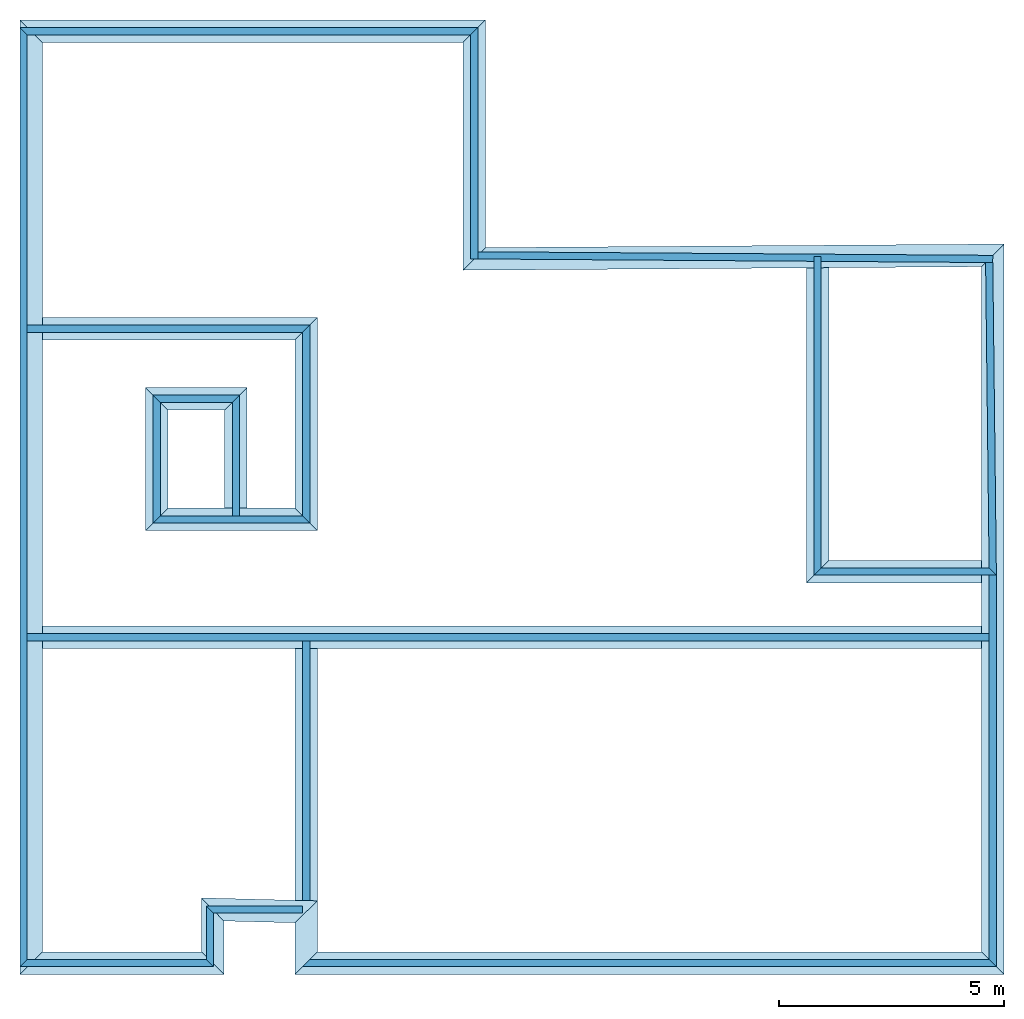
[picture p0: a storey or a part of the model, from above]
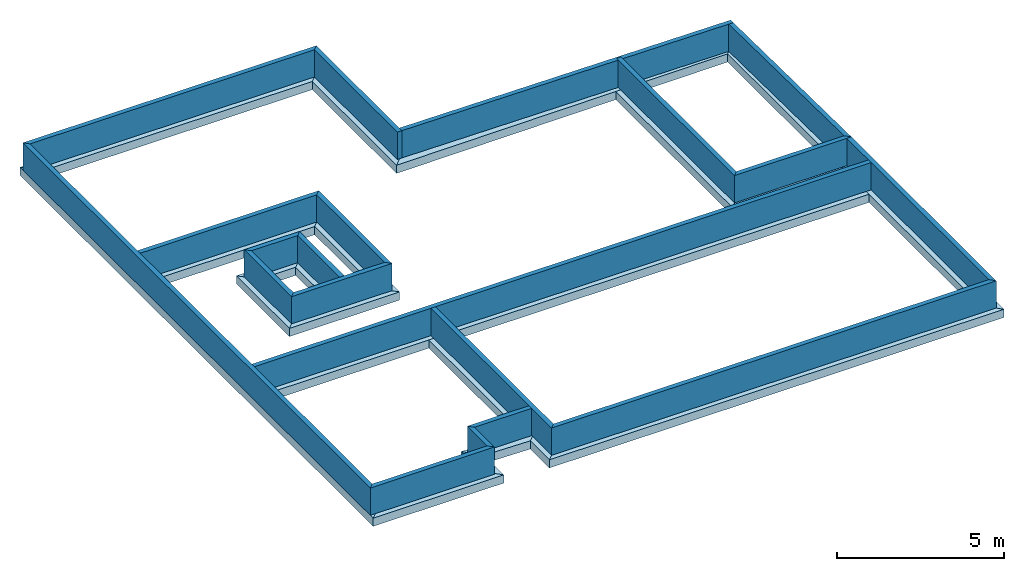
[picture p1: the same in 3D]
Properties of the parts of a building model (IFC2X3), part 1 of 6

# File
Description: ViewDefinition [CoordinationView_V2.0], Option [Drawing Scale: 100.000000], Option [Global Unique Identifiers (GUID): Keep existing], Option [Elements to export: Visible elements (on all stories)], Option [Partial Structure Display: Entire Model], Option [IFC Domain: All], Option [Structural Function: All Elements], Option [Convert Grid elements: On], Option [Convert IFC Annotations and ArchiCAD 2D elements: Off], Option [Convert 2D symbols of Doors and Windows: Off], Option [Explode Composite and Complex Profile elements into parts: Off], Option [Export geometries that Participates in Collision Detection only: Off], Option [Multi-skin complex geometries: Building element parts], Option [Elements in Solid Element Operations: Extruded/revolved], Option [Elements with junctions: Extruded/revolved without junctions], Option [Slabs with slanted edge(s): Extruded], Option [Use legacy geometric methods as in Coordination View 1.0: Off], Option [IFC Site Geometry: As boundary representation (BRep)], Option [Properties To Export: All properties], Option [Space containment: Off], Option [Bounding Box: Off], Option [Geometry to type objects: Off], Option [IFC base quantities (size, area and volume): Off], Option [All ArchiCAD BIM parameters: On], Option [IFC Space boundaries: Off], Option [ArchiCAD Zone Categories as IFC Space classification data: Off]
File name: J:\STATION DOCUMENTS\TB2E COMMI\SESSION 2016\T_Coulaures\GYMN LDV2007PCv5.ifc
Time: 2016-01-12T23:22:32
Author: Architect
Organization: Building Designer Office
Written by: PreProc - EDM 5.0
Made in: IFC file generated by Graphisoft ArchiCAD-64 19.0.0 FRA FULL Windows version (IFC2x3 add-on version: 4006 FRA FULL).
Authorization: The authorising person

# IfcSite, Site
RefLatitude: 48, 52, 0, 0; RefLongitude: 2, 20, 0, 0; RefElevation: 0 m

# IfcBuildingStorey (4)
In: Bâtiment
Name | Elevation (m)
FONDATIONS | -1.5
NIVEAU BAS GYMNASE | 0
NIVEAU HAUT ENTRÉE | 3
PLAN DE MASSE-TOITURE | 6.2

# IfcBeam: Hachure solide 2670559909 60 x 40, Pou-003
In: NIVEAU HAUT ENTRÉE
Material: Hachure solide 2670559909
Pset_BeamCommon - Reference: Hachure solide 2670559909 60 x 40
ArchiCADProperties - ID Elément entier: Pou-003; ID Elément compact: Pou-003; Etage d'implantation: NIVEAU HAUT ENTRÉE; Calque: Constr: Poutraison.Importation IFC; Type: Poutre; Verrouillé: no; Matériau de construction / Composite / Profil / Hachure: Hachure solide 2670559909; Fonction structurelle: Non défini; Position: Non défini; Classification d'élement: Type ArchiCAD; Etat de rénovation: Existant; Afficher sur filtre de rénovation: Tous les filtres appropriés; Type de structure: Basique; Surface supérieure: Menuiserie métal; Surface inférieure: Menuiserie métal; Surface gauche: Menuiserie métal; Surface droite: Menuiserie métal; Surface de fin: Menuiserie métal; Matériau de construction / Profil: Hachure solide 2670559909; Angle d'inclinaison de poutre: 27.0331 deg; Coupe transversale de poutre: Rectangulaire
AC_Pset_RenovationAndPhasing - Renovation Status: Existing
ArchiCADQuantities - Altitude à Zéro du Projet: 0.923819 m; Altitude à étage: -2.07618 m; Hauteur: 0.04 m; Superficie de surface: 1.24902 m2; Volume net: 0.0149235 m3; Superficie: 0.373088 m2; Longueur droite: 6.21814 m; Longueur gauche: 6.21814 m; Surface inférieure: 0.373088 m2; Surface supérieure: 0.373088 m2; Surface côté gauche: 0.248726 m2; Surface côté droit: 0.248726 m2; Volume: 0.0149235 m3; Surface de fin: 0.00538876 m2; Surface des trous: 0 m2; Surface des arêtes de trou: 0 m2; Nombre de trous: 0; Volume des trous: 0 m3; Largeur des trous: 0 m; Hauteur du trou: 0 m; Niveau du trou: 0 m; Largeur: 0.06 m; Décalage: 0 m; Volume conditionnel: 0.0149235 m3

# IfcBeam: Hachure solide 2670559909 700 x 300 (2)
Material: Hachure solide 2670559909
Pset_BeamCommon - Reference: Hachure solide 2670559909 700 x 300
ArchiCADProperties - ID Elément entier: Pou-002; ID Elément compact: Pou-002; Calque: Constr: Poutraison.Importation IFC; Type: Poutre; Verrouillé: no; Matériau de construction / Composite / Profil / Hachure: Hachure solide 2670559909; Fonction structurelle: Non défini; Position: Non défini; Classification d'élement: Type ArchiCAD; Etat de rénovation: Existant; Afficher sur filtre de rénovation: Tous les filtres appropriés; Type de structure: Basique; Surface supérieure: Surface-Stuc blanc; Surface inférieure: Surface-Stuc blanc; Surface gauche: Surface-Stuc blanc; Surface droite: Surface-Stuc blanc; Surface de fin: Surface-Stuc blanc; Matériau de construction / Profil: Hachure solide 2670559909; Angle d'inclinaison de poutre: 0 deg; Coupe transversale de poutre: Rectangulaire
AC_Pset_RenovationAndPhasing - Renovation Status: Existing
ArchiCADQuantities - Hauteur: 0.3 m; Superficie de surface: 35.06 m2; Volume net: 3.6372 m3; Superficie: 12.124 m2; Longueur droite: 17.32 m; Longueur gauche: 17.32 m; Surface inférieure: 12.124 m2; Surface supérieure: 12.124 m2; Surface côté gauche: 5.196 m2; Surface côté droit: 5.196 m2; Volume: 3.6372 m3; Surface de fin: 0.42 m2; Surface des trous: 0 m2; Surface des arêtes de trou: 0 m2; Nombre de trous: 0; Volume des trous: 0 m3; Largeur des trous: 0 m; Hauteur du trou: 0 m; Niveau du trou: 0 m; Largeur: 0.7 m; Décalage: 0 m; Volume conditionnel: 3.6372 m3
Name | In | Etage d'implantation | Altitude à Zéro du Projet (m) | Altitude à étage (m)
Pou-002 | NIVEAU BAS GYMNASE | NIVEAU BAS GYMNASE | 2.75 | 2.75
Pou-002 | PLAN DE MASSE-TOITURE | PLAN DE MASSE-TOITURE | 6.5 | 0.3

# IfcBeam: Pente double 10 (7)
In: NIVEAU BAS GYMNASE
Material: Sans Trame
ArchiCADProperties - ID Elément entier: MOB-0004; ID Elément compact: MOB-0004; Etage d'implantation: NIVEAU BAS GYMNASE; Calque: Cotat: 1/100.Importation IFC; Type: Objet; Verrouillé: no; Nom Elément de Bibliothèque: Poutre 1; Matériau de construction / Composite / Profil / Hachure: Sans Trame; Fonction structurelle: Non défini; Position: Non défini; Classification d'élement: Type ArchiCAD; Etat de rénovation: Existant; Afficher sur filtre de rénovation: Tous les filtres appropriés; Angle de rotation: 90 deg; Surface: Enduit - Blanc nature
AC_Pset_Poutre_1 - Type Hachure: Sans Trame; Stylo Hachure: Fond - Couleur 1; Stylo fond hachure: Fond - Couleur 1; Coût: 0; Type de groupe (FM_Type): Autres; Type de groupe (iFMType): 25; Poids de l'objet: 0; Unité poids de l'objet: kg; Stylo de contour: Eléments 2D - Général; Surface par défaut: Enduit - Blanc nature; Surface 1: Bois-Lambris foncé; Afficher arêtes de contour seulement en 3D: yes
AC_Pset_RenovationAndPhasing - Renovation Status: Existing
ArchiCADQuantities - Altitude à Zéro du Projet: 0 m; Altitude à étage: 0 m; Superficie de surface: 82.9834 m2; Volume net: 1.00818 m3; Superficie: 4.852 m2; Hauteur (Taille en Z): 8.38065 m; Longueur (A): 24.26 m; Volume: 1.00818 m3; Largeur (B): 0.2 m
Name | Nom de Zone | Numéro de Zone
6 x MOB-0004 | Grande Salle de Jeux | 010
MOB-0004

# IfcBuildingElementProxy: Banc public 04 10 (24)
In: NIVEAU BAS GYMNASE
Material: AS_EMPTY
ArchiCADProperties - ID Elément entier: Obj.-025; ID Elément compact: Obj.-025; Etage d'implantation: NIVEAU BAS GYMNASE; Numéro de Zone: 010; Calque: •Arbres.Importation IFC; Type: Objet; Verrouillé: no; Matériau de construction / Composite / Profil / Hachure: AS_EMPTY; Fonction structurelle: Non défini; Position: Non défini; Classification d'élement: Type ArchiCAD; Etat de rénovation: Existant; Afficher sur filtre de rénovation: Tous les filtres appropriés; Surface: Enduit - Blanc nature
AC_Pset_RenovationAndPhasing - Renovation Status: Existing
ArchiCADQuantities - Altitude à Zéro du Projet: 0 m; Altitude à étage: 0 m; Hauteur (Taille en Z): 0.39 m
Name | Nom de Zone | Nom Elément de Bibliothèque | Angle de rotation (deg) | Superficie de surface (m2) | Volume net (m3) = Volume (m3) | Superficie (m2) | Longueur (A) (m) | Largeur (B) (m)
2 x Obj.-025 | Sanit Vest 4 | Elément Modèle 1 | -90 | 3.3602 | 0.0680893 | 0.930667 | 2.32667 | 0.4 | AC_Pset_Elément_Modèle_1 - Type Hachure: Sans Trame; Stylo Hachure: Fond - Couleur 1; Stylo fond hachure: Fond - Couleur 1; Stylo de contour: Eléments 2D - Général; Surface par défaut: Enduit - Blanc nature; Surface 1: Peinture-01; Surface 2: Bois-Pin horizontal; Afficher arêtes de contour seulement en 3D: yes
Obj.-025 | Sanit Vest 4 | Elément Modèle 3 | -90 | 3.2522 | 0.0666973 | 0.882667 | 2.20667 | 0.4 | AC_Pset_Elément_Modèle_3 - Type Hachure: Sans Trame; Stylo Hachure: Fond - Couleur 1; Stylo fond hachure: Fond - Couleur 1; Stylo de contour: Eléments 2D - Général; Surface par défaut: Enduit - Blanc nature; Surface 1: Peinture-01; Surface 2: Bois-Pin horizontal; Afficher arêtes de contour seulement en 3D: yes
3 x Obj.-025 | Sanit Vest 1 | Elément Modèle 4 | 90 | 3.3602 | 0.0680893 | 0.930667 | 2.32667 | 0.4 | AC_Pset_Elément_Modèle_4 - Type Hachure: Sans Trame; Stylo Hachure: Fond - Couleur 1; Stylo fond hachure: Fond - Couleur 1; Stylo de contour: Eléments 2D - Général; Surface par défaut: Enduit - Blanc nature; Surface 1: Peinture-01; Surface 2: Bois-Pin horizontal; Afficher arêtes de contour seulement en 3D: yes
Obj.-025 | Sanit Vest 1 | Elément Modèle 5 | 180 | 4.14599 | 0.0782173 | 1.27991 | 3.19977 | 0.4 | AC_Pset_Elément_Modèle_5 - Type Hachure: Sans Trame; Stylo Hachure: Fond - Couleur 1; Stylo fond hachure: Fond - Couleur 1; Stylo de contour: Eléments 2D - Général; Surface par défaut: Enduit - Blanc nature; Surface 1: Peinture-01; Surface 2: Bois-Pin horizontal; Afficher arêtes de contour seulement en 3D: yes
3 x Obj.-025 | Sanit Vest 2 | Elément Modèle 1 | -90 | 3.3602 | 0.0680893 | 0.930667 | 2.32667 | 0.4 | AC_Pset_Elément_Modèle_1 - Type Hachure: Sans Trame; Stylo Hachure: Fond - Couleur 1; Stylo fond hachure: Fond - Couleur 1; Stylo de contour: Eléments 2D - Général; Surface par défaut: Enduit - Blanc nature; Surface 1: Peinture-01; Surface 2: Bois-Pin horizontal; Afficher arêtes de contour seulement en 3D: yes
Obj.-025 | Sanit Vest 2 | Elément Modèle 6 | 180 | 4.14599 | 0.0782173 | 1.27991 | 3.19977 | 0.4 | AC_Pset_Elément_Modèle_6 - Type Hachure: Sans Trame; Stylo Hachure: Fond - Couleur 1; Stylo fond hachure: Fond - Couleur 1; Stylo de contour: Eléments 2D - Général; Surface par défaut: Enduit - Blanc nature; Surface 1: Peinture-01; Surface 2: Bois-Pin horizontal; Afficher arêtes de contour seulement en 3D: yes
3 x Obj.-025 | Sanit Vest 3 | Elément Modèle 4 | 90 | 3.3602 | 0.0680893 | 0.930667 | 2.32667 | 0.4 | AC_Pset_Elément_Modèle_4 - Type Hachure: Sans Trame; Stylo Hachure: Fond - Couleur 1; Stylo fond hachure: Fond - Couleur 1; Stylo de contour: Eléments 2D - Général; Surface par défaut: Enduit - Blanc nature; Surface 1: Peinture-01; Surface 2: Bois-Pin horizontal; Afficher arêtes de contour seulement en 3D: yes
Obj.-025 | Sanit Vest 3 | Elément Modèle 5 | 180 | 4.14599 | 0.0782173 | 1.27991 | 3.19977 | 0.4 | AC_Pset_Elément_Modèle_5 - Type Hachure: Sans Trame; Stylo Hachure: Fond - Couleur 1; Stylo fond hachure: Fond - Couleur 1; Stylo de contour: Eléments 2D - Général; Surface par défaut: Enduit - Blanc nature; Surface 1: Peinture-01; Surface 2: Bois-Pin horizontal; Afficher arêtes de contour seulement en 3D: yes
2 x Obj.-025 | Sanit Vest 5 | Elément Modèle 7 | 90 | 3.6512 | 0.07184 | 1.06 | 2.65 | 0.4 | AC_Pset_Elément_Modèle_7 - Type Hachure: Sans Trame; Stylo Hachure: Fond - Couleur 1; Stylo fond hachure: Fond - Couleur 1; Stylo de contour: Eléments 2D - Général; Surface par défaut: Enduit - Blanc nature; Surface 1: Peinture-01; Surface 2: Bois-Pin horizontal; Afficher arêtes de contour seulement en 3D: yes
2 x Obj.-025 | Sanit Vest 6 | Elément Modèle 8 | -90 | 3.6512 | 0.07184 | 1.06 | 2.65 | 0.4 | AC_Pset_Elément_Modèle_8 - Type Hachure: Sans Trame; Stylo Hachure: Fond - Couleur 1; Stylo fond hachure: Fond - Couleur 1; Stylo de contour: Eléments 2D - Général; Surface par défaut: Enduit - Blanc nature; Surface 1: Peinture-01; Surface 2: Bois-Pin horizontal; Afficher arêtes de contour seulement en 3D: yes
Obj.-025 | Sanit Vest 5 | Elément Modèle 7 | 180 | 3.6512 | 0.07184 | 1.06 | 2.65 | 0.4 | AC_Pset_Elément_Modèle_7 - Type Hachure: Sans Trame; Stylo Hachure: Fond - Couleur 1; Stylo fond hachure: Fond - Couleur 1; Stylo de contour: Eléments 2D - Général; Surface par défaut: Enduit - Blanc nature; Surface 1: Peinture-01; Surface 2: Bois-Pin horizontal; Afficher arêtes de contour seulement en 3D: yes
Obj.-025 | Sanit Vest 6 | Elément Modèle 7 | 180 | 3.6512 | 0.07184 | 1.06 | 2.65 | 0.4 | AC_Pset_Elément_Modèle_7 - Type Hachure: Sans Trame; Stylo Hachure: Fond - Couleur 1; Stylo fond hachure: Fond - Couleur 1; Stylo de contour: Eléments 2D - Général; Surface par défaut: Enduit - Blanc nature; Surface 1: Peinture-01; Surface 2: Bois-Pin horizontal; Afficher arêtes de contour seulement en 3D: yes
Obj.-025 | Sanit Vest 4 | Elément Modèle 10 | 180 | 4.40922 | 0.0834246 | 1.38394 | 3.32727 | 0.415939 | AC_Pset_Elément_Modèle_10 - Type Hachure: Sans Trame; Stylo Hachure: Fond - Couleur 1; Stylo fond hachure: Fond - Couleur 1; Stylo de contour: Eléments 2D - Général; Surface par défaut: Enduit - Blanc nature; Surface 1: Peinture-01; Surface 2: Bois-Pin horizontal; Afficher arêtes de contour seulement en 3D: yes
Obj.-025 | Sanit Prof H | Elément Modèle 13 | -90 | 1.5602 | 0.0371 | 0.24 | 0.8 | 0.3 | AC_Pset_Elément_Modèle_13 - Type Hachure: Sans Trame; Stylo Hachure: Fond - Couleur 1; Stylo fond hachure: Fond - Couleur 1; Stylo de contour: Eléments 2D - Général; Surface par défaut: Enduit - Blanc nature; Surface 1: Peinture-01; Surface 2: Bois-Pin horizontal; Afficher arêtes de contour seulement en 3D: yes
Obj.-025 | Sanit Prof F | Elément Modèle 14 | 90 | 1.5602 | 0.0371 | 0.24 | 0.8 | 0.3 | AC_Pset_Elément_Modèle_14 - Type Hachure: Sans Trame; Stylo Hachure: Fond - Couleur 1; Stylo fond hachure: Fond - Couleur 1; Stylo de contour: Eléments 2D - Général; Surface par défaut: Enduit - Blanc nature; Surface 1: Peinture-01; Surface 2: Bois-Pin horizontal; Afficher arêtes de contour seulement en 3D: yes

# IfcBuildingElementProxy: Terrain de handball 10, Obj.-016
In: NIVEAU BAS GYMNASE
Material: AS_EMPTY
ArchiCADProperties - ID Elément entier: Obj.-016; ID Elément compact: Obj.-016; Etage d'implantation: NIVEAU BAS GYMNASE; Nom de Zone: Grande Salle de Jeux; Numéro de Zone: 010; Calque: Calque ArchiCAD.Importation IFC; Type: Objet; Verrouillé: no; Nom Elément de Bibliothèque: Elément Modèle 12; Matériau de construction / Composite / Profil / Hachure: AS_EMPTY; Fonction structurelle: Non défini; Position: Non défini; Classification d'élement: Type ArchiCAD; Etat de rénovation: Existant; Afficher sur filtre de rénovation: Tous les filtres appropriés; Angle de rotation: -90 deg; Surface: Enduit - Blanc nature
AC_Pset_Elément_Modèle_12 - Type Hachure: Sans Trame; Stylo Hachure: Fond - Couleur 1; Stylo fond hachure: Fond - Couleur 1; Stylo de contour: Eléments 2D - Général; Surface par défaut: Enduit - Blanc nature; Surface 1: Peinture-21; Surface 2: Surface-Blanc; Surface 3: Peinture-14; Surface 4: Métal-Chaîne clôture; Afficher arêtes de contour seulement en 3D: yes
AC_Pset_RenovationAndPhasing - Renovation Status: Existing
ArchiCADQuantities - Altitude à Zéro du Projet: 0.015 m; Altitude à étage: 0.015 m; Superficie de surface: 1847.91 m2; Volume net: 160.152 m3; Superficie: 836.8 m2; Hauteur (Taille en Z): 2.28 m; Longueur (A): 20 m; Volume: 160.152 m3; Largeur (B): 41.84 m

# IfcBuildingElementProxy: Terrain de volley 10 (3)
In: NIVEAU BAS GYMNASE
Material: AS_EMPTY
ArchiCADProperties - ID Elément entier: Obj.-016; ID Elément compact: Obj.-016; Etage d'implantation: NIVEAU BAS GYMNASE; Nom de Zone: Grande Salle de Jeux; Numéro de Zone: 010; Calque: Calque ArchiCAD.Importation IFC; Type: Objet; Verrouillé: no; Nom Elément de Bibliothèque: Elément Modèle 11; Matériau de construction / Composite / Profil / Hachure: AS_EMPTY; Fonction structurelle: Non défini; Position: Non défini; Classification d'élement: Type ArchiCAD; Etat de rénovation: Existant; Afficher sur filtre de rénovation: Tous les filtres appropriés; Angle de rotation: 0 deg; Surface: Enduit - Blanc nature
AC_Pset_Elément_Modèle_11 - Type Hachure: Sans Trame; Stylo Hachure: Fond - Couleur 1; Stylo fond hachure: Fond - Couleur 1; Stylo de contour: Eléments 2D - Général; Surface par défaut: Enduit - Blanc nature; Surface 1: Peinture-08; Surface 2: Surface-Blanc; Surface 3: Peinture-14; Surface 4: Métal-Inox; Surface 5: Métal-Chaîne clôture; Afficher arêtes de contour seulement en 3D: yes
AC_Pset_RenovationAndPhasing - Renovation Status: Existing
ArchiCADQuantities - Altitude à Zéro du Projet: 0.015 m; Altitude à étage: 0.015 m; Superficie de surface: 349.499 m2; Volume net: 4.18376 m3; Superficie: 203.625 m2; Hauteur (Taille en Z): 3.24167 m; Longueur (A): 10.922 m; Volume: 4.18376 m3; Largeur (B): 18.6436 m

# IfcBuildingElementProxy: Texte_3D_OD (2)
Material: Sans Trame
ArchiCADProperties - ID Elément entier: MOB-0004; ID Elément compact: MOB-0004; Calque: Cotat: 1/100.Importation IFC; Type: Objet; Verrouillé: no; Matériau de construction / Composite / Profil / Hachure: Sans Trame; Fonction structurelle: Non défini; Position: Non défini; Classification d'élement: Type ArchiCAD; Etat de rénovation: Existant; Afficher sur filtre de rénovation: Tous les filtres appropriés; Surface: Enduit - Blanc nature
AC_Pset_RenovationAndPhasing - Renovation Status: Existing
Name | In | Etage d'implantation | Nom Elément de Bibliothèque | Angle de rotation (deg) | Altitude à Zéro du Projet (m) | Altitude à étage (m) | Superficie de surface (m2) | Volume net (m3) = Volume (m3) | Superficie (m2) | Hauteur (Taille en Z) (m) | Longueur (A) (m) | Largeur (B) (m)
MOB-0004 | NIVEAU BAS GYMNASE | NIVEAU BAS GYMNASE | Elément Modèle 9 | 0 | 1.6 | 1.6 | 0.472826 | 0.00186074 | 0.15564 | 0.142176 | 10.376 | 0.015 | AC_Pset_Elément_Modèle_9 - Type Hachure: Sans Trame; Stylo Hachure: Fond - Couleur 1; Stylo fond hachure: Fond - Couleur 1; Stylo de contour: Eléments 2D - Général; Surface par défaut: Enduit - Blanc nature; Surface 1: Métal-Nickel; Afficher arêtes de contour seulement en 3D: yes
MOB-0004 | NIVEAU HAUT ENTRÉE | NIVEAU HAUT ENTRÉE | Elément Modèle 21 | 90 | 7.77443 | 4.77443 | 1.11299 | 0.00467516 | 0.00456994 | 3.02019 | 0.456994 | 0.01 | AC_Pset_Elément_Modèle_21 - Type Hachure: Sans Trame; Stylo Hachure: Fond - Couleur 1; Stylo fond hachure: Fond - Couleur 1; Stylo de contour: Eléments 2D - Général; Surface par défaut: Enduit - Blanc nature; Surface 1: Métal-Nickel; Afficher arêtes de contour seulement en 3D: yes

# IfcBuildingElementProxy: gypse_droit_lisses_rempl, MOB-0003
In: NIVEAU HAUT ENTRÉE
Material: Sans Trame
ArchiCADProperties - ID Elément entier: MOB-0003; ID Elément compact: MOB-0003; Etage d'implantation: NIVEAU HAUT ENTRÉE; Calque: Cotat: 1/100.Importation IFC; Type: Objet; Verrouillé: no; Nom Elément de Bibliothèque: Elément Modèle 16; Matériau de construction / Composite / Profil / Hachure: Sans Trame; Fonction structurelle: Non défini; Position: Non défini; Classification d'élement: Type ArchiCAD; Etat de rénovation: Existant; Afficher sur filtre de rénovation: Tous les filtres appropriés; Angle de rotation: 0 deg; Surface: Enduit - Blanc nature
AC_Pset_Elément_Modèle_16 - Type Hachure: Sans Trame; Stylo Hachure: Fond - Couleur 1; Stylo fond hachure: Fond - Couleur 1; Stylo de contour: Eléments 2D - Général; Surface par défaut: Enduit - Blanc nature; Surface 1: RAL 7035 Gris clair; Surface 2: gypse_gasket; Surface 3: Vitrage-Clair; Afficher arêtes de contour seulement en 3D: yes
AC_Pset_RenovationAndPhasing - Renovation Status: Existing
ArchiCADQuantities - Altitude à Zéro du Projet: 3.01 m; Altitude à étage: 0.01 m; Superficie de surface: 2.75879 m2; Volume net: 0.0103288 m3; Superficie: 0.317148 m2; Hauteur (Taille en Z): 1.1511 m; Longueur (A): 1.38766 m; Volume: 0.0103288 m3; Largeur (B): 0.228548 m

# IfcBuildingElementProxy: gypse_ramp_lisses_tigeinox, MOB-0003
In: NIVEAU HAUT ENTRÉE
Material: Sans Trame
ArchiCADProperties - ID Elément entier: MOB-0003; ID Elément compact: MOB-0003; Etage d'implantation: NIVEAU HAUT ENTRÉE; Nom de Zone: Salle de Sport de Combat; Numéro de Zone: 006; Calque: Cotat: 1/100.Importation IFC; Type: Objet; Verrouillé: no; Nom Elément de Bibliothèque: Elément Modèle 20; Matériau de construction / Composite / Profil / Hachure: Sans Trame; Fonction structurelle: Non défini; Position: Non défini; Classification d'élement: Type ArchiCAD; Etat de rénovation: Existant; Afficher sur filtre de rénovation: Tous les filtres appropriés; Angle de rotation: 180 deg; Surface: Enduit - Blanc nature
AC_Pset_Elément_Modèle_20 - Type Hachure: Sans Trame; Stylo Hachure: Fond - Couleur 1; Stylo fond hachure: Fond - Couleur 1; Stylo de contour: Eléments 2D - Général; Surface par défaut: Enduit - Blanc nature; Surface 1: RAL 7035 Gris clair; Afficher arêtes de contour seulement en 3D: yes
AC_Pset_RenovationAndPhasing - Renovation Status: Existing
ArchiCADQuantities - Altitude à Zéro du Projet: 3 m; Altitude à étage: 0 m; Superficie de surface: 3.69626 m2; Volume net: 0.0146362 m3; Superficie: 0.4284 m2; Hauteur (Taille en Z): 0.999371 m; Longueur (A): 3.57 m; Volume: 0.0146362 m3; Largeur (B): 0.12 m

# IfcColumn: Béton 2199952591 300 x 700, Pilier-001
In: NIVEAU BAS GYMNASE
Material: Béton 2199952591
Pset_ColumnCommon - Reference: Béton 2199952591 300 x 700
ArchiCADProperties - ID Elément entier: Pilier-001; ID Elément compact: Pilier-001; Etage d'implantation: NIVEAU BAS GYMNASE; Calque: Constr: Poteaux.Importation IFC; Type: Poteau; Verrouillé: no; Matériau de construction / Composite / Profil / Hachure: Béton 2199952591; Fonction structurelle: Non défini; Position: Non défini; Classification d'élement: Type ArchiCAD; Etat de rénovation: Existant; Afficher sur filtre de rénovation: Tous les filtres appropriés; Type de structure: Basique; Matériau de construction / Profil: Béton 2199952591; Surface: Surface-Stuc blanc; Angle d'inclinaison de poteau: 90 deg; Coupe transversale de poteau: Rectangulaire; Etage supérieur lié: Non lié
AC_Pset_RenovationAndPhasing - Renovation Status: Existing
ArchiCADQuantities - Altitude à Zéro du Projet: 2.45 m; Altitude à étage: 2.45 m; Hauteur: 4.05 m; Superficie de surface: 8.1 m2; Volume net: 0.8505 m3; Superficie: 0.21 m2; Surface nette de l'âme (sans haut/bas): 8.1 m2; Surface du revêtement: 0 m2; Volume net de l'Ame: 0.8505 m3; Volume net du revêtement: 0 m3; Dimensions Ame: 0.7 m; 2ème dimension âme: 0.3 m; Hauteur minimum du Poteau: 4.05 m; Hauteur maximum Poteau: 4.05 m; Périmètre du Poteau: 2 m; Surface du Poteau: 0.21 m2; Volume du Poteau: 0.8505 m3; Volume brut du Poteau: 0.8505 m3; Surface brute de l'âme (sans haut/bas): 8.1 m2; Volume brut de l'Ame: 0.8505 m3; Surface brute du revêtement (sans haut/bas): 0 m2; Volume brut du revêtement: 0 m3; Surface nette du haut de l'Ame: 0.21 m2; Surface nette du bas de l'Ame: 0.21 m2; Surface nette du haut du Revêtement: 0 m2; Surface nette du bas du Revêtement: 0 m2; Surface brute du haut (ou bas) de l'âme: 0.21 m2; Surface brute du haut (ou bas) du revêtement: 0 m2; Décalage étage d'implantation: 2.45 m; Décalage supérieur: -0.3 m

# IfcColumn: Empty Fill 1720032642 30 x 40 (6)
In: NIVEAU HAUT ENTRÉE
Material: Empty Fill 1720032642
Pset_ColumnCommon - Reference: Empty Fill 1720032642 30 x 40
ArchiCADProperties - ID Elément entier: Pilier-002; ID Elément compact: Pilier-002; Etage d'implantation: NIVEAU HAUT ENTRÉE; Calque: Constr: Poteaux.Importation IFC; Type: Poteau; Verrouillé: no; Matériau de construction / Composite / Profil / Hachure: Empty Fill 1720032642; Fonction structurelle: Non défini; Position: Non défini; Classification d'élement: Type ArchiCAD; Etat de rénovation: Existant; Afficher sur filtre de rénovation: Tous les filtres appropriés; Type de structure: Basique; Matériau de construction / Profil: Empty Fill 1720032642; Surface: Agave 5 OD; Angle d'inclinaison de poteau: 90 deg; Coupe transversale de poteau: Rectangulaire; Etage supérieur lié: Non lié
AC_Pset_RenovationAndPhasing - Renovation Status: Existing
ArchiCADQuantities - Altitude à Zéro du Projet: 2.75 m; Altitude à étage: -0.25 m; Hauteur: 3.45 m; Superficie de surface: 0.483 m2; Volume net: 0.00414 m3; Superficie: 0.0012 m2; Surface nette de l'âme (sans haut/bas): 0.483 m2; Surface du revêtement: 0 m2; Volume net de l'Ame: 0.00414 m3; Volume net du revêtement: 0 m3; Dimensions Ame: 0.04 m; 2ème dimension âme: 0.03 m; Hauteur minimum du Poteau: 3.45 m; Hauteur maximum Poteau: 3.45 m; Périmètre du Poteau: 0.14 m; Surface du Poteau: 0.0012 m2; Volume du Poteau: 0.00414 m3; Volume brut du Poteau: 0.00414 m3; Surface brute de l'âme (sans haut/bas): 0.483 m2; Volume brut de l'Ame: 0.00414 m3; Surface brute du revêtement (sans haut/bas): 0 m2; Volume brut du revêtement: 0 m3; Surface nette du haut de l'Ame: 0.0012 m2; Surface nette du bas de l'Ame: 0.0012 m2; Surface nette du haut du Revêtement: 0 m2; Surface nette du bas du Revêtement: 0 m2; Surface brute du haut (ou bas) de l'âme: 0.0012 m2; Surface brute du haut (ou bas) du revêtement: 0 m2; Décalage étage d'implantation: -0.25 m; Décalage supérieur: -0.3 m

# IfcColumn: Hachure solide (2) 1078492233 250 x 900, Pilier-001
In: NIVEAU BAS GYMNASE
Material: Hachure solide (2) 1078492233
Pset_ColumnCommon - Reference: Hachure solide (2) 1078492233 250 x 900
ArchiCADProperties - ID Elément entier: Pilier-001; ID Elément compact: Pilier-001; Etage d'implantation: NIVEAU BAS GYMNASE; Calque: Constr: Poteaux.Importation IFC; Type: Poteau; Verrouillé: no; Matériau de construction / Composite / Profil / Hachure: Hachure solide (2) 1078492233; Fonction structurelle: Non défini; Position: Non défini; Classification d'élement: Type ArchiCAD; Etat de rénovation: Existant; Afficher sur filtre de rénovation: Tous les filtres appropriés; Type de structure: Basique; Matériau de construction / Profil: Hachure solide (2) 1078492233; Surface: Pierre-Granite rouge; Angle d'inclinaison de poteau: 90 deg; Coupe transversale de poteau: Rectangulaire; Etage supérieur lié: Non lié
AC_Pset_RenovationAndPhasing - Renovation Status: Existing
ArchiCADQuantities - Altitude à Zéro du Projet: 2.75 m; Altitude à étage: 2.75 m; Hauteur: 6.63885 m; Superficie de surface: 15.2694 m2; Volume net: 1.49374 m3; Superficie: 0.225 m2; Surface nette de l'âme (sans haut/bas): 15.2694 m2; Surface du revêtement: 0 m2; Volume net de l'Ame: 1.49374 m3; Volume net du revêtement: 0 m3; Dimensions Ame: 0.9 m; 2ème dimension âme: 0.25 m; Hauteur minimum du Poteau: 6.63885 m; Hauteur maximum Poteau: 6.63885 m; Périmètre du Poteau: 2.3 m; Surface du Poteau: 0.225 m2; Volume du Poteau: 1.49374 m3; Volume brut du Poteau: 1.49374 m3; Surface brute de l'âme (sans haut/bas): 15.2694 m2; Volume brut de l'Ame: 1.49374 m3; Surface brute du revêtement (sans haut/bas): 0 m2; Volume brut du revêtement: 0 m3; Surface nette du haut de l'Ame: 0.225 m2; Surface nette du bas de l'Ame: 0.225 m2; Surface nette du haut du Revêtement: 0 m2; Surface nette du bas du Revêtement: 0 m2; Surface brute du haut (ou bas) de l'âme: 0.225 m2; Surface brute du haut (ou bas) du revêtement: 0 m2; Décalage étage d'implantation: 2.75 m; Décalage supérieur: -0.3 m

# IfcColumn: Hachure solide (2) 2212012751 300 x 870, Pilier-001
In: NIVEAU BAS GYMNASE
Material: Hachure solide (2) 2212012751
Pset_ColumnCommon - Reference: Hachure solide (2) 2212012751 300 x 870
ArchiCADProperties - ID Elément entier: Pilier-001; ID Elément compact: Pilier-001; Etage d'implantation: NIVEAU BAS GYMNASE; Calque: Constr: Poteaux.Importation IFC; Type: Poteau; Verrouillé: no; Matériau de construction / Composite / Profil / Hachure: Hachure solide (2) 2212012751; Fonction structurelle: Non défini; Position: Non défini; Classification d'élement: Type ArchiCAD; Etat de rénovation: Existant; Afficher sur filtre de rénovation: Tous les filtres appropriés; Type de structure: Basique; Matériau de construction / Profil: Hachure solide (2) 2212012751; Surface: Surface-Stuc blanc; Angle d'inclinaison de poteau: 90 deg; Coupe transversale de poteau: Rectangulaire; Etage supérieur lié: Non lié
AC_Pset_RenovationAndPhasing - Renovation Status: Existing
ArchiCADQuantities - Altitude à Zéro du Projet: 2.75 m; Altitude à étage: 2.75 m; Hauteur: 4.55 m; Superficie de surface: 10.647 m2; Volume net: 1.18755 m3; Superficie: 0.261 m2; Surface nette de l'âme (sans haut/bas): 10.647 m2; Surface du revêtement: 0 m2; Volume net de l'Ame: 1.18755 m3; Volume net du revêtement: 0 m3; Dimensions Ame: 0.87 m; 2ème dimension âme: 0.3 m; Hauteur minimum du Poteau: 4.55 m; Hauteur maximum Poteau: 4.55 m; Périmètre du Poteau: 2.34 m; Surface du Poteau: 0.261 m2; Volume du Poteau: 1.18755 m3; Volume brut du Poteau: 1.18755 m3; Surface brute de l'âme (sans haut/bas): 10.647 m2; Volume brut de l'Ame: 1.18755 m3; Surface brute du revêtement (sans haut/bas): 0 m2; Volume brut du revêtement: 0 m3; Surface nette du haut de l'Ame: 0.261 m2; Surface nette du bas de l'Ame: 0.261 m2; Surface nette du haut du Revêtement: 0 m2; Surface nette du bas du Revêtement: 0 m2; Surface brute du haut (ou bas) de l'âme: 0.261 m2; Surface brute du haut (ou bas) du revêtement: 0 m2; Décalage étage d'implantation: 2.75 m; Décalage supérieur: -0.3 m

# IfcColumn: Hachure solide (2) 2212012855 300 x 2400, Pilier-001
In: NIVEAU BAS GYMNASE
Material: Hachure solide (2) 2212012855
Pset_ColumnCommon - Reference: Hachure solide (2) 2212012855 300 x 2400
ArchiCADProperties - ID Elément entier: Pilier-001; ID Elément compact: Pilier-001; Etage d'implantation: NIVEAU BAS GYMNASE; Calque: Constr: Poteaux.Importation IFC; Type: Poteau; Verrouillé: no; Matériau de construction / Composite / Profil / Hachure: Hachure solide (2) 2212012855; Fonction structurelle: Non défini; Position: Non défini; Classification d'élement: Type ArchiCAD; Etat de rénovation: Existant; Afficher sur filtre de rénovation: Tous les filtres appropriés; Type de structure: Basique; Matériau de construction / Profil: Hachure solide (2) 2212012855; Surface: Surface-Stuc blanc; Angle d'inclinaison de poteau: 90 deg; Coupe transversale de poteau: Rectangulaire; Etage supérieur lié: Non lié
AC_Pset_RenovationAndPhasing - Renovation Status: Existing
ArchiCADQuantities - Altitude à Zéro du Projet: 2.85 m; Altitude à étage: 2.85 m; Hauteur: 4.45 m; Superficie de surface: 24.03 m2; Volume net: 3.204 m3; Superficie: 0.72 m2; Surface nette de l'âme (sans haut/bas): 24.03 m2; Surface du revêtement: 0 m2; Volume net de l'Ame: 3.204 m3; Volume net du revêtement: 0 m3; Dimensions Ame: 2.4 m; 2ème dimension âme: 0.3 m; Hauteur minimum du Poteau: 4.45 m; Hauteur maximum Poteau: 4.45 m; Périmètre du Poteau: 5.4 m; Surface du Poteau: 0.72 m2; Volume du Poteau: 3.204 m3; Volume brut du Poteau: 3.204 m3; Surface brute de l'âme (sans haut/bas): 24.03 m2; Volume brut de l'Ame: 3.204 m3; Surface brute du revêtement (sans haut/bas): 0 m2; Volume brut du revêtement: 0 m3; Surface nette du haut de l'Ame: 0.72 m2; Surface nette du bas de l'Ame: 0.72 m2; Surface nette du haut du Revêtement: 0 m2; Surface nette du bas du Revêtement: 0 m2; Surface brute du haut (ou bas) de l'âme: 0.72 m2; Surface brute du haut (ou bas) du revêtement: 0 m2; Décalage étage d'implantation: 2.85 m; Décalage supérieur: -0.3 m

# IfcCurtainWall: Mur rid droit 10 (3)
In: NIVEAU HAUT ENTRÉE
Material: Sans Trame
ArchiCADProperties - ID Elément entier: MOB-0002; ID Elément compact: MOB-0002; Etage d'implantation: NIVEAU HAUT ENTRÉE; Calque: Cotat: 1/100.Importation IFC; Type: Objet; Verrouillé: no; Matériau de construction / Composite / Profil / Hachure: Sans Trame; Fonction structurelle: Non défini; Position: Non défini; Classification d'élement: Type ArchiCAD; Etat de rénovation: Existant; Afficher sur filtre de rénovation: Tous les filtres appropriés; Surface: Enduit - Blanc nature
AC_Pset_RenovationAndPhasing - Renovation Status: Existing
ArchiCADQuantities - Altitude à Zéro du Projet: 2.6 m; Altitude à étage: -0.4 m; Hauteur (Taille en Z): 6.3 m; Largeur (B): 0.16 m
Name | Nom Elément de Bibliothèque | Angle de rotation (deg) | Superficie de surface (m2) | Volume net (m3) = Volume (m3) | Superficie (m2) | Longueur (A) (m)
MOB-0002 | Mur Rideau 1 | 0 | 877.641 | 45.4102 | 7.20797 | 45.0498 | AC_Pset_Mur_Rideau_1 - Type Hachure: Sans Trame; Stylo Hachure: Fond - Couleur 1; Stylo fond hachure: Fond - Couleur 1; Coût: 0; Type de groupe (FM_Type): Autres; Type de groupe (iFMType): 25; Poids de l'objet: 0; Unité poids de l'objet: kg; Stylo de contour: Eléments 2D - Général; Surface par défaut: Enduit - Blanc nature; Surface 1: Carrelage Piscine; Surface 2: RAL 6021 Vert pâle2; Afficher arêtes de contour seulement en 3D: yes
MOB-0002 | Mur Rideau 2 | 90 | 373.556 | 19.2153 | 3.05005 | 19.0628 | AC_Pset_Mur_Rideau_2 - Type Hachure: Sans Trame; Stylo Hachure: Fond - Couleur 1; Stylo fond hachure: Fond - Couleur 1; Coût: 0; Type de groupe (FM_Type): Autres; Type de groupe (iFMType): 25; Poids de l'objet: 0; Unité poids de l'objet: kg; Stylo de contour: Eléments 2D - Général; Surface par défaut: Enduit - Blanc nature; Surface 1: Carrelage Piscine; Surface 2: RAL 6021 Vert pâle2; Afficher arêtes de contour seulement en 3D: yes
MOB-0002 | Mur Rideau 3 | -90 | 481.332 | 24.8069 | 3.9376 | 24.61 | AC_Pset_Mur_Rideau_3 - Type Hachure: Sans Trame; Stylo Hachure: Fond - Couleur 1; Stylo fond hachure: Fond - Couleur 1; Coût: 0; Type de groupe (FM_Type): Autres; Type de groupe (iFMType): 25; Poids de l'objet: 0; Unité poids de l'objet: kg; Stylo de contour: Eléments 2D - Général; Surface par défaut: Enduit - Blanc nature; Surface 1: Carrelage Piscine; Surface 2: RAL 6021 Vert pâle2; Afficher arêtes de contour seulement en 3D: yes

# IfcDiscreteAccessory: Par soleil droit 10, MOB-0009
In: NIVEAU HAUT ENTRÉE
Material: Sans Trame
ArchiCADProperties - ID Elément entier: MOB-0009; ID Elément compact: MOB-0009; Etage d'implantation: NIVEAU HAUT ENTRÉE; Calque: Cotat: 1/100.Importation IFC; Type: Objet; Verrouillé: no; Nom Elément de Bibliothèque: Accessoire partiel 1; Matériau de construction / Composite / Profil / Hachure: Sans Trame; Fonction structurelle: Non défini; Position: Non défini; Classification d'élement: Type ArchiCAD; Etat de rénovation: Existant; Afficher sur filtre de rénovation: Tous les filtres appropriés; Angle de rotation: 0 deg; Surface: Enduit - Blanc nature
AC_Pset_Accessoire_partiel_1 - Type Hachure: Sans Trame; Stylo Hachure: Fond - Couleur 1; Stylo fond hachure: Fond - Couleur 1; Stylo de contour: Eléments 2D - Général; Surface par défaut: Enduit - Blanc nature; Surface 1: AS Laque argenté; Surface 2: Aluminium; Afficher arêtes de contour seulement en 3D: yes
AC_Pset_RenovationAndPhasing - Renovation Status: Existing
ArchiCADQuantities - Altitude à Zéro du Projet: 3.3564 m; Altitude à étage: 0.356398 m; Superficie de surface: 20.0849 m2; Volume net: 0.249482 m3; Superficie: 15.5174 m2; Hauteur (Taille en Z): 0.15 m; Longueur (A): 1.9583 m; Volume: 0.249482 m3; Largeur (B): 7.92391 m

# IfcDoor: P1 Devanture 1 10, Por-020
In: NIVEAU BAS GYMNASE
Type - OperationType: SINGLE_SWING_LEFT; ParameterTakesPrecedence: no; Sizeable: no
Type - Propriétés Doublure Porte - LiningDepth: 0.08 m; LiningThickness: 0.04 m
Type - Propriétés Panneau Porte - Panneau1 - PanelDepth: 0.04 m; PanelOperation: SWINGING; PanelPosition: MIDDLE
OverallHeight: 2.1 m; OverallWidth: 0.9 m; Material: Sans Trame
Pset_DoorCommon - ThermalTransmittance: 0; GlazingAreaFraction: 0
ArchiCADProperties - ID Elément entier: Por-020; ID Elément compact: Por-020; Etage d'implantation: NIVEAU BAS GYMNASE; Nom de Zone: Hall & Circulation; Numéro de Zone: 010; Calque: Murs Ext: Périphériques.Importation IFC; Type: Porte; Verrouillé: no; Nom Elément de Bibliothèque: Porte (Mur) 16; Matériau de construction / Composite / Profil / Hachure: Menuis1; Fonction structurelle: Non défini; Position: Non défini; Classification d'élement: Type ArchiCAD; Etat de rénovation: Existant; Afficher sur filtre de rénovation: Tous les filtres appropriés; De Zone: Hall & Circulation; Orientation: D; De la Zone numéro: 010; Structure mur: •GYMN 10+10 0232896968; Taille L x H nominale: 0,90x2,10; Taille L x H x E nominale: 0,90x2,10x0,20
AC_Pset_Porte_(Mur)_16 - Contours Mur (0-Sans,1-Tout,2-Côté,3-Longueur): 1; Point ch.0-Non,1-2D,2-3D,3-Tous: 3; Points chauds auto. en 3D: yes; Trou reprend surface latérale de mur: no; Division de surface de trou courbée: no; Stylo du symbole: Ouvertures - Général; Angle ouverture en 2D: 90 deg; Stylo de contour: Eléments 2D - Général; Type Hachure: Sans Trame; Stylo Hachure: Fond - Couleur 1; Stylo fond hachure: Fond - Couleur 1; Stylo cadre: Eléments 2D - Général; Stylo panneaux: Eléments 2D - Général; Angle ouverture en 3D: 0 deg; Afficher arêtes de contour seulement en 3D: yes; Surface par défaut: Enduit - Blanc nature; Surface 1: Métal-Aluminium; Surface 2: Vitrage-Clair; Surface de battant: Bois - Pin granuleux horizontal; Surface de cadre: Bois - Pin granuleux horizontal; Opération IFC (ifc_optype): 1
AC_Pset_RenovationAndPhasing - Renovation Status: Existing
ArchiCADQuantities - Altitude à Zéro du Projet: 0 m; Altitude à étage: 0 m; Hauteur: 2.1 m; Superficie de surface: 5.53608 m2; Volume net: 0.0489668 m3; Largeur: 0.9 m; Epaisseur: 0.1 m; Hauteur nominale seuil: 0 m; Hauteur seuil côté ébrasure: 0 m; Hauteur seuil côté opposé ébrasure: 0 m; Hauteur nominale linteau: 2.1 m; Hauteur linteau côté ébrasure: 2.1 m; Hauteur linteau côté opposé ébrasure: 2.1 m; Largeur ouverture côté ébrasure: 0.9 m; Largeur ouverture côté opposé ébrasure: 0.9 m; Hauteur ouverture côté ébrasure: 2.1 m; Hauteur ouverture côté opposé ébrasure: 2.1 m; Surface ouverture côté ébrasure: 1.89 m2; Surface ouverture côté opposé ébrasure: 1.89 m2; Largeur nominale de l'ouverture côté ébrasure: 0.9 m; Largeur nominale de l'ouverture côté opposée ébrasure: 0.9 m; Hauteur nominale de l'ouverture côté ébrasure: 2.1 m; Hauteur nominale de l'ouverture côté opposée ébrasure: 2.1 m; Surface nominale de l'ouverture P/F côté ébrasure: 1.89 m2; Surface nominale de l'ouverture P/F côté opposé ébrasure: 1.89 m2; Volume ouverture: 0.0489668 m3; Surface nominale ouverture P/F: 1.89 m2; Volume nominal ouverture: 0.378 m3; Valeur Appui ou Linteau: 0 m; Epaisseur de Mur: 0.2 m
AC_Equantity_Porte_(Mur)_16 - Largeur: 1 m; Hauteur: 2.1 m; Hauteur appui à étage actuel: 0 m; Niveau inférieur: 1 m; Niveau supérieur: 0 m; Largeur cadre: 0.05 m; Epaisseur cadre: 0.1 m; Epaisseur panneaux: 0.04 m; Dépass.ouverture à droite: 0 m; Dépass.ouverture supérieur: 0 m; Dépass.ouverture inférieur: 0 m; Dépass.ouverture gauche: 0 m

# IfcDoor: P2 Devanture 2 10 (2)
Type - OperationType: DOUBLE_DOOR_SINGLE_SWING; ParameterTakesPrecedence: no; Sizeable: no
Type - Propriétés Doublure Porte - LiningDepth: 0.08 m; LiningThickness: 0.04 m
Type - Propriétés Panneau Porte - Panneau1 - PanelDepth: 0.04 m; PanelOperation: SWINGING; PanelWidth: 0.5; PanelPosition: LEFT
Type - Propriétés Panneau Porte - Panneau2 - PanelDepth: 0.04 m; PanelOperation: SWINGING; PanelWidth: 0.5; PanelPosition: RIGHT
OverallWidth: 1.9 m; Material: Sans Trame
Pset_DoorCommon - ThermalTransmittance: 0; GlazingAreaFraction: 0
ArchiCADProperties - Type: Porte; Verrouillé: no; Matériau de construction / Composite / Profil / Hachure: Menuis1; Fonction structurelle: Non défini; Position: Non défini; Classification d'élement: Type ArchiCAD; Etat de rénovation: Existant; Afficher sur filtre de rénovation: Tous les filtres appropriés; Orientation: G
AC_Pset_RenovationAndPhasing - Renovation Status: Existing
ArchiCADQuantities - Largeur: 1.9 m; Epaisseur: 0.1 m; Largeur ouverture côté ébrasure: 1.9 m; Largeur ouverture côté opposé ébrasure: 1.9 m; Largeur nominale de l'ouverture côté ébrasure: 1.9 m; Largeur nominale de l'ouverture côté opposée ébrasure: 1.9 m
Name | In | OverallHeight (m) = ArchiCADQuantities, Hauteur (m) = Hauteur ouverture côté ébrasure (m) = Hauteur ouverture côté opposé ébrasure (m) = Hauteur nominale de l'ouverture côté ébrasure (m) = Hauteur nominale de l'ouverture côté opposée ébrasure (m) | ID Elément entier = ID Elément compact | Etage d'implantation | Calque | Nom Elément de Bibliothèque | Structure mur | Taille L x H nominale | Taille L x H x E nominale | Altitude à Zéro du Projet (m) | Altitude à étage (m) | Superficie de surface (m2) | Volume net (m3) = Volume ouverture (m3) | Hauteur nominale seuil (m) = Valeur Appui ou Linteau (m) | Hauteur seuil côté ébrasure (m) = Hauteur seuil côté opposé ébrasure (m) | Hauteur nominale linteau (m) = Hauteur linteau côté ébrasure (m) = Hauteur linteau côté opposé ébrasure (m) | Surface ouverture côté ébrasure (m2) = Surface ouverture côté opposé ébrasure (m2) = Surface nominale de l'ouverture P/F côté ébrasure (m2) = Surface nominale de l'ouverture P/F côté opposé ébrasure (m2) = Surface nominale ouverture P/F (m2) | Volume nominal ouverture (m3) | Epaisseur de Mur (m)
Por-013 | NIVEAU BAS GYMNASE | 2.4 | Por-013 | NIVEAU BAS GYMNASE | Murs Ext: Périphériques.Importation IFC | Porte (Mur) 11 | •GYMN 10+10 0232896968 | 1,90x2,40 | 1,90x2,40x0,20 | 0.02 | 0.02 | 11.9869 | 0.1123 | 0.02 | 0.02 | 2.42 | 4.56 | 0.912 | 0.2 | AC_Pset_Porte_(Mur)_11 - Contours Mur (0-Sans,1-Tout,2-Côté,3-Longueur): 1; Point ch.0-Non,1-2D,2-3D,3-Tous: 3; Points chauds auto. en 3D: yes; Trou reprend surface latérale de mur: no; Division de surface de trou courbée: no; Stylo du symbole: Ouvertures - Général; Angle ouverture en 2D: 90 deg; Stylo de contour: Eléments 2D - Général; Type Hachure: Sans Trame; Stylo Hachure: Fond - Couleur 1; Stylo fond hachure: Fond - Couleur 1; Stylo cadre: Eléments 2D - Général; Stylo panneaux: Eléments 2D - Général; Angle ouverture en 3D: 0 deg; Afficher arêtes de contour seulement en 3D: yes; Surface par défaut: Enduit - Blanc nature; Surface 1: Métal-Aluminium; Surface 2: Métal-Zinc; Surface 3: Vitrage-Bleu; Surface 4: Métal-Fer; Surface de battant: Bois - Pin granuleux horizontal; Surface de cadre: Bois - Pin granuleux horizontal; Opération IFC (ifc_optype): 2; AC_Equantity_Porte_(Mur)_11 - Largeur: 1 m; Hauteur: 2.1 m; Hauteur appui à étage actuel: 0 m; Niveau inférieur: 1 m; Niveau supérieur: 0 m; Largeur cadre: 0.05 m; Epaisseur cadre: 0.1 m; Epaisseur panneaux: 0.04 m; Dépass.ouverture à droite: 0 m; Dépass.ouverture supérieur: 0 m; Dépass.ouverture inférieur: 0 m; Dépass.ouverture gauche: 0 m
Por-014 | NIVEAU HAUT ENTRÉE | 2.95373 | Por-014 | NIVEAU HAUT ENTRÉE | 0.Importation IFC | Porte (Mur) 42 | •GYMN 16+10 | 1,90x2,95 | 1,90x2,95x0,26 | 2.97 | -0.03 | 14.476 | 0.13007 | -5e-12 | 0 | 2.95373 | 5.61209 | 1.45914 | 0.26 | ArchiCADProperties - Nom de Zone: Hall d'Entrée; Numéro de Zone: 010; De Zone: Hall d'Entrée; De la Zone numéro: 010; AC_Pset_Porte_(Mur)_42 - Contours Mur (0-Sans,1-Tout,2-Côté,3-Longueur): 1; Point ch.0-Non,1-2D,2-3D,3-Tous: 3; Points chauds auto. en 3D: yes; Trou reprend surface latérale de mur: no; Division de surface de trou courbée: no; Stylo du symbole: Ouvertures - Général; Angle ouverture en 2D: 90 deg; Stylo de contour: Eléments 2D - Général; Type Hachure: Sans Trame; Stylo Hachure: Fond - Couleur 1; Stylo fond hachure: Fond - Couleur 1; Stylo cadre: Eléments 2D - Général; Stylo panneaux: Eléments 2D - Général; Angle ouverture en 3D: 0 deg; Afficher arêtes de contour seulement en 3D: yes; Surface par défaut: Enduit - Blanc nature; Surface 1: Métal-Aluminium; Surface 2: Vitrage-Clair; Surface 3: Métal-Zinc; Surface 4: Métal-Fer; Surface de battant: Bois - Pin granuleux horizontal; Surface de cadre: Bois - Pin granuleux horizontal; Opération IFC (ifc_optype): 2; AC_Equantity_Porte_(Mur)_42 - Largeur: 1 m; Hauteur: 2.1 m; Hauteur appui à étage actuel: 2.97 m; Niveau inférieur: 1 m; Niveau supérieur: 0 m; Largeur cadre: 0.05 m; Epaisseur cadre: 0.1 m; Epaisseur panneaux: 0.04 m; Dépass.ouverture à droite: 0 m; Dépass.ouverture supérieur: 0 m; Dépass.ouverture inférieur: 0 m; Dépass.ouverture gauche: 0 m

# IfcDoor: P2 Devanture 3 10 (2)
In: NIVEAU BAS GYMNASE
Type - OperationType: DOUBLE_DOOR_SINGLE_SWING; ParameterTakesPrecedence: no; Sizeable: no
Type - Propriétés Doublure Porte - LiningDepth: 0.08 m; LiningThickness: 0.04 m
Type - Propriétés Panneau Porte - Panneau1 - PanelDepth: 0.04 m; PanelOperation: SWINGING; PanelWidth: 0.5; PanelPosition: LEFT
Type - Propriétés Panneau Porte - Panneau2 - PanelDepth: 0.04 m; PanelOperation: SWINGING; PanelWidth: 0.5; PanelPosition: RIGHT
OverallHeight: 2.32 m; OverallWidth: 3.9397 m; Material: Sans Trame
Pset_DoorCommon - ThermalTransmittance: 0; GlazingAreaFraction: 0
ArchiCADProperties - ID Elément entier: Por-022; ID Elément compact: Por-022; Etage d'implantation: NIVEAU BAS GYMNASE; Calque: Murs Ext: Périphériques.Importation IFC; Type: Porte; Verrouillé: no; Matériau de construction / Composite / Profil / Hachure: Menuis1; Fonction structurelle: Non défini; Position: Non défini; Classification d'élement: Type ArchiCAD; Etat de rénovation: Existant; Afficher sur filtre de rénovation: Tous les filtres appropriés; Orientation: G; Structure mur: Acier 2556372607; Taille L x H nominale: 3,94x2,32; Taille L x H x E nominale: 3,94x2,32x0,10
AC_Pset_RenovationAndPhasing - Renovation Status: Existing
ArchiCADQuantities - Altitude à Zéro du Projet: 0.1 m; Altitude à étage: 0.1 m; Hauteur: 2.32 m; Largeur: 3.9397 m; Epaisseur: 0.1 m; Hauteur nominale seuil: 0.1 m; Hauteur seuil côté ébrasure: 0.1 m; Hauteur seuil côté opposé ébrasure: 0.1 m; Hauteur nominale linteau: 2.42 m; Hauteur linteau côté ébrasure: 2.42 m; Hauteur linteau côté opposé ébrasure: 2.42 m; Largeur ouverture côté ébrasure: 3.9397 m; Largeur ouverture côté opposé ébrasure: 3.8397 m; Hauteur ouverture côté ébrasure: 2.32 m; Hauteur ouverture côté opposé ébrasure: 2.32 m; Surface ouverture côté ébrasure: 9.1401 m2; Surface ouverture côté opposé ébrasure: 8.9081 m2; Largeur nominale de l'ouverture côté ébrasure: 3.9397 m; Largeur nominale de l'ouverture côté opposée ébrasure: 3.9397 m; Hauteur nominale de l'ouverture côté ébrasure: 2.32 m; Hauteur nominale de l'ouverture côté opposée ébrasure: 2.32 m; Surface nominale de l'ouverture P/F côté ébrasure: 9.1401 m2; Surface nominale de l'ouverture P/F côté opposé ébrasure: 9.1401 m2; Surface nominale ouverture P/F: 9.1401 m2; Volume nominal ouverture: 0.91401 m3; Valeur Appui ou Linteau: 0.1 m; Epaisseur de Mur: 0.1 m
Name | Nom Elément de Bibliothèque | Superficie de surface (m2) | Volume net (m3) = Volume ouverture (m3)
Por-022 | Porte (Mur) 17 | 22.3576 | 0.200278 | AC_Pset_Porte_(Mur)_17 - Contours Mur (0-Sans,1-Tout,2-Côté,3-Longueur): 1; Point ch.0-Non,1-2D,2-3D,3-Tous: 3; Points chauds auto. en 3D: yes; Trou reprend surface latérale de mur: no; Division de surface de trou courbée: no; Stylo du symbole: Ouvertures - Général; Angle ouverture en 2D: 90 deg; Stylo de contour: Eléments 2D - Général; Type Hachure: Sans Trame; Stylo Hachure: Fond - Couleur 1; Stylo fond hachure: Fond - Couleur 1; Stylo cadre: Eléments 2D - Général; Stylo panneaux: Eléments 2D - Général; Angle ouverture en 3D: 0 deg; Afficher arêtes de contour seulement en 3D: yes; Surface par défaut: Enduit - Blanc nature; Surface 1: Métal-Aluminium; Surface 2: Vitrage-Clair; Surface 3: Métal-Zinc; Surface 4: Métal-Fer; Surface de battant: Bois - Pin granuleux horizontal; Surface de cadre: Bois - Pin granuleux horizontal; Opération IFC (ifc_optype): 2; AC_Equantity_Porte_(Mur)_17 - Largeur: 1 m; Hauteur: 2.1 m; Hauteur appui à étage actuel: 0 m; Niveau inférieur: 1 m; Niveau supérieur: 0 m; Largeur cadre: 0.05 m; Epaisseur cadre: 0.1 m; Epaisseur panneaux: 0.04 m; Dépass.ouverture à droite: 0 m; Dépass.ouverture supérieur: 0 m; Dépass.ouverture inférieur: 0 m; Dépass.ouverture gauche: 0 m
Por-022 | Porte (Mur) 33 | 22.3548 | 0.197296 | AC_Pset_Porte_(Mur)_33 - Contours Mur (0-Sans,1-Tout,2-Côté,3-Longueur): 1; Point ch.0-Non,1-2D,2-3D,3-Tous: 3; Points chauds auto. en 3D: yes; Trou reprend surface latérale de mur: no; Division de surface de trou courbée: no; Stylo du symbole: Ouvertures - Général; Angle ouverture en 2D: 90 deg; Stylo de contour: Eléments 2D - Général; Type Hachure: Sans Trame; Stylo Hachure: Fond - Couleur 1; Stylo fond hachure: Fond - Couleur 1; Stylo cadre: Eléments 2D - Général; Stylo panneaux: Eléments 2D - Général; Angle ouverture en 3D: 0 deg; Afficher arêtes de contour seulement en 3D: yes; Surface par défaut: Enduit - Blanc nature; Surface 1: Métal-Aluminium; Surface 2: Vitrage-Clair; Surface 3: Métal-Zinc; Surface 4: Métal-Fer; Surface de battant: Bois - Pin granuleux horizontal; Surface de cadre: Bois - Pin granuleux horizontal; Opération IFC (ifc_optype): 2; AC_Equantity_Porte_(Mur)_33 - Largeur: 1 m; Hauteur: 2.1 m; Hauteur appui à étage actuel: 0 m; Niveau inférieur: 1 m; Niveau supérieur: 0 m; Largeur cadre: 0.05 m; Epaisseur cadre: 0.1 m; Epaisseur panneaux: 0.04 m; Dépass.ouverture à droite: 0 m; Dépass.ouverture supérieur: 0 m; Dépass.ouverture inférieur: 0 m; Dépass.ouverture gauche: 0 m

# IfcDoor: P_métallique 10, Por-021
In: NIVEAU BAS GYMNASE
Type - OperationType: SINGLE_SWING_LEFT; ParameterTakesPrecedence: no; Sizeable: no
Type - Propriétés Doublure Porte - LiningDepth: 0.1 m; LiningThickness: 0.032 m; ThresholdThickness: 0.012 m
Type - Propriétés Panneau Porte - Panneau1 - PanelDepth: 0.04 m; PanelOperation: SWINGING; PanelPosition: MIDDLE
OverallHeight: 2.1 m; OverallWidth: 0.9 m; Material: Sans Trame
Pset_DoorCommon - ThermalTransmittance: 0; GlazingAreaFraction: 0
ArchiCADProperties - ID Elément entier: Por-021; ID Elément compact: Por-021; Etage d'implantation: NIVEAU BAS GYMNASE; Nom de Zone: Chaufferie; Numéro de Zone: 010; Calque: Murs Ext: Périphériques.Importation IFC; Type: Porte; Verrouillé: no; Nom Elément de Bibliothèque: Porte (Mur) 9; Matériau de construction / Composite / Profil / Hachure: Menuis1; Fonction structurelle: Non défini; Position: Non défini; Classification d'élement: Type ArchiCAD; Etat de rénovation: Existant; Afficher sur filtre de rénovation: Tous les filtres appropriés; De Zone: Chaufferie; Orientation: D; De la Zone numéro: 010; Structure mur: Hachure solide* 1842511997; Taille L x H nominale: 0,90x2,10; Taille L x H x E nominale: 0,90x2,10x0,16
AC_Pset_Porte_(Mur)_9 - Contours Mur (0-Sans,1-Tout,2-Côté,3-Longueur): 1; Point ch.0-Non,1-2D,2-3D,3-Tous: 3; Points chauds auto. en 3D: yes; Trou reprend surface latérale de mur: no; Division de surface de trou courbée: no; Stylo du symbole: Ouvertures - Général; Angle ouverture en 2D: 90 deg; Stylo de contour: Eléments 2D - Général; Type Hachure: Sans Trame; Stylo Hachure: Fond - Couleur 1; Stylo fond hachure: Fond - Couleur 1; Stylo cadre: Eléments 2D - Général; Stylo panneaux: Eléments 2D - Général; Angle ouverture en 3D: 0 deg; Afficher arêtes de contour seulement en 3D: yes; Surface par défaut: Enduit - Blanc nature; Surface 1: Métal-Fer; Surface 2: Métal-Aluminium; Surface 3: Agave 2 OD; Surface de battant: Bois - Pin granuleux horizontal; Surface de cadre: Bois - Pin granuleux horizontal; Opération IFC (ifc_optype): 1
AC_Pset_RenovationAndPhasing - Renovation Status: Existing
ArchiCADQuantities - Altitude à Zéro du Projet: 0 m; Altitude à étage: 0 m; Hauteur: 2.1 m; Superficie de surface: 5.21659 m2; Volume net: 0.0853402 m3; Largeur: 0.9 m; Epaisseur: 0.1 m; Hauteur nominale seuil: 0 m; Hauteur seuil côté ébrasure: 0 m; Hauteur seuil côté opposé ébrasure: 0 m; Hauteur nominale linteau: 2.1 m; Hauteur linteau côté ébrasure: 2.1 m; Hauteur linteau côté opposé ébrasure: 2.1 m; Largeur ouverture côté ébrasure: 0.9 m; Largeur ouverture côté opposé ébrasure: 0.9 m; Hauteur ouverture côté ébrasure: 2.1 m; Hauteur ouverture côté opposé ébrasure: 2.1 m; Surface ouverture côté ébrasure: 1.89 m2; Surface ouverture côté opposé ébrasure: 1.89 m2; Largeur nominale de l'ouverture côté ébrasure: 0.9 m; Largeur nominale de l'ouverture côté opposée ébrasure: 0.9 m; Hauteur nominale de l'ouverture côté ébrasure: 2.1 m; Hauteur nominale de l'ouverture côté opposée ébrasure: 2.1 m; Surface nominale de l'ouverture P/F côté ébrasure: 1.89 m2; Surface nominale de l'ouverture P/F côté opposé ébrasure: 1.89 m2; Volume ouverture: 0.0853402 m3; Surface nominale ouverture P/F: 1.89 m2; Volume nominal ouverture: 0.3024 m3; Valeur Appui ou Linteau: 0 m; Epaisseur de Mur: 0.16 m
AC_Equantity_Porte_(Mur)_9 - Largeur: 1 m; Hauteur: 2.1 m; Hauteur appui à étage actuel: 0 m; Niveau inférieur: 1 m; Niveau supérieur: 0 m; Largeur cadre: 0.05 m; Epaisseur cadre: 0.1 m; Epaisseur panneaux: 0.04 m; Dépass.ouverture à droite: 0 m; Dépass.ouverture supérieur: 0 m; Dépass.ouverture inférieur: 0 m; Dépass.ouverture gauche: 0 m

# IfcDoor: Porte int 1v (55)
Type - ParameterTakesPrecedence: no; Sizeable: no
Material: Sans Trame
ArchiCADProperties - Type: Porte; Verrouillé: no; Matériau de construction / Composite / Profil / Hachure: Menuis1; Fonction structurelle: Non défini; Position: Non défini; Classification d'élement: Type ArchiCAD; Etat de rénovation: Existant; Afficher sur filtre de rénovation: Tous les filtres appropriés; Orientation: G
AC_Pset_RenovationAndPhasing - Renovation Status: Existing
ArchiCADQuantities - Epaisseur: 0.1 m; Hauteur seuil côté ébrasure: 0 m; Hauteur seuil côté opposé ébrasure: 0 m
Name | In | OverallHeight (m) = ArchiCADQuantities, Hauteur (m) = Hauteur nominale de l'ouverture côté ébrasure (m) = Hauteur nominale de l'ouverture côté opposée ébrasure (m) | OverallWidth (m) = ArchiCADQuantities, Largeur (m) = Largeur ouverture côté ébrasure (m) = Largeur ouverture côté opposé ébrasure (m) = Largeur nominale de l'ouverture côté ébrasure (m) = Largeur nominale de l'ouverture côté opposée ébrasure (m) | ID Elément entier = ID Elément compact | Etage d'implantation | Calque | Nom Elément de Bibliothèque | Structure mur | Taille L x H nominale | Taille L x H x E nominale | Altitude à Zéro du Projet (m) | Altitude à étage (m) = Hauteur nominale seuil (m) = Valeur Appui ou Linteau (m) | Superficie de surface (m2) | Volume net (m3) = Volume ouverture (m3) | Hauteur nominale linteau (m) = Hauteur linteau côté ébrasure (m) = Hauteur linteau côté opposé ébrasure (m) = Hauteur ouverture côté ébrasure (m) = Hauteur ouverture côté opposé ébrasure (m) | Surface ouverture côté ébrasure (m2) = Surface ouverture côté opposé ébrasure (m2) | Surface nominale de l'ouverture P/F côté ébrasure (m2) = Surface nominale de l'ouverture P/F côté opposé ébrasure (m2) = Surface nominale ouverture P/F (m2) | Volume nominal ouverture (m3) | Epaisseur de Mur (m)
Por-021 | NIVEAU BAS GYMNASE | 2.055 | 0.79 | Por-021 | NIVEAU BAS GYMNASE | Murs Ext: Périphériques.Importation IFC | Porte (Mur) 1 | Hachure solide* 3962059836 | 0,79x2,05 | 0,79x2,05x0,07 | -0.01 | -0.01 | 4.32837 | 0.0730983 | 2.045 | 1.61555 | 1.62345 | 0.113642 | 0.07 | AC_Pset_Porte_(Mur)_1 - Contours Mur (0-Sans,1-Tout,2-Côté,3-Longueur): 1; Point ch.0-Non,1-2D,2-3D,3-Tous: 3; Points chauds auto. en 3D: yes; Trou reprend surface latérale de mur: no; Division de surface de trou courbée: no; Stylo du symbole: Ouvertures - Général; Angle ouverture en 2D: 90 deg; Stylo de contour: Eléments 2D - Général; Type Hachure: Sans Trame; Stylo Hachure: Fond - Couleur 1; Stylo fond hachure: Fond - Couleur 1; Stylo cadre: Eléments 2D - Général; Stylo panneaux: Eléments 2D - Général; Angle ouverture en 3D: 0 deg; Afficher arêtes de contour seulement en 3D: yes; Surface par défaut: Enduit - Blanc nature; Surface 1: •MENUIS H CHASSIS; Surface 2: Peinture-16; Surface 3: Métal-Fer; Surface 4: Métal-Nickel; Surface de battant: Bois - Pin granuleux horizontal; Surface de cadre: Bois - Pin granuleux horizontal; Opération IFC (ifc_optype): 0; AC_Equantity_Porte_(Mur)_1 - Largeur: 1 m; Hauteur: 2.1 m; Hauteur appui à étage actuel: 0 m; Niveau inférieur: 1 m; Niveau supérieur: 0 m; Largeur cadre: 0.05 m; Epaisseur cadre: 0.1 m; Epaisseur panneaux: 0.04 m; Dépass.ouverture à droite: 0 m; Dépass.ouverture supérieur: 0 m; Dépass.ouverture inférieur: 0 m; Dépass.ouverture gauche: 0 m
Por-018 | NIVEAU BAS GYMNASE | 2.055 | 0.79 | Por-018 | NIVEAU BAS GYMNASE | Murs Ext: Périphériques.Importation IFC | Porte (Mur) 2 | Hachure solide* 3962059836 | 0,79x2,05 | 0,79x2,05x0,10 | -0.01 | -0.01 | 4.61967 | 0.0795918 | 2.045 | 1.61555 | 1.62345 | 0.162345 | 0.1 | AC_Pset_Porte_(Mur)_2 - Contours Mur (0-Sans,1-Tout,2-Côté,3-Longueur): 1; Point ch.0-Non,1-2D,2-3D,3-Tous: 3; Points chauds auto. en 3D: yes; Trou reprend surface latérale de mur: no; Division de surface de trou courbée: no; Stylo du symbole: Ouvertures - Général; Angle ouverture en 2D: 90 deg; Stylo de contour: Eléments 2D - Général; Type Hachure: Sans Trame; Stylo Hachure: Fond - Couleur 1; Stylo fond hachure: Fond - Couleur 1; Stylo cadre: Eléments 2D - Général; Stylo panneaux: Eléments 2D - Général; Angle ouverture en 3D: 0 deg; Afficher arêtes de contour seulement en 3D: yes; Surface par défaut: Enduit - Blanc nature; Surface 1: •MENUIS H CHASSIS; Surface 2: Peinture-16; Surface 3: Métal-Fer; Surface 4: Métal-Nickel; Surface de battant: Bois - Pin granuleux horizontal; Surface de cadre: Bois - Pin granuleux horizontal; Opération IFC (ifc_optype): 0; AC_Equantity_Porte_(Mur)_2 - Largeur: 1 m; Hauteur: 2.1 m; Hauteur appui à étage actuel: 0 m; Niveau inférieur: 1 m; Niveau supérieur: 0 m; Largeur cadre: 0.05 m; Epaisseur cadre: 0.1 m; Epaisseur panneaux: 0.04 m; Dépass.ouverture à droite: 0 m; Dépass.ouverture supérieur: 0 m; Dépass.ouverture inférieur: 0 m; Dépass.ouverture gauche: 0 m
Por-017 | NIVEAU BAS GYMNASE | 2.555 | 0.89 | Por-017 | NIVEAU BAS GYMNASE | Murs Ext: Périphériques.Importation IFC | Porte (Mur) 3 | Hachure solide* 3962059836 | 0,89x2,55 | 0,89x2,55x0,10 | -0.01 | -0.01 | 6.45477 | 0.0997413 | 2.545 | 2.26505 | 2.27395 | 0.227395 | 0.1 | ArchiCADProperties - Nom de Zone: Bureau Prof; Numéro de Zone: 006; De Zone: Sanit Prof F; De la Zone numéro: 010; AC_Pset_Porte_(Mur)_3 - Contours Mur (0-Sans,1-Tout,2-Côté,3-Longueur): 1; Point ch.0-Non,1-2D,2-3D,3-Tous: 3; Points chauds auto. en 3D: yes; Trou reprend surface latérale de mur: no; Division de surface de trou courbée: no; Stylo du symbole: Ouvertures - Général; Angle ouverture en 2D: 90 deg; Stylo de contour: Eléments 2D - Général; Type Hachure: Sans Trame; Stylo Hachure: Fond - Couleur 1; Stylo fond hachure: Fond - Couleur 1; Stylo cadre: Eléments 2D - Général; Stylo panneaux: Eléments 2D - Général; Angle ouverture en 3D: 0 deg; Afficher arêtes de contour seulement en 3D: yes; Surface par défaut: Enduit - Blanc nature; Surface 1: •MENUIS H CHASSIS; Surface 2: Vitrage-Clair; Surface 3: Peinture-16; Surface 4: Métal-Fer; Surface 5: Métal-Nickel; Surface de battant: Bois - Pin granuleux horizontal; Surface de cadre: Bois - Pin granuleux horizontal; Opération IFC (ifc_optype): 0; AC_Equantity_Porte_(Mur)_3 - Largeur: 1 m; Hauteur: 2.1 m; Hauteur appui à étage actuel: 0 m; Niveau inférieur: 1 m; Niveau supérieur: 0 m; Largeur cadre: 0.05 m; Epaisseur cadre: 0.1 m; Epaisseur panneaux: 0.04 m; Dépass.ouverture à droite: 0 m; Dépass.ouverture supérieur: 0 m; Dépass.ouverture inférieur: 0 m; Dépass.ouverture gauche: 0 m
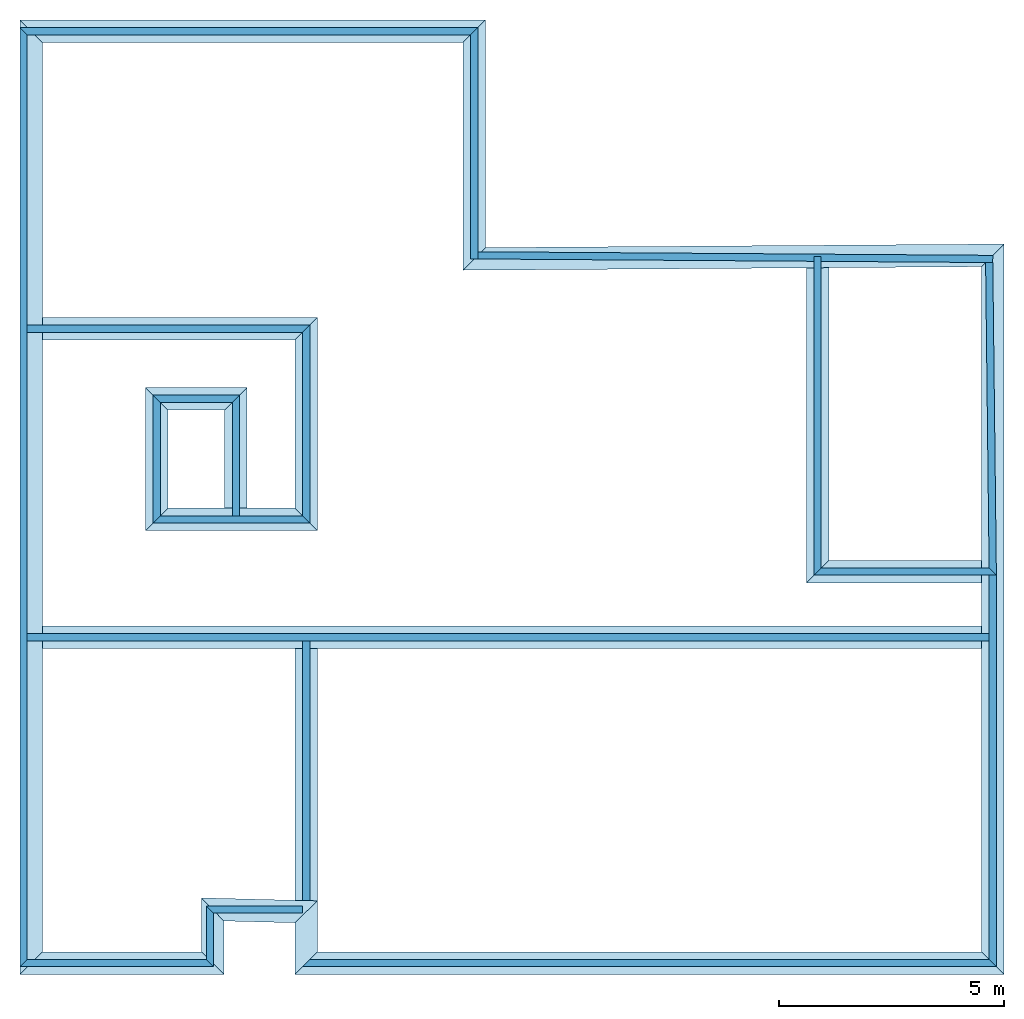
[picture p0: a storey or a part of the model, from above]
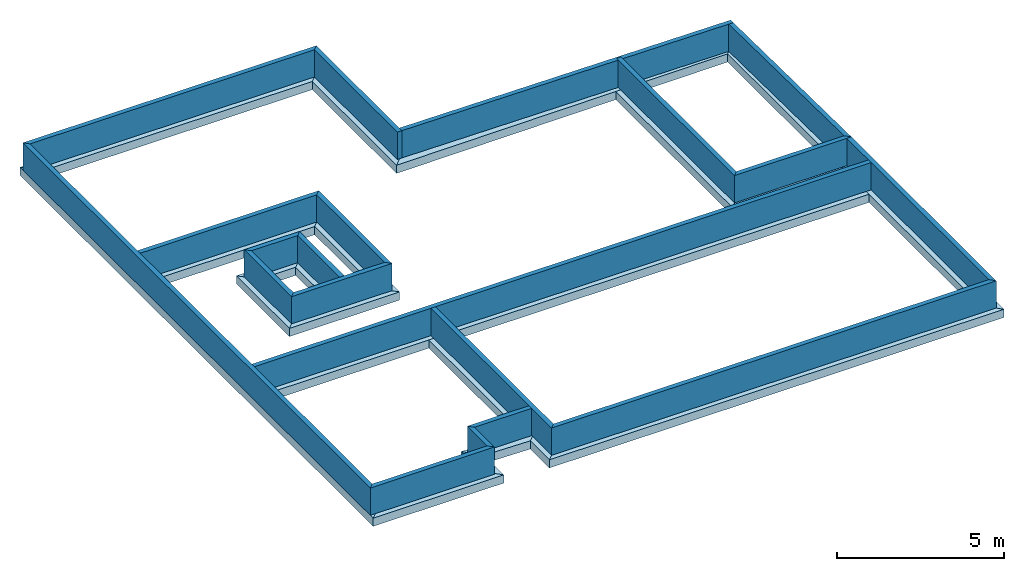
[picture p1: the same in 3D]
Properties of the parts of a building model (IFC2X3), part 2 of 6

# IfcDoor: Porte int 1v (55)
Name | In | OverallHeight (m) = ArchiCADQuantities, Hauteur (m) = Hauteur nominale de l'ouverture côté ébrasure (m) = Hauteur nominale de l'ouverture côté opposée ébrasure (m) | OverallWidth (m) = ArchiCADQuantities, Largeur (m) = Largeur ouverture côté ébrasure (m) = Largeur ouverture côté opposé ébrasure (m) = Largeur nominale de l'ouverture côté ébrasure (m) = Largeur nominale de l'ouverture côté opposée ébrasure (m) | ID Elément entier = ID Elément compact | Etage d'implantation | Calque | Nom Elément de Bibliothèque | Structure mur | Taille L x H nominale | Taille L x H x E nominale | Altitude à Zéro du Projet (m) | Altitude à étage (m) = Hauteur nominale seuil (m) = Valeur Appui ou Linteau (m) | Superficie de surface (m2) | Volume net (m3) = Volume ouverture (m3) | Hauteur nominale linteau (m) = Hauteur linteau côté ébrasure (m) = Hauteur linteau côté opposé ébrasure (m) = Hauteur ouverture côté ébrasure (m) = Hauteur ouverture côté opposé ébrasure (m) | Surface ouverture côté ébrasure (m2) = Surface ouverture côté opposé ébrasure (m2) | Surface nominale de l'ouverture P/F côté ébrasure (m2) = Surface nominale de l'ouverture P/F côté opposé ébrasure (m2) = Surface nominale ouverture P/F (m2) | Volume nominal ouverture (m3) | Epaisseur de Mur (m)
Por-018 | NIVEAU BAS GYMNASE | 2.555 | 0.89 | Por-018 | NIVEAU BAS GYMNASE | Murs Ext: Périphériques.Importation IFC | Porte (Mur) 4 | Hachure solide* 3962059836 | 0,89x2,55 | 0,89x2,55x0,10 | -0.01 | -0.01 | 6.45477 | 0.0997413 | 2.545 | 2.26505 | 2.27395 | 0.227395 | 0.1 | ArchiCADProperties - Nom de Zone: Bureau Prof; Numéro de Zone: 006; De Zone: Sanit Prof H; De la Zone numéro: 010; AC_Pset_Porte_(Mur)_4 - Contours Mur (0-Sans,1-Tout,2-Côté,3-Longueur): 1; Point ch.0-Non,1-2D,2-3D,3-Tous: 3; Points chauds auto. en 3D: yes; Trou reprend surface latérale de mur: no; Division de surface de trou courbée: no; Stylo du symbole: Ouvertures - Général; Angle ouverture en 2D: 90 deg; Stylo de contour: Eléments 2D - Général; Type Hachure: Sans Trame; Stylo Hachure: Fond - Couleur 1; Stylo fond hachure: Fond - Couleur 1; Stylo cadre: Eléments 2D - Général; Stylo panneaux: Eléments 2D - Général; Angle ouverture en 3D: 0 deg; Afficher arêtes de contour seulement en 3D: yes; Surface par défaut: Enduit - Blanc nature; Surface 1: •MENUIS H CHASSIS; Surface 2: Vitrage-Clair; Surface 3: Peinture-16; Surface 4: Métal-Fer; Surface 5: Métal-Nickel; Surface de battant: Bois - Pin granuleux horizontal; Surface de cadre: Bois - Pin granuleux horizontal; Opération IFC (ifc_optype): 0; AC_Equantity_Porte_(Mur)_4 - Largeur: 1 m; Hauteur: 2.1 m; Hauteur appui à étage actuel: 0 m; Niveau inférieur: 1 m; Niveau supérieur: 0 m; Largeur cadre: 0.05 m; Epaisseur cadre: 0.1 m; Epaisseur panneaux: 0.04 m; Dépass.ouverture à droite: 0 m; Dépass.ouverture supérieur: 0 m; Dépass.ouverture inférieur: 0 m; Dépass.ouverture gauche: 0 m
Por-018 | NIVEAU BAS GYMNASE | 2.055 | 0.79 | Por-018 | NIVEAU BAS GYMNASE | Murs Ext: Périphériques.Importation IFC | Porte (Mur) 5 | Hachure solide* 3962059836 | 0,79x2,05 | 0,79x2,05x0,10 | -0.01 | -0.01 | 4.61967 | 0.0795918 | 2.045 | 1.61555 | 1.62345 | 0.162345 | 0.1 | AC_Pset_Porte_(Mur)_5 - Contours Mur (0-Sans,1-Tout,2-Côté,3-Longueur): 1; Point ch.0-Non,1-2D,2-3D,3-Tous: 3; Points chauds auto. en 3D: yes; Trou reprend surface latérale de mur: no; Division de surface de trou courbée: no; Stylo du symbole: Ouvertures - Général; Angle ouverture en 2D: 90 deg; Stylo de contour: Eléments 2D - Général; Type Hachure: Sans Trame; Stylo Hachure: Fond - Couleur 1; Stylo fond hachure: Fond - Couleur 1; Stylo cadre: Eléments 2D - Général; Stylo panneaux: Eléments 2D - Général; Angle ouverture en 3D: 0 deg; Afficher arêtes de contour seulement en 3D: yes; Surface par défaut: Enduit - Blanc nature; Surface 1: •MENUIS H CHASSIS; Surface 2: Peinture-16; Surface 3: Métal-Fer; Surface 4: Métal-Nickel; Surface de battant: Bois - Pin granuleux horizontal; Surface de cadre: Bois - Pin granuleux horizontal; Opération IFC (ifc_optype): 0; AC_Equantity_Porte_(Mur)_5 - Largeur: 1 m; Hauteur: 2.1 m; Hauteur appui à étage actuel: 0 m; Niveau inférieur: 1 m; Niveau supérieur: 0 m; Largeur cadre: 0.05 m; Epaisseur cadre: 0.1 m; Epaisseur panneaux: 0.04 m; Dépass.ouverture à droite: 0 m; Dépass.ouverture supérieur: 0 m; Dépass.ouverture inférieur: 0 m; Dépass.ouverture gauche: 0 m
Por-019 | NIVEAU BAS GYMNASE | 2.055 | 0.79 | Por-019 | NIVEAU BAS GYMNASE | Murs Ext: Périphériques.Importation IFC | Porte (Mur) 1 | Hachure solide* 3962059836 | 0,79x2,05 | 0,79x2,05x0,07 | -0.01 | -0.01 | 4.32837 | 0.0730983 | 2.045 | 1.61555 | 1.62345 | 0.113642 | 0.07 | AC_Pset_Porte_(Mur)_1 - Contours Mur (0-Sans,1-Tout,2-Côté,3-Longueur): 1; Point ch.0-Non,1-2D,2-3D,3-Tous: 3; Points chauds auto. en 3D: yes; Trou reprend surface latérale de mur: no; Division de surface de trou courbée: no; Stylo du symbole: Ouvertures - Général; Angle ouverture en 2D: 90 deg; Stylo de contour: Eléments 2D - Général; Type Hachure: Sans Trame; Stylo Hachure: Fond - Couleur 1; Stylo fond hachure: Fond - Couleur 1; Stylo cadre: Eléments 2D - Général; Stylo panneaux: Eléments 2D - Général; Angle ouverture en 3D: 0 deg; Afficher arêtes de contour seulement en 3D: yes; Surface par défaut: Enduit - Blanc nature; Surface 1: •MENUIS H CHASSIS; Surface 2: Peinture-16; Surface 3: Métal-Fer; Surface 4: Métal-Nickel; Surface de battant: Bois - Pin granuleux horizontal; Surface de cadre: Bois - Pin granuleux horizontal; Opération IFC (ifc_optype): 0; AC_Equantity_Porte_(Mur)_1 - Largeur: 1 m; Hauteur: 2.1 m; Hauteur appui à étage actuel: 0 m; Niveau inférieur: 1 m; Niveau supérieur: 0 m; Largeur cadre: 0.05 m; Epaisseur cadre: 0.1 m; Epaisseur panneaux: 0.04 m; Dépass.ouverture à droite: 0 m; Dépass.ouverture supérieur: 0 m; Dépass.ouverture inférieur: 0 m; Dépass.ouverture gauche: 0 m
Por-017 | NIVEAU BAS GYMNASE | 2.555 | 0.89 | Por-017 | NIVEAU BAS GYMNASE | Murs Ext: Périphériques.Importation IFC | Porte (Mur) 7 | Hachure solide* 1842511997 | 0,89x2,55 | 0,89x2,55x0,16 | -0.01 | -0.01 | 7.27437 | 0.117939 | 2.545 | 2.26505 | 2.27395 | 0.363832 | 0.16 | ArchiCADProperties - Nom de Zone: Sanit Vest 1; Numéro de Zone: 010; De Zone: Hall & Circulation; De la Zone numéro: 010; AC_Pset_Porte_(Mur)_7 - Contours Mur (0-Sans,1-Tout,2-Côté,3-Longueur): 1; Point ch.0-Non,1-2D,2-3D,3-Tous: 3; Points chauds auto. en 3D: yes; Trou reprend surface latérale de mur: no; Division de surface de trou courbée: no; Stylo du symbole: Ouvertures - Général; Angle ouverture en 2D: 90 deg; Stylo de contour: Eléments 2D - Général; Type Hachure: Sans Trame; Stylo Hachure: Fond - Couleur 1; Stylo fond hachure: Fond - Couleur 1; Stylo cadre: Eléments 2D - Général; Stylo panneaux: Eléments 2D - Général; Angle ouverture en 3D: 0 deg; Afficher arêtes de contour seulement en 3D: yes; Surface par défaut: Enduit - Blanc nature; Surface 1: •MENUIS H CHASSIS; Surface 2: Vitrage-Clair; Surface 3: Peinture-16; Surface 4: Métal-Fer; Surface 5: Métal-Nickel; Surface de battant: Bois - Pin granuleux horizontal; Surface de cadre: Bois - Pin granuleux horizontal; Opération IFC (ifc_optype): 0; AC_Equantity_Porte_(Mur)_7 - Largeur: 1 m; Hauteur: 2.1 m; Hauteur appui à étage actuel: 0 m; Niveau inférieur: 1 m; Niveau supérieur: 0 m; Largeur cadre: 0.05 m; Epaisseur cadre: 0.1 m; Epaisseur panneaux: 0.04 m; Dépass.ouverture à droite: 0 m; Dépass.ouverture supérieur: 0 m; Dépass.ouverture inférieur: 0 m; Dépass.ouverture gauche: 0 m
Por-017 | NIVEAU BAS GYMNASE | 2.555 | 0.89 | Por-017 | NIVEAU BAS GYMNASE | Murs Ext: Périphériques.Importation IFC | Porte (Mur) 8 | Hachure solide* 1842511997 | 0,89x2,55 | 0,89x2,55x0,16 | -0.01 | -0.01 | 7.27437 | 0.117939 | 2.545 | 2.26505 | 2.27395 | 0.363832 | 0.16 | ArchiCADProperties - Nom de Zone: Sanit Vest 2; Numéro de Zone: 010; De Zone: Hall & Circulation; De la Zone numéro: 010; AC_Pset_Porte_(Mur)_8 - Contours Mur (0-Sans,1-Tout,2-Côté,3-Longueur): 1; Point ch.0-Non,1-2D,2-3D,3-Tous: 3; Points chauds auto. en 3D: yes; Trou reprend surface latérale de mur: no; Division de surface de trou courbée: no; Stylo du symbole: Ouvertures - Général; Angle ouverture en 2D: 90 deg; Stylo de contour: Eléments 2D - Général; Type Hachure: Sans Trame; Stylo Hachure: Fond - Couleur 1; Stylo fond hachure: Fond - Couleur 1; Stylo cadre: Eléments 2D - Général; Stylo panneaux: Eléments 2D - Général; Angle ouverture en 3D: 0 deg; Afficher arêtes de contour seulement en 3D: yes; Surface par défaut: Enduit - Blanc nature; Surface 1: •MENUIS H CHASSIS; Surface 2: Vitrage-Clair; Surface 3: Peinture-16; Surface 4: Métal-Fer; Surface 5: Métal-Nickel; Surface de battant: Bois - Pin granuleux horizontal; Surface de cadre: Bois - Pin granuleux horizontal; Opération IFC (ifc_optype): 0; AC_Equantity_Porte_(Mur)_8 - Largeur: 1 m; Hauteur: 2.1 m; Hauteur appui à étage actuel: 0 m; Niveau inférieur: 1 m; Niveau supérieur: 0 m; Largeur cadre: 0.05 m; Epaisseur cadre: 0.1 m; Epaisseur panneaux: 0.04 m; Dépass.ouverture à droite: 0 m; Dépass.ouverture supérieur: 0 m; Dépass.ouverture inférieur: 0 m; Dépass.ouverture gauche: 0 m
Por-017 | NIVEAU BAS GYMNASE | 2.555 | 0.89 | Por-017 | NIVEAU BAS GYMNASE | Murs Ext: Périphériques.Importation IFC | Porte (Mur) 7 | Hachure solide* 1842511997 | 0,89x2,55 | 0,89x2,55x0,16 | -0.01 | -0.01 | 7.27437 | 0.117939 | 2.545 | 2.26505 | 2.27395 | 0.363832 | 0.16 | ArchiCADProperties - Nom de Zone: Sanit Vest 3; Numéro de Zone: 010; De Zone: Hall & Circulation; De la Zone numéro: 010; AC_Pset_Porte_(Mur)_7 - Contours Mur (0-Sans,1-Tout,2-Côté,3-Longueur): 1; Point ch.0-Non,1-2D,2-3D,3-Tous: 3; Points chauds auto. en 3D: yes; Trou reprend surface latérale de mur: no; Division de surface de trou courbée: no; Stylo du symbole: Ouvertures - Général; Angle ouverture en 2D: 90 deg; Stylo de contour: Eléments 2D - Général; Type Hachure: Sans Trame; Stylo Hachure: Fond - Couleur 1; Stylo fond hachure: Fond - Couleur 1; Stylo cadre: Eléments 2D - Général; Stylo panneaux: Eléments 2D - Général; Angle ouverture en 3D: 0 deg; Afficher arêtes de contour seulement en 3D: yes; Surface par défaut: Enduit - Blanc nature; Surface 1: •MENUIS H CHASSIS; Surface 2: Vitrage-Clair; Surface 3: Peinture-16; Surface 4: Métal-Fer; Surface 5: Métal-Nickel; Surface de battant: Bois - Pin granuleux horizontal; Surface de cadre: Bois - Pin granuleux horizontal; Opération IFC (ifc_optype): 0; AC_Equantity_Porte_(Mur)_7 - Largeur: 1 m; Hauteur: 2.1 m; Hauteur appui à étage actuel: 0 m; Niveau inférieur: 1 m; Niveau supérieur: 0 m; Largeur cadre: 0.05 m; Epaisseur cadre: 0.1 m; Epaisseur panneaux: 0.04 m; Dépass.ouverture à droite: 0 m; Dépass.ouverture supérieur: 0 m; Dépass.ouverture inférieur: 0 m; Dépass.ouverture gauche: 0 m
Por-018 | NIVEAU BAS GYMNASE | 2.555 | 0.89 | Por-018 | NIVEAU BAS GYMNASE | Murs Ext: Périphériques.Importation IFC | Porte (Mur) 8 | Hachure solide* 1842511997 | 0,89x2,55 | 0,89x2,55x0,16 | -0.01 | -0.01 | 7.27437 | 0.117939 | 2.545 | 2.26505 | 2.27395 | 0.363832 | 0.16 | ArchiCADProperties - Nom de Zone: Sanit Vest 4; Numéro de Zone: 010; De Zone: Hall & Circulation; De la Zone numéro: 010; AC_Pset_Porte_(Mur)_8 - Contours Mur (0-Sans,1-Tout,2-Côté,3-Longueur): 1; Point ch.0-Non,1-2D,2-3D,3-Tous: 3; Points chauds auto. en 3D: yes; Trou reprend surface latérale de mur: no; Division de surface de trou courbée: no; Stylo du symbole: Ouvertures - Général; Angle ouverture en 2D: 90 deg; Stylo de contour: Eléments 2D - Général; Type Hachure: Sans Trame; Stylo Hachure: Fond - Couleur 1; Stylo fond hachure: Fond - Couleur 1; Stylo cadre: Eléments 2D - Général; Stylo panneaux: Eléments 2D - Général; Angle ouverture en 3D: 0 deg; Afficher arêtes de contour seulement en 3D: yes; Surface par défaut: Enduit - Blanc nature; Surface 1: •MENUIS H CHASSIS; Surface 2: Vitrage-Clair; Surface 3: Peinture-16; Surface 4: Métal-Fer; Surface 5: Métal-Nickel; Surface de battant: Bois - Pin granuleux horizontal; Surface de cadre: Bois - Pin granuleux horizontal; Opération IFC (ifc_optype): 0; AC_Equantity_Porte_(Mur)_8 - Largeur: 1 m; Hauteur: 2.1 m; Hauteur appui à étage actuel: 0 m; Niveau inférieur: 1 m; Niveau supérieur: 0 m; Largeur cadre: 0.05 m; Epaisseur cadre: 0.1 m; Epaisseur panneaux: 0.04 m; Dépass.ouverture à droite: 0 m; Dépass.ouverture supérieur: 0 m; Dépass.ouverture inférieur: 0 m; Dépass.ouverture gauche: 0 m
Por-017 | NIVEAU BAS GYMNASE | 2.555 | 0.89 | Por-017 | NIVEAU BAS GYMNASE | Murs Ext: Périphériques.Importation IFC | Porte (Mur) 10 | •GYMN 10+10 0232896968 | 0,89x2,55 | 0,89x2,55x0,20 | -0.01 | -0.01 | 7.82077 | 0.130071 | 2.545 | 2.26505 | 2.27395 | 0.45479 | 0.2 | ArchiCADProperties - Nom de Zone: Bureau Prof; Numéro de Zone: 006; De Zone: Hall & Circulation; De la Zone numéro: 010; AC_Pset_Porte_(Mur)_10 - Contours Mur (0-Sans,1-Tout,2-Côté,3-Longueur): 1; Point ch.0-Non,1-2D,2-3D,3-Tous: 3; Points chauds auto. en 3D: yes; Trou reprend surface latérale de mur: no; Division de surface de trou courbée: no; Stylo du symbole: Ouvertures - Général; Angle ouverture en 2D: 90 deg; Stylo de contour: Eléments 2D - Général; Type Hachure: Sans Trame; Stylo Hachure: Fond - Couleur 1; Stylo fond hachure: Fond - Couleur 1; Stylo cadre: Eléments 2D - Général; Stylo panneaux: Eléments 2D - Général; Angle ouverture en 3D: 0 deg; Afficher arêtes de contour seulement en 3D: yes; Surface par défaut: Enduit - Blanc nature; Surface 1: •MENUIS H CHASSIS; Surface 2: Vitrage-Clair; Surface 3: Peinture-16; Surface 4: Métal-Fer; Surface 5: Métal-Nickel; Surface de battant: Bois - Pin granuleux horizontal; Surface de cadre: Bois - Pin granuleux horizontal; Opération IFC (ifc_optype): 0; AC_Equantity_Porte_(Mur)_10 - Largeur: 1 m; Hauteur: 2.1 m; Hauteur appui à étage actuel: 0 m; Niveau inférieur: 1 m; Niveau supérieur: 0 m; Largeur cadre: 0.05 m; Epaisseur cadre: 0.1 m; Epaisseur panneaux: 0.04 m; Dépass.ouverture à droite: 0 m; Dépass.ouverture supérieur: 0 m; Dépass.ouverture inférieur: 0 m; Dépass.ouverture gauche: 0 m
Por-019 | NIVEAU BAS GYMNASE | 2.055 | 0.79 | Por-019 | NIVEAU BAS GYMNASE | Murs Ext: Périphériques.Importation IFC | Porte (Mur) 12 | Hachure solide* 3962059836 | 0,79x2,05 | 0,79x2,05x0,07 | -0.01 | -0.01 | 4.32837 | 0.0730983 | 2.045 | 1.61555 | 1.62345 | 0.113642 | 0.07 | AC_Pset_Porte_(Mur)_12 - Contours Mur (0-Sans,1-Tout,2-Côté,3-Longueur): 1; Point ch.0-Non,1-2D,2-3D,3-Tous: 3; Points chauds auto. en 3D: yes; Trou reprend surface latérale de mur: no; Division de surface de trou courbée: no; Stylo du symbole: Ouvertures - Général; Angle ouverture en 2D: 90 deg; Stylo de contour: Eléments 2D - Général; Type Hachure: Sans Trame; Stylo Hachure: Fond - Couleur 1; Stylo fond hachure: Fond - Couleur 1; Stylo cadre: Eléments 2D - Général; Stylo panneaux: Eléments 2D - Général; Angle ouverture en 3D: 0 deg; Afficher arêtes de contour seulement en 3D: yes; Surface par défaut: Enduit - Blanc nature; Surface 1: •MENUIS H CHASSIS; Surface 2: Peinture-16; Surface 3: Métal-Fer; Surface 4: Métal-Nickel; Surface de battant: Bois - Pin granuleux horizontal; Surface de cadre: Bois - Pin granuleux horizontal; Opération IFC (ifc_optype): 0; AC_Equantity_Porte_(Mur)_12 - Largeur: 1 m; Hauteur: 2.1 m; Hauteur appui à étage actuel: 0 m; Niveau inférieur: 1 m; Niveau supérieur: 0 m; Largeur cadre: 0.05 m; Epaisseur cadre: 0.1 m; Epaisseur panneaux: 0.04 m; Dépass.ouverture à droite: 0 m; Dépass.ouverture supérieur: 0 m; Dépass.ouverture inférieur: 0 m; Dépass.ouverture gauche: 0 m
Por-018 | NIVEAU BAS GYMNASE | 2.555 | 0.89 | Por-018 | NIVEAU BAS GYMNASE | Murs Ext: Périphériques.Importation IFC | Porte (Mur) 4 | Hachure solide* 4022991772 | 0,89x2,55 | 0,89x2,55x0,10 | -0.01 | -0.01 | 6.45477 | 0.0997413 | 2.545 | 2.26505 | 2.27395 | 0.227395 | 0.1 | ArchiCADProperties - Nom de Zone: Bureau Arbitre; Numéro de Zone: 006; De Zone: Hall & Circulation; De la Zone numéro: 010; AC_Pset_Porte_(Mur)_4 - Contours Mur (0-Sans,1-Tout,2-Côté,3-Longueur): 1; Point ch.0-Non,1-2D,2-3D,3-Tous: 3; Points chauds auto. en 3D: yes; Trou reprend surface latérale de mur: no; Division de surface de trou courbée: no; Stylo du symbole: Ouvertures - Général; Angle ouverture en 2D: 90 deg; Stylo de contour: Eléments 2D - Général; Type Hachure: Sans Trame; Stylo Hachure: Fond - Couleur 1; Stylo fond hachure: Fond - Couleur 1; Stylo cadre: Eléments 2D - Général; Stylo panneaux: Eléments 2D - Général; Angle ouverture en 3D: 0 deg; Afficher arêtes de contour seulement en 3D: yes; Surface par défaut: Enduit - Blanc nature; Surface 1: •MENUIS H CHASSIS; Surface 2: Vitrage-Clair; Surface 3: Peinture-16; Surface 4: Métal-Fer; Surface 5: Métal-Nickel; Surface de battant: Bois - Pin granuleux horizontal; Surface de cadre: Bois - Pin granuleux horizontal; Opération IFC (ifc_optype): 0; AC_Equantity_Porte_(Mur)_4 - Largeur: 1 m; Hauteur: 2.1 m; Hauteur appui à étage actuel: 0 m; Niveau inférieur: 1 m; Niveau supérieur: 0 m; Largeur cadre: 0.05 m; Epaisseur cadre: 0.1 m; Epaisseur panneaux: 0.04 m; Dépass.ouverture à droite: 0 m; Dépass.ouverture supérieur: 0 m; Dépass.ouverture inférieur: 0 m; Dépass.ouverture gauche: 0 m
Por-021 | NIVEAU BAS GYMNASE | 2.055 | 0.79 | Por-021 | NIVEAU BAS GYMNASE | Murs Ext: Périphériques.Importation IFC | Porte (Mur) 12 | Hachure solide* 3962059836 | 0,79x2,05 | 0,79x2,05x0,07 | -0.01 | -0.01 | 4.32837 | 0.0730983 | 2.045 | 1.61555 | 1.62345 | 0.113642 | 0.07 | AC_Pset_Porte_(Mur)_12 - Contours Mur (0-Sans,1-Tout,2-Côté,3-Longueur): 1; Point ch.0-Non,1-2D,2-3D,3-Tous: 3; Points chauds auto. en 3D: yes; Trou reprend surface latérale de mur: no; Division de surface de trou courbée: no; Stylo du symbole: Ouvertures - Général; Angle ouverture en 2D: 90 deg; Stylo de contour: Eléments 2D - Général; Type Hachure: Sans Trame; Stylo Hachure: Fond - Couleur 1; Stylo fond hachure: Fond - Couleur 1; Stylo cadre: Eléments 2D - Général; Stylo panneaux: Eléments 2D - Général; Angle ouverture en 3D: 0 deg; Afficher arêtes de contour seulement en 3D: yes; Surface par défaut: Enduit - Blanc nature; Surface 1: •MENUIS H CHASSIS; Surface 2: Peinture-16; Surface 3: Métal-Fer; Surface 4: Métal-Nickel; Surface de battant: Bois - Pin granuleux horizontal; Surface de cadre: Bois - Pin granuleux horizontal; Opération IFC (ifc_optype): 0; AC_Equantity_Porte_(Mur)_12 - Largeur: 1 m; Hauteur: 2.1 m; Hauteur appui à étage actuel: 0 m; Niveau inférieur: 1 m; Niveau supérieur: 0 m; Largeur cadre: 0.05 m; Epaisseur cadre: 0.1 m; Epaisseur panneaux: 0.04 m; Dépass.ouverture à droite: 0 m; Dépass.ouverture supérieur: 0 m; Dépass.ouverture inférieur: 0 m; Dépass.ouverture gauche: 0 m
Por-017 | NIVEAU BAS GYMNASE | 2.555 | 0.89 | Por-017 | NIVEAU BAS GYMNASE | Murs Ext: Périphériques.Importation IFC | Porte (Mur) 3 | Hachure solide* 3962059836 | 0,89x2,55 | 0,89x2,55x0,10 | -0.01 | -0.01 | 6.45477 | 0.0997413 | 2.545 | 2.26505 | 2.27395 | 0.227395 | 0.1 | ArchiCADProperties - Nom de Zone: Local Nettoyage Ent.; Numéro de Zone: 010; De Zone: Hall & Circulation; De la Zone numéro: 010; AC_Pset_Porte_(Mur)_3 - Contours Mur (0-Sans,1-Tout,2-Côté,3-Longueur): 1; Point ch.0-Non,1-2D,2-3D,3-Tous: 3; Points chauds auto. en 3D: yes; Trou reprend surface latérale de mur: no; Division de surface de trou courbée: no; Stylo du symbole: Ouvertures - Général; Angle ouverture en 2D: 90 deg; Stylo de contour: Eléments 2D - Général; Type Hachure: Sans Trame; Stylo Hachure: Fond - Couleur 1; Stylo fond hachure: Fond - Couleur 1; Stylo cadre: Eléments 2D - Général; Stylo panneaux: Eléments 2D - Général; Angle ouverture en 3D: 0 deg; Afficher arêtes de contour seulement en 3D: yes; Surface par défaut: Enduit - Blanc nature; Surface 1: •MENUIS H CHASSIS; Surface 2: Vitrage-Clair; Surface 3: Peinture-16; Surface 4: Métal-Fer; Surface 5: Métal-Nickel; Surface de battant: Bois - Pin granuleux horizontal; Surface de cadre: Bois - Pin granuleux horizontal; Opération IFC (ifc_optype): 0; AC_Equantity_Porte_(Mur)_3 - Largeur: 1 m; Hauteur: 2.1 m; Hauteur appui à étage actuel: 0 m; Niveau inférieur: 1 m; Niveau supérieur: 0 m; Largeur cadre: 0.05 m; Epaisseur cadre: 0.1 m; Epaisseur panneaux: 0.04 m; Dépass.ouverture à droite: 0 m; Dépass.ouverture supérieur: 0 m; Dépass.ouverture inférieur: 0 m; Dépass.ouverture gauche: 0 m
Por-018 | NIVEAU BAS GYMNASE | 2.555 | 0.89 | Por-018 | NIVEAU BAS GYMNASE | Murs Ext: Périphériques.Importation IFC | Porte (Mur) 3 | Hachure solide* 3962059836 | 0,89x2,55 | 0,89x2,55x0,10 | -0.01 | -0.01 | 6.45477 | 0.0997413 | 2.545 | 2.26505 | 2.27395 | 0.227395 | 0.1 | ArchiCADProperties - Nom de Zone: Sanit Vest 5; Numéro de Zone: 010; De Zone: Hall & Circulation; De la Zone numéro: 010; AC_Pset_Porte_(Mur)_3 - Contours Mur (0-Sans,1-Tout,2-Côté,3-Longueur): 1; Point ch.0-Non,1-2D,2-3D,3-Tous: 3; Points chauds auto. en 3D: yes; Trou reprend surface latérale de mur: no; Division de surface de trou courbée: no; Stylo du symbole: Ouvertures - Général; Angle ouverture en 2D: 90 deg; Stylo de contour: Eléments 2D - Général; Type Hachure: Sans Trame; Stylo Hachure: Fond - Couleur 1; Stylo fond hachure: Fond - Couleur 1; Stylo cadre: Eléments 2D - Général; Stylo panneaux: Eléments 2D - Général; Angle ouverture en 3D: 0 deg; Afficher arêtes de contour seulement en 3D: yes; Surface par défaut: Enduit - Blanc nature; Surface 1: •MENUIS H CHASSIS; Surface 2: Vitrage-Clair; Surface 3: Peinture-16; Surface 4: Métal-Fer; Surface 5: Métal-Nickel; Surface de battant: Bois - Pin granuleux horizontal; Surface de cadre: Bois - Pin granuleux horizontal; Opération IFC (ifc_optype): 0; AC_Equantity_Porte_(Mur)_3 - Largeur: 1 m; Hauteur: 2.1 m; Hauteur appui à étage actuel: 0 m; Niveau inférieur: 1 m; Niveau supérieur: 0 m; Largeur cadre: 0.05 m; Epaisseur cadre: 0.1 m; Epaisseur panneaux: 0.04 m; Dépass.ouverture à droite: 0 m; Dépass.ouverture supérieur: 0 m; Dépass.ouverture inférieur: 0 m; Dépass.ouverture gauche: 0 m
Por-019 | NIVEAU BAS GYMNASE | 2.555 | 0.89 | Por-019 | NIVEAU BAS GYMNASE | Murs Ext: Périphériques.Importation IFC | Porte (Mur) 4 | Hachure solide* 3962059836 | 0,89x2,55 | 0,89x2,55x0,10 | -0.01 | -0.01 | 6.45477 | 0.0997413 | 2.545 | 2.26505 | 2.27395 | 0.227395 | 0.1 | ArchiCADProperties - Nom de Zone: Sanit Vest 6; Numéro de Zone: 010; De Zone: Hall & Circulation; De la Zone numéro: 010; AC_Pset_Porte_(Mur)_4 - Contours Mur (0-Sans,1-Tout,2-Côté,3-Longueur): 1; Point ch.0-Non,1-2D,2-3D,3-Tous: 3; Points chauds auto. en 3D: yes; Trou reprend surface latérale de mur: no; Division de surface de trou courbée: no; Stylo du symbole: Ouvertures - Général; Angle ouverture en 2D: 90 deg; Stylo de contour: Eléments 2D - Général; Type Hachure: Sans Trame; Stylo Hachure: Fond - Couleur 1; Stylo fond hachure: Fond - Couleur 1; Stylo cadre: Eléments 2D - Général; Stylo panneaux: Eléments 2D - Général; Angle ouverture en 3D: 0 deg; Afficher arêtes de contour seulement en 3D: yes; Surface par défaut: Enduit - Blanc nature; Surface 1: •MENUIS H CHASSIS; Surface 2: Vitrage-Clair; Surface 3: Peinture-16; Surface 4: Métal-Fer; Surface 5: Métal-Nickel; Surface de battant: Bois - Pin granuleux horizontal; Surface de cadre: Bois - Pin granuleux horizontal; Opération IFC (ifc_optype): 0; AC_Equantity_Porte_(Mur)_4 - Largeur: 1 m; Hauteur: 2.1 m; Hauteur appui à étage actuel: 0 m; Niveau inférieur: 1 m; Niveau supérieur: 0 m; Largeur cadre: 0.05 m; Epaisseur cadre: 0.1 m; Epaisseur panneaux: 0.04 m; Dépass.ouverture à droite: 0 m; Dépass.ouverture supérieur: 0 m; Dépass.ouverture inférieur: 0 m; Dépass.ouverture gauche: 0 m
Por-018 | NIVEAU BAS GYMNASE | 2.05 | 0.86 | Por-018 | NIVEAU BAS GYMNASE | 0.Importation IFC | Porte (Mur) 25 | Hachure solide 3821565075 | 0,86x2,05 | 0,86x2,05x0,02 | -0.02 | -0.02 | 4.00463 | 0.035358 | 2.03 | 1.7458 | 1.763 | 0.03526 | 0.02 | AC_Pset_Porte_(Mur)_25 - Contours Mur (0-Sans,1-Tout,2-Côté,3-Longueur): 1; Point ch.0-Non,1-2D,2-3D,3-Tous: 3; Points chauds auto. en 3D: yes; Trou reprend surface latérale de mur: no; Division de surface de trou courbée: no; Stylo du symbole: Ouvertures - Général; Angle ouverture en 2D: 90 deg; Stylo de contour: Eléments 2D - Général; Type Hachure: Sans Trame; Stylo Hachure: Fond - Couleur 1; Stylo fond hachure: Fond - Couleur 1; Stylo cadre: Eléments 2D - Général; Stylo panneaux: Eléments 2D - Général; Angle ouverture en 3D: 0 deg; Afficher arêtes de contour seulement en 3D: yes; Surface par défaut: Enduit - Blanc nature; Surface 1: Menuiserie Plastique (2); Surface 2: Peinture-16; Surface 3: Métal-Nickel; Surface 4: Métal-Fer; Surface de battant: Bois - Pin granuleux horizontal; Surface de cadre: Bois - Pin granuleux horizontal; Opération IFC (ifc_optype): 0; AC_Equantity_Porte_(Mur)_25 - Largeur: 1 m; Hauteur: 2.1 m; Hauteur appui à étage actuel: 0 m; Niveau inférieur: 1 m; Niveau supérieur: 0 m; Largeur cadre: 0.05 m; Epaisseur cadre: 0.1 m; Epaisseur panneaux: 0.04 m; Dépass.ouverture à droite: 0 m; Dépass.ouverture supérieur: 0 m; Dépass.ouverture inférieur: 0 m; Dépass.ouverture gauche: 0 m
Por-018 | NIVEAU BAS GYMNASE | 2.05 | 0.78 | Por-018 | NIVEAU BAS GYMNASE | 0.Importation IFC | Porte (Mur) 26 | Hachure solide 3821565075 | 0,78x2,05 | 0,78x2,05x0,02 | -0.02 | -0.02 | 3.67103 | 0.032104 | 2.03 | 1.5834 | 1.599 | 0.03198 | 0.02 | AC_Pset_Porte_(Mur)_26 - Contours Mur (0-Sans,1-Tout,2-Côté,3-Longueur): 1; Point ch.0-Non,1-2D,2-3D,3-Tous: 3; Points chauds auto. en 3D: yes; Trou reprend surface latérale de mur: no; Division de surface de trou courbée: no; Stylo du symbole: Ouvertures - Général; Angle ouverture en 2D: 90 deg; Stylo de contour: Eléments 2D - Général; Type Hachure: Sans Trame; Stylo Hachure: Fond - Couleur 1; Stylo fond hachure: Fond - Couleur 1; Stylo cadre: Eléments 2D - Général; Stylo panneaux: Eléments 2D - Général; Angle ouverture en 3D: 0 deg; Afficher arêtes de contour seulement en 3D: yes; Surface par défaut: Enduit - Blanc nature; Surface 1: Menuiserie Plastique (2); Surface 2: Peinture-16; Surface 3: Métal-Nickel; Surface 4: Métal-Fer; Surface de battant: Bois - Pin granuleux horizontal; Surface de cadre: Bois - Pin granuleux horizontal; Opération IFC (ifc_optype): 0; AC_Equantity_Porte_(Mur)_26 - Largeur: 1 m; Hauteur: 2.1 m; Hauteur appui à étage actuel: 0 m; Niveau inférieur: 1 m; Niveau supérieur: 0 m; Largeur cadre: 0.05 m; Epaisseur cadre: 0.1 m; Epaisseur panneaux: 0.04 m; Dépass.ouverture à droite: 0 m; Dépass.ouverture supérieur: 0 m; Dépass.ouverture inférieur: 0 m; Dépass.ouverture gauche: 0 m
Por-019 | NIVEAU BAS GYMNASE | 2.05 | 0.78 | Por-019 | NIVEAU BAS GYMNASE | 0.Importation IFC | Porte (Mur) 26 | Hachure solide 3821565075 | 0,78x2,05 | 0,78x2,05x0,02 | -0.02 | -0.02 | 3.67103 | 0.032104 | 2.03 | 1.5834 | 1.599 | 0.03198 | 0.02 | AC_Pset_Porte_(Mur)_26 - Contours Mur (0-Sans,1-Tout,2-Côté,3-Longueur): 1; Point ch.0-Non,1-2D,2-3D,3-Tous: 3; Points chauds auto. en 3D: yes; Trou reprend surface latérale de mur: no; Division de surface de trou courbée: no; Stylo du symbole: Ouvertures - Général; Angle ouverture en 2D: 90 deg; Stylo de contour: Eléments 2D - Général; Type Hachure: Sans Trame; Stylo Hachure: Fond - Couleur 1; Stylo fond hachure: Fond - Couleur 1; Stylo cadre: Eléments 2D - Général; Stylo panneaux: Eléments 2D - Général; Angle ouverture en 3D: 0 deg; Afficher arêtes de contour seulement en 3D: yes; Surface par défaut: Enduit - Blanc nature; Surface 1: Menuiserie Plastique (2); Surface 2: Peinture-16; Surface 3: Métal-Nickel; Surface 4: Métal-Fer; Surface de battant: Bois - Pin granuleux horizontal; Surface de cadre: Bois - Pin granuleux horizontal; Opération IFC (ifc_optype): 0; AC_Equantity_Porte_(Mur)_26 - Largeur: 1 m; Hauteur: 2.1 m; Hauteur appui à étage actuel: 0 m; Niveau inférieur: 1 m; Niveau supérieur: 0 m; Largeur cadre: 0.05 m; Epaisseur cadre: 0.1 m; Epaisseur panneaux: 0.04 m; Dépass.ouverture à droite: 0 m; Dépass.ouverture supérieur: 0 m; Dépass.ouverture inférieur: 0 m; Dépass.ouverture gauche: 0 m
Por-022 | NIVEAU BAS GYMNASE | 2.05 | 0.78 | Por-022 | NIVEAU BAS GYMNASE | 0.Importation IFC | Porte (Mur) 26 | Hachure solide 3821565075 | 0,78x2,05 | 0,78x2,05x0,02 | -0.02 | -0.02 | 3.67103 | 0.032104 | 2.03 | 1.5834 | 1.599 | 0.03198 | 0.02 | AC_Pset_Porte_(Mur)_26 - Contours Mur (0-Sans,1-Tout,2-Côté,3-Longueur): 1; Point ch.0-Non,1-2D,2-3D,3-Tous: 3; Points chauds auto. en 3D: yes; Trou reprend surface latérale de mur: no; Division de surface de trou courbée: no; Stylo du symbole: Ouvertures - Général; Angle ouverture en 2D: 90 deg; Stylo de contour: Eléments 2D - Général; Type Hachure: Sans Trame; Stylo Hachure: Fond - Couleur 1; Stylo fond hachure: Fond - Couleur 1; Stylo cadre: Eléments 2D - Général; Stylo panneaux: Eléments 2D - Général; Angle ouverture en 3D: 0 deg; Afficher arêtes de contour seulement en 3D: yes; Surface par défaut: Enduit - Blanc nature; Surface 1: Menuiserie Plastique (2); Surface 2: Peinture-16; Surface 3: Métal-Nickel; Surface 4: Métal-Fer; Surface de battant: Bois - Pin granuleux horizontal; Surface de cadre: Bois - Pin granuleux horizontal; Opération IFC (ifc_optype): 0; AC_Equantity_Porte_(Mur)_26 - Largeur: 1 m; Hauteur: 2.1 m; Hauteur appui à étage actuel: 0 m; Niveau inférieur: 1 m; Niveau supérieur: 0 m; Largeur cadre: 0.05 m; Epaisseur cadre: 0.1 m; Epaisseur panneaux: 0.04 m; Dépass.ouverture à droite: 0 m; Dépass.ouverture supérieur: 0 m; Dépass.ouverture inférieur: 0 m; Dépass.ouverture gauche: 0 m
Por-023 | NIVEAU BAS GYMNASE | 2.05 | 0.78 | Por-023 | NIVEAU BAS GYMNASE | 0.Importation IFC | Porte (Mur) 26 | Hachure solide 3821565075 | 0,78x2,05 | 0,78x2,05x0,02 | -0.02 | -0.02 | 3.67103 | 0.032104 | 2.03 | 1.5834 | 1.599 | 0.03198 | 0.02 | AC_Pset_Porte_(Mur)_26 - Contours Mur (0-Sans,1-Tout,2-Côté,3-Longueur): 1; Point ch.0-Non,1-2D,2-3D,3-Tous: 3; Points chauds auto. en 3D: yes; Trou reprend surface latérale de mur: no; Division de surface de trou courbée: no; Stylo du symbole: Ouvertures - Général; Angle ouverture en 2D: 90 deg; Stylo de contour: Eléments 2D - Général; Type Hachure: Sans Trame; Stylo Hachure: Fond - Couleur 1; Stylo fond hachure: Fond - Couleur 1; Stylo cadre: Eléments 2D - Général; Stylo panneaux: Eléments 2D - Général; Angle ouverture en 3D: 0 deg; Afficher arêtes de contour seulement en 3D: yes; Surface par défaut: Enduit - Blanc nature; Surface 1: Menuiserie Plastique (2); Surface 2: Peinture-16; Surface 3: Métal-Nickel; Surface 4: Métal-Fer; Surface de battant: Bois - Pin granuleux horizontal; Surface de cadre: Bois - Pin granuleux horizontal; Opération IFC (ifc_optype): 0; AC_Equantity_Porte_(Mur)_26 - Largeur: 1 m; Hauteur: 2.1 m; Hauteur appui à étage actuel: 0 m; Niveau inférieur: 1 m; Niveau supérieur: 0 m; Largeur cadre: 0.05 m; Epaisseur cadre: 0.1 m; Epaisseur panneaux: 0.04 m; Dépass.ouverture à droite: 0 m; Dépass.ouverture supérieur: 0 m; Dépass.ouverture inférieur: 0 m; Dépass.ouverture gauche: 0 m
Por-019 | NIVEAU BAS GYMNASE | 2.05 | 0.86 | Por-019 | NIVEAU BAS GYMNASE | 0.Importation IFC | Porte (Mur) 27 | Hachure solide 3821565075 | 0,86x2,05 | 0,86x2,05x0,02 | -0.02 | -0.02 | 4.00463 | 0.035358 | 2.03 | 1.7458 | 1.763 | 0.03526 | 0.02 | AC_Pset_Porte_(Mur)_27 - Contours Mur (0-Sans,1-Tout,2-Côté,3-Longueur): 1; Point ch.0-Non,1-2D,2-3D,3-Tous: 3; Points chauds auto. en 3D: yes; Trou reprend surface latérale de mur: no; Division de surface de trou courbée: no; Stylo du symbole: Ouvertures - Général; Angle ouverture en 2D: 90 deg; Stylo de contour: Eléments 2D - Général; Type Hachure: Sans Trame; Stylo Hachure: Fond - Couleur 1; Stylo fond hachure: Fond - Couleur 1; Stylo cadre: Eléments 2D - Général; Stylo panneaux: Eléments 2D - Général; Angle ouverture en 3D: 0 deg; Afficher arêtes de contour seulement en 3D: yes; Surface par défaut: Enduit - Blanc nature; Surface 1: Menuiserie Plastique (2); Surface 2: Peinture-16; Surface 3: Métal-Nickel; Surface 4: Métal-Fer; Surface de battant: Bois - Pin granuleux horizontal; Surface de cadre: Bois - Pin granuleux horizontal; Opération IFC (ifc_optype): 0; AC_Equantity_Porte_(Mur)_27 - Largeur: 1 m; Hauteur: 2.1 m; Hauteur appui à étage actuel: 0 m; Niveau inférieur: 1 m; Niveau supérieur: 0 m; Largeur cadre: 0.05 m; Epaisseur cadre: 0.1 m; Epaisseur panneaux: 0.04 m; Dépass.ouverture à droite: 0 m; Dépass.ouverture supérieur: 0 m; Dépass.ouverture inférieur: 0 m; Dépass.ouverture gauche: 0 m
Por-023 | NIVEAU BAS GYMNASE | 2.05 | 0.78 | Por-023 | NIVEAU BAS GYMNASE | 0.Importation IFC | Porte (Mur) 28 | Hachure solide 3821565075 | 0,78x2,05 | 0,78x2,05x0,02 | -0.02 | -0.02 | 3.67103 | 0.032104 | 2.03 | 1.5834 | 1.599 | 0.03198 | 0.02 | AC_Pset_Porte_(Mur)_28 - Contours Mur (0-Sans,1-Tout,2-Côté,3-Longueur): 1; Point ch.0-Non,1-2D,2-3D,3-Tous: 3; Points chauds auto. en 3D: yes; Trou reprend surface latérale de mur: no; Division de surface de trou courbée: no; Stylo du symbole: Ouvertures - Général; Angle ouverture en 2D: 90 deg; Stylo de contour: Eléments 2D - Général; Type Hachure: Sans Trame; Stylo Hachure: Fond - Couleur 1; Stylo fond hachure: Fond - Couleur 1; Stylo cadre: Eléments 2D - Général; Stylo panneaux: Eléments 2D - Général; Angle ouverture en 3D: 0 deg; Afficher arêtes de contour seulement en 3D: yes; Surface par défaut: Enduit - Blanc nature; Surface 1: Menuiserie Plastique (2); Surface 2: Peinture-16; Surface 3: Métal-Nickel; Surface 4: Métal-Fer; Surface de battant: Bois - Pin granuleux horizontal; Surface de cadre: Bois - Pin granuleux horizontal; Opération IFC (ifc_optype): 0; AC_Equantity_Porte_(Mur)_28 - Largeur: 1 m; Hauteur: 2.1 m; Hauteur appui à étage actuel: 0 m; Niveau inférieur: 1 m; Niveau supérieur: 0 m; Largeur cadre: 0.05 m; Epaisseur cadre: 0.1 m; Epaisseur panneaux: 0.04 m; Dépass.ouverture à droite: 0 m; Dépass.ouverture supérieur: 0 m; Dépass.ouverture inférieur: 0 m; Dépass.ouverture gauche: 0 m
Por-024 | NIVEAU BAS GYMNASE | 2.05 | 0.78 | Por-024 | NIVEAU BAS GYMNASE | 0.Importation IFC | Porte (Mur) 28 | Hachure solide 3821565075 | 0,78x2,05 | 0,78x2,05x0,02 | -0.02 | -0.02 | 3.67103 | 0.032104 | 2.03 | 1.5834 | 1.599 | 0.03198 | 0.02 | AC_Pset_Porte_(Mur)_28 - Contours Mur (0-Sans,1-Tout,2-Côté,3-Longueur): 1; Point ch.0-Non,1-2D,2-3D,3-Tous: 3; Points chauds auto. en 3D: yes; Trou reprend surface latérale de mur: no; Division de surface de trou courbée: no; Stylo du symbole: Ouvertures - Général; Angle ouverture en 2D: 90 deg; Stylo de contour: Eléments 2D - Général; Type Hachure: Sans Trame; Stylo Hachure: Fond - Couleur 1; Stylo fond hachure: Fond - Couleur 1; Stylo cadre: Eléments 2D - Général; Stylo panneaux: Eléments 2D - Général; Angle ouverture en 3D: 0 deg; Afficher arêtes de contour seulement en 3D: yes; Surface par défaut: Enduit - Blanc nature; Surface 1: Menuiserie Plastique (2); Surface 2: Peinture-16; Surface 3: Métal-Nickel; Surface 4: Métal-Fer; Surface de battant: Bois - Pin granuleux horizontal; Surface de cadre: Bois - Pin granuleux horizontal; Opération IFC (ifc_optype): 0; AC_Equantity_Porte_(Mur)_28 - Largeur: 1 m; Hauteur: 2.1 m; Hauteur appui à étage actuel: 0 m; Niveau inférieur: 1 m; Niveau supérieur: 0 m; Largeur cadre: 0.05 m; Epaisseur cadre: 0.1 m; Epaisseur panneaux: 0.04 m; Dépass.ouverture à droite: 0 m; Dépass.ouverture supérieur: 0 m; Dépass.ouverture inférieur: 0 m; Dépass.ouverture gauche: 0 m
Por-025 | NIVEAU BAS GYMNASE | 2.05 | 0.78 | Por-025 | NIVEAU BAS GYMNASE | 0.Importation IFC | Porte (Mur) 28 | Hachure solide 3821565075 | 0,78x2,05 | 0,78x2,05x0,02 | -0.02 | -0.02 | 3.67103 | 0.032104 | 2.03 | 1.5834 | 1.599 | 0.03198 | 0.02 | AC_Pset_Porte_(Mur)_28 - Contours Mur (0-Sans,1-Tout,2-Côté,3-Longueur): 1; Point ch.0-Non,1-2D,2-3D,3-Tous: 3; Points chauds auto. en 3D: yes; Trou reprend surface latérale de mur: no; Division de surface de trou courbée: no; Stylo du symbole: Ouvertures - Général; Angle ouverture en 2D: 90 deg; Stylo de contour: Eléments 2D - Général; Type Hachure: Sans Trame; Stylo Hachure: Fond - Couleur 1; Stylo fond hachure: Fond - Couleur 1; Stylo cadre: Eléments 2D - Général; Stylo panneaux: Eléments 2D - Général; Angle ouverture en 3D: 0 deg; Afficher arêtes de contour seulement en 3D: yes; Surface par défaut: Enduit - Blanc nature; Surface 1: Menuiserie Plastique (2); Surface 2: Peinture-16; Surface 3: Métal-Nickel; Surface 4: Métal-Fer; Surface de battant: Bois - Pin granuleux horizontal; Surface de cadre: Bois - Pin granuleux horizontal; Opération IFC (ifc_optype): 0; AC_Equantity_Porte_(Mur)_28 - Largeur: 1 m; Hauteur: 2.1 m; Hauteur appui à étage actuel: 0 m; Niveau inférieur: 1 m; Niveau supérieur: 0 m; Largeur cadre: 0.05 m; Epaisseur cadre: 0.1 m; Epaisseur panneaux: 0.04 m; Dépass.ouverture à droite: 0 m; Dépass.ouverture supérieur: 0 m; Dépass.ouverture inférieur: 0 m; Dépass.ouverture gauche: 0 m
Por-026 | NIVEAU BAS GYMNASE | 2.05 | 0.78 | Por-026 | NIVEAU BAS GYMNASE | 0.Importation IFC | Porte (Mur) 28 | Hachure solide 3821565075 | 0,78x2,05 | 0,78x2,05x0,02 | -0.02 | -0.02 | 3.67103 | 0.032104 | 2.03 | 1.5834 | 1.599 | 0.03198 | 0.02 | AC_Pset_Porte_(Mur)_28 - Contours Mur (0-Sans,1-Tout,2-Côté,3-Longueur): 1; Point ch.0-Non,1-2D,2-3D,3-Tous: 3; Points chauds auto. en 3D: yes; Trou reprend surface latérale de mur: no; Division de surface de trou courbée: no; Stylo du symbole: Ouvertures - Général; Angle ouverture en 2D: 90 deg; Stylo de contour: Eléments 2D - Général; Type Hachure: Sans Trame; Stylo Hachure: Fond - Couleur 1; Stylo fond hachure: Fond - Couleur 1; Stylo cadre: Eléments 2D - Général; Stylo panneaux: Eléments 2D - Général; Angle ouverture en 3D: 0 deg; Afficher arêtes de contour seulement en 3D: yes; Surface par défaut: Enduit - Blanc nature; Surface 1: Menuiserie Plastique (2); Surface 2: Peinture-16; Surface 3: Métal-Nickel; Surface 4: Métal-Fer; Surface de battant: Bois - Pin granuleux horizontal; Surface de cadre: Bois - Pin granuleux horizontal; Opération IFC (ifc_optype): 0; AC_Equantity_Porte_(Mur)_28 - Largeur: 1 m; Hauteur: 2.1 m; Hauteur appui à étage actuel: 0 m; Niveau inférieur: 1 m; Niveau supérieur: 0 m; Largeur cadre: 0.05 m; Epaisseur cadre: 0.1 m; Epaisseur panneaux: 0.04 m; Dépass.ouverture à droite: 0 m; Dépass.ouverture supérieur: 0 m; Dépass.ouverture inférieur: 0 m; Dépass.ouverture gauche: 0 m
4 x Por-017 | NIVEAU BAS GYMNASE | 1.87 | 0.78 | Por-017 | NIVEAU BAS GYMNASE | 0.Importation IFC | Porte (Mur) 29 | Hachure solide 3821565075 | 0,78x1,87 | 0,78x1,87x0,02 | -0.02 | -0.02 | 3.35783 | 0.029269 | 1.85 | 1.443 | 1.4586 | 0.029172 | 0.02 | AC_Pset_Porte_(Mur)_29 - Contours Mur (0-Sans,1-Tout,2-Côté,3-Longueur): 1; Point ch.0-Non,1-2D,2-3D,3-Tous: 3; Points chauds auto. en 3D: yes; Trou reprend surface latérale de mur: no; Division de surface de trou courbée: no; Stylo du symbole: Ouvertures - Général; Angle ouverture en 2D: 90 deg; Stylo de contour: Eléments 2D - Général; Type Hachure: Sans Trame; Stylo Hachure: Fond - Couleur 1; Stylo fond hachure: Fond - Couleur 1; Stylo cadre: Eléments 2D - Général; Stylo panneaux: Eléments 2D - Général; Angle ouverture en 3D: 0 deg; Afficher arêtes de contour seulement en 3D: yes; Surface par défaut: Enduit - Blanc nature; Surface 1: Menuiserie Plastique (2); Surface 2: Peinture-16; Surface 3: Métal-Nickel; Surface 4: Métal-Fer; Surface de battant: Bois - Pin granuleux horizontal; Surface de cadre: Bois - Pin granuleux horizontal; Opération IFC (ifc_optype): 0; AC_Equantity_Porte_(Mur)_29 - Largeur: 1 m; Hauteur: 2.1 m; Hauteur appui à étage actuel: 0 m; Niveau inférieur: 1 m; Niveau supérieur: 0 m; Largeur cadre: 0.05 m; Epaisseur cadre: 0.1 m; Epaisseur panneaux: 0.04 m; Dépass.ouverture à droite: 0 m; Dépass.ouverture supérieur: 0 m; Dépass.ouverture inférieur: 0 m; Dépass.ouverture gauche: 0 m
2 x Por-018 | NIVEAU BAS GYMNASE | 1.87 | 0.78 | Por-018 | NIVEAU BAS GYMNASE | 0.Importation IFC | Porte (Mur) 29 | Hachure solide 3821565075 | 0,78x1,87 | 0,78x1,87x0,02 | -0.02 | -0.02 | 3.35783 | 0.029269 | 1.85 | 1.443 | 1.4586 | 0.029172 | 0.02 | AC_Pset_Porte_(Mur)_29 - Contours Mur (0-Sans,1-Tout,2-Côté,3-Longueur): 1; Point ch.0-Non,1-2D,2-3D,3-Tous: 3; Points chauds auto. en 3D: yes; Trou reprend surface latérale de mur: no; Division de surface de trou courbée: no; Stylo du symbole: Ouvertures - Général; Angle ouverture en 2D: 90 deg; Stylo de contour: Eléments 2D - Général; Type Hachure: Sans Trame; Stylo Hachure: Fond - Couleur 1; Stylo fond hachure: Fond - Couleur 1; Stylo cadre: Eléments 2D - Général; Stylo panneaux: Eléments 2D - Général; Angle ouverture en 3D: 0 deg; Afficher arêtes de contour seulement en 3D: yes; Surface par défaut: Enduit - Blanc nature; Surface 1: Menuiserie Plastique (2); Surface 2: Peinture-16; Surface 3: Métal-Nickel; Surface 4: Métal-Fer; Surface de battant: Bois - Pin granuleux horizontal; Surface de cadre: Bois - Pin granuleux horizontal; Opération IFC (ifc_optype): 0; AC_Equantity_Porte_(Mur)_29 - Largeur: 1 m; Hauteur: 2.1 m; Hauteur appui à étage actuel: 0 m; Niveau inférieur: 1 m; Niveau supérieur: 0 m; Largeur cadre: 0.05 m; Epaisseur cadre: 0.1 m; Epaisseur panneaux: 0.04 m; Dépass.ouverture à droite: 0 m; Dépass.ouverture supérieur: 0 m; Dépass.ouverture inférieur: 0 m; Dépass.ouverture gauche: 0 m
2 x Por-019 | NIVEAU BAS GYMNASE | 1.87 | 0.78 | Por-019 | NIVEAU BAS GYMNASE | 0.Importation IFC | Porte (Mur) 29 | Hachure solide 3821565075 | 0,78x1,87 | 0,78x1,87x0,02 | -0.02 | -0.02 | 3.35783 | 0.029269 | 1.85 | 1.443 | 1.4586 | 0.029172 | 0.02 | AC_Pset_Porte_(Mur)_29 - Contours Mur (0-Sans,1-Tout,2-Côté,3-Longueur): 1; Point ch.0-Non,1-2D,2-3D,3-Tous: 3; Points chauds auto. en 3D: yes; Trou reprend surface latérale de mur: no; Division de surface de trou courbée: no; Stylo du symbole: Ouvertures - Général; Angle ouverture en 2D: 90 deg; Stylo de contour: Eléments 2D - Général; Type Hachure: Sans Trame; Stylo Hachure: Fond - Couleur 1; Stylo fond hachure: Fond - Couleur 1; Stylo cadre: Eléments 2D - Général; Stylo panneaux: Eléments 2D - Général; Angle ouverture en 3D: 0 deg; Afficher arêtes de contour seulement en 3D: yes; Surface par défaut: Enduit - Blanc nature; Surface 1: Menuiserie Plastique (2); Surface 2: Peinture-16; Surface 3: Métal-Nickel; Surface 4: Métal-Fer; Surface de battant: Bois - Pin granuleux horizontal; Surface de cadre: Bois - Pin granuleux horizontal; Opération IFC (ifc_optype): 0; AC_Equantity_Porte_(Mur)_29 - Largeur: 1 m; Hauteur: 2.1 m; Hauteur appui à étage actuel: 0 m; Niveau inférieur: 1 m; Niveau supérieur: 0 m; Largeur cadre: 0.05 m; Epaisseur cadre: 0.1 m; Epaisseur panneaux: 0.04 m; Dépass.ouverture à droite: 0 m; Dépass.ouverture supérieur: 0 m; Dépass.ouverture inférieur: 0 m; Dépass.ouverture gauche: 0 m
Por-018 | NIVEAU BAS GYMNASE | 1.87 | 0.86 | Por-018 | NIVEAU BAS GYMNASE | 0.Importation IFC | Porte (Mur) 30 | Hachure solide 3821565075 | 0,86x1,87 | 0,86x1,87x0,02 | -0.02 | -0.02 | 3.66263 | 0.032235 | 1.85 | 1.591 | 1.6082 | 0.032164 | 0.02 | AC_Pset_Porte_(Mur)_30 - Contours Mur (0-Sans,1-Tout,2-Côté,3-Longueur): 1; Point ch.0-Non,1-2D,2-3D,3-Tous: 3; Points chauds auto. en 3D: yes; Trou reprend surface latérale de mur: no; Division de surface de trou courbée: no; Stylo du symbole: Ouvertures - Général; Angle ouverture en 2D: 90 deg; Stylo de contour: Eléments 2D - Général; Type Hachure: Sans Trame; Stylo Hachure: Fond - Couleur 1; Stylo fond hachure: Fond - Couleur 1; Stylo cadre: Eléments 2D - Général; Stylo panneaux: Eléments 2D - Général; Angle ouverture en 3D: 0 deg; Afficher arêtes de contour seulement en 3D: yes; Surface par défaut: Enduit - Blanc nature; Surface 1: Menuiserie Plastique (2); Surface 2: Peinture-16; Surface 3: Métal-Nickel; Surface 4: Métal-Fer; Surface de battant: Bois - Pin granuleux horizontal; Surface de cadre: Bois - Pin granuleux horizontal; Opération IFC (ifc_optype): 0; AC_Equantity_Porte_(Mur)_30 - Largeur: 1 m; Hauteur: 2.1 m; Hauteur appui à étage actuel: 0 m; Niveau inférieur: 1 m; Niveau supérieur: 0 m; Largeur cadre: 0.05 m; Epaisseur cadre: 0.1 m; Epaisseur panneaux: 0.04 m; Dépass.ouverture à droite: 0 m; Dépass.ouverture supérieur: 0 m; Dépass.ouverture inférieur: 0 m; Dépass.ouverture gauche: 0 m
4 x Por-017 | NIVEAU BAS GYMNASE | 1.87 | 0.78 | Por-017 | NIVEAU BAS GYMNASE | 0.Importation IFC | Porte (Mur) 31 | Hachure solide 3821565075 | 0,78x1,87 | 0,78x1,87x0,02 | -0.02 | -0.02 | 3.35783 | 0.029269 | 1.85 | 1.443 | 1.4586 | 0.029172 | 0.02 | AC_Pset_Porte_(Mur)_31 - Contours Mur (0-Sans,1-Tout,2-Côté,3-Longueur): 1; Point ch.0-Non,1-2D,2-3D,3-Tous: 3; Points chauds auto. en 3D: yes; Trou reprend surface latérale de mur: no; Division de surface de trou courbée: no; Stylo du symbole: Ouvertures - Général; Angle ouverture en 2D: 90 deg; Stylo de contour: Eléments 2D - Général; Type Hachure: Sans Trame; Stylo Hachure: Fond - Couleur 1; Stylo fond hachure: Fond - Couleur 1; Stylo cadre: Eléments 2D - Général; Stylo panneaux: Eléments 2D - Général; Angle ouverture en 3D: 0 deg; Afficher arêtes de contour seulement en 3D: yes; Surface par défaut: Enduit - Blanc nature; Surface 1: Menuiserie Plastique (2); Surface 2: Peinture-16; Surface 3: Métal-Nickel; Surface 4: Métal-Fer; Surface de battant: Bois - Pin granuleux horizontal; Surface de cadre: Bois - Pin granuleux horizontal; Opération IFC (ifc_optype): 0; AC_Equantity_Porte_(Mur)_31 - Largeur: 1 m; Hauteur: 2.1 m; Hauteur appui à étage actuel: 0 m; Niveau inférieur: 1 m; Niveau supérieur: 0 m; Largeur cadre: 0.05 m; Epaisseur cadre: 0.1 m; Epaisseur panneaux: 0.04 m; Dépass.ouverture à droite: 0 m; Dépass.ouverture supérieur: 0 m; Dépass.ouverture inférieur: 0 m; Dépass.ouverture gauche: 0 m
2 x Por-018 | NIVEAU BAS GYMNASE | 1.87 | 0.78 | Por-018 | NIVEAU BAS GYMNASE | 0.Importation IFC | Porte (Mur) 31 | Hachure solide 3821565075 | 0,78x1,87 | 0,78x1,87x0,02 | -0.02 | -0.02 | 3.35783 | 0.029269 | 1.85 | 1.443 | 1.4586 | 0.029172 | 0.02 | AC_Pset_Porte_(Mur)_31 - Contours Mur (0-Sans,1-Tout,2-Côté,3-Longueur): 1; Point ch.0-Non,1-2D,2-3D,3-Tous: 3; Points chauds auto. en 3D: yes; Trou reprend surface latérale de mur: no; Division de surface de trou courbée: no; Stylo du symbole: Ouvertures - Général; Angle ouverture en 2D: 90 deg; Stylo de contour: Eléments 2D - Général; Type Hachure: Sans Trame; Stylo Hachure: Fond - Couleur 1; Stylo fond hachure: Fond - Couleur 1; Stylo cadre: Eléments 2D - Général; Stylo panneaux: Eléments 2D - Général; Angle ouverture en 3D: 0 deg; Afficher arêtes de contour seulement en 3D: yes; Surface par défaut: Enduit - Blanc nature; Surface 1: Menuiserie Plastique (2); Surface 2: Peinture-16; Surface 3: Métal-Nickel; Surface 4: Métal-Fer; Surface de battant: Bois - Pin granuleux horizontal; Surface de cadre: Bois - Pin granuleux horizontal; Opération IFC (ifc_optype): 0; AC_Equantity_Porte_(Mur)_31 - Largeur: 1 m; Hauteur: 2.1 m; Hauteur appui à étage actuel: 0 m; Niveau inférieur: 1 m; Niveau supérieur: 0 m; Largeur cadre: 0.05 m; Epaisseur cadre: 0.1 m; Epaisseur panneaux: 0.04 m; Dépass.ouverture à droite: 0 m; Dépass.ouverture supérieur: 0 m; Dépass.ouverture inférieur: 0 m; Dépass.ouverture gauche: 0 m
2 x Por-019 | NIVEAU BAS GYMNASE | 1.87 | 0.78 | Por-019 | NIVEAU BAS GYMNASE | 0.Importation IFC | Porte (Mur) 31 | Hachure solide 3821565075 | 0,78x1,87 | 0,78x1,87x0,02 | -0.02 | -0.02 | 3.35783 | 0.029269 | 1.85 | 1.443 | 1.4586 | 0.029172 | 0.02 | AC_Pset_Porte_(Mur)_31 - Contours Mur (0-Sans,1-Tout,2-Côté,3-Longueur): 1; Point ch.0-Non,1-2D,2-3D,3-Tous: 3; Points chauds auto. en 3D: yes; Trou reprend surface latérale de mur: no; Division de surface de trou courbée: no; Stylo du symbole: Ouvertures - Général; Angle ouverture en 2D: 90 deg; Stylo de contour: Eléments 2D - Général; Type Hachure: Sans Trame; Stylo Hachure: Fond - Couleur 1; Stylo fond hachure: Fond - Couleur 1; Stylo cadre: Eléments 2D - Général; Stylo panneaux: Eléments 2D - Général; Angle ouverture en 3D: 0 deg; Afficher arêtes de contour seulement en 3D: yes; Surface par défaut: Enduit - Blanc nature; Surface 1: Menuiserie Plastique (2); Surface 2: Peinture-16; Surface 3: Métal-Nickel; Surface 4: Métal-Fer; Surface de battant: Bois - Pin granuleux horizontal; Surface de cadre: Bois - Pin granuleux horizontal; Opération IFC (ifc_optype): 0; AC_Equantity_Porte_(Mur)_31 - Largeur: 1 m; Hauteur: 2.1 m; Hauteur appui à étage actuel: 0 m; Niveau inférieur: 1 m; Niveau supérieur: 0 m; Largeur cadre: 0.05 m; Epaisseur cadre: 0.1 m; Epaisseur panneaux: 0.04 m; Dépass.ouverture à droite: 0 m; Dépass.ouverture supérieur: 0 m; Dépass.ouverture inférieur: 0 m; Dépass.ouverture gauche: 0 m
Por-020 | NIVEAU BAS GYMNASE | 1.87 | 0.86 | Por-020 | NIVEAU BAS GYMNASE | 0.Importation IFC | Porte (Mur) 32 | Hachure solide 3821565075 | 0,86x1,87 | 0,86x1,87x0,02 | -0.02 | -0.02 | 3.66263 | 0.032235 | 1.85 | 1.591 | 1.6082 | 0.032164 | 0.02 | AC_Pset_Porte_(Mur)_32 - Contours Mur (0-Sans,1-Tout,2-Côté,3-Longueur): 1; Point ch.0-Non,1-2D,2-3D,3-Tous: 3; Points chauds auto. en 3D: yes; Trou reprend surface latérale de mur: no; Division de surface de trou courbée: no; Stylo du symbole: Ouvertures - Général; Angle ouverture en 2D: 90 deg; Stylo de contour: Eléments 2D - Général; Type Hachure: Sans Trame; Stylo Hachure: Fond - Couleur 1; Stylo fond hachure: Fond - Couleur 1; Stylo cadre: Eléments 2D - Général; Stylo panneaux: Eléments 2D - Général; Angle ouverture en 3D: 0 deg; Afficher arêtes de contour seulement en 3D: yes; Surface par défaut: Enduit - Blanc nature; Surface 1: Menuiserie Plastique (2); Surface 2: Peinture-16; Surface 3: Métal-Nickel; Surface 4: Métal-Fer; Surface de battant: Bois - Pin granuleux horizontal; Surface de cadre: Bois - Pin granuleux horizontal; Opération IFC (ifc_optype): 0; AC_Equantity_Porte_(Mur)_32 - Largeur: 1 m; Hauteur: 2.1 m; Hauteur appui à étage actuel: 0 m; Niveau inférieur: 1 m; Niveau supérieur: 0 m; Largeur cadre: 0.05 m; Epaisseur cadre: 0.1 m; Epaisseur panneaux: 0.04 m; Dépass.ouverture à droite: 0 m; Dépass.ouverture supérieur: 0 m; Dépass.ouverture inférieur: 0 m; Dépass.ouverture gauche: 0 m
Por-019 | NIVEAU BAS GYMNASE | 1.87 | 0.86 | Por-019 | NIVEAU BAS GYMNASE | 0.Importation IFC | Porte (Mur) 30 | Hachure solide 3821565075 | 0,86x1,87 | 0,86x1,87x0,02 | -0.02 | -0.02 | 3.66263 | 0.032235 | 1.85 | 1.591 | 1.6082 | 0.032164 | 0.02 | AC_Pset_Porte_(Mur)_30 - Contours Mur (0-Sans,1-Tout,2-Côté,3-Longueur): 1; Point ch.0-Non,1-2D,2-3D,3-Tous: 3; Points chauds auto. en 3D: yes; Trou reprend surface latérale de mur: no; Division de surface de trou courbée: no; Stylo du symbole: Ouvertures - Général; Angle ouverture en 2D: 90 deg; Stylo de contour: Eléments 2D - Général; Type Hachure: Sans Trame; Stylo Hachure: Fond - Couleur 1; Stylo fond hachure: Fond - Couleur 1; Stylo cadre: Eléments 2D - Général; Stylo panneaux: Eléments 2D - Général; Angle ouverture en 3D: 0 deg; Afficher arêtes de contour seulement en 3D: yes; Surface par défaut: Enduit - Blanc nature; Surface 1: Menuiserie Plastique (2); Surface 2: Peinture-16; Surface 3: Métal-Nickel; Surface 4: Métal-Fer; Surface de battant: Bois - Pin granuleux horizontal; Surface de cadre: Bois - Pin granuleux horizontal; Opération IFC (ifc_optype): 0; AC_Equantity_Porte_(Mur)_30 - Largeur: 1 m; Hauteur: 2.1 m; Hauteur appui à étage actuel: 0 m; Niveau inférieur: 1 m; Niveau supérieur: 0 m; Largeur cadre: 0.05 m; Epaisseur cadre: 0.1 m; Epaisseur panneaux: 0.04 m; Dépass.ouverture à droite: 0 m; Dépass.ouverture supérieur: 0 m; Dépass.ouverture inférieur: 0 m; Dépass.ouverture gauche: 0 m
Por-019 | NIVEAU BAS GYMNASE | 1.87 | 0.86 | Por-019 | NIVEAU BAS GYMNASE | 0.Importation IFC | Porte (Mur) 32 | Hachure solide 3821565075 | 0,86x1,87 | 0,86x1,87x0,02 | -0.02 | -0.02 | 3.66263 | 0.032235 | 1.85 | 1.591 | 1.6082 | 0.032164 | 0.02 | AC_Pset_Porte_(Mur)_32 - Contours Mur (0-Sans,1-Tout,2-Côté,3-Longueur): 1; Point ch.0-Non,1-2D,2-3D,3-Tous: 3; Points chauds auto. en 3D: yes; Trou reprend surface latérale de mur: no; Division de surface de trou courbée: no; Stylo du symbole: Ouvertures - Général; Angle ouverture en 2D: 90 deg; Stylo de contour: Eléments 2D - Général; Type Hachure: Sans Trame; Stylo Hachure: Fond - Couleur 1; Stylo fond hachure: Fond - Couleur 1; Stylo cadre: Eléments 2D - Général; Stylo panneaux: Eléments 2D - Général; Angle ouverture en 3D: 0 deg; Afficher arêtes de contour seulement en 3D: yes; Surface par défaut: Enduit - Blanc nature; Surface 1: Menuiserie Plastique (2); Surface 2: Peinture-16; Surface 3: Métal-Nickel; Surface 4: Métal-Fer; Surface de battant: Bois - Pin granuleux horizontal; Surface de cadre: Bois - Pin granuleux horizontal; Opération IFC (ifc_optype): 0; AC_Equantity_Porte_(Mur)_32 - Largeur: 1 m; Hauteur: 2.1 m; Hauteur appui à étage actuel: 0 m; Niveau inférieur: 1 m; Niveau supérieur: 0 m; Largeur cadre: 0.05 m; Epaisseur cadre: 0.1 m; Epaisseur panneaux: 0.04 m; Dépass.ouverture à droite: 0 m; Dépass.ouverture supérieur: 0 m; Dépass.ouverture inférieur: 0 m; Dépass.ouverture gauche: 0 m
Por-019 | NIVEAU HAUT ENTRÉE | 2.06 | 0.75 | Por-019 | NIVEAU HAUT ENTRÉE | Murs Ext: Périphériques.Importation IFC | Porte (Mur) 34 | Hachure solide* 3962059836 | 0,75x2,06 | 0,75x2,06x0,10 | 3 | 0 | 4.40903 | 0.0674207 | 2.06 | 1.545 | 1.545 | 0.1545 | 0.1 | ArchiCADProperties - Nom de Zone: Hall d'Entrée; Numéro de Zone: 010; De Zone: Hall d'Entrée; De la Zone numéro: 010; AC_Pset_Porte_(Mur)_34 - Contours Mur (0-Sans,1-Tout,2-Côté,3-Longueur): 1; Point ch.0-Non,1-2D,2-3D,3-Tous: 3; Points chauds auto. en 3D: yes; Trou reprend surface latérale de mur: no; Division de surface de trou courbée: no; Stylo du symbole: Ouvertures - Général; Angle ouverture en 2D: 90 deg; Stylo de contour: Eléments 2D - Général; Type Hachure: Sans Trame; Stylo Hachure: Fond - Couleur 1; Stylo fond hachure: Fond - Couleur 1; Stylo cadre: Eléments 2D - Général; Stylo panneaux: Eléments 2D - Général; Angle ouverture en 3D: 0 deg; Afficher arêtes de contour seulement en 3D: yes; Surface par défaut: Enduit - Blanc nature; Surface 1: Menuiserie Plastique (2); Surface 2: Peinture-16; Surface 3: Métal-Nickel; Surface 4: Métal-Fer; Surface de battant: Bois - Pin granuleux horizontal; Surface de cadre: Bois - Pin granuleux horizontal; Opération IFC (ifc_optype): 0; AC_Equantity_Porte_(Mur)_34 - Largeur: 1 m; Hauteur: 2.1 m; Hauteur appui à étage actuel: 0 m; Niveau inférieur: 1 m; Niveau supérieur: 0 m; Largeur cadre: 0.05 m; Epaisseur cadre: 0.1 m; Epaisseur panneaux: 0.04 m; Dépass.ouverture à droite: 0 m; Dépass.ouverture supérieur: 0 m; Dépass.ouverture inférieur: 0 m; Dépass.ouverture gauche: 0 m
Por-017 | NIVEAU HAUT ENTRÉE | 2.06 | 0.8 | Por-017 | NIVEAU HAUT ENTRÉE | Murs Ext: Périphériques.Importation IFC | Porte (Mur) 35 | Hachure solide* 3962059836 | 0,80x2,06 | 0,80x2,06x0,10 | 3 | 0 | 4.62953 | 0.070732 | 2.06 | 1.648 | 1.648 | 0.1648 | 0.1 | ArchiCADProperties - Nom de Zone: Hall d'Entrée; Numéro de Zone: 010; De Zone: Hall d'Entrée; De la Zone numéro: 010; AC_Pset_Porte_(Mur)_35 - Contours Mur (0-Sans,1-Tout,2-Côté,3-Longueur): 1; Point ch.0-Non,1-2D,2-3D,3-Tous: 3; Points chauds auto. en 3D: yes; Trou reprend surface latérale de mur: no; Division de surface de trou courbée: no; Stylo du symbole: Ouvertures - Général; Angle ouverture en 2D: 90 deg; Stylo de contour: Eléments 2D - Général; Type Hachure: Sans Trame; Stylo Hachure: Fond - Couleur 1; Stylo fond hachure: Fond - Couleur 1; Stylo cadre: Eléments 2D - Général; Stylo panneaux: Eléments 2D - Général; Angle ouverture en 3D: 0 deg; Afficher arêtes de contour seulement en 3D: yes; Surface par défaut: Enduit - Blanc nature; Surface 1: Menuiserie Plastique (2); Surface 2: Peinture-16; Surface 3: Métal-Nickel; Surface 4: Métal-Fer; Surface de battant: Bois - Pin granuleux horizontal; Surface de cadre: Bois - Pin granuleux horizontal; Opération IFC (ifc_optype): 0; AC_Equantity_Porte_(Mur)_35 - Largeur: 1 m; Hauteur: 2.1 m; Hauteur appui à étage actuel: 0 m; Niveau inférieur: 1 m; Niveau supérieur: 0 m; Largeur cadre: 0.05 m; Epaisseur cadre: 0.1 m; Epaisseur panneaux: 0.04 m; Dépass.ouverture à droite: 0 m; Dépass.ouverture supérieur: 0 m; Dépass.ouverture inférieur: 0 m; Dépass.ouverture gauche: 0 m
Por-018 | NIVEAU HAUT ENTRÉE | 2.06 | 0.72 | Por-018 | NIVEAU HAUT ENTRÉE | Murs Ext: Périphériques.Importation IFC | Porte (Mur) 36 | Hachure solide* 3962059836 | 0,72x2,06 | 0,72x2,06x0,10 | 3 | 0 | 4.27673 | 0.065434 | 2.06 | 1.4832 | 1.4832 | 0.14832 | 0.1 | ArchiCADProperties - Nom de Zone: Hall d'Entrée; Numéro de Zone: 010; De Zone: Hall d'Entrée; De la Zone numéro: 010; AC_Pset_Porte_(Mur)_36 - Contours Mur (0-Sans,1-Tout,2-Côté,3-Longueur): 1; Point ch.0-Non,1-2D,2-3D,3-Tous: 3; Points chauds auto. en 3D: yes; Trou reprend surface latérale de mur: no; Division de surface de trou courbée: no; Stylo du symbole: Ouvertures - Général; Angle ouverture en 2D: 90 deg; Stylo de contour: Eléments 2D - Général; Type Hachure: Sans Trame; Stylo Hachure: Fond - Couleur 1; Stylo fond hachure: Fond - Couleur 1; Stylo cadre: Eléments 2D - Général; Stylo panneaux: Eléments 2D - Général; Angle ouverture en 3D: 0 deg; Afficher arêtes de contour seulement en 3D: yes; Surface par défaut: Enduit - Blanc nature; Surface 1: Menuiserie Plastique (2); Surface 2: Peinture-16; Surface 3: Métal-Nickel; Surface 4: Métal-Fer; Surface de battant: Bois - Pin granuleux horizontal; Surface de cadre: Bois - Pin granuleux horizontal; Opération IFC (ifc_optype): 0; AC_Equantity_Porte_(Mur)_36 - Largeur: 1 m; Hauteur: 2.1 m; Hauteur appui à étage actuel: 0 m; Niveau inférieur: 1 m; Niveau supérieur: 0 m; Largeur cadre: 0.05 m; Epaisseur cadre: 0.1 m; Epaisseur panneaux: 0.04 m; Dépass.ouverture à droite: 0 m; Dépass.ouverture supérieur: 0 m; Dépass.ouverture inférieur: 0 m; Dépass.ouverture gauche: 0 m
Por-019 | NIVEAU HAUT ENTRÉE | 2.05 | 0.96 | Por-019 | NIVEAU HAUT ENTRÉE | Murs Ext: Périphériques.Importation IFC | Porte (Mur) 37 | Hachure solide* 3962059836 | 0,96x2,05 | 0,96x2,05x0,10 | 2.98 | -0.02 | 5.28213 | 0.070117 | 2.03 | 1.9488 | 1.968 | 0.1968 | 0.1 | ArchiCADProperties - Nom de Zone: Sanit Visit. F; Numéro de Zone: 010; De Zone: Hall d'Entrée; De la Zone numéro: 010; AC_Pset_Porte_(Mur)_37 - Contours Mur (0-Sans,1-Tout,2-Côté,3-Longueur): 1; Point ch.0-Non,1-2D,2-3D,3-Tous: 3; Points chauds auto. en 3D: yes; Trou reprend surface latérale de mur: no; Division de surface de trou courbée: no; Stylo du symbole: Ouvertures - Général; Angle ouverture en 2D: 90 deg; Stylo de contour: Eléments 2D - Général; Type Hachure: Sans Trame; Stylo Hachure: Fond - Couleur 1; Stylo fond hachure: Fond - Couleur 1; Stylo cadre: Eléments 2D - Général; Stylo panneaux: Eléments 2D - Général; Angle ouverture en 3D: 0 deg; Afficher arêtes de contour seulement en 3D: yes; Surface par défaut: Enduit - Blanc nature; Surface 1: Menuiserie Plastique (2); Surface 2: Peinture-16; Surface 3: Métal-Nickel; Surface 4: Métal-Fer; Surface de battant: Bois - Pin granuleux horizontal; Surface de cadre: Bois - Pin granuleux horizontal; Opération IFC (ifc_optype): 0; AC_Equantity_Porte_(Mur)_37 - Largeur: 1 m; Hauteur: 2.1 m; Hauteur appui à étage actuel: 0 m; Niveau inférieur: 1 m; Niveau supérieur: 0 m; Largeur cadre: 0.05 m; Epaisseur cadre: 0.1 m; Epaisseur panneaux: 0.04 m; Dépass.ouverture à droite: 0 m; Dépass.ouverture supérieur: 0 m; Dépass.ouverture inférieur: 0 m; Dépass.ouverture gauche: 0 m
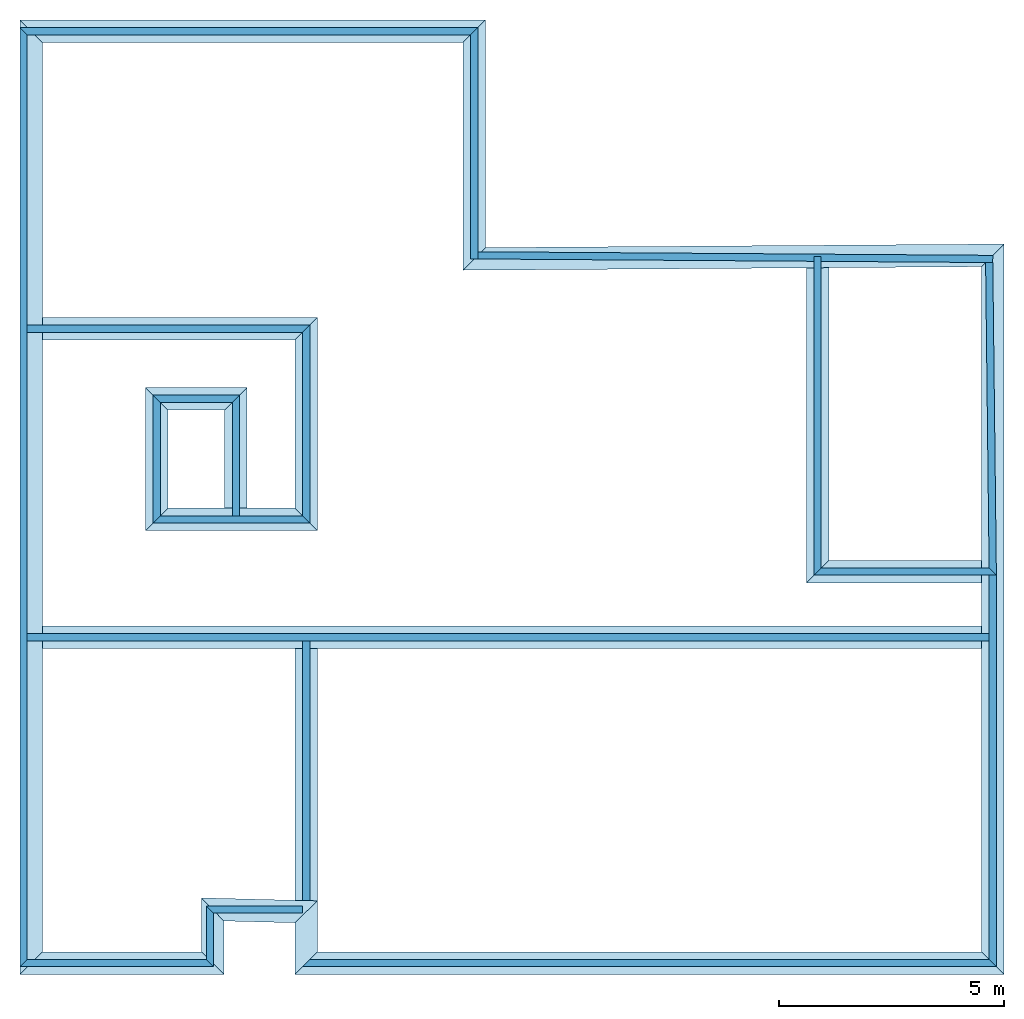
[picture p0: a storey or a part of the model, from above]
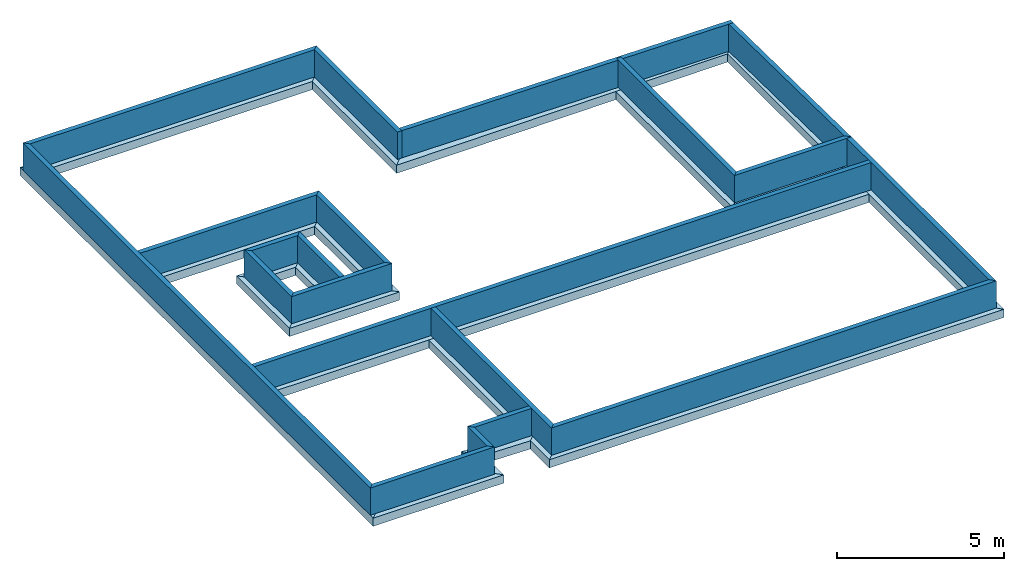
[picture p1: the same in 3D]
Properties of the parts of a building model (IFC2X3), part 3 of 6

# IfcDoor: Porte int 1v (55)
Name | In | OverallHeight (m) = ArchiCADQuantities, Hauteur (m) = Hauteur nominale de l'ouverture côté ébrasure (m) = Hauteur nominale de l'ouverture côté opposée ébrasure (m) | OverallWidth (m) = ArchiCADQuantities, Largeur (m) = Largeur ouverture côté ébrasure (m) = Largeur ouverture côté opposé ébrasure (m) = Largeur nominale de l'ouverture côté ébrasure (m) = Largeur nominale de l'ouverture côté opposée ébrasure (m) | ID Elément entier = ID Elément compact | Etage d'implantation | Calque | Nom Elément de Bibliothèque | Structure mur | Taille L x H nominale | Taille L x H x E nominale | Altitude à Zéro du Projet (m) | Altitude à étage (m) = Hauteur nominale seuil (m) = Valeur Appui ou Linteau (m) | Superficie de surface (m2) | Volume net (m3) = Volume ouverture (m3) | Hauteur nominale linteau (m) = Hauteur linteau côté ébrasure (m) = Hauteur linteau côté opposé ébrasure (m) = Hauteur ouverture côté ébrasure (m) = Hauteur ouverture côté opposé ébrasure (m) | Surface ouverture côté ébrasure (m2) = Surface ouverture côté opposé ébrasure (m2) | Surface nominale de l'ouverture P/F côté ébrasure (m2) = Surface nominale de l'ouverture P/F côté opposé ébrasure (m2) = Surface nominale ouverture P/F (m2) | Volume nominal ouverture (m3) | Epaisseur de Mur (m)
Por-021 | NIVEAU HAUT ENTRÉE | 2.05 | 0.96 | Por-021 | NIVEAU HAUT ENTRÉE | Murs Ext: Périphériques.Importation IFC | Porte (Mur) 37 | Hachure solide* 3962059836 | 0,96x2,05 | 0,96x2,05x0,10 | 2.98 | -0.02 | 5.28213 | 0.070117 | 2.03 | 1.9488 | 1.968 | 0.1968 | 0.1 | ArchiCADProperties - Nom de Zone: Sanit Visit. H; Numéro de Zone: 010; De Zone: Hall d'Entrée; De la Zone numéro: 010; AC_Pset_Porte_(Mur)_37 - Contours Mur (0-Sans,1-Tout,2-Côté,3-Longueur): 1; Point ch.0-Non,1-2D,2-3D,3-Tous: 3; Points chauds auto. en 3D: yes; Trou reprend surface latérale de mur: no; Division de surface de trou courbée: no; Stylo du symbole: Ouvertures - Général; Angle ouverture en 2D: 90 deg; Stylo de contour: Eléments 2D - Général; Type Hachure: Sans Trame; Stylo Hachure: Fond - Couleur 1; Stylo fond hachure: Fond - Couleur 1; Stylo cadre: Eléments 2D - Général; Stylo panneaux: Eléments 2D - Général; Angle ouverture en 3D: 0 deg; Afficher arêtes de contour seulement en 3D: yes; Surface par défaut: Enduit - Blanc nature; Surface 1: Menuiserie Plastique (2); Surface 2: Peinture-16; Surface 3: Métal-Nickel; Surface 4: Métal-Fer; Surface de battant: Bois - Pin granuleux horizontal; Surface de cadre: Bois - Pin granuleux horizontal; Opération IFC (ifc_optype): 0; AC_Equantity_Porte_(Mur)_37 - Largeur: 1 m; Hauteur: 2.1 m; Hauteur appui à étage actuel: 0 m; Niveau inférieur: 1 m; Niveau supérieur: 0 m; Largeur cadre: 0.05 m; Epaisseur cadre: 0.1 m; Epaisseur panneaux: 0.04 m; Dépass.ouverture à droite: 0 m; Dépass.ouverture supérieur: 0 m; Dépass.ouverture inférieur: 0 m; Dépass.ouverture gauche: 0 m
Por-019 | NIVEAU HAUT ENTRÉE | 2.05 | 0.96 | Por-019 | NIVEAU HAUT ENTRÉE | Murs Ext: Périphériques.Importation IFC | Porte (Mur) 38 | Hachure solide* 3962059836 | 0,96x2,05 | 0,96x2,05x0,10 | 2.98 | -0.02 | 5.28213 | 0.070117 | 2.03 | 1.9488 | 1.968 | 0.1968 | 0.1 | ArchiCADProperties - Nom de Zone: Dépot; Numéro de Zone: 010; De Zone: Hall d'Entrée; De la Zone numéro: 010; AC_Pset_Porte_(Mur)_38 - Contours Mur (0-Sans,1-Tout,2-Côté,3-Longueur): 1; Point ch.0-Non,1-2D,2-3D,3-Tous: 3; Points chauds auto. en 3D: yes; Trou reprend surface latérale de mur: no; Division de surface de trou courbée: no; Stylo du symbole: Ouvertures - Général; Angle ouverture en 2D: 90 deg; Stylo de contour: Eléments 2D - Général; Type Hachure: Sans Trame; Stylo Hachure: Fond - Couleur 1; Stylo fond hachure: Fond - Couleur 1; Stylo cadre: Eléments 2D - Général; Stylo panneaux: Eléments 2D - Général; Angle ouverture en 3D: 0 deg; Afficher arêtes de contour seulement en 3D: yes; Surface par défaut: Enduit - Blanc nature; Surface 1: Menuiserie Plastique (2); Surface 2: Peinture-16; Surface 3: Métal-Nickel; Surface 4: Métal-Fer; Surface de battant: Bois - Pin granuleux horizontal; Surface de cadre: Bois - Pin granuleux horizontal; Opération IFC (ifc_optype): 0; AC_Equantity_Porte_(Mur)_38 - Largeur: 1 m; Hauteur: 2.1 m; Hauteur appui à étage actuel: 0 m; Niveau inférieur: 1 m; Niveau supérieur: 0 m; Largeur cadre: 0.05 m; Epaisseur cadre: 0.1 m; Epaisseur panneaux: 0.04 m; Dépass.ouverture à droite: 0 m; Dépass.ouverture supérieur: 0 m; Dépass.ouverture inférieur: 0 m; Dépass.ouverture gauche: 0 m
Por-018 | NIVEAU HAUT ENTRÉE | 2.05 | 0.96 | Por-018 | NIVEAU HAUT ENTRÉE | Murs Ext: Périphériques.Importation IFC | Porte (Mur) 39 | Hachure solide* 3962059836 | 0,96x2,05 | 0,96x2,05x0,16 | 2.98 | -0.02 | 5.88334 | 0.0790821 | 2.03 | 1.9488 | 1.968 | 0.31488 | 0.16 | ArchiCADProperties - Nom de Zone: Hall d'Entrée; Numéro de Zone: 010; De Zone: Hall d'Entrée; De la Zone numéro: 010; AC_Pset_Porte_(Mur)_39 - Contours Mur (0-Sans,1-Tout,2-Côté,3-Longueur): 1; Point ch.0-Non,1-2D,2-3D,3-Tous: 3; Points chauds auto. en 3D: yes; Trou reprend surface latérale de mur: no; Division de surface de trou courbée: no; Stylo du symbole: Ouvertures - Général; Angle ouverture en 2D: 90 deg; Stylo de contour: Eléments 2D - Général; Type Hachure: Sans Trame; Stylo Hachure: Fond - Couleur 1; Stylo fond hachure: Fond - Couleur 1; Stylo cadre: Eléments 2D - Général; Stylo panneaux: Eléments 2D - Général; Angle ouverture en 3D: 0 deg; Afficher arêtes de contour seulement en 3D: yes; Surface par défaut: Enduit - Blanc nature; Surface 1: Menuiserie Plastique (2); Surface 2: Peinture-16; Surface 3: Métal-Nickel; Surface 4: Métal-Fer; Surface de battant: Bois - Pin granuleux horizontal; Surface de cadre: Bois - Pin granuleux horizontal; Opération IFC (ifc_optype): 0; AC_Equantity_Porte_(Mur)_39 - Largeur: 1 m; Hauteur: 2.1 m; Hauteur appui à étage actuel: 0 m; Niveau inférieur: 1 m; Niveau supérieur: 0 m; Largeur cadre: 0.05 m; Epaisseur cadre: 0.1 m; Epaisseur panneaux: 0.04 m; Dépass.ouverture à droite: 0 m; Dépass.ouverture supérieur: 0 m; Dépass.ouverture inférieur: 0 m; Dépass.ouverture gauche: 0 m
Por-019 | NIVEAU HAUT ENTRÉE | 2.05 | 0.96 | Por-019 | NIVEAU HAUT ENTRÉE | Murs Ext: Périphériques.Importation IFC | Porte (Mur) 40 | Hachure solide* 3962059836 | 0,96x2,05 | 0,96x2,05x0,16 | 2.98 | -0.02 | 5.88333 | 0.0790801 | 2.03 | 1.9488 | 1.968 | 0.31488 | 0.16 | ArchiCADProperties - Nom de Zone: Hall d'Entrée; Numéro de Zone: 010; De Zone: Hall d'Entrée; De la Zone numéro: 010; AC_Pset_Porte_(Mur)_40 - Contours Mur (0-Sans,1-Tout,2-Côté,3-Longueur): 1; Point ch.0-Non,1-2D,2-3D,3-Tous: 3; Points chauds auto. en 3D: yes; Trou reprend surface latérale de mur: no; Division de surface de trou courbée: no; Stylo du symbole: Ouvertures - Général; Angle ouverture en 2D: 90 deg; Stylo de contour: Eléments 2D - Général; Type Hachure: Sans Trame; Stylo Hachure: Fond - Couleur 1; Stylo fond hachure: Fond - Couleur 1; Stylo cadre: Eléments 2D - Général; Stylo panneaux: Eléments 2D - Général; Angle ouverture en 3D: 0 deg; Afficher arêtes de contour seulement en 3D: yes; Surface par défaut: Enduit - Blanc nature; Surface 1: Menuiserie Plastique (2); Surface 2: Peinture-16; Surface 3: Métal-Nickel; Surface 4: Métal-Fer; Surface de battant: Bois - Pin granuleux horizontal; Surface de cadre: Bois - Pin granuleux horizontal; Opération IFC (ifc_optype): 0; AC_Equantity_Porte_(Mur)_40 - Largeur: 1 m; Hauteur: 2.1 m; Hauteur appui à étage actuel: 0 m; Niveau inférieur: 1 m; Niveau supérieur: 0 m; Largeur cadre: 0.05 m; Epaisseur cadre: 0.1 m; Epaisseur panneaux: 0.04 m; Dépass.ouverture à droite: 0 m; Dépass.ouverture supérieur: 0 m; Dépass.ouverture inférieur: 0 m; Dépass.ouverture gauche: 0 m

# IfcDoor: Porte int 2v inégaux (4)
Type - ParameterTakesPrecedence: no; Sizeable: no
OverallHeight: 2.045 m; Material: Sans Trame
ArchiCADProperties - Type: Porte; Verrouillé: no; Matériau de construction / Composite / Profil / Hachure: Menuis1; Fonction structurelle: Non défini; Position: Non défini; Classification d'élement: Type ArchiCAD; Etat de rénovation: Existant; Afficher sur filtre de rénovation: Tous les filtres appropriés; Orientation: G
AC_Pset_RenovationAndPhasing - Renovation Status: Existing
ArchiCADQuantities - Altitude à étage: 0 m; Hauteur: 2.045 m; Epaisseur: 0.1 m; Hauteur nominale seuil: 0 m; Hauteur seuil côté ébrasure: 0 m; Hauteur seuil côté opposé ébrasure: 0 m; Hauteur nominale linteau: 2.045 m; Hauteur linteau côté ébrasure: 2.045 m; Hauteur linteau côté opposé ébrasure: 2.045 m; Hauteur ouverture côté ébrasure: 2.045 m; Hauteur ouverture côté opposé ébrasure: 2.045 m; Hauteur nominale de l'ouverture côté ébrasure: 2.045 m; Hauteur nominale de l'ouverture côté opposée ébrasure: 2.045 m; Valeur Appui ou Linteau: 0 m
Name | In | OverallWidth (m) = ArchiCADQuantities, Largeur (m) = Largeur ouverture côté ébrasure (m) = Largeur ouverture côté opposé ébrasure (m) = Largeur nominale de l'ouverture côté ébrasure (m) = Largeur nominale de l'ouverture côté opposée ébrasure (m) | ID Elément entier = ID Elément compact | Etage d'implantation | Nom de Zone | Numéro de Zone | Calque | Nom Elément de Bibliothèque | De Zone | De la Zone numéro | Structure mur | Taille L x H nominale | Taille L x H x E nominale | Altitude à Zéro du Projet (m) | Superficie de surface (m2) | Volume net (m3) = Volume ouverture (m3) | Surface ouverture côté ébrasure (m2) = Surface ouverture côté opposé ébrasure (m2) = Surface nominale de l'ouverture P/F côté ébrasure (m2) = Surface nominale de l'ouverture P/F côté opposé ébrasure (m2) = Surface nominale ouverture P/F (m2) | Volume nominal ouverture (m3) | Epaisseur de Mur (m)
Por-017 | NIVEAU BAS GYMNASE | 1.89 | Por-017 | NIVEAU BAS GYMNASE | Dépot 1 | 010 | 0.Importation IFC | Porte (Mur) 23 | Dépot 1 | 010 | •GYMN 18+10 | 1,89x2,05 | 1,89x2,05x0,28 | 0 | 11.7801 | 0.183643 | 3.86505 | 1.08221 | 0.28 | AC_Pset_Porte_(Mur)_23 - Contours Mur (0-Sans,1-Tout,2-Côté,3-Longueur): 1; Point ch.0-Non,1-2D,2-3D,3-Tous: 3; Points chauds auto. en 3D: yes; Trou reprend surface latérale de mur: no; Division de surface de trou courbée: no; Stylo du symbole: Ouvertures - Général; Angle ouverture en 2D: 90 deg; Stylo de contour: Eléments 2D - Général; Type Hachure: Sans Trame; Stylo Hachure: Fond - Couleur 1; Stylo fond hachure: Fond - Couleur 1; Stylo cadre: Eléments 2D - Général; Stylo panneaux: Eléments 2D - Général; Angle ouverture en 3D: 0 deg; Afficher arêtes de contour seulement en 3D: yes; Surface par défaut: Enduit - Blanc nature; Surface 1: Bois-Pin horizontal; Surface 2: Peinture-16; Surface 3: Métal-Nickel; Surface 4: Métal-Fer; Surface de battant: Bois - Pin granuleux horizontal; Surface de cadre: Bois - Pin granuleux horizontal; Opération IFC (ifc_optype): 0; AC_Equantity_Porte_(Mur)_23 - Largeur: 1 m; Hauteur: 2.1 m; Hauteur appui à étage actuel: 0 m; Niveau inférieur: 1 m; Niveau supérieur: 0 m; Largeur cadre: 0.05 m; Epaisseur cadre: 0.1 m; Epaisseur panneaux: 0.04 m; Dépass.ouverture à droite: 0 m; Dépass.ouverture supérieur: 0 m; Dépass.ouverture inférieur: 0 m; Dépass.ouverture gauche: 0 m
Por-017 | NIVEAU BAS GYMNASE | 1.89 | Por-017 | NIVEAU BAS GYMNASE | Dépot 2 | 010 | 0.Importation IFC | Porte (Mur) 24 | Dépot 2 | 010 | •GYMN 18+10 | 1,89x2,05 | 1,89x2,05x0,28 | 0 | 11.7801 | 0.183643 | 3.86505 | 1.08221 | 0.28 | AC_Pset_Porte_(Mur)_24 - Contours Mur (0-Sans,1-Tout,2-Côté,3-Longueur): 1; Point ch.0-Non,1-2D,2-3D,3-Tous: 3; Points chauds auto. en 3D: yes; Trou reprend surface latérale de mur: no; Division de surface de trou courbée: no; Stylo du symbole: Ouvertures - Général; Angle ouverture en 2D: 90 deg; Stylo de contour: Eléments 2D - Général; Type Hachure: Sans Trame; Stylo Hachure: Fond - Couleur 1; Stylo fond hachure: Fond - Couleur 1; Stylo cadre: Eléments 2D - Général; Stylo panneaux: Eléments 2D - Général; Angle ouverture en 3D: 0 deg; Afficher arêtes de contour seulement en 3D: yes; Surface par défaut: Enduit - Blanc nature; Surface 1: Bois-Pin horizontal; Surface 2: Peinture-16; Surface 3: Métal-Nickel; Surface 4: Métal-Fer; Surface de battant: Bois - Pin granuleux horizontal; Surface de cadre: Bois - Pin granuleux horizontal; Opération IFC (ifc_optype): 0; AC_Equantity_Porte_(Mur)_24 - Largeur: 1 m; Hauteur: 2.1 m; Hauteur appui à étage actuel: 0 m; Niveau inférieur: 1 m; Niveau supérieur: 0 m; Largeur cadre: 0.05 m; Epaisseur cadre: 0.1 m; Epaisseur panneaux: 0.04 m; Dépass.ouverture à droite: 0 m; Dépass.ouverture supérieur: 0 m; Dépass.ouverture inférieur: 0 m; Dépass.ouverture gauche: 0 m
Por-018 | NIVEAU BAS GYMNASE | 1.89 | Por-018 | NIVEAU BAS GYMNASE |  |  | 0.Importation IFC | Porte (Mur) 24 |  |  | •GYMN 18+10 | 1,89x2,05 | 1,89x2,05x0,28 | 0 | 11.7801 | 0.183643 | 3.86505 | 1.08221 | 0.28 | AC_Pset_Porte_(Mur)_24 - Contours Mur (0-Sans,1-Tout,2-Côté,3-Longueur): 1; Point ch.0-Non,1-2D,2-3D,3-Tous: 3; Points chauds auto. en 3D: yes; Trou reprend surface latérale de mur: no; Division de surface de trou courbée: no; Stylo du symbole: Ouvertures - Général; Angle ouverture en 2D: 90 deg; Stylo de contour: Eléments 2D - Général; Type Hachure: Sans Trame; Stylo Hachure: Fond - Couleur 1; Stylo fond hachure: Fond - Couleur 1; Stylo cadre: Eléments 2D - Général; Stylo panneaux: Eléments 2D - Général; Angle ouverture en 3D: 0 deg; Afficher arêtes de contour seulement en 3D: yes; Surface par défaut: Enduit - Blanc nature; Surface 1: Bois-Pin horizontal; Surface 2: Peinture-16; Surface 3: Métal-Nickel; Surface 4: Métal-Fer; Surface de battant: Bois - Pin granuleux horizontal; Surface de cadre: Bois - Pin granuleux horizontal; Opération IFC (ifc_optype): 0; AC_Equantity_Porte_(Mur)_24 - Largeur: 1 m; Hauteur: 2.1 m; Hauteur appui à étage actuel: 0 m; Niveau inférieur: 1 m; Niveau supérieur: 0 m; Largeur cadre: 0.05 m; Epaisseur cadre: 0.1 m; Epaisseur panneaux: 0.04 m; Dépass.ouverture à droite: 0 m; Dépass.ouverture supérieur: 0 m; Dépass.ouverture inférieur: 0 m; Dépass.ouverture gauche: 0 m
Por-017 | NIVEAU HAUT ENTRÉE | 1.78 | Por-017 | NIVEAU HAUT ENTRÉE | Salle de Sport de Combat | 006 | Murs Ext: Périphériques.Importation IFC | Porte (Mur) 41 | Hall d'Entrée | 010 | Hachure solide* 3962059836 | 1,78x2,05 | 1,78x2,05x0,16 | 3 | 9.86066 | 0.14442 | 3.6401 | 0.582416 | 0.16 | AC_Pset_Porte_(Mur)_41 - Contours Mur (0-Sans,1-Tout,2-Côté,3-Longueur): 1; Point ch.0-Non,1-2D,2-3D,3-Tous: 3; Points chauds auto. en 3D: yes; Trou reprend surface latérale de mur: no; Division de surface de trou courbée: no; Stylo du symbole: Ouvertures - Général; Angle ouverture en 2D: 90 deg; Stylo de contour: Eléments 2D - Général; Type Hachure: Sans Trame; Stylo Hachure: Fond - Couleur 1; Stylo fond hachure: Fond - Couleur 1; Stylo cadre: Eléments 2D - Général; Stylo panneaux: Eléments 2D - Général; Angle ouverture en 3D: 0 deg; Afficher arêtes de contour seulement en 3D: yes; Surface par défaut: Enduit - Blanc nature; Surface 1: Bois-Pin horizontal; Surface 2: Peinture-16; Surface 3: Métal-Nickel; Surface 4: Métal-Fer; Surface de battant: Bois - Pin granuleux horizontal; Surface de cadre: Bois - Pin granuleux horizontal; Opération IFC (ifc_optype): 0; AC_Equantity_Porte_(Mur)_41 - Largeur: 1 m; Hauteur: 2.1 m; Hauteur appui à étage actuel: 0 m; Niveau inférieur: 1 m; Niveau supérieur: 0 m; Largeur cadre: 0.05 m; Epaisseur cadre: 0.1 m; Epaisseur panneaux: 0.04 m; Dépass.ouverture à droite: 0 m; Dépass.ouverture supérieur: 0 m; Dépass.ouverture inférieur: 0 m; Dépass.ouverture gauche: 0 m

# IfcFooting (20)
In: FONDATIONS
Material: Struct. - B.A. coulé
BET - Classe béton: C25/30; Ratio acier: 65 kg/m3
ArchiCADProperties - Etage d'implantation: FONDATIONS; Calque: Murs ext - Périphériques; Type: Mur; Verrouillé: no; Matériau de construction / Composite / Profil / Hachure: Struct. - B.A. coulé; Fonction structurelle: Elément porteur; Position: Extérieur; Classification d'élement: Empattement; Etat de rénovation: Existant; Afficher sur filtre de rénovation: Tous les filtres appropriés; Type de structure: Basique; Matériau de construction / Composite / Profil: Struct. - B.A. coulé; Surface de face extérieure: Béton - Brut de décoffrage (Planches); Surface de face intérieure: Béton - Brut de décoffrage (Planches); Surface latérale: Béton - Brut de décoffrage (Planches); Angle d'inclinaison externe: 90 deg; Angle d'inclinaison interne: 90 deg; Type d'inclinaison de mur: Droit; Etage supérieur lié: Non lié; Option de géométrie: Uniforme
AC_Pset_RenovationAndPhasing - Renovation Status: Existing
ArchiCADQuantities - Altitude à Zéro du Projet: -1.5 m; Altitude à étage: 0 m; Hauteur: 0.3 m; Epaisseur: 0.5 m; Nombre de Portes: 0; Nombre de Fenêtres: 0; Nombre de trous (Nombre d'ouvertures vides): 0; Nombre de Poteaux: 0; Largeur totale des Portes: 0 m; Largeur totale des Fenêtres: 0 m; Epaisseur du Mur à la fin: 0.5 m; Hauteur minimum du Mur: 0 m; Hauteur maximum du Mur: 0.3 m; Surface analytique des ouvertures sur face intérieure: 0 m2; Surface analytique des ouvertures sur face extérieure: 0 m2; Volume analytique des ouvertures dans le Mur: 0 m3; Epaisseur de couche de mur sur face extérieure: 0 m; Epaisseur de couche de mur sur face intérieure: 0 m; Epaisseur couche isolation: 0 m; Epaisseur couche d'air: 0 m; Hauteur de couche de mur minimum sur face extérieure: 0 m; Hauteur de couche de mur maximum sur face extérieure: 0 m; Hauteur de couche de mur minimum sur face intérieure: 0 m; Hauteur de couche de mur maximum sur face intérieure: 0 m; Volume de couche de mur sur face extérieure: 0 m3; Volume de couche de mur sur face intérieure: 0 m3; Volume de couche de mur conditionnelle sur face extérieure: 0 m3; Volume de couche de mur conditionnelle sur face intérieure: 0 m3; Décalage étage d'implantation: 0 m; Décalage supérieur: -0.2 m; Surface des fenêtres dans le mur: 0 m2; Surface des portes dans le mur: 0 m2; Surface des baies libres dans le mur: 0 m2; Volume de poteaux: 0 m3
Name | ID Elément entier = ID Elément compact | Emplacement de ligne de référence | Superficie de surface (m2) = Surface de mur nette sur face extérieure (m2) = Surface conditionnelle sur face extérieure (m2) | Volume net (m3) = Volume conditionnel (m3) | Superficie (m2) = Surface du Mur (m2) | Longueur de mur sur face extérieure (m) = Longueur conditionnelle sur face extérieure (m) | Longueur de mur sur face intérieure (m) = Longueur conditionnelle sur face intérieure (m) | Surface de mur nette sur face intérieure (m2) = Surface conditionnelle sur face intérieure (m2) | Surface nette des arêtes (m2) | Longueur du Mur au centre (m) = Longueur moyenne (m) | Périmètre du Mur (m) | Surface brute de mur sur face intérieure (m2) | Surface brute de mur sur face extérieure (m2) | Volume brut du Mur (m3) | Longueur de ligne de référence (m)
semelle | semelle | Centrer | 3.1035 | 1.55175 | 4.9225 | 9.345 | 10.345 | 3.1035 | 10.345 | 9.845 | 21.1042 | 3.1035 | 3.1035 | 1.55175 | 10.095
semelle | semelle | Centrer | 1.51861 | 0.759046 | 2.53015 | 5.06204 | 5.05856 | 1.51757 | 5.06031 | 5.0603 | 11.5373 | 1.66757 | 1.66861 | 0.834046 | 5.0603
semelle | semelle | Centrer | 3.45758 | 1.72879 | 5.76264 | 11.5253 | 11.5253 | 3.45758 | 11.5253 | 11.5253 | 24.4697 | 3.60759 | 3.60759 | 1.80379 | 11.5253
semelle | semelle | Centrer | 4.71848 | 2.3595 | 7.865 | 15.2283 | 16.2317 | 4.71952 | 15.73 | 15.73 | 32.8767 | 4.86952 | 4.86848 | 2.4345 | 15.73
semelle | semelle | Centrer | 4.578 | 2.289 | 7.63 | 14.76 | 15.76 | 4.578 | 15.26 | 15.26 | 31.9342 | 4.728 | 4.728 | 2.364 | 15.26
semelle | semelle | Centrer | 0.159803 | 0.0799014 | 0.569579 | 1.13284 | 1.14548 | 0.159803 | 0.532676 | 1.13916 | 3.68365 | 0.493692 | 0.489852 | 0.245886 | 1.13916
semelle | semelle | Centrer | 0.624204 | 0.312102 | 1.04034 | 2.58085 | 1.58052 | 0.624204 | 2.08068 | 2.08068 | 5.57592 | 0.774254 | 0.774254 | 0.387127 | 2.08068
semelle | semelle | Centrer | 0.359617 | 0.178849 | 0.596203 | 1.19889 | 1.18592 | 0.355777 | 1.19232 | 1.19241 | 3.80825 | 0.505826 | 0.509666 | 0.253873 | 1.19241
semelle | semelle | Centrer | 1.209 | 0.6045 | 2.015 | 3.53 | 4.53 | 1.209 | 4.03 | 4.03 | 9.47421 | 1.359 | 1.359 | 0.6795 | 4.28
Semelles | Semelles | Face intérieure | 6.06309 | 3.03155 | 10.3552 | 20.2103 | 21.2103 | 6.06309 | 20.2103 | 20.7103 | 42.8348 | 6.36309 | 6.36309 | 3.18155 | 20.7103
Semelles | Semelles | Centrer | 6.261 | 3.1305 | 10.435 | 20.87 | 20.87 | 6.261 | 20.87 | 20.87 | 42.74 | 6.561 | 6.561 | 3.2805 | 21.62
Semelles | Semelles | Centrer | 1.8622 | 0.931099 | 2.80038 | 5.60716 | 5.59436 | 1.8622 | 6.35732 | 5.60076 | 12.2017 | 2.0122 | 2.0122 | 1.0061 | 6.10084
Semelles | Semelles | Centrer | 1.1685 | 0.58425 | 1.8225 | 3.395 | 3.895 | 1.1685 | 3.895 | 3.645 | 8.49711 | 1.3185 | 1.3185 | 0.65925 | 3.895
Semelles | Semelles | Centrer | 1.95141 | 0.975444 | 3.37648 | 6.50469 | 7.00122 | 1.95037 | 6.50296 | 6.75296 | 14.713 | 2.25037 | 2.25141 | 1.12545 | 7.00296
Semelles | Semelles | Centrer | 1.833 | 0.9165 | 2.93 | 5.61 | 6.11 | 1.833 | 6.11 | 5.86 | 12.9271 | 1.983 | 1.983 | 0.9915 | 6.36
Semelles | Semelles | Centrer | 1.272 | 0.636 | 2.12 | 3.74 | 4.74 | 1.272 | 4.24 | 4.24 | 9.89421 | 1.422 | 1.422 | 0.711 | 4.24
Semelles | Semelles | Centrer | 0.996 | 0.498 | 1.66 | 2.82 | 3.82 | 0.996 | 3.32 | 3.32 | 8.05421 | 1.146 | 1.146 | 0.573 | 3.32
Semelles | Semelles | Centrer | 0.804324 | 0.402162 | 1.34054 | 2.18108 | 3.18108 | 0.804324 | 2.68108 | 2.68108 | 6.77637 | 0.954324 | 0.954324 | 0.477162 | 2.68108
Semelles | Semelles | Centrer | 0.528 | 0.264 | 0.88 | 1.26 | 2.26 | 0.528 | 1.76 | 1.76 | 4.93421 | 0.678 | 0.678 | 0.339 | 1.76
Semelles | Semelles | Centrer | 0.654324 | 0.327162 | 1.21554 | 2.18108 | 2.68108 | 0.654324 | 2.18108 | 2.43108 | 6.06926 | 0.954324 | 0.954324 | 0.477162 | 2.68108

# IfcSlab: 3/Couches toiture 250mm 288 (2)
In: PLAN DE MASSE-TOITURE
Type - PredefinedType: ROOF
Material: Placomur 278529293 0.06 m, Hachure solide 278529293 0.036 m, Contre-plaqué 270275980 0.022 m, Isolation structures 337961919 0.1 m, Bois 270275980 0.032 m
ArchiCADProperties - ID Elément entier: Toit-003; ID Elément compact: Toit-003; Etage d'implantation: PLAN DE MASSE-TOITURE; Calque: Toit: Toitures.Importation IFC; Type: Toit; Verrouillé: no; Matériau de construction / Composite / Profil / Hachure: 3/Couches toiture 250mm; Fonction structurelle: Non défini; Position: Non défini; Classification d'élement: Type ArchiCAD; Etat de rénovation: Existant; Afficher sur filtre de rénovation: Tous les filtres appropriés; Type de structure: Composite; Matériau de construction / Composite: 3/Couches toiture 250mm; Hachure de recouvrement: Tuile de toit 01; Option de géométrie: Panneau-simple; Corps de découpe: Contours vers le bas; Pente: 2.95986 deg
AC_Pset_RenovationAndPhasing - Renovation Status: Existing
ArchiCADQuantities - Altitude à Zéro du Projet: 7.8 m; Altitude à étage: 1.6 m; Hauteur: 0.25 m; Superficie de surface: 500.851 m2; Volume net: 125.213 m3; Superficie: 500.182 m2; Surface inférieure nette: 500.851 m2; Surface supérieure nette: 500.851 m2; Surface nette de l'arête: 27.9222 m2; Volume: 125.213 m3; Périmètre: 111.57 m; Surface des trous: 0 m2; Périmètre des trous: 0 m; Epaisseur: 0.25 m; Epaisseur verticales: 0.250334 m; Surface inférieure brute: 500.851 m2; Surface supérieure brute: 500.851 m2; Surface brute des bords du Toit: 27.9222 m2; Volume brut du Toit: 125.213 m3; Surface conditionnelle inférieure: 500.851 m2; Surface conditionnelles upérieure: 500.851 m2; Volume conditionnel: 125.213 m3; Epaisseur couche isolation: 0 m; Longueur faîtage: 0 m; Longueur noue: 0 m; Longueur rive: 0 m; Longueur arêtier: 0 m; Longueur d'avant-toit: 0 m; Longueur rive de tête: 0 m; Longueur connexion mur latéral: 0 m; Longueur de la connexion mur d’extrémité: 0 m; Longueur connexion dôme: 0 m; Longueur connexion creux: 0 m; Nombre d'Ouvertures de toit: 0; Nombre de trous: 0; Surface des ouvertures: 0 m2

# IfcSlab: 3/Couches toiture 250mm 289 (2)
In: PLAN DE MASSE-TOITURE
Type - PredefinedType: ROOF
Material: Placomur 278529293 0.06 m, Hachure solide 278529293 0.036 m, Contre-plaqué 270275980 0.022 m, Isolation structures 337961919 0.1 m, Bois 270275980 0.032 m
ArchiCADProperties - ID Elément entier: Toit-003; ID Elément compact: Toit-003; Etage d'implantation: PLAN DE MASSE-TOITURE; Calque: Toit: Toitures.Importation IFC; Type: Toit; Verrouillé: no; Matériau de construction / Composite / Profil / Hachure: 3/Couches toiture 250mm; Fonction structurelle: Non défini; Position: Non défini; Classification d'élement: Type ArchiCAD; Etat de rénovation: Existant; Afficher sur filtre de rénovation: Tous les filtres appropriés; Type de structure: Composite; Matériau de construction / Composite: 3/Couches toiture 250mm; Hachure de recouvrement: Tuile de toit 01; Option de géométrie: Panneau-simple; Corps de découpe: Contours vers le bas; Pente: 0.967013 deg
AC_Pset_RenovationAndPhasing - Renovation Status: Existing
ArchiCADQuantities - Altitude à Zéro du Projet: 7.78 m; Altitude à étage: 1.58 m; Hauteur: 0.25 m; Superficie de surface: 40.0916 m2; Volume net: 10.0229 m3; Superficie: 40.0859 m2; Surface inférieure nette: 40.0916 m2; Surface supérieure nette: 40.0916 m2; Surface nette de l'arête: 22.7232 m2; Volume: 10.0229 m3; Périmètre: 90.8799 m; Surface des trous: 0 m2; Périmètre des trous: 0 m; Epaisseur: 0.25 m; Epaisseur verticales: 0.250036 m; Surface inférieure brute: 40.0916 m2; Surface supérieure brute: 40.0916 m2; Surface brute des bords du Toit: 22.7232 m2; Volume brut du Toit: 10.0229 m3; Surface conditionnelle inférieure: 40.0916 m2; Surface conditionnelles upérieure: 40.0916 m2; Volume conditionnel: 10.0229 m3; Epaisseur couche isolation: 0 m; Longueur faîtage: 0 m; Longueur noue: 0 m; Longueur rive: 0 m; Longueur arêtier: 0 m; Longueur d'avant-toit: 0 m; Longueur rive de tête: 0 m; Longueur connexion mur latéral: 0 m; Longueur de la connexion mur d’extrémité: 0 m; Longueur connexion dôme: 0 m; Longueur connexion creux: 0 m; Nombre d'Ouvertures de toit: 0; Nombre de trous: 0; Surface des ouvertures: 0 m2

# IfcSlab: Bloc béton 2590676203 50 (2)
In: PLAN DE MASSE-TOITURE
Type - PredefinedType: FLOOR
Material: Bloc béton 2590676203 0.05 m
ArchiCADProperties - ID Elément entier: Dalle-002; ID Elément compact: Dalle-002; Etage d'implantation: PLAN DE MASSE-TOITURE; Calque: Sols: Dalles.Importation IFC; Type: Dalle; Verrouillé: no; Matériau de construction / Composite / Profil / Hachure: Bloc béton 2590676203; Fonction structurelle: Non défini; Position: Non défini; Classification d'élement: Type ArchiCAD; Etat de rénovation: Existant; Afficher sur filtre de rénovation: Tous les filtres appropriés; Type de structure: Basique; Surface supérieure: RAL 9005 Noir; Surface latérale: RAL 9005 Noir; Surface inférieure: RAL 9005 Noir; Matériau de construction / Composite: Bloc béton 2590676203; Hachure de recouvrement: 25 %; Emplacement de plan de référence: Haut
AC_Pset_RenovationAndPhasing - Renovation Status: Existing
ArchiCADQuantities - Hauteur: 0.05 m; Surface des trous: 0 m2; Périmètre des trous: 0 m; Epaisseur: 0.05 m
Name | Altitude à Zéro du Projet (m) = Altitude supérieure (m) | Altitude à étage (m) | Superficie de surface (m2) = Superficie (m2) = Surface inférieure (m2) = Surface supérieure (m2) = Surface conditionnelle inférieure (m2) = Surface conditionnelle supérieure (m2) | Volume net (m3) = Volume (m3) = Volume conditionnel (m3) | Surface d'arête (m2) | Périmètre (m) | Surface brute supérieure de la Dalle (m2) = Surface brute inférieure de la Dalle (m2) = Surface brute supérieure de la dalle avec trous (m2) = Surface brute inférieure de la dalle avec trous (m2) | Surface brute des bords de la Dalle (m2) = Surface brute des arêtes de la dalle avec trous (m2) | Volume brut de la Dalle (m3) = Volume brut de la dalle avec trous (m3) | Altitude inférieure (m)
Dalle-002 | 8.95 | 2.75 | 19.5256 | 0.976279 | 8.89727 | 177.945 | 19.5256 | 8.89727 | 0.976279 | 8.9
Dalle-002 | 6.98 | 0.78 | 14.6462 | 0.73231 | 6.245 | 124.98 | 14.6478 | 6.249 | 0.73239 | 6.93

# IfcSlab: Hachure solide* 2593434267 180, Dalle-001
In: PLAN DE MASSE-TOITURE
Type - PredefinedType: FLOOR
Material: Hachure solide* 2593434267 0.18 m
ArchiCADProperties - ID Elément entier: Dalle-001; ID Elément compact: Dalle-001; Etage d'implantation: PLAN DE MASSE-TOITURE; Calque: Sols: Dalles.Importation IFC; Type: Dalle; Verrouillé: no; Matériau de construction / Composite / Profil / Hachure: Hachure solide* 2593434267; Fonction structurelle: Non défini; Position: Non défini; Classification d'élement: Type ArchiCAD; Etat de rénovation: Existant; Afficher sur filtre de rénovation: Tous les filtres appropriés; Type de structure: Basique; Surface supérieure: Peinture-09; Surface latérale: Peinture-09; Surface inférieure: Peinture-09; Matériau de construction / Composite: Hachure solide* 2593434267; Hachure de recouvrement: 25 %; Emplacement de plan de référence: Haut
AC_Pset_RenovationAndPhasing - Renovation Status: Existing
ArchiCADQuantities - Altitude à Zéro du Projet: 6.38 m; Altitude à étage: 0.18 m; Hauteur: 0.18 m; Superficie de surface: 322.787 m2; Volume net: 58.1017 m3; Superficie: 322.787 m2; Surface inférieure: 322.787 m2; Surface supérieure: 322.787 m2; Surface d'arête: 14.1948 m2; Volume: 58.1017 m3; Périmètre: 78.86 m; Surface des trous: 1.4 m2; Périmètre des trous: 4.8 m; Epaisseur: 0.18 m; Surface brute supérieure de la Dalle: 324.187 m2; Surface brute inférieure de la Dalle: 324.187 m2; Surface brute des bords de la Dalle: 13.3308 m2; Volume brut de la Dalle: 58.3537 m3; Surface conditionnelle inférieure: 324.187 m2; Surface conditionnelle supérieure: 324.187 m2; Volume conditionnel: 58.3537 m3; Surface brute supérieure de la dalle avec trous: 322.787 m2; Surface brute inférieure de la dalle avec trous: 322.787 m2; Surface brute des arêtes de la dalle avec trous: 14.1948 m2; Volume brut de la dalle avec trous: 58.1017 m3; Altitude supérieure: 6.38 m; Altitude inférieure: 6.2 m

# IfcSlab: Hachure solide* 2593434267 200 (3)
Type - PredefinedType: FLOOR
Material: Hachure solide* 2593434267 0.2 m
ArchiCADProperties - Calque: Sols: Dalles.Importation IFC; Type: Dalle; Verrouillé: no; Matériau de construction / Composite / Profil / Hachure: Hachure solide* 2593434267; Fonction structurelle: Non défini; Position: Non défini; Classification d'élement: Type ArchiCAD; Etat de rénovation: Existant; Afficher sur filtre de rénovation: Tous les filtres appropriés; Type de structure: Basique; Matériau de construction / Composite: Hachure solide* 2593434267; Hachure de recouvrement: 25 %; Emplacement de plan de référence: Haut
AC_Pset_RenovationAndPhasing - Renovation Status: Existing
ArchiCADQuantities - Hauteur: 0.2 m; Surface des trous: 0 m2; Périmètre des trous: 0 m; Epaisseur: 0.2 m
Name | In | ID Elément entier = ID Elément compact | Etage d'implantation | ArchiCADProperties, Surface supérieure = Surface latérale = ArchiCADProperties, Surface inférieure | Altitude à Zéro du Projet (m) = Altitude supérieure (m) | Altitude à étage (m) | Superficie de surface (m2) = Superficie (m2) = ArchiCADQuantities, Surface supérieure (m2) = Surface brute supérieure de la Dalle (m2) = Surface brute inférieure de la Dalle (m2) = Surface conditionnelle supérieure (m2) = Surface brute supérieure de la dalle avec trous (m2) = Surface brute inférieure de la dalle avec trous (m2) | Volume net (m3) = Volume (m3) = Volume conditionnel (m3) | ArchiCADQuantities, Surface inférieure (m2) = Surface conditionnelle inférieure (m2) | Surface d'arête (m2) | Périmètre (m) | Surface brute des bords de la Dalle (m2) = Surface brute des arêtes de la dalle avec trous (m2) | Volume brut de la Dalle (m3) = Volume brut de la dalle avec trous (m3) | Altitude inférieure (m)
Dalle-002 | NIVEAU BAS GYMNASE | Dalle-002 | NIVEAU BAS GYMNASE | Peinture-09 | 2.8 | 2.8 | 44.1279 | 8.29583 | 40.5962 | 3.66683 | 29.9106 | 5.98212 | 8.82558 | 2.6
Dalle-001 | NIVEAU BAS GYMNASE | Dalle-001 | NIVEAU BAS GYMNASE | Peinture-09 | 0 | 0 | 1089.38 | 217.876 | 1089.38 | 27.632 | 138.16 | 27.632 | 217.876 | -0.2
Dalle-002 | NIVEAU HAUT ENTRÉE | Dalle-002 | NIVEAU HAUT ENTRÉE | RAL 9010 Blanc pure | 3 | 0 | 303.364 | 60.6728 | 303.364 | 16.316 | 81.58 | 16.316 | 60.6728 | 2.8

# IfcSlab: Hachure solide* 2593434267 300 (2)
Type - PredefinedType: FLOOR
Material: Hachure solide* 2593434267 0.3 m
ArchiCADProperties - Calque: Sols: Dalles.Importation IFC; Type: Dalle; Verrouillé: no; Matériau de construction / Composite / Profil / Hachure: Hachure solide* 2593434267; Fonction structurelle: Non défini; Position: Non défini; Classification d'élement: Type ArchiCAD; Etat de rénovation: Existant; Afficher sur filtre de rénovation: Tous les filtres appropriés; Type de structure: Basique; Matériau de construction / Composite: Hachure solide* 2593434267; Hachure de recouvrement: 25 %; Emplacement de plan de référence: Haut
AC_Pset_RenovationAndPhasing - Renovation Status: Existing
ArchiCADQuantities - Hauteur: 0.3 m; Surface des trous: 0 m2; Périmètre des trous: 0 m; Epaisseur: 0.3 m
Name | In | ID Elément entier = ID Elément compact | Etage d'implantation | ArchiCADProperties, Surface supérieure = Surface latérale = ArchiCADProperties, Surface inférieure | Altitude à Zéro du Projet (m) = Altitude supérieure (m) | Altitude à étage (m) | Superficie de surface (m2) = Superficie (m2) = ArchiCADQuantities, Surface supérieure (m2) = Surface conditionnelle supérieure (m2) | Volume net (m3) = Volume (m3) = Volume conditionnel (m3) | ArchiCADQuantities, Surface inférieure (m2) = Surface brute supérieure de la Dalle (m2) = Surface brute inférieure de la Dalle (m2) = Surface conditionnelle inférieure (m2) = Surface brute supérieure de la dalle avec trous (m2) = Surface brute inférieure de la dalle avec trous (m2) | Surface d'arête (m2) | Périmètre (m) | Surface brute des bords de la Dalle (m2) = Surface brute des arêtes de la dalle avec trous (m2) | Volume brut de la Dalle (m3) = Volume brut de la dalle avec trous (m3) | Altitude inférieure (m)
Dalle-002 | NIVEAU BAS GYMNASE | Dalle-002 | NIVEAU BAS GYMNASE | Peinture-09 | 0 | 0 | 374.731 | 112.768 | 378.22 | 16.4198 | 87.6069 | 26.2821 | 113.466 | -0.3
Dalle-001 | PLAN DE MASSE-TOITURE | Dalle-001 | PLAN DE MASSE-TOITURE | Surface-Stuc blanc | 7.3 | 1.1 | 40.9336 | 12.2801 | 40.9336 | 7.716 | 25.72 | 7.716 | 12.2801 | 7

# IfcSlab: Hachure solide* 2593434267 370, Dalle-001
In: NIVEAU HAUT ENTRÉE
Type - PredefinedType: FLOOR
Material: Hachure solide* 2593434267 0.37 m
ArchiCADProperties - ID Elément entier: Dalle-001; ID Elément compact: Dalle-001; Etage d'implantation: NIVEAU HAUT ENTRÉE; Calque: Sols: Dalles.Importation IFC; Type: Dalle; Verrouillé: no; Matériau de construction / Composite / Profil / Hachure: Hachure solide* 2593434267; Fonction structurelle: Non défini; Position: Non défini; Classification d'élement: Type ArchiCAD; Etat de rénovation: Existant; Afficher sur filtre de rénovation: Tous les filtres appropriés; Type de structure: Basique; Surface supérieure: Surface-Stuc blanc; Surface latérale: Surface-Stuc blanc; Surface inférieure: Surface-Stuc blanc; Matériau de construction / Composite: Hachure solide* 2593434267; Hachure de recouvrement: 25 %; Emplacement de plan de référence: Haut
AC_Pset_RenovationAndPhasing - Renovation Status: Existing
ArchiCADQuantities - Altitude à Zéro du Projet: 2.97 m; Altitude à étage: -0.03 m; Hauteur: 0.37 m; Superficie de surface: 15.15 m2; Volume net: 5.6055 m3; Superficie: 15.15 m2; Surface inférieure: 15.15 m2; Surface supérieure: 15.15 m2; Surface d'arête: 6.3344 m2; Volume: 5.6055 m3; Périmètre: 17.12 m; Surface des trous: 0 m2; Périmètre des trous: 0 m; Epaisseur: 0.37 m; Surface brute supérieure de la Dalle: 15.15 m2; Surface brute inférieure de la Dalle: 15.15 m2; Surface brute des bords de la Dalle: 6.3344 m2; Volume brut de la Dalle: 5.6055 m3; Surface conditionnelle inférieure: 15.15 m2; Surface conditionnelle supérieure: 15.15 m2; Volume conditionnel: 5.6055 m3; Surface brute supérieure de la dalle avec trous: 15.15 m2; Surface brute inférieure de la dalle avec trous: 15.15 m2; Surface brute des arêtes de la dalle avec trous: 6.3344 m2; Volume brut de la dalle avec trous: 5.6055 m3; Altitude supérieure: 2.97 m; Altitude inférieure: 2.6 m

# IfcSlab: Hachure solide* 2593434267 640, Dalle-001
In: NIVEAU HAUT ENTRÉE
Type - PredefinedType: FLOOR
Material: Hachure solide* 2593434267 0.64 m
ArchiCADProperties - ID Elément entier: Dalle-001; ID Elément compact: Dalle-001; Etage d'implantation: NIVEAU HAUT ENTRÉE; Calque: Sols: Dalles.Importation IFC; Type: Dalle; Verrouillé: no; Matériau de construction / Composite / Profil / Hachure: Hachure solide* 2593434267; Fonction structurelle: Non défini; Position: Non défini; Classification d'élement: Type ArchiCAD; Etat de rénovation: Existant; Afficher sur filtre de rénovation: Tous les filtres appropriés; Type de structure: Basique; Surface supérieure: Agave 3 OD; Surface latérale: Agave 3 OD; Surface inférieure: Agave 3 OD; Matériau de construction / Composite: Hachure solide* 2593434267; Hachure de recouvrement: 25 %; Emplacement de plan de référence: Haut
AC_Pset_RenovationAndPhasing - Renovation Status: Existing
ArchiCADQuantities - Altitude à Zéro du Projet: 6.16 m; Altitude à étage: 3.16 m; Hauteur: 0.64 m; Superficie de surface: 0.078127 m2; Volume net: 0.0500013 m3; Superficie: 0.078127 m2; Surface inférieure: 0.078127 m2; Surface supérieure: 0.078127 m2; Surface d'arête: 4.42846 m2; Volume: 0.0500013 m3; Périmètre: 6.91946 m; Surface des trous: 0 m2; Périmètre des trous: 0 m; Epaisseur: 0.64 m; Surface brute supérieure de la Dalle: 0.078127 m2; Surface brute inférieure de la Dalle: 0.078127 m2; Surface brute des bords de la Dalle: 4.42846 m2; Volume brut de la Dalle: 0.0500013 m3; Surface conditionnelle inférieure: 0.078127 m2; Surface conditionnelle supérieure: 0.078127 m2; Volume conditionnel: 0.0500013 m3; Surface brute supérieure de la dalle avec trous: 0.078127 m2; Surface brute inférieure de la dalle avec trous: 0.078127 m2; Surface brute des arêtes de la dalle avec trous: 4.42846 m2; Volume brut de la dalle avec trous: 0.0500013 m3; Altitude supérieure: 6.16 m; Altitude inférieure: 5.52 m

# IfcSlab: Hachure solide* 2593434267 660 (9)
In: NIVEAU HAUT ENTRÉE
Type - PredefinedType: FLOOR
Material: Hachure solide* 2593434267 0.66 m
ArchiCADProperties - ID Elément entier: Dalle-001; ID Elément compact: Dalle-001; Etage d'implantation: NIVEAU HAUT ENTRÉE; Calque: Sols: Dalles.Importation IFC; Type: Dalle; Verrouillé: no; Matériau de construction / Composite / Profil / Hachure: Hachure solide* 2593434267; Fonction structurelle: Non défini; Position: Non défini; Classification d'élement: Type ArchiCAD; Etat de rénovation: Existant; Afficher sur filtre de rénovation: Tous les filtres appropriés; Type de structure: Basique; Matériau de construction / Composite: Hachure solide* 2593434267; Hachure de recouvrement: 25 %; Emplacement de plan de référence: Haut
AC_Pset_RenovationAndPhasing - Renovation Status: Existing
ArchiCADQuantities - Hauteur: 0.66 m; Surface des trous: 0 m2; Périmètre des trous: 0 m; Epaisseur: 0.66 m
Name | ArchiCADProperties, Surface supérieure = Surface latérale = ArchiCADProperties, Surface inférieure | Altitude à Zéro du Projet (m) = Altitude supérieure (m) | Altitude à étage (m) | Superficie de surface (m2) = Superficie (m2) = ArchiCADQuantities, Surface inférieure (m2) = ArchiCADQuantities, Surface supérieure (m2) = Surface conditionnelle inférieure (m2) = Surface conditionnelle supérieure (m2) | Volume net (m3) = Volume (m3) = Volume conditionnel (m3) | Surface d'arête (m2) | Périmètre (m) | Surface brute supérieure de la Dalle (m2) = Surface brute inférieure de la Dalle (m2) = Surface brute supérieure de la dalle avec trous (m2) = Surface brute inférieure de la dalle avec trous (m2) | Surface brute des bords de la Dalle (m2) = Surface brute des arêtes de la dalle avec trous (m2) | Volume brut de la Dalle (m3) = Volume brut de la dalle avec trous (m3) | Altitude inférieure (m)
Dalle-001 | Agave 1 OD | 4.09 | 1.09 | 0.0779224 | 0.0514288 | 4.55497 | 6.90146 | 0.0779224 | 4.55497 | 0.0514288 | 3.43
Dalle-001 | Agave 1 OD | 3.43 | 0.43 | 0.0777178 | 0.0512938 | 4.54309 | 6.88346 | 0.0777178 | 4.54309 | 0.0512938 | 2.77
Dalle-001 | Agave 1 OD | 5.49 | 2.49 | 0.0779224 | 0.0514288 | 4.55497 | 6.90146 | 0.0779224 | 4.55497 | 0.0514288 | 4.83
Dalle-001 | Agave 3 OD | 4.10999 | 1.10999 | 0.077911 | 0.0514213 | 4.5393 | 6.90146 | 0.0779224 | 4.55497 | 0.0514288 | 3.44999
Dalle-001 | Agave 3 OD | 5.49 | 2.49 | 0.0779224 | 0.0514288 | 4.55497 | 6.90146 | 0.0779224 | 4.55497 | 0.0514288 | 4.83
Dalle-001 | Agave 3 OD | 4.8 | 1.8 | 0.0777178 | 0.0512938 | 4.54309 | 6.88346 | 0.0777178 | 4.54309 | 0.0512938 | 4.14
Dalle-001 | Agave 3 OD | 4.8 | 1.8 | 0.0788355 | 0.0520314 | 4.55532 | 6.902 | 0.0788355 | 4.55532 | 0.0520314 | 4.14
Dalle-001 | Agave 3 OD | 6.18 | 3.18 | 0.0788355 | 0.0520314 | 4.55532 | 6.902 | 0.0788355 | 4.55532 | 0.0520314 | 5.52
Dalle-001 | Agave 1 OD | 3.43 | 0.43 | 0.0788355 | 0.0520314 | 4.55532 | 6.902 | 0.0788355 | 4.55532 | 0.0520314 | 2.77

# IfcStair (2)
In: NIVEAU BAS GYMNASE
Material: Placomur
ArchiCADProperties - Etage d'implantation: NIVEAU BAS GYMNASE; Calque: Equip: Escaliers int.Importation IFC; Type: Objet; Verrouillé: no; Matériau de construction / Composite / Profil / Hachure: Placomur; Fonction structurelle: Non défini; Position: Non défini; Classification d'élement: Type ArchiCAD; Etat de rénovation: Existant; Afficher sur filtre de rénovation: Tous les filtres appropriés; Surface: Enduit - Blanc nature
AC_Pset_RenovationAndPhasing - Renovation Status: Existing
Name | ID Elément entier = ID Elément compact | Nom Elément de Bibliothèque | Angle de rotation (deg) | Altitude à Zéro du Projet (m) = Altitude à étage (m) | Superficie de surface (m2) | Volume net (m3) = Volume (m3) | Superficie (m2) | Hauteur (Taille en Z) (m) | Longueur (A) (m) | Largeur (B) (m)
ESC-004 | ESC-004 | Escalier 1 | 0 | -0.05 | 44.5743 | 2.88087 | 10.6532 | 3.05105 | 1.9583 | 5.44 | AC_Pset_Escalier_1 - Type Hachure: Sans Trame; Stylo Hachure: Fond - Couleur 1; Stylo fond hachure: Fond - Couleur 1; Coût: 0; Type de groupe (FM_Type): Autres; Type de groupe (iFMType): 25; Poids de l'objet: 0; Unité poids de l'objet: kg; Nombre d'étages: 0; Nombre de demi-paliers: 0; Hauteur des niveaux: 0; Echappée: 0; Capacité de support: 0; Escalier sans fumée: no; Longueur des marches: 0; Type escalier: 0; Nombre de contremarches: 0; Nombre de girons (ifc_NumberOfTreads): 0; Stylo de contour: Eléments 2D - Général; Surface par défaut: Enduit - Blanc nature; Surface 1: Pierre-Marbre blanc; Surface 2: Pierre-Marbre rose; Afficher arêtes de contour seulement en 3D: yes; AC_Equantity_Escalier_1 - Hauteur contremarche: 0 m; Longueur giron: 0 m
ESC-003 | ESC-003 | Escalier 2 | -90 | 0 | 68.2727 | 3.43736 | 17.1205 | 4.7244 | 4.5955 | 3.7255 | AC_Pset_Escalier_2 - Type Hachure: Sans Trame; Stylo Hachure: Fond - Couleur 1; Stylo fond hachure: Fond - Couleur 1; Coût: 0; Type de groupe (FM_Type): Autres; Type de groupe (iFMType): 25; Poids de l'objet: 0; Unité poids de l'objet: kg; Nombre d'étages: 0; Nombre de demi-paliers: 0; Hauteur des niveaux: 0; Echappée: 0; Capacité de support: 0; Escalier sans fumée: no; Longueur des marches: 0; Type escalier: 0; Nombre de contremarches: 0; Nombre de girons (ifc_NumberOfTreads): 0; Stylo de contour: Eléments 2D - Général; Surface par défaut: Enduit - Blanc nature; Surface 1: Métal-Zinc; Surface 2: Bois-Pin horizontal; Surface 3: BETON65; Surface 4: Peinture-04; Afficher arêtes de contour seulement en 3D: yes; AC_Equantity_Escalier_2 - Hauteur contremarche: 0 m; Longueur giron: 0 m

# IfcTransportElement: Ascenseur 2 10, Obj.-013
In: NIVEAU BAS GYMNASE
CapacityByWeight: 0 g; CapacityByNumber: 0; Material: AS_EMPTY
ArchiCADProperties - ID Elément entier: Obj.-013; ID Elément compact: Obj.-013; Etage d'implantation: NIVEAU BAS GYMNASE; Calque: •Objets.Importation IFC; Type: Objet; Verrouillé: no; Nom Elément de Bibliothèque: Elément de transport 1; Matériau de construction / Composite / Profil / Hachure: AS_EMPTY; Fonction structurelle: Non défini; Position: Non défini; Classification d'élement: Type ArchiCAD; Etat de rénovation: Existant; Afficher sur filtre de rénovation: Tous les filtres appropriés; Angle de rotation: 0 deg; Surface: Enduit - Blanc nature
AC_Pset_Elément_de_transport_1 - Type Hachure: Sans Trame; Stylo Hachure: Fond - Couleur 1; Stylo fond hachure: Fond - Couleur 1; Coût: 0; Type de groupe (FM_Type): Ascenseurs; Type de groupe (iFMType): 4; Poids de l'objet: 0; Unité poids de l'objet: kg; Capacité ascenseur: 0; Capacité par personne: 0; Opération IFC: 0; Stylo de contour: Eléments 2D - Général; Surface par défaut: Enduit - Blanc nature; Surface 1: Peinture-18; Surface 2: Aluminium; Surface 3: Peinture-17; Surface 4: Métal-Or; Surface 5: Métal-Fer; Surface 6: Peinture-01; Surface 7: Peinture-19; Surface 8: Peinture-15; Afficher arêtes de contour seulement en 3D: yes
AC_Pset_RenovationAndPhasing - Renovation Status: Existing
ArchiCADQuantities - Altitude à Zéro du Projet: 0 m; Altitude à étage: 0 m; Superficie de surface: 195.531 m2; Volume net: 10.2544 m3; Superficie: 3.9168 m2; Hauteur (Taille en Z): 7.76 m; Longueur (A): 1.92 m; Volume: 10.2544 m3; Largeur (B): 2.04 m

# IfcWallStandardCase: Acier 2556372607 100 (3)
In: NIVEAU BAS GYMNASE
Material: Acier 2556372607 0.1 m
ArchiCADProperties - ID Elément entier: Mur-002; ID Elément compact: Mur-002; Etage d'implantation: NIVEAU BAS GYMNASE; Calque: Murs Ext: Périphériques.Importation IFC; Type: Mur; Verrouillé: no; Matériau de construction / Composite / Profil / Hachure: Acier 2556372607; Fonction structurelle: Non défini; Position: Non défini; Classification d'élement: Type ArchiCAD; Etat de rénovation: Existant; Afficher sur filtre de rénovation: Tous les filtres appropriés; Type de structure: Basique; Matériau de construction / Composite / Profil: Acier 2556372607; Surface de face extérieure: RAL 7016 Gris anthracite; Surface de face intérieure: RAL 7016 Gris anthracite; Surface latérale: RAL 7016 Gris anthracite; Angle d'inclinaison externe: 90 deg; Angle d'inclinaison interne: 90 deg; Type d'inclinaison de mur: Droit; Emplacement de ligne de référence: Face extérieure; Etage supérieur lié: Non lié; Option de géométrie: Uniforme
AC_Pset_RenovationAndPhasing - Renovation Status: Existing
ArchiCADQuantities - Altitude à Zéro du Projet: 0 m; Altitude à étage: 0 m; Epaisseur: 0.1 m; Nombre de trous (Nombre d'ouvertures vides): 0; Nombre de Poteaux: 0; Epaisseur du Mur à la fin: 0.1 m; Hauteur minimum du Mur: 0 m; Epaisseur de couche de mur sur face extérieure: 0 m; Epaisseur de couche de mur sur face intérieure: 0 m; Epaisseur couche isolation: 0 m; Epaisseur couche d'air: 0 m; Hauteur de couche de mur minimum sur face extérieure: 0 m; Hauteur de couche de mur maximum sur face extérieure: 0 m; Hauteur de couche de mur minimum sur face intérieure: 0 m; Hauteur de couche de mur maximum sur face intérieure: 0 m; Volume de couche de mur sur face extérieure: 0 m3; Volume de couche de mur sur face intérieure: 0 m3; Volume de couche de mur conditionnelle sur face extérieure: 0 m3; Volume de couche de mur conditionnelle sur face intérieure: 0 m3; Décalage étage d'implantation: 0 m; Décalage supérieur: -0.12 m; Surface des baies libres dans le mur: 0 m2; Volume de poteaux: 0 m3
Name | Hauteur (m) = Hauteur maximum du Mur (m) | Superficie de surface (m2) = Surface de mur nette sur face extérieure (m2) = Surface de mur nette sur face intérieure (m2) = Surface conditionnelle sur face extérieure (m2) = Surface conditionnelle sur face intérieure (m2) | Volume net (m3) | Superficie (m2) = Surface du Mur (m2) | Longueur de mur sur face extérieure (m) = Longueur conditionnelle sur face extérieure (m) | Longueur de mur sur face intérieure (m) = Longueur conditionnelle sur face intérieure (m) | Surface nette des arêtes (m2) | Volume conditionnel (m3) | Nombre de Portes | Nombre de Fenêtres | Largeur totale des Portes (m) | Largeur totale des Fenêtres (m) | Longueur du Mur au centre (m) = Longueur moyenne (m) | Périmètre du Mur (m) | Surface brute de mur sur face intérieure (m2) = Surface brute de mur sur face extérieure (m2) | Volume brut du Mur (m3) | Surface analytique des ouvertures sur face intérieure (m2) = Surface analytique des ouvertures sur face extérieure (m2) | Volume analytique des ouvertures dans le Mur (m3) | Longueur de ligne de référence (m) | Surface des fenêtres dans le mur (m2) | Surface des portes dans le mur (m2)
Mur-002 | 2.62 | 13.468 | 1.3468 | 4.46398 | 44.7398 | 44.5398 | 8.94797 | 3.11154 | 0 | 6 | 0 | 44.72 | 44.6398 | 89.5625 | 117.218 | 11.7218 | 103.75 | 10.375 | 44.7398 | 103.75 | 0
Mur-002 | 2.8 | 1.86106 | 0.186106 | 0.38897 | 3.9397 | 3.8397 | 0.82594 | 1.07692 | 1 | 0 | 3.9397 | 0 | 3.8897 | 8.02082 | 11.0312 | 1.10312 | 8.9081 | 0.89081 | 3.9397 | 0 | 9.1401
Mur-002 | 2.62 | 2.429 | 0.2429 | 0.814667 | 8.09667 | 8.19667 | 1.64933 | 2.12133 | 1 | 1 | 3.9397 | 4.25697 | 8.14667 | 16.5348 | 21.4753 | 2.14753 | 18.7843 | 1.87843 | 8.19667 | 9.87616 | 9.1401

# IfcWallStandardCase: Aluminium 3973644675 300, Mur-006
In: NIVEAU BAS GYMNASE
Material: Aluminium 3973644675 0.3 m
ArchiCADProperties - ID Elément entier: Mur-006; ID Elément compact: Mur-006; Etage d'implantation: NIVEAU BAS GYMNASE; Calque: Murs Ext: Périphériques.Importation IFC; Type: Mur; Verrouillé: no; Matériau de construction / Composite / Profil / Hachure: Aluminium 3973644675; Fonction structurelle: Non défini; Position: Non défini; Classification d'élement: Type ArchiCAD; Etat de rénovation: Existant; Afficher sur filtre de rénovation: Tous les filtres appropriés; Type de structure: Basique; Matériau de construction / Composite / Profil: Aluminium 3973644675; Surface de face extérieure: Surface-Stuc blanc; Surface de face intérieure: Surface-Stuc blanc; Surface latérale: Surface-Stuc blanc; Angle d'inclinaison externe: 90 deg; Angle d'inclinaison interne: 90 deg; Type d'inclinaison de mur: Droit; Emplacement de ligne de référence: Face extérieure; Etage supérieur lié: Non lié; Option de géométrie: Uniforme
AC_Pset_RenovationAndPhasing - Renovation Status: Existing
ArchiCADQuantities - Altitude à Zéro du Projet: 2.45 m; Altitude à étage: 2.45 m; Hauteur: 4.05 m; Superficie de surface: 13.938 m2; Volume net: 4.1814 m3; Superficie: 1.188 m2; Epaisseur: 0.3 m; Longueur de mur sur face extérieure: 3.96 m; Longueur de mur sur face intérieure: 3.96 m; Surface de mur nette sur face extérieure: 13.938 m2; Surface de mur nette sur face intérieure: 13.938 m2; Surface nette des arêtes: 4.596 m2; Volume conditionnel: 4.8114 m3; Nombre de Portes: 0; Nombre de Fenêtres: 1; Nombre de trous (Nombre d'ouvertures vides): 0; Nombre de Poteaux: 1; Largeur totale des Portes: 0 m; Largeur totale des Fenêtres: 3 m; Epaisseur du Mur à la fin: 0.3 m; Hauteur minimum du Mur: 4.05 m; Hauteur maximum du Mur: 4.05 m; Longueur du Mur au centre: 3.96 m; Surface du Mur: 1.188 m2; Périmètre du Mur: 8.52 m; Surface brute de mur sur face intérieure: 16.038 m2; Surface brute de mur sur face extérieure: 16.038 m2; Volume brut du Mur: 4.8114 m3; Surface analytique des ouvertures sur face intérieure: 2.1 m2; Surface analytique des ouvertures sur face extérieure: 2.1 m2; Volume analytique des ouvertures dans le Mur: 0.63 m3; Epaisseur de couche de mur sur face extérieure: 0 m; Epaisseur de couche de mur sur face intérieure: 0 m; Epaisseur couche isolation: 0 m; Epaisseur couche d'air: 0 m; Hauteur de couche de mur minimum sur face extérieure: 0 m; Hauteur de couche de mur maximum sur face extérieure: 0 m; Hauteur de couche de mur minimum sur face intérieure: 0 m; Hauteur de couche de mur maximum sur face intérieure: 0 m; Longueur conditionnelle sur face extérieure: 3.96 m; Longueur conditionnelle sur face intérieure: 3.96 m; Surface conditionnelle sur face extérieure: 13.938 m2; Surface conditionnelle sur face intérieure: 13.938 m2; Volume de couche de mur sur face extérieure: 0 m3; Volume de couche de mur sur face intérieure: 0 m3; Volume de couche de mur conditionnelle sur face extérieure: 0 m3; Volume de couche de mur conditionnelle sur face intérieure: 0 m3; Longueur de ligne de référence: 3.96 m; Décalage étage d'implantation: 2.45 m; Décalage supérieur: -0.12 m; Longueur moyenne: 3.96 m; Surface des fenêtres dans le mur: 2.1 m2; Surface des portes dans le mur: 0 m2; Surface des baies libres dans le mur: 0 m2; Volume de poteaux: 0 m3

# IfcWallStandardCase: Hachure solide 3821565075 20 (36)
In: NIVEAU BAS GYMNASE
Material: Hachure solide 3821565075 0.02 m
ArchiCADProperties - Etage d'implantation: NIVEAU BAS GYMNASE; Calque: 0.Importation IFC; Type: Mur; Verrouillé: no; Matériau de construction / Composite / Profil / Hachure: Hachure solide 3821565075; Fonction structurelle: Non défini; Position: Non défini; Classification d'élement: Type ArchiCAD; Etat de rénovation: Existant; Afficher sur filtre de rénovation: Tous les filtres appropriés; Type de structure: Basique; Matériau de construction / Composite / Profil: Hachure solide 3821565075; Surface de face extérieure: RAL 5002 Bleu OutreMer; Surface de face intérieure: RAL 5002 Bleu OutreMer; Surface latérale: RAL 5002 Bleu OutreMer; Angle d'inclinaison externe: 90 deg; Angle d'inclinaison interne: 90 deg; Type d'inclinaison de mur: Droit; Emplacement de ligne de référence: Face extérieure; Etage supérieur lié: Non lié; Option de géométrie: Uniforme
AC_Pset_RenovationAndPhasing - Renovation Status: Existing
ArchiCADQuantities - Altitude à Zéro du Projet: 0 m; Altitude à étage: 0 m; Epaisseur: 0.02 m; Nombre de Fenêtres: 0; Nombre de trous (Nombre d'ouvertures vides): 0; Nombre de Poteaux: 0; Largeur totale des Fenêtres: 0 m; Epaisseur du Mur à la fin: 0.02 m; Hauteur minimum du Mur: 0 m; Epaisseur de couche de mur sur face extérieure: 0 m; Epaisseur de couche de mur sur face intérieure: 0 m; Epaisseur couche isolation: 0 m; Epaisseur couche d'air: 0 m; Hauteur de couche de mur minimum sur face extérieure: 0 m; Hauteur de couche de mur maximum sur face extérieure: 0 m; Hauteur de couche de mur minimum sur face intérieure: 0 m; Hauteur de couche de mur maximum sur face intérieure: 0 m; Volume de couche de mur sur face extérieure: 0 m3; Volume de couche de mur sur face intérieure: 0 m3; Volume de couche de mur conditionnelle sur face extérieure: 0 m3; Volume de couche de mur conditionnelle sur face intérieure: 0 m3; Décalage étage d'implantation: 0 m; Décalage supérieur: -0.12 m; Surface des fenêtres dans le mur: 0 m2; Surface des baies libres dans le mur: 0 m2; Volume de poteaux: 0 m3
Name | ID Elément entier = ID Elément compact | Nom de Zone | Numéro de Zone | Hauteur (m) | Superficie de surface (m2) = Surface de mur nette sur face extérieure (m2) = Surface de mur nette sur face intérieure (m2) | Volume net (m3) | Superficie (m2) = Surface du Mur (m2) | Longueur de mur sur face extérieure (m) | Longueur de mur sur face intérieure (m) | Surface nette des arêtes (m2) | Volume conditionnel (m3) | Nombre de Portes | Largeur totale des Portes (m) | Hauteur maximum du Mur (m) | Longueur du Mur au centre (m) = Longueur moyenne (m) | Périmètre du Mur (m) | Surface brute de mur sur face intérieure (m2) = Surface brute de mur sur face extérieure (m2) | Volume brut du Mur (m3) | Surface analytique des ouvertures sur face intérieure (m2) = Surface analytique des ouvertures sur face extérieure (m2) | Volume analytique des ouvertures dans le Mur (m3) | Longueur conditionnelle sur face extérieure (m) | Longueur conditionnelle sur face intérieure (m) | Surface conditionnelle sur face extérieure (m2) = Surface conditionnelle sur face intérieure (m2) | Longueur de ligne de référence (m) | Surface des portes dans le mur (m2)
Mur-022 | Mur-022 | Sanit Vest 6 | 010 | 2.1 | 3.38959 | 0.0677917 | 0.0320951 | 1.59476 | 1.61476 | 0.0641902 | 0.0677917 | 0 | 0 | 2.1 | 1.60476 | 3.25779 | 3.59959 | 0.0719917 | 0 | 0 | 1.59476 | 1.61476 | 3.38959 | 1.59476 | 0
Mur-022 | Mur-022 | Sanit Vest 5 | 010 | 2.03 | 2.43571 | 0.0487143 | 0.103397 | 5.15986 | 5.17986 | 0.0479944 | 0.210302 | 5 | 3.98 | 2.03 | 5.16986 | 10.388 | 10.5151 | 0.210302 | 8.0794 | 0.161588 | 1.17986 | 1.19986 | 10.5151 | 5.15986 | 8.159
Mur-022 | Mur-022 | Sanit Vest 1 | 010 | 1.85 | 2.9503 | 0.0590059 | 0.0318951 | 1.59476 | 1.59476 | 0.0637902 | 0.0590059 | 0 | 0 | 1.85 | 1.59476 | 3.22951 | 3.3573 | 0.0671459 | 0 | 0 | 1.59476 | 1.59476 | 2.9503 | 1.64476 | 0
Mur-022 | Mur-022 | Sanit Vest 6 | 010 | 2.03 | 2.39511 | 0.0479023 | 0.103397 | 5.17986 | 5.15986 | 0.0471944 | 0.20949 | 5 | 3.98 | 2.03 | 5.16986 | 10.388 | 10.5151 | 0.210302 | 8.0794 | 0.161588 | 1.19986 | 1.17986 | 10.4745 | 5.15986 | 8.159
Mur-023 | Mur-023 | Sanit Vest 4 | 010 | 1.85 | 2.9503 | 0.0590059 | 0.0318951 | 1.59476 | 1.59476 | 0.0637902 | 0.0590059 | 0 | 0 | 1.85 | 1.59476 | 3.22951 | 3.3573 | 0.0671459 | 0 | 0 | 1.59476 | 1.59476 | 2.9503 | 1.64476 | 0
2 x Mur-022 | Mur-022 | Sanit Vest 5 | 010 | 2.82 | 4.46531 | 0.0893063 | 0.0318951 | 1.59476 | 1.59476 | 0.0318951 | 0.0893063 | 0 | 0 | 2.8 | 1.59476 | 3.22951 | 5.10181 | 0.102036 | 0 | 0 | 1.59476 | 1.59476 | 4.46531 | 1.69476 | 0
Mur-022 | Mur-022 | Sanit Vest 5 | 010 | 2.82 | 4.46531 | 0.0893063 | 0.0320951 | 1.61476 | 1.59476 | 0.0878951 | 0.0893063 | 0 | 0 | 2.8 | 1.60476 | 3.25779 | 4.53781 | 0.0907562 | 0 | 0 | 1.61476 | 1.59476 | 4.46531 | 1.59476 | 0
2 x Mur-023 | Mur-023 | Sanit Vest 5 | 010 | 2.82 | 4.46531 | 0.0893063 | 0.0318951 | 1.59476 | 1.59476 | 0.0318951 | 0.0893063 | 0 | 0 | 2.8 | 1.59476 | 3.22951 | 5.10181 | 0.102036 | 0 | 0 | 1.59476 | 1.59476 | 4.46531 | 1.69476 | 0
2 x Mur-023 | Mur-023 | Sanit Vest 6 | 010 | 2.82 | 4.46531 | 0.0893063 | 0.0318951 | 1.59476 | 1.59476 | 0.0318951 | 0.0893063 | 0 | 0 | 2.8 | 1.59476 | 3.22951 | 4.81981 | 0.0963962 | 0 | 0 | 1.59476 | 1.59476 | 4.46531 | 1.59476 | 0
2 x Mur-022 | Mur-022 | Sanit Vest 6 | 010 | 2.82 | 4.46531 | 0.0893063 | 0.0318951 | 1.59476 | 1.59476 | 0.0318951 | 0.0893063 | 0 | 0 | 2.8 | 1.59476 | 3.22951 | 4.81981 | 0.0963962 | 0 | 0 | 1.59476 | 1.59476 | 4.46531 | 1.59476 | 0
2 x Mur-023 | Mur-023 | Sanit Vest 2 | 010 | 1.85 | 2.9503 | 0.0590059 | 0.0318951 | 1.59476 | 1.59476 | 0.0637902 | 0.0590059 | 0 | 0 | 1.85 | 1.59476 | 3.22951 | 3.3573 | 0.0671459 | 0 | 0 | 1.59476 | 1.59476 | 2.9503 | 1.64476 | 0
2 x Mur-023 | Mur-023 | Sanit Vest 1 | 010 | 1.85 | 2.9503 | 0.0590059 | 0.0318951 | 1.59476 | 1.59476 | 0.0637902 | 0.0590059 | 0 | 0 | 1.85 | 1.59476 | 3.22951 | 3.1723 | 0.0634459 | 0 | 0 | 1.59476 | 1.59476 | 2.9503 | 1.64476 | 0
Mur-022 | Mur-022 | Sanit Vest 2 | 010 | 1.85 | 2.9873 | 0.0597459 | 0.0320951 | 1.59476 | 1.61476 | 0.10159 | 0.0597459 | 0 | 0 | 1.85 | 1.60476 | 3.25779 | 2.9873 | 0.0597459 | 0 | 0 | 1.59476 | 1.61476 | 2.9873 | 1.59476 | 0
Mur-023 | Mur-023 | Sanit Vest 3 | 010 | 1.85 | 2.9503 | 0.0590059 | 0.0318951 | 1.59476 | 1.59476 | 0.0637902 | 0.0590059 | 0 | 0 | 1.85 | 1.59476 | 3.22951 | 3.3573 | 0.0671459 | 0 | 0 | 1.59476 | 1.59476 | 2.9503 | 1.64476 | 0
Mur-022 | Mur-022 | Sanit Vest 2 | 010 | 1.85 | 2.9503 | 0.0590059 | 0.0318951 | 1.59476 | 1.59476 | 0.0637902 | 0.0590059 | 0 | 0 | 1.85 | 1.59476 | 3.22951 | 3.1723 | 0.0634459 | 0 | 0 | 1.59476 | 1.59476 | 2.9503 | 1.64476 | 0
Mur-022 | Mur-022 | Sanit Vest 1 | 010 | 1.85 | 2.9873 | 0.0597459 | 0.0320951 | 1.61476 | 1.59476 | 0.10159 | 0.0597459 | 0 | 0 | 1.85 | 1.60476 | 3.25779 | 2.9873 | 0.0597459 | 0 | 0 | 1.61476 | 1.59476 | 2.9873 | 1.59476 | 0
2 x Mur-022 | Mur-022 |  |  | 1.85 | 2.18274 | 0.0436548 | 0.103397 | 5.15986 | 5.17986 | 0.0841944 | 0.190915 | 5 | 3.98 | 1.85 | 5.16986 | 10.388 | 9.58274 | 0.191655 | 7.363 | 0.14726 | 1.17986 | 1.19986 | 9.54574 | 5.15986 | 7.4426
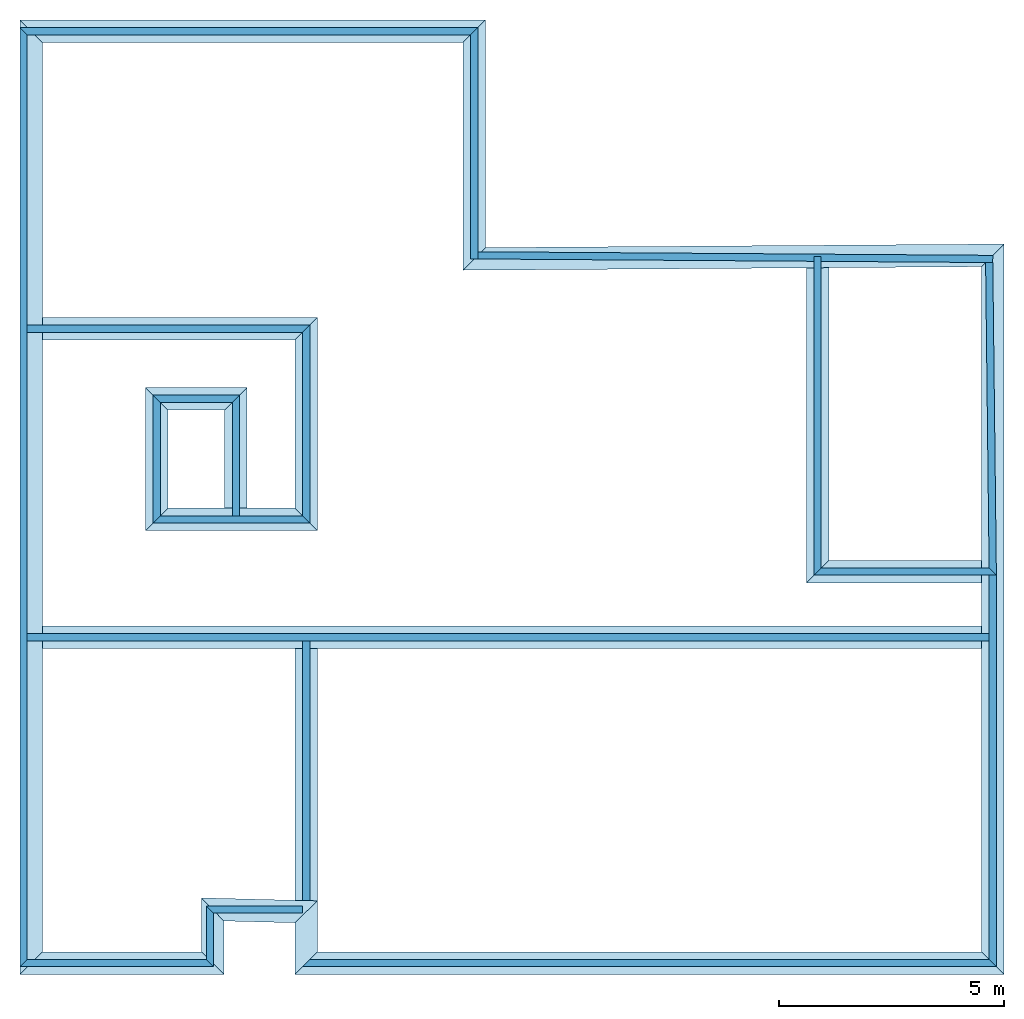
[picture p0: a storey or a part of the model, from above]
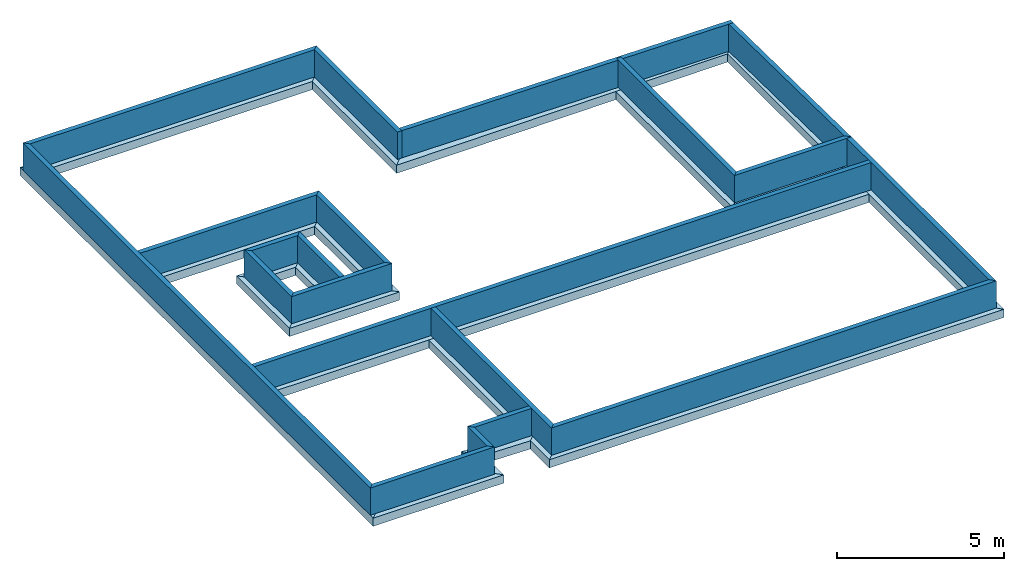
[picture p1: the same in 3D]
Properties of the parts of a building model (IFC2X3), part 4 of 6

# IfcWallStandardCase: Hachure solide 3821565075 20 (36)
Name | ID Elément entier = ID Elément compact | Nom de Zone | Numéro de Zone | Hauteur (m) | Superficie de surface (m2) = Surface de mur nette sur face extérieure (m2) = Surface de mur nette sur face intérieure (m2) | Volume net (m3) | Superficie (m2) = Surface du Mur (m2) | Longueur de mur sur face extérieure (m) | Longueur de mur sur face intérieure (m) | Surface nette des arêtes (m2) | Volume conditionnel (m3) | Nombre de Portes | Largeur totale des Portes (m) | Hauteur maximum du Mur (m) | Longueur du Mur au centre (m) = Longueur moyenne (m) | Périmètre du Mur (m) | Surface brute de mur sur face intérieure (m2) = Surface brute de mur sur face extérieure (m2) | Volume brut du Mur (m3) | Surface analytique des ouvertures sur face intérieure (m2) = Surface analytique des ouvertures sur face extérieure (m2) | Volume analytique des ouvertures dans le Mur (m3) | Longueur conditionnelle sur face extérieure (m) | Longueur conditionnelle sur face intérieure (m) | Surface conditionnelle sur face extérieure (m2) = Surface conditionnelle sur face intérieure (m2) | Longueur de ligne de référence (m) | Surface des portes dans le mur (m2)
Mur-022 | Mur-022 | Sanit Vest 2 | 010 | 1.85 | 2.9503 | 0.0590059 | 0.0318951 | 1.59476 | 1.59476 | 0.0637902 | 0.0590059 | 0 | 0 | 1.85 | 1.59476 | 3.22951 | 3.3573 | 0.0671459 | 0 | 0 | 1.59476 | 1.59476 | 2.9503 | 1.64476 | 0
Mur-022 | Mur-022 | Sanit Vest 1 | 010 | 1.85 | 2.9503 | 0.0590059 | 0.0318951 | 1.59476 | 1.59476 | 0.0637902 | 0.0590059 | 0 | 0 | 1.85 | 1.59476 | 3.22951 | 3.1723 | 0.0634459 | 0 | 0 | 1.59476 | 1.59476 | 2.9503 | 1.64476 | 0
Mur-022 | Mur-022 | Sanit Vest 3 | 010 | 1.85 | 2.9873 | 0.0597459 | 0.0320951 | 1.61476 | 1.59476 | 0.10159 | 0.0597459 | 0 | 0 | 1.85 | 1.60476 | 3.25779 | 2.9873 | 0.0597459 | 0 | 0 | 1.61476 | 1.59476 | 2.9873 | 1.59476 | 0
Mur-022 | Mur-022 | Sanit Vest 4 | 010 | 1.85 | 2.9873 | 0.0597459 | 0.0320951 | 1.59476 | 1.61476 | 0.10159 | 0.0597459 | 0 | 0 | 1.85 | 1.60476 | 3.25779 | 2.9873 | 0.0597459 | 0 | 0 | 1.59476 | 1.61476 | 2.9873 | 1.59476 | 0
2 x Mur-022 | Mur-022 |  |  | 1.85 | 2.18274 | 0.0436548 | 0.103397 | 5.17986 | 5.15986 | 0.0841944 | 0.190915 | 5 | 3.98 | 1.85 | 5.16986 | 10.388 | 9.58274 | 0.191655 | 7.363 | 0.14726 | 1.19986 | 1.17986 | 9.54574 | 5.15986 | 7.4426
Mur-023 | Mur-023 | Sanit Vest 3 | 010 | 1.85 | 2.9503 | 0.0590059 | 0.0318951 | 1.59476 | 1.59476 | 0.0637902 | 0.0590059 | 0 | 0 | 1.85 | 1.59476 | 3.22951 | 3.1723 | 0.0634459 | 0 | 0 | 1.59476 | 1.59476 | 2.9503 | 1.64476 | 0
Mur-023 | Mur-023 | Sanit Vest 4 | 010 | 1.85 | 2.9503 | 0.0590059 | 0.0318951 | 1.59476 | 1.59476 | 0.0637902 | 0.0590059 | 0 | 0 | 1.85 | 1.59476 | 3.22951 | 3.1723 | 0.0634459 | 0 | 0 | 1.59476 | 1.59476 | 2.9503 | 1.64476 | 0
2 x Mur-022 | Mur-022 | Sanit Vest 3 | 010 | 1.85 | 2.9503 | 0.0590059 | 0.0318951 | 1.59476 | 1.59476 | 0.0637902 | 0.0590059 | 0 | 0 | 1.85 | 1.59476 | 3.22951 | 3.3573 | 0.0671459 | 0 | 0 | 1.59476 | 1.59476 | 2.9503 | 1.64476 | 0
2 x Mur-022 | Mur-022 | Sanit Vest 4 | 010 | 1.85 | 2.9503 | 0.0590059 | 0.0318951 | 1.59476 | 1.59476 | 0.0637902 | 0.0590059 | 0 | 0 | 1.85 | 1.59476 | 3.22951 | 3.1723 | 0.0634459 | 0 | 0 | 1.59476 | 1.59476 | 2.9503 | 1.64476 | 0

# IfcWallStandardCase: Hachure solide* 1842511997 160 (3)
In: NIVEAU BAS GYMNASE
Material: Hachure solide* 1842511997 0.16 m
ArchiCADProperties - ID Elément entier: Mur-004; ID Elément compact: Mur-004; Etage d'implantation: NIVEAU BAS GYMNASE; Numéro de Zone: 010; Calque: Murs Ext: Périphériques.Importation IFC; Type: Mur; Verrouillé: no; Matériau de construction / Composite / Profil / Hachure: Hachure solide* 1842511997; Fonction structurelle: Non défini; Position: Non défini; Classification d'élement: Type ArchiCAD; Etat de rénovation: Existant; Afficher sur filtre de rénovation: Tous les filtres appropriés; Type de structure: Basique; Matériau de construction / Composite / Profil: Hachure solide* 1842511997; Angle d'inclinaison externe: 90 deg; Angle d'inclinaison interne: 90 deg; Type d'inclinaison de mur: Droit; Emplacement de ligne de référence: Face extérieure; Etage supérieur lié: Non lié; Option de géométrie: Uniforme
AC_Pset_RenovationAndPhasing - Renovation Status: Existing
ArchiCADQuantities - Altitude à Zéro du Projet: 0 m; Altitude à étage: 0 m; Epaisseur: 0.16 m; Nombre de trous (Nombre d'ouvertures vides): 0; Nombre de Poteaux: 0; Epaisseur du Mur à la fin: 0.16 m; Hauteur minimum du Mur: 0 m; Epaisseur de couche de mur sur face extérieure: 0 m; Epaisseur de couche de mur sur face intérieure: 0 m; Epaisseur couche isolation: 0 m; Epaisseur couche d'air: 0 m; Hauteur de couche de mur minimum sur face extérieure: 0 m; Hauteur de couche de mur maximum sur face extérieure: 0 m; Hauteur de couche de mur minimum sur face intérieure: 0 m; Hauteur de couche de mur maximum sur face intérieure: 0 m; Volume de couche de mur sur face extérieure: 0 m3; Volume de couche de mur sur face intérieure: 0 m3; Volume de couche de mur conditionnelle sur face extérieure: 0 m3; Volume de couche de mur conditionnelle sur face intérieure: 0 m3; Décalage étage d'implantation: 0 m; Décalage supérieur: -0.12 m; Surface des baies libres dans le mur: 0 m2; Volume de poteaux: 0 m3
Name | Nom de Zone | Surface de face extérieure = Surface de face intérieure = Surface latérale | Hauteur (m) = Hauteur maximum du Mur (m) | Superficie de surface (m2) = Surface de mur nette sur face extérieure (m2) | Volume net (m3) | Superficie (m2) = Surface du Mur (m2) | Longueur de mur sur face extérieure (m) | Longueur de mur sur face intérieure (m) | Surface de mur nette sur face intérieure (m2) | Surface nette des arêtes (m2) | Volume conditionnel (m3) | Nombre de Portes | Nombre de Fenêtres | Largeur totale des Portes (m) | Largeur totale des Fenêtres (m) | Longueur du Mur au centre (m) = Longueur moyenne (m) | Périmètre du Mur (m) | Surface brute de mur sur face intérieure (m2) = Surface brute de mur sur face extérieure (m2) | Volume brut du Mur (m3) | Surface analytique des ouvertures sur face intérieure (m2) = Surface analytique des ouvertures sur face extérieure (m2) | Volume analytique des ouvertures dans le Mur (m3) | Longueur conditionnelle sur face extérieure (m) | Longueur conditionnelle sur face intérieure (m) | Surface conditionnelle sur face extérieure (m2) | Surface conditionnelle sur face intérieure (m2) | Longueur de ligne de référence (m) | Surface des fenêtres dans le mur (m2) | Surface des portes dans le mur (m2)
Mur-004 | Hall & Circulation | Revêt-murs int. | 2.8 | 31.3845 | 5.02005 | 2.29833 | 14.4446 | 14.2846 | 31.2365 | 4.09266 | 6.46968 | 4 | 0 | 3.56 | 0 | 14.3646 | 29.1154 | 40.4447 | 6.47116 | 9.0602 | 1.44963 | 10.8846 | 10.7246 | 31.3845 | 31.2365 | 14.4446 | 0 | 9.0958
Mur-004 | Chaufferie | BETON65 | 2.75 | 1.025 | 0.164 | 0.1568 | 0.9 | 1.06 | 1.025 | 0.1952 | 0.4664 | 1 | 0 | 0.9 | 0 | 0.98 | 2.34627 | 3.905 | 0.6248 | 1.89 | 0.3024 | 0 | 0.16 | 2.915 | 2.915 | 1.16 | 0 | 1.89
Mur-004 | Chaufferie | BETON65 | 2.8 | 0.447921 | 0.0716673 | 0.111271 | 0.615447 | 0.775447 | 0.447921 | 0.180943 | 0.27492 | 0 | 1 | 0 | 0.615447 | 0.695447 | 1.77717 | 2.61125 | 0.4178 | 1.27033 | 0.203253 | 0.615447 | 0.775447 | 1.71825 | 1.71825 | 0.775447 | 1.27033 | 0

# IfcWallStandardCase: Hachure solide* 2593434267 160 (2)
In: NIVEAU BAS GYMNASE
Material: Hachure solide* 2593434267 0.16 m
ArchiCADProperties - Etage d'implantation: NIVEAU BAS GYMNASE; Numéro de Zone: 010; Calque: Murs Ext: Périphériques.Importation IFC; Type: Mur; Verrouillé: no; Matériau de construction / Composite / Profil / Hachure: Hachure solide* 2593434267; Fonction structurelle: Non défini; Position: Non défini; Classification d'élement: Type ArchiCAD; Etat de rénovation: Existant; Afficher sur filtre de rénovation: Tous les filtres appropriés; Type de structure: Basique; Matériau de construction / Composite / Profil: Hachure solide* 2593434267; Angle d'inclinaison externe: 90 deg; Angle d'inclinaison interne: 90 deg; Type d'inclinaison de mur: Droit; Emplacement de ligne de référence: Face extérieure; Etage supérieur lié: Non lié; Option de géométrie: Uniforme
AC_Pset_RenovationAndPhasing - Renovation Status: Existing
ArchiCADQuantities - Epaisseur: 0.16 m; Nombre de Portes: 1; Nombre de Fenêtres: 0; Nombre de trous (Nombre d'ouvertures vides): 0; Nombre de Poteaux: 0; Largeur totale des Fenêtres: 0 m; Epaisseur du Mur à la fin: 0.16 m; Hauteur minimum du Mur: 0 m; Epaisseur de couche de mur sur face extérieure: 0 m; Epaisseur de couche de mur sur face intérieure: 0 m; Epaisseur couche isolation: 0 m; Epaisseur couche d'air: 0 m; Hauteur de couche de mur minimum sur face extérieure: 0 m; Hauteur de couche de mur maximum sur face extérieure: 0 m; Hauteur de couche de mur minimum sur face intérieure: 0 m; Hauteur de couche de mur maximum sur face intérieure: 0 m; Volume de couche de mur sur face extérieure: 0 m3; Volume de couche de mur sur face intérieure: 0 m3; Volume de couche de mur conditionnelle sur face extérieure: 0 m3; Volume de couche de mur conditionnelle sur face intérieure: 0 m3; Décalage supérieur: -0.12 m; Surface des fenêtres dans le mur: 0 m2; Surface des baies libres dans le mur: 0 m2; Volume de poteaux: 0 m3
Name | ID Elément entier = ID Elément compact | Nom de Zone | Surface de face extérieure = Surface de face intérieure = Surface latérale | Altitude à Zéro du Projet (m) = Altitude à étage (m) = Décalage étage d'implantation (m) | Hauteur (m) = Hauteur maximum du Mur (m) | Superficie de surface (m2) = Surface de mur nette sur face extérieure (m2) = Surface de mur nette sur face intérieure (m2) = Surface conditionnelle sur face extérieure (m2) = Surface conditionnelle sur face intérieure (m2) | Volume net (m3) | Superficie (m2) = Surface du Mur (m2) | Longueur de mur sur face extérieure (m) | Longueur de mur sur face intérieure (m) | Surface nette des arêtes (m2) | Volume conditionnel (m3) | Largeur totale des Portes (m) | Longueur du Mur au centre (m) = Longueur moyenne (m) | Périmètre du Mur (m) | Surface brute de mur sur face intérieure (m2) = Surface brute de mur sur face extérieure (m2) | Volume brut du Mur (m3) | Surface analytique des ouvertures sur face intérieure (m2) = Surface analytique des ouvertures sur face extérieure (m2) | Volume analytique des ouvertures dans le Mur (m3) | Longueur conditionnelle sur face extérieure (m) | Longueur conditionnelle sur face intérieure (m) | Longueur de ligne de référence (m) | Surface des portes dans le mur (m2)
Mur-005 | Mur-005 | Dépot 3 | BETON65 | 0 | 3 | 18.725 | 2.996 | 0.9984 | 6.24 | 6.24 | 2.48 | 2.996 | 3.475 | 6.24 | 12.8 | 19.56 | 3.1296 | 0 | 0 | 6.24 | 6.24 | 6.52 | 6.95
Mur-022 | Mur-022 | Chaufferie | Peinture-09 | -0.2 | 2.95 | 18.2875 | 2.926 | 1.1376 | 7.19 | 7.03 | 2.184 | 3.31576 | 1.2 | 7.11 | 14.6063 | 21.2105 | 3.39368 | 2.436 | 0.38976 | 6.03 | 5.87 | 7.19 | 2.52

# IfcWallStandardCase: Hachure solide* 3893414420 450, Mur-002
In: NIVEAU BAS GYMNASE
Material: Hachure solide* 3893414420 0.45 m
ArchiCADProperties - ID Elément entier: Mur-002; ID Elément compact: Mur-002; Etage d'implantation: NIVEAU BAS GYMNASE; Nom de Zone: Grande Salle de Jeux; Numéro de Zone: 010; Calque: Murs Ext: Périphériques.Importation IFC; Type: Mur; Verrouillé: no; Matériau de construction / Composite / Profil / Hachure: Hachure solide* 3893414420; Fonction structurelle: Non défini; Position: Non défini; Classification d'élement: Type ArchiCAD; Etat de rénovation: Existant; Afficher sur filtre de rénovation: Tous les filtres appropriés; Type de structure: Basique; Matériau de construction / Composite / Profil: Hachure solide* 3893414420; Surface de face extérieure: BETON65; Surface de face intérieure: BETON65; Surface latérale: BETON65; Angle d'inclinaison externe: 90 deg; Angle d'inclinaison interne: 90 deg; Type d'inclinaison de mur: Droit; Emplacement de ligne de référence: Face extérieure; Etage supérieur lié: Non lié; Option de géométrie: Uniforme
AC_Pset_RenovationAndPhasing - Renovation Status: Existing
ArchiCADQuantities - Altitude à Zéro du Projet: -0.2 m; Altitude à étage: -0.2 m; Hauteur: 4.66 m; Superficie de surface: 103.537 m2; Volume net: 46.5917 m3; Superficie: 9.9855 m2; Epaisseur: 0.45 m; Longueur de mur sur face extérieure: 22.07 m; Longueur de mur sur face intérieure: 22.31 m; Surface de mur nette sur face extérieure: 103.537 m2; Surface de mur nette sur face intérieure: 103.537 m2; Surface nette des arêtes: 22.0635 m2; Volume conditionnel: 46.5917 m3; Nombre de Portes: 0; Nombre de Fenêtres: 0; Nombre de trous (Nombre d'ouvertures vides): 0; Nombre de Poteaux: 1; Largeur totale des Portes: 0 m; Largeur totale des Fenêtres: 0 m; Epaisseur du Mur à la fin: 0.45 m; Hauteur minimum du Mur: 0 m; Hauteur maximum du Mur: 4.66 m; Longueur du Mur au centre: 22.19 m; Surface du Mur: 9.9855 m2; Périmètre du Mur: 45.34 m; Surface brute de mur sur face intérieure: 103.965 m2; Surface brute de mur sur face extérieure: 103.965 m2; Volume brut du Mur: 46.7841 m3; Surface analytique des ouvertures sur face intérieure: 0 m2; Surface analytique des ouvertures sur face extérieure: 0 m2; Volume analytique des ouvertures dans le Mur: 0 m3; Epaisseur de couche de mur sur face extérieure: 0 m; Epaisseur de couche de mur sur face intérieure: 0 m; Epaisseur couche isolation: 0 m; Epaisseur couche d'air: 0 m; Hauteur de couche de mur minimum sur face extérieure: 0 m; Hauteur de couche de mur maximum sur face extérieure: 0 m; Hauteur de couche de mur minimum sur face intérieure: 0 m; Hauteur de couche de mur maximum sur face intérieure: 0 m; Longueur conditionnelle sur face extérieure: 22.07 m; Longueur conditionnelle sur face intérieure: 22.31 m; Surface conditionnelle sur face extérieure: 103.537 m2; Surface conditionnelle sur face intérieure: 103.537 m2; Volume de couche de mur sur face extérieure: 0 m3; Volume de couche de mur sur face intérieure: 0 m3; Volume de couche de mur conditionnelle sur face extérieure: 0 m3; Volume de couche de mur conditionnelle sur face intérieure: 0 m3; Longueur de ligne de référence: 22.31 m; Décalage étage d'implantation: -0.2 m; Décalage supérieur: -0.12 m; Longueur moyenne: 22.19 m; Surface des fenêtres dans le mur: 0 m2; Surface des portes dans le mur: 0 m2; Surface des baies libres dans le mur: 0 m2; Volume de poteaux: 0 m3

# IfcWallStandardCase: Hachure solide* 3914859788 160, Mur-004
In: NIVEAU BAS GYMNASE
Material: Hachure solide* 3914859788 0.16 m
ArchiCADProperties - ID Elément entier: Mur-004; ID Elément compact: Mur-004; Etage d'implantation: NIVEAU BAS GYMNASE; Nom de Zone: Hall & Circulation; Numéro de Zone: 010; Calque: Murs Ext: Périphériques.Importation IFC; Type: Mur; Verrouillé: no; Matériau de construction / Composite / Profil / Hachure: Hachure solide* 3914859788; Fonction structurelle: Non défini; Position: Non défini; Classification d'élement: Type ArchiCAD; Etat de rénovation: Existant; Afficher sur filtre de rénovation: Tous les filtres appropriés; Type de structure: Basique; Matériau de construction / Composite / Profil: Hachure solide* 3914859788; Surface de face extérieure: BETON65; Surface de face intérieure: BETON65; Surface latérale: BETON65; Angle d'inclinaison externe: 90 deg; Angle d'inclinaison interne: 90 deg; Type d'inclinaison de mur: Droit; Emplacement de ligne de référence: Face extérieure; Etage supérieur lié: Non lié; Option de géométrie: Uniforme
AC_Pset_RenovationAndPhasing - Renovation Status: Existing
ArchiCADQuantities - Altitude à Zéro du Projet: 0 m; Altitude à étage: 0 m; Hauteur: 2.75 m; Superficie de surface: 19.195 m2; Volume net: 3.0712 m3; Superficie: 1.1296 m2; Epaisseur: 0.16 m; Longueur de mur sur face extérieure: 7.14 m; Longueur de mur sur face intérieure: 6.98 m; Surface de mur nette sur face extérieure: 19.195 m2; Surface de mur nette sur face intérieure: 19.195 m2; Surface nette des arêtes: 2.2336 m2; Volume conditionnel: 3.0712 m3; Nombre de Portes: 0; Nombre de Fenêtres: 0; Nombre de trous (Nombre d'ouvertures vides): 0; Nombre de Poteaux: 0; Largeur totale des Portes: 0 m; Largeur totale des Fenêtres: 0 m; Epaisseur du Mur à la fin: 0.16 m; Hauteur minimum du Mur: 0 m; Hauteur maximum du Mur: 2.75 m; Longueur du Mur au centre: 7.06 m; Surface du Mur: 1.1296 m2; Périmètre du Mur: 14.5063 m; Surface brute de mur sur face intérieure: 20.35 m2; Surface brute de mur sur face extérieure: 20.35 m2; Volume brut du Mur: 3.256 m3; Surface analytique des ouvertures sur face intérieure: 0 m2; Surface analytique des ouvertures sur face extérieure: 0 m2; Volume analytique des ouvertures dans le Mur: 0 m3; Epaisseur de couche de mur sur face extérieure: 0 m; Epaisseur de couche de mur sur face intérieure: 0 m; Epaisseur couche isolation: 0 m; Epaisseur couche d'air: 0 m; Hauteur de couche de mur minimum sur face extérieure: 0 m; Hauteur de couche de mur maximum sur face extérieure: 0 m; Hauteur de couche de mur minimum sur face intérieure: 0 m; Hauteur de couche de mur maximum sur face intérieure: 0 m; Longueur conditionnelle sur face extérieure: 7.14 m; Longueur conditionnelle sur face intérieure: 6.98 m; Surface conditionnelle sur face extérieure: 19.195 m2; Surface conditionnelle sur face intérieure: 19.195 m2; Volume de couche de mur sur face extérieure: 0 m3; Volume de couche de mur sur face intérieure: 0 m3; Volume de couche de mur conditionnelle sur face extérieure: 0 m3; Volume de couche de mur conditionnelle sur face intérieure: 0 m3; Longueur de ligne de référence: 7.24 m; Décalage étage d'implantation: 0 m; Décalage supérieur: -0.12 m; Longueur moyenne: 7.06 m; Surface des fenêtres dans le mur: 0 m2; Surface des portes dans le mur: 0 m2; Surface des baies libres dans le mur: 0 m2; Volume de poteaux: 0 m3

# IfcWallStandardCase: Hachure solide* 3919599173 160, Mur-004
In: NIVEAU BAS GYMNASE
Material: Hachure solide* 3919599173 0.16 m
ArchiCADProperties - ID Elément entier: Mur-004; ID Elément compact: Mur-004; Etage d'implantation: NIVEAU BAS GYMNASE; Nom de Zone: Local Nettoyage Ent.; Numéro de Zone: 010; Calque: Murs Ext: Périphériques.Importation IFC; Type: Mur; Verrouillé: no; Matériau de construction / Composite / Profil / Hachure: Hachure solide* 3919599173; Fonction structurelle: Non défini; Position: Non défini; Classification d'élement: Type ArchiCAD; Etat de rénovation: Existant; Afficher sur filtre de rénovation: Tous les filtres appropriés; Type de structure: Basique; Matériau de construction / Composite / Profil: Hachure solide* 3919599173; Surface de face extérieure: BETON65; Surface de face intérieure: BETON65; Surface latérale: BETON65; Angle d'inclinaison externe: 90 deg; Angle d'inclinaison interne: 90 deg; Type d'inclinaison de mur: Droit; Emplacement de ligne de référence: Face extérieure; Etage supérieur lié: Non lié; Option de géométrie: Uniforme
AC_Pset_RenovationAndPhasing - Renovation Status: Existing
ArchiCADQuantities - Altitude à Zéro du Projet: 0 m; Altitude à étage: 0 m; Hauteur: 3 m; Superficie de surface: 11.648 m2; Volume net: 1.86368 m3; Superficie: 0.6576 m2; Epaisseur: 0.16 m; Longueur de mur sur face extérieure: 4.16 m; Longueur de mur sur face intérieure: 4.06 m; Surface de mur nette sur face extérieure: 11.648 m2; Surface de mur nette sur face intérieure: 11.648 m2; Surface nette des arêtes: 0.6656 m2; Volume conditionnel: 1.86368 m3; Nombre de Portes: 0; Nombre de Fenêtres: 0; Nombre de trous (Nombre d'ouvertures vides): 0; Nombre de Poteaux: 0; Largeur totale des Portes: 0 m; Largeur totale des Fenêtres: 0 m; Epaisseur du Mur à la fin: 0.16 m; Hauteur minimum du Mur: 0 m; Hauteur maximum du Mur: 2.8 m; Longueur du Mur au centre: 4.11 m; Surface du Mur: 0.6576 m2; Périmètre du Mur: 8.56868 m; Surface brute de mur sur face intérieure: 12.942 m2; Surface brute de mur sur face extérieure: 12.942 m2; Volume brut du Mur: 2.07072 m3; Surface analytique des ouvertures sur face intérieure: 0 m2; Surface analytique des ouvertures sur face extérieure: 0 m2; Volume analytique des ouvertures dans le Mur: 0 m3; Epaisseur de couche de mur sur face extérieure: 0 m; Epaisseur de couche de mur sur face intérieure: 0 m; Epaisseur couche isolation: 0 m; Epaisseur couche d'air: 0 m; Hauteur de couche de mur minimum sur face extérieure: 0 m; Hauteur de couche de mur maximum sur face extérieure: 0 m; Hauteur de couche de mur minimum sur face intérieure: 0 m; Hauteur de couche de mur maximum sur face intérieure: 0 m; Longueur conditionnelle sur face extérieure: 4.16 m; Longueur conditionnelle sur face intérieure: 4.06 m; Surface conditionnelle sur face extérieure: 11.648 m2; Surface conditionnelle sur face intérieure: 11.648 m2; Volume de couche de mur sur face extérieure: 0 m3; Volume de couche de mur sur face intérieure: 0 m3; Volume de couche de mur conditionnelle sur face extérieure: 0 m3; Volume de couche de mur conditionnelle sur face intérieure: 0 m3; Longueur de ligne de référence: 4.06 m; Décalage étage d'implantation: 0 m; Décalage supérieur: -0.12 m; Longueur moyenne: 4.11 m; Surface des fenêtres dans le mur: 0 m2; Surface des portes dans le mur: 0 m2; Surface des baies libres dans le mur: 0 m2; Volume de poteaux: 0 m3

# IfcWallStandardCase: Hachure solide* 3919599173 450, Mur-002
In: NIVEAU BAS GYMNASE
Material: Hachure solide* 3919599173 0.45 m
ArchiCADProperties - ID Elément entier: Mur-002; ID Elément compact: Mur-002; Etage d'implantation: NIVEAU BAS GYMNASE; Nom de Zone: Grande Salle de Jeux; Numéro de Zone: 010; Calque: Murs Ext: Périphériques.Importation IFC; Type: Mur; Verrouillé: no; Matériau de construction / Composite / Profil / Hachure: Hachure solide* 3919599173; Fonction structurelle: Non défini; Position: Non défini; Classification d'élement: Type ArchiCAD; Etat de rénovation: Existant; Afficher sur filtre de rénovation: Tous les filtres appropriés; Type de structure: Basique; Matériau de construction / Composite / Profil: Hachure solide* 3919599173; Surface de face extérieure: BETON65; Surface de face intérieure: BETON65; Surface latérale: BETON65; Angle d'inclinaison externe: 90 deg; Angle d'inclinaison interne: 90 deg; Type d'inclinaison de mur: Droit; Emplacement de ligne de référence: Face extérieure; Etage supérieur lié: Non lié; Option de géométrie: Uniforme
AC_Pset_RenovationAndPhasing - Renovation Status: Existing
ArchiCADQuantities - Altitude à Zéro du Projet: -0.2 m; Altitude à étage: -0.2 m; Hauteur: 4.66 m; Superficie de surface: 108.281 m2; Volume net: 48.7266 m3; Superficie: 10.4563 m2; Epaisseur: 0.45 m; Longueur de mur sur face extérieure: 23.2363 m; Longueur de mur sur face intérieure: 23.2363 m; Surface de mur nette sur face extérieure: 108.281 m2; Surface de mur nette sur face intérieure: 108.281 m2; Surface nette des arêtes: 25.1067 m2; Volume conditionnel: 48.7266 m3; Nombre de Portes: 0; Nombre de Fenêtres: 0; Nombre de trous (Nombre d'ouvertures vides): 0; Nombre de Poteaux: 0; Largeur totale des Portes: 0 m; Largeur totale des Fenêtres: 0 m; Epaisseur du Mur à la fin: 0.45 m; Hauteur minimum du Mur: 4.66 m; Hauteur maximum du Mur: 4.66 m; Longueur du Mur au centre: 23.2363 m; Surface du Mur: 10.4563 m2; Périmètre du Mur: 47.3727 m; Surface brute de mur sur face intérieure: 108.281 m2; Surface brute de mur sur face extérieure: 108.281 m2; Volume brut du Mur: 48.7266 m3; Surface analytique des ouvertures sur face intérieure: 0 m2; Surface analytique des ouvertures sur face extérieure: 0 m2; Volume analytique des ouvertures dans le Mur: 0 m3; Epaisseur de couche de mur sur face extérieure: 0 m; Epaisseur de couche de mur sur face intérieure: 0 m; Epaisseur couche isolation: 0 m; Epaisseur couche d'air: 0 m; Hauteur de couche de mur minimum sur face extérieure: 0 m; Hauteur de couche de mur maximum sur face extérieure: 0 m; Hauteur de couche de mur minimum sur face intérieure: 0 m; Hauteur de couche de mur maximum sur face intérieure: 0 m; Longueur conditionnelle sur face extérieure: 23.2363 m; Longueur conditionnelle sur face intérieure: 23.2363 m; Surface conditionnelle sur face extérieure: 108.281 m2; Surface conditionnelle sur face intérieure: 108.281 m2; Volume de couche de mur sur face extérieure: 0 m3; Volume de couche de mur sur face intérieure: 0 m3; Volume de couche de mur conditionnelle sur face extérieure: 0 m3; Volume de couche de mur conditionnelle sur face intérieure: 0 m3; Longueur de ligne de référence: 23.2363 m; Décalage étage d'implantation: -0.2 m; Décalage supérieur: -0.12 m; Longueur moyenne: 23.2363 m; Surface des fenêtres dans le mur: 0 m2; Surface des portes dans le mur: 0 m2; Surface des baies libres dans le mur: 0 m2; Volume de poteaux: 0 m3

# IfcWallStandardCase: Hachure solide* 3962059836 100 (25)
Material: Hachure solide* 3962059836 0.1 m
ArchiCADProperties - Calque: Murs Ext: Périphériques.Importation IFC; Type: Mur; Verrouillé: no; Matériau de construction / Composite / Profil / Hachure: Hachure solide* 3962059836; Fonction structurelle: Non défini; Position: Non défini; Classification d'élement: Type ArchiCAD; Etat de rénovation: Existant; Afficher sur filtre de rénovation: Tous les filtres appropriés; Type de structure: Basique; Matériau de construction / Composite / Profil: Hachure solide* 3962059836; Angle d'inclinaison externe: 90 deg; Angle d'inclinaison interne: 90 deg; Type d'inclinaison de mur: Droit; Emplacement de ligne de référence: Face extérieure; Etage supérieur lié: Non lié; Option de géométrie: Uniforme
AC_Pset_RenovationAndPhasing - Renovation Status: Existing
ArchiCADQuantities - Altitude à étage: 0 m; Epaisseur: 0.1 m; Nombre de trous (Nombre d'ouvertures vides): 0; Nombre de Poteaux: 0; Epaisseur du Mur à la fin: 0.1 m; Epaisseur de couche de mur sur face extérieure: 0 m; Epaisseur de couche de mur sur face intérieure: 0 m; Epaisseur couche isolation: 0 m; Epaisseur couche d'air: 0 m; Hauteur de couche de mur minimum sur face extérieure: 0 m; Hauteur de couche de mur maximum sur face extérieure: 0 m; Hauteur de couche de mur minimum sur face intérieure: 0 m; Hauteur de couche de mur maximum sur face intérieure: 0 m; Volume de couche de mur sur face extérieure: 0 m3; Volume de couche de mur sur face intérieure: 0 m3; Volume de couche de mur conditionnelle sur face extérieure: 0 m3; Volume de couche de mur conditionnelle sur face intérieure: 0 m3; Décalage étage d'implantation: 0 m; Décalage supérieur: -0.12 m; Surface des baies libres dans le mur: 0 m2; Volume de poteaux: 0 m3
Name | In | ID Elément entier = ID Elément compact | Etage d'implantation | Nom de Zone | Numéro de Zone | Surface de face extérieure = Surface de face intérieure = Surface latérale | Altitude à Zéro du Projet (m) | Hauteur (m) | Superficie de surface (m2) = Surface de mur nette sur face extérieure (m2) = Surface de mur nette sur face intérieure (m2) | Volume net (m3) | Superficie (m2) = Surface du Mur (m2) | Longueur de mur sur face extérieure (m) | Longueur de mur sur face intérieure (m) | Surface nette des arêtes (m2) | Volume conditionnel (m3) | Nombre de Portes | Nombre de Fenêtres | Largeur totale des Portes (m) | Largeur totale des Fenêtres (m) | Hauteur minimum du Mur (m) | Hauteur maximum du Mur (m) | Longueur du Mur au centre (m) = Longueur moyenne (m) | Périmètre du Mur (m) | Surface brute de mur sur face intérieure (m2) = Surface brute de mur sur face extérieure (m2) | Volume brut du Mur (m3) | Surface analytique des ouvertures sur face intérieure (m2) = Surface analytique des ouvertures sur face extérieure (m2) | Volume analytique des ouvertures dans le Mur (m3) | Longueur conditionnelle sur face extérieure (m) | Longueur conditionnelle sur face intérieure (m) | Surface conditionnelle sur face extérieure (m2) = Surface conditionnelle sur face intérieure (m2) | Longueur de ligne de référence (m) | Surface des fenêtres dans le mur (m2) | Surface des portes dans le mur (m2)
Mur-004 | NIVEAU BAS GYMNASE | Mur-004 | NIVEAU BAS GYMNASE | Bureau Arbitre | 006 | BETON65 | 0 | 2.8 | 0.87645 | 0.087645 | 0.084 | 0.79 | 0.89 | 0.099 | 0.2492 | 1 | 0 | 0.79 | 0 | 0 | 2.8 | 0.84 | 1.92142 | 3.22 | 0.322 | 1.61555 | 0.161555 | 3.24101e-09 | 0.1 | 2.492 | 0.79 | 0 | 1.62345
Mur-004 | NIVEAU BAS GYMNASE | Mur-004 | NIVEAU BAS GYMNASE | Bureau Arbitre | 006 | BETON65 | 0 | 2.8 | 3.92 | 0.392 | 0.145 | 1.4 | 1.5 | 0.28 | 0.392 | 0 | 0 | 0 | 0 | 0 | 2.8 | 1.45 | 3.14142 | 4.648 | 0.4648 | 0 | 0 | 1.4 | 1.5 | 3.92 | 1.4 | 0 | 0
Mur-004 | NIVEAU BAS GYMNASE | Mur-004 | NIVEAU BAS GYMNASE | Bureau Arbitre | 006 | BETON65 | 0 | 2.8 | 3.92 | 0.392 | 0.14 | 1.4 | 1.4 | 0.28 | 0.392 | 0 | 0 | 0 | 0 | 0 | 2.8 | 1.4 | 3 | 4.816 | 0.4816 | 0 | 0 | 1.4 | 1.4 | 3.92 | 1.4 | 0 | 0
Mur-001 | NIVEAU BAS GYMNASE | Mur-001 | NIVEAU BAS GYMNASE | Sanit Prof F | 010 | BETON65 | 0 | 2.8 | 7.1749 | 0.71749 | 0.413 | 4.18 | 4.08 | 0.66 | 1.1705 | 2 | 0 | 1.78 | 0 | 0 | 2.8 | 4.13 | 8.50142 | 12.488 | 1.2488 | 4.5301 | 0.45301 | 2.4 | 2.3 | 7.1749 | 4.36 | 0 | 4.5479
Mur-005 | NIVEAU BAS GYMNASE | Mur-005 | NIVEAU BAS GYMNASE |  |  | BETON65 | 0 | 2.8 | 3.62145 | 0.362145 | 0.187 | 1.87 | 1.87 | 0.297 | 0.5237 | 1 | 0 | 0.79 | 0 | 0 | 2.8 | 1.87 | 3.94 | 6.3 | 0.63 | 1.61555 | 0.161555 | 1.08 | 1.08 | 5.237 | 2.25 | 0 | 1.62345
Mur-004 | NIVEAU BAS GYMNASE | Mur-004 | NIVEAU BAS GYMNASE | Sanit Prof F | 010 | BETON65 | 0 | 3 | 8.596 | 0.8596 | 0.307 | 3.07 | 3.07 | 0.307 | 0.8596 | 0 | 0 | 0 | 0 | 0 | 2.8 | 3.07 | 6.34 | 9.958 | 0.9958 | 0 | 0 | 3.07 | 3.07 | 8.596 | 3.17 | 0 | 0
Mur-006 | NIVEAU BAS GYMNASE | Mur-006 | NIVEAU BAS GYMNASE | Hall & Circulation | 010 | BETON65 | 0 | 1 | 1.03077 | 0.103077 | 0.103077 | 1.03077 | 1.03077 | 0.306155 | 0.103077 | 0 | 0 | 0 | 0 | 0 | 1 | 1.03077 | 2.26155 | 1.13077 | 0.113077 | 0 | 0 | 1.03077 | 1.03077 | 1.03077 | 1.13077 | 0 | 0
Mur-004 | NIVEAU BAS GYMNASE | Mur-004 | NIVEAU BAS GYMNASE | Hall & Circulation | 010 | BETON65 | 0 | 3 | 8.596 | 0.8596 | 0.32 | 3.07 | 3.33 | 0.307 | 0.8596 | 0 | 0 | 0 | 0 | 0 | 2.8 | 3.2 | 6.7301 | 9.958 | 0.9958 | 0 | 0 | 3.07 | 3.33 | 8.596 | 3.17 | 0 | 0
Mur-004 | NIVEAU BAS GYMNASE | Mur-004 | NIVEAU BAS GYMNASE | Hall & Circulation | 010 | BETON65 | 0 | 2.82 | 7.91295 | 0.791295 | 0.3715 | 3.795 | 3.635 | 0.2745 | 1.0178 | 1 | 0 | 0.89 | 0 | 0 | 2.8 | 3.715 | 7.71868 | 10.9839 | 1.09839 | 2.26505 | 0.226505 | 2.905 | 2.745 | 7.91295 | 3.895 | 0 | 2.27395
Mur-007 | NIVEAU BAS GYMNASE | Mur-007 | NIVEAU BAS GYMNASE | Hall & Circulation | 010 | BETON65 | 0 | 2.82 | 10.4024 | 1.04024 | 0.366514 | 3.71514 | 3.61514 | 0.371514 | 1.04024 | 0 | 0 | 0 | 0 | 0 | 2.8 | 3.66514 | 7.57171 | 10.4767 | 1.04767 | 0 | 0 | 3.71514 | 3.61514 | 10.4024 | 3.71514 | 0 | 0
Mur-004 | NIVEAU BAS GYMNASE | Mur-004 | NIVEAU BAS GYMNASE | Local Nettoyage Ent. | 010 | BETON65 | 0 | 2.82 | 10.178 | 1.0178 | 0.3635 | 3.635 | 3.635 | 0.3635 | 1.0178 | 0 | 0 | 0 | 0 | 0 | 2.8 | 3.635 | 7.47 | 10.9839 | 1.09839 | 0 | 0 | 3.635 | 3.635 | 10.178 | 3.895 | 0 | 0
Mur-007 | NIVEAU BAS GYMNASE | Mur-007 | NIVEAU BAS GYMNASE | Sanit Vest 5 | 010 | BETON65 | 0 | 2.82 | 19.124 | 1.9124 | 0.683 | 6.83 | 6.83 | 0.963 | 1.9124 | 0 | 0 | 0 | 0 | 0 | 2.8 | 6.83 | 13.86 | 19.5426 | 1.95426 | 0 | 0 | 6.83 | 6.83 | 19.124 | 6.93 | 0 | 0
Mur-004 | NIVEAU BAS GYMNASE | Mur-004 | NIVEAU BAS GYMNASE | Hall & Circulation | 010 | BETON65 | 0 | 2.82 | 16.2039 | 1.62039 | 0.742 | 7.37 | 7.47 | 0.865 | 2.1634 | 2 | 1 | 1.78 | 2 | 2.545 | 2.8 | 7.42 | 15.0814 | 22.0686 | 2.20686 | 5.4301 | 0.54301 | 5.59 | 5.69 | 17.1039 | 7.63 | 0.9 | 4.5479
Mur-007 | NIVEAU BAS GYMNASE | Mur-007 | NIVEAU BAS GYMNASE | Sanit Vest 4 | 010 | RAL 5024 Bleu pastel | 0 | 1.85 | 12.913 | 1.2913 | 0.698 | 6.98 | 6.98 | 1.396 | 1.2913 | 0 | 0 | 0 | 0 | 0 | 1.85 | 6.98 | 14.16 | 13.69 | 1.369 | 0 | 0 | 6.98 | 6.98 | 12.913 | 7.24 | 0 | 0
2 x Mur-007 | NIVEAU BAS GYMNASE | Mur-007 | NIVEAU BAS GYMNASE | Sanit Vest 2 | 010 | RAL 5024 Bleu pastel | 0 | 1.85 | 12.913 | 1.2913 | 0.698 | 6.98 | 6.98 | 1.396 | 1.2913 | 0 | 0 | 0 | 0 | 0 | 1.85 | 6.98 | 14.16 | 13.69 | 1.369 | 0 | 0 | 6.98 | 6.98 | 12.913 | 7.24 | 0 | 0
Mur-002 | NIVEAU HAUT ENTRÉE | Mur-002 | NIVEAU HAUT ENTRÉE | Salle de Sport de Combat | 006 | BETON65 | 3 | 2.03 | 5.68858 | 0.568858 | 0.280226 | 2.80226 | 2.80226 | 0.763451 | 0.568858 | 0 | 0 | 0 | 0 | 0 | 2.03 | 2.80226 | 5.80451 | 5.89158 | 0.589158 | 0 | 0 | 2.80226 | 2.80226 | 5.68858 | 2.80226 | 0 | 0
Mur-007 | NIVEAU HAUT ENTRÉE | Mur-007 | NIVEAU HAUT ENTRÉE | Sanit Visit. F | 010 | BETON65 | 3 | 3.2 | 7.35278 | 0.735278 | 0.229774 | 2.29774 | 2.29774 | 0.459549 | 0.735278 | 0 | 0 | 0 | 0 | 0 | 3.2 | 2.29774 | 4.79549 | 8.50478 | 0.850478 | 0 | 0 | 2.29774 | 2.29774 | 7.35278 | 2.65774 | 0 | 0
Mur-007 | NIVEAU HAUT ENTRÉE | Mur-007 | NIVEAU HAUT ENTRÉE | Hall d'Entrée | 010 | BETON65 | 3 | 3.2 | 2.99658 | 0.299658 | 0.234774 | 2.39774 | 2.29774 | 0.252549 | 0.767278 | 3 | 0 | 2.27 | 0 | 0 | 3.2 | 2.34774 | 4.93691 | 8.50478 | 0.850478 | 4.6762 | 0.46762 | 0.127744 | 0.0277437 | 2.99658 | 2.65774 | 0 | 4.6762
Mur-005 | NIVEAU HAUT ENTRÉE | Mur-005 | NIVEAU HAUT ENTRÉE | Sanit Visit. F | 010 | BETON65 | 3 | 3.2 | 7.35278 | 0.735278 | 0.229774 | 2.29774 | 2.29774 | 0.459549 | 0.735278 | 0 | 0 | 0 | 0 | 0 | 3.2 | 2.29774 | 4.79549 | 8.50478 | 0.850478 | 0 | 0 | 2.29774 | 2.29774 | 7.35278 | 2.65774 | 0 | 0
Mur-002 | NIVEAU HAUT ENTRÉE | Mur-002 | NIVEAU HAUT ENTRÉE | Bureau Association | 011 | BETON65 | 3 | 3.2 | 7.67278 | 0.767278 | 0.234774 | 2.29774 | 2.39774 | 0.479549 | 0.767278 | 0 | 0 | 0 | 0 | 0 | 3.2 | 2.34774 | 4.93691 | 8.50478 | 0.850478 | 0 | 0 | 2.29774 | 2.39774 | 7.67278 | 2.65774 | 0 | 0
Mur-006 | NIVEAU HAUT ENTRÉE | Mur-006 | NIVEAU HAUT ENTRÉE | Sanit Visit. F | 010 | BETON65 | 3 | 3.2 | 9.0624 | 0.90624 | 0.415 | 4.25 | 4.05 | 0.618 | 1.296 | 2 | 0 | 1.92 | 0 | 0 | 3.2 | 4.15 | 8.58284 | 13.6 | 1.36 | 3.8976 | 0.38976 | 2.33 | 2.13 | 12.96 | 4.15 | 0 | 3.936
Mur-005 | NIVEAU HAUT ENTRÉE | Mur-005 | NIVEAU HAUT ENTRÉE | Dépot | 010 | BETON65 | 3 | 3.2 | 9.2832 | 0.92832 | 0.346 | 3.51 | 3.41 | 0.606 | 1.1232 | 1 | 0 | 0.96 | 0 | 0 | 3.2 | 3.46 | 7.16142 | 11.744 | 1.1744 | 1.9488 | 0.19488 | 2.55 | 2.45 | 11.232 | 3.51 | 0 | 1.968
Mur-007 | NIVEAU HAUT ENTRÉE | Mur-007 | NIVEAU HAUT ENTRÉE | Dépot | 010 | BETON65 | 3 | 3.2 | 5.06322 | 0.506322 | 0.163226 | 1.58226 | 1.68226 | 0.316451 | 0.506322 | 0 | 0 | 0 | 0 | 0 | 3.2 | 1.63226 | 3.50593 | 5.89522 | 0.589522 | 0 | 0 | 1.58226 | 1.68226 | 5.06322 | 1.58226 | 0 | 0
Mur-001 | NIVEAU HAUT ENTRÉE | Mur-001 | NIVEAU HAUT ENTRÉE | Salle de Sport de Combat | 006 | BETON65 | 3 | 3.2 | 13.536 | 1.3536 | 0.423 | 4.23 | 4.23 | 0.846 | 1.3536 | 0 | 0 | 0 | 0 | 0 | 3.2 | 4.23 | 8.66 | 14.88 | 1.488 | 0 | 0 | 4.23 | 4.23 | 13.536 | 4.65 | 0 | 0

# IfcWallStandardCase: Hachure solide* 3962059836 160 (19)
Material: Hachure solide* 3962059836 0.16 m
ArchiCADProperties - Calque: Murs Ext: Périphériques.Importation IFC; Type: Mur; Verrouillé: no; Matériau de construction / Composite / Profil / Hachure: Hachure solide* 3962059836; Fonction structurelle: Non défini; Position: Non défini; Classification d'élement: Type ArchiCAD; Etat de rénovation: Existant; Afficher sur filtre de rénovation: Tous les filtres appropriés; Type de structure: Basique; Matériau de construction / Composite / Profil: Hachure solide* 3962059836; Angle d'inclinaison externe: 90 deg; Angle d'inclinaison interne: 90 deg; Type d'inclinaison de mur: Droit; Emplacement de ligne de référence: Face extérieure; Etage supérieur lié: Non lié; Option de géométrie: Uniforme
AC_Pset_RenovationAndPhasing - Renovation Status: Existing
ArchiCADQuantities - Epaisseur: 0.16 m; Nombre de Fenêtres: 0; Nombre de trous (Nombre d'ouvertures vides): 0; Largeur totale des Fenêtres: 0 m; Epaisseur du Mur à la fin: 0.16 m; Hauteur minimum du Mur: 0 m; Epaisseur de couche de mur sur face extérieure: 0 m; Epaisseur de couche de mur sur face intérieure: 0 m; Epaisseur couche isolation: 0 m; Epaisseur couche d'air: 0 m; Hauteur de couche de mur minimum sur face extérieure: 0 m; Hauteur de couche de mur maximum sur face extérieure: 0 m; Hauteur de couche de mur minimum sur face intérieure: 0 m; Hauteur de couche de mur maximum sur face intérieure: 0 m; Volume de couche de mur sur face extérieure: 0 m3; Volume de couche de mur sur face intérieure: 0 m3; Volume de couche de mur conditionnelle sur face extérieure: 0 m3; Volume de couche de mur conditionnelle sur face intérieure: 0 m3; Décalage supérieur: -0.12 m; Surface des fenêtres dans le mur: 0 m2; Surface des baies libres dans le mur: 0 m2; Volume de poteaux: 0 m3
Name | In | ID Elément entier = ID Elément compact | Etage d'implantation | Surface de face extérieure = Surface de face intérieure = Surface latérale | Altitude à Zéro du Projet (m) | Altitude à étage (m) = Décalage étage d'implantation (m) | Hauteur (m) | Superficie de surface (m2) = Surface de mur nette sur face extérieure (m2) = Surface de mur nette sur face intérieure (m2) | Volume net (m3) | Superficie (m2) = Surface du Mur (m2) | Longueur de mur sur face extérieure (m) | Longueur de mur sur face intérieure (m) | Surface nette des arêtes (m2) | Volume conditionnel (m3) | Nombre de Portes | Nombre de Poteaux | Largeur totale des Portes (m) | Hauteur maximum du Mur (m) | Longueur du Mur au centre (m) = Longueur moyenne (m) | Périmètre du Mur (m) | Surface brute de mur sur face intérieure (m2) = Surface brute de mur sur face extérieure (m2) | Volume brut du Mur (m3) | Surface analytique des ouvertures sur face intérieure (m2) = Surface analytique des ouvertures sur face extérieure (m2) | Volume analytique des ouvertures dans le Mur (m3) | Longueur conditionnelle sur face extérieure (m) | Longueur conditionnelle sur face intérieure (m) | Surface conditionnelle sur face extérieure (m2) = Surface conditionnelle sur face intérieure (m2) | Longueur de ligne de référence (m) | Surface des portes dans le mur (m2)
Mur-005 | NIVEAU BAS GYMNASE | Mur-005 | NIVEAU BAS GYMNASE | BETON65 | 0 | 0 | 3 | 5.76 | 0.9216 | 0.2816 | 1.6 | 1.92 | 0.6144 | 0.9216 | 0 | 0 | 0 | 3 | 1.76 | 3.97255 | 5.76 | 0.9216 | 0 | 0 | 1.6 | 1.92 | 5.76 | 1.92 | 0 | ArchiCADProperties - Nom de Zone: Bureau Arbitre; Numéro de Zone: 006
Mur-006 | NIVEAU BAS GYMNASE | Mur-006 | NIVEAU BAS GYMNASE | BETON65 | 0 | 0 | 3 | 1.74 | 0.2784 | 0.1056 | 0.58 | 0.74 | 0.6656 | 0.2784 | 0 | 0 | 0 | 3 | 0.66 | 1.70627 | 2.22 | 0.3552 | 0 | 0 | 0.58 | 0.74 | 1.74 | 0.74 | 0
Mur-004 | NIVEAU BAS GYMNASE | Mur-004 | NIVEAU BAS GYMNASE | BETON65 | 0 | 0 | 3 | 1.74 | 0.2784 | 0.1056 | 0.58 | 0.74 | 0.6656 | 0.2784 | 0 | 0 | 0 | 3 | 0.66 | 1.70627 | 2.22 | 0.3552 | 0 | 0 | 0.58 | 0.74 | 1.74 | 0.74 | 0 | ArchiCADProperties - Nom de Zone: Bureau Arbitre; Numéro de Zone: 006
Mur-004 | NIVEAU BAS GYMNASE | Mur-004 | NIVEAU BAS GYMNASE | BETON65 | -0.2 | -0.2 | 2.95 | 12.4262 | 1.9882 | 0.6104 | 3.735 | 3.895 | 1.6624 | 1.9882 | 0 | 0 | 0 | 2.95 | 3.815 | 8.01627 | 12.4262 | 1.9882 | 0 | 0 | 3.735 | 3.895 | 12.4262 | 3.895 | 0 | ArchiCADProperties - Nom de Zone: Chaufferie; Numéro de Zone: 010
Mur-008 | NIVEAU HAUT ENTRÉE | Mur-008 | NIVEAU HAUT ENTRÉE | Revêt. pilier rond | 6.18 | 3.18 | 1.1 | 1.0964 | 0.175424 | 0.3232 | 2.02 | 2.02 | 0.3424 | 0.175424 | 0 | 0 | 0 | 0.82 | 2.02 | 4.36 | 2.224 | 0.35584 | 0 | 0 | 2.02 | 2.02 | 1.0964 | 2.02 | 0
Mur-005 | NIVEAU HAUT ENTRÉE | Mur-005 | NIVEAU HAUT ENTRÉE | Revêt. pilier rond | 6.18 | 3.18 | 0.82 | 1.2224 | 0.195584 | 0.2816 | 1.92 | 1.6 | 0.5632 | 0.195584 | 0 | 0 | 0 | 0.82 | 1.76 | 3.97255 | 1.5744 | 0.251904 | 0 | 0 | 1.92 | 1.6 | 1.2224 | 1.92 | 0
Mur-005 | NIVEAU HAUT ENTRÉE | Mur-005 | NIVEAU HAUT ENTRÉE | Revêt-murs int. | 3 | 0 | 3.2 | 5.632 | 0.90112 | 0.2816 | 1.6 | 1.92 | 0.5632 | 0.90112 | 0 | 0 | 0 | 3.2 | 1.76 | 3.97255 | 6.144 | 0.98304 | 0 | 0 | 1.6 | 1.92 | 5.632 | 1.92 | 0
Mur-004 | NIVEAU HAUT ENTRÉE | Mur-004 | NIVEAU HAUT ENTRÉE | Revêt-murs int. | 3 | 0 | 3.2 | 1.854 | 0.29664 | 0.1056 | 0.58 | 0.74 | 0.1696 | 0.29664 | 0 | 0 | 0 | 3.2 | 0.66 | 1.70627 | 2.3712 | 0.379392 | 0 | 0 | 0.58 | 0.74 | 1.854 | 0.74 | 0 | ArchiCADProperties - Nom de Zone: Hall d'Entrée; Numéro de Zone: 010
Mur-002 | NIVEAU HAUT ENTRÉE | Mur-002 | NIVEAU HAUT ENTRÉE | Revêt-murs int. | 3 | 0 | 3.2 | 8.46162 | 1.35386 | 0.605161 | 3.86226 | 3.70226 | 0.928722 | 1.97748 | 2 | 0 | 1.92 | 3.2 | 3.78226 | 7.95079 | 12.6792 | 2.02868 | 3.8976 | 0.623616 | 1.94226 | 1.78226 | 12.3592 | 3.70226 | 3.936 | ArchiCADProperties - Nom de Zone: Dépot; Numéro de Zone: 010
Mur-004 | NIVEAU HAUT ENTRÉE | Mur-004 | NIVEAU HAUT ENTRÉE | Revêt-murs int. | 3 | 0 | 3.2 | 26.5999 | 4.25598 | 1.5248 | 9.45 | 9.61 | 2.7392 | 4.8384 | 1 | 0 | 1.78 | 3.2 | 9.53 | 19.4463 | 31.904 | 5.10464 | 3.6401 | 0.582416 | 7.67 | 7.83 | 26.5999 | 9.71 | 3.6401 | ArchiCADProperties - Nom de Zone: Dépot; Numéro de Zone: 010
Mur-006 | NIVEAU HAUT ENTRÉE | Mur-006 | NIVEAU HAUT ENTRÉE | Revêt-murs int. | 3 | 0 | 3.2 | 2.3712 | 0.379392 | 0.1056 | 0.58 | 0.74 | 0.2624 | 0.379392 | 0 | 0 | 0 | 3.2 | 0.66 | 1.70627 | 2.3712 | 0.379392 | 0 | 0 | 0.58 | 0.74 | 2.3712 | 0.74 | 0
Mur-005 | PLAN DE MASSE-TOITURE | Mur-005 | PLAN DE MASSE-TOITURE | BETON65 | 6.2 | 0 | 0.73 | 7.1394 | 1.1423 | 1.5776 | 9.78 | 9.94 | 3.1296 | 1.1423 | 0 | 0 | 0 | 0.73 | 9.86 | 20.1063 | 7.3992 | 1.18387 | 0 | 0 | 9.78 | 9.94 | 7.1394 | 9.94 | 0
Mur-004 | PLAN DE MASSE-TOITURE | Mur-004 | PLAN DE MASSE-TOITURE | Surface-Stuc blanc | 6.38 | 0.18 | 0.92 | 5.8512 | 0.936192 | 1.0288 | 6.2 | 6.66 | 2.0352 | 0.936192 | 0 | 0 | 0 | 0.92 | 6.43 | 13.4263 | 6.1272 | 0.980352 | 0 | 0 | 6.2 | 6.66 | 5.8512 | 6.36 | 0
Mur-005 | PLAN DE MASSE-TOITURE | Mur-005 | PLAN DE MASSE-TOITURE | Surface-Stuc blanc | 6.2 | 0 | 1.1 | 4.7148 | 0.754368 | 0.6816 | 4.1 | 4.42 | 1.3888 | 0.754368 | 0 | 1 | 0 | 1.1 | 4.26 | 8.97255 | 4.862 | 0.77792 | 0 | 0 | 4.1 | 4.42 | 4.7148 | 4.42 | 0
Mur-006 | PLAN DE MASSE-TOITURE | Mur-006 | PLAN DE MASSE-TOITURE | Revêt. pilier rond | 6.2 | 0 | 1 | 1.054 | 0.16864 | 0.2848 | 1.7 | 1.86 | 0 | 0.16864 | 0 | 0 | 0 | 0.62 | 1.78 | 3.94627 | 2.02 | 0.3232 | 0 | 0 | 1.7 | 1.86 | 1.054 | 2.02 | 0
Mur-005 | PLAN DE MASSE-TOITURE | Mur-005 | PLAN DE MASSE-TOITURE | BETON65 | 6.2 | 0 | 0.8 | 4.96 | 0.7936 | 1.0048 | 6.2 | 6.36 | 1.984 | 0.7936 | 0 | 1 | 0 | 0.8 | 6.28 | 12.9463 | 5.328 | 0.85248 | 0 | 0 | 6.2 | 6.36 | 4.96 | 6.36 | 0
Mur-004 | PLAN DE MASSE-TOITURE | Mur-004 | PLAN DE MASSE-TOITURE | BETON65 | 6.2 | 0 | 0.73 | 11.4829 | 1.83726 | 2.5168 | 15.89 | 15.57 | 5.0336 | 1.83726 | 0 | 0 | 0 | 0.73 | 15.73 | 31.9125 | 11.5997 | 1.85595 | 0 | 0 | 15.89 | 15.57 | 11.4829 | 15.89 | 0
Mur-004 | PLAN DE MASSE-TOITURE | Mur-004 | PLAN DE MASSE-TOITURE | BETON65 | 6.2 | 0 | 0.73 | 15.8994 | 2.5439 | 3.4592 | 21.78 | 21.46 | 6.9696 | 2.5439 | 0 | 1 | 0 | 0.73 | 21.62 | 43.6925 | 15.8994 | 2.5439 | 0 | 0 | 21.78 | 21.46 | 15.8994 | 21.78 | 0
Mur-004 | PLAN DE MASSE-TOITURE | Mur-004 | PLAN DE MASSE-TOITURE | BETON65 | 6.2 | 0 | 0.73 | 10.9208 | 1.74733 | 2.4304 | 14.96 | 15.42 | 4.7872 | 1.74733 | 0 | 1 | 0 | 0.73 | 15.19 | 30.9463 | 11.2566 | 1.80106 | 0 | 0 | 14.96 | 15.42 | 10.9208 | 15.42 | 0

# IfcWallStandardCase: Hachure solide* 3962059836 250, Mur-004
In: NIVEAU BAS GYMNASE
Material: Hachure solide* 3962059836 0.25 m
ArchiCADProperties - ID Elément entier: Mur-004; ID Elément compact: Mur-004; Etage d'implantation: NIVEAU BAS GYMNASE; Calque: Murs Ext: Périphériques.Importation IFC; Type: Mur; Verrouillé: no; Matériau de construction / Composite / Profil / Hachure: Hachure solide* 3962059836; Fonction structurelle: Non défini; Position: Non défini; Classification d'élement: Type ArchiCAD; Etat de rénovation: Existant; Afficher sur filtre de rénovation: Tous les filtres appropriés; Type de structure: Basique; Matériau de construction / Composite / Profil: Hachure solide* 3962059836; Surface de face extérieure: BETON65; Surface de face intérieure: BETON65; Surface latérale: BETON65; Angle d'inclinaison externe: 90 deg; Angle d'inclinaison interne: 90 deg; Type d'inclinaison de mur: Droit; Emplacement de ligne de référence: Face extérieure; Etage supérieur lié: Non lié; Option de géométrie: Uniforme
AC_Pset_RenovationAndPhasing - Renovation Status: Existing
ArchiCADQuantities - Altitude à Zéro du Projet: -0.115362 m; Altitude à étage: -0.115362 m; Hauteur: 3.83536 m; Superficie de surface: 47.1426 m2; Volume net: 11.7857 m3; Superficie: 3.2 m2; Epaisseur: 0.25 m; Longueur de mur sur face extérieure: 12.8 m; Longueur de mur sur face intérieure: 12.8 m; Surface de mur nette sur face extérieure: 47.1426 m2; Surface de mur nette sur face intérieure: 47.1426 m2; Surface nette des arêtes: 8.15518 m2; Volume conditionnel: 12.2732 m3; Nombre de Portes: 0; Nombre de Fenêtres: 1; Nombre de trous (Nombre d'ouvertures vides): 0; Nombre de Poteaux: 0; Largeur totale des Portes: 0 m; Largeur totale des Fenêtres: 3 m; Epaisseur du Mur à la fin: 0.25 m; Hauteur minimum du Mur: 3.83536 m; Hauteur maximum du Mur: 3.83536 m; Longueur du Mur au centre: 12.8 m; Surface du Mur: 3.2 m2; Périmètre du Mur: 26.1 m; Surface brute de mur sur face intérieure: 49.0926 m2; Surface brute de mur sur face extérieure: 49.0926 m2; Volume brut du Mur: 12.2732 m3; Surface analytique des ouvertures sur face intérieure: 1.95 m2; Surface analytique des ouvertures sur face extérieure: 1.95 m2; Volume analytique des ouvertures dans le Mur: 0.4875 m3; Epaisseur de couche de mur sur face extérieure: 0 m; Epaisseur de couche de mur sur face intérieure: 0 m; Epaisseur couche isolation: 0 m; Epaisseur couche d'air: 0 m; Hauteur de couche de mur minimum sur face extérieure: 0 m; Hauteur de couche de mur maximum sur face extérieure: 0 m; Hauteur de couche de mur minimum sur face intérieure: 0 m; Hauteur de couche de mur maximum sur face intérieure: 0 m; Longueur conditionnelle sur face extérieure: 12.8 m; Longueur conditionnelle sur face intérieure: 12.8 m; Surface conditionnelle sur face extérieure: 49.0926 m2; Surface conditionnelle sur face intérieure: 49.0926 m2; Volume de couche de mur sur face extérieure: 0 m3; Volume de couche de mur sur face intérieure: 0 m3; Volume de couche de mur conditionnelle sur face extérieure: 0 m3; Volume de couche de mur conditionnelle sur face intérieure: 0 m3; Longueur de ligne de référence: 12.8 m; Décalage étage d'implantation: -0.115362 m; Décalage supérieur: -0.12 m; Longueur moyenne: 12.8 m; Surface des fenêtres dans le mur: 1.95 m2; Surface des portes dans le mur: 0 m2; Surface des baies libres dans le mur: 0 m2; Volume de poteaux: 0 m3

# IfcWallStandardCase: Hachure solide* 3962059836 30 (4)
In: NIVEAU BAS GYMNASE
Material: Hachure solide* 3962059836 0.03 m
ArchiCADProperties - Etage d'implantation: NIVEAU BAS GYMNASE; Numéro de Zone: 010; Calque: Murs Ext: Périphériques.Importation IFC; Type: Mur; Verrouillé: no; Matériau de construction / Composite / Profil / Hachure: Hachure solide* 3962059836; Fonction structurelle: Non défini; Position: Non défini; Classification d'élement: Type ArchiCAD; Etat de rénovation: Existant; Afficher sur filtre de rénovation: Tous les filtres appropriés; Type de structure: Basique; Matériau de construction / Composite / Profil: Hachure solide* 3962059836; Surface de face extérieure: BETON65; Surface de face intérieure: BETON65; Surface latérale: BETON65; Angle d'inclinaison externe: 90 deg; Angle d'inclinaison interne: 90 deg; Type d'inclinaison de mur: Droit; Emplacement de ligne de référence: Face extérieure; Etage supérieur lié: Non lié; Option de géométrie: Uniforme
AC_Pset_RenovationAndPhasing - Renovation Status: Existing
ArchiCADQuantities - Altitude à Zéro du Projet: 0 m; Altitude à étage: 0 m; Hauteur: 1 m; Epaisseur: 0.03 m; Nombre de Portes: 0; Nombre de Fenêtres: 0; Nombre de trous (Nombre d'ouvertures vides): 0; Nombre de Poteaux: 0; Largeur totale des Portes: 0 m; Largeur totale des Fenêtres: 0 m; Epaisseur du Mur à la fin: 0.03 m; Hauteur minimum du Mur: 0 m; Hauteur maximum du Mur: 1 m; Surface analytique des ouvertures sur face intérieure: 0 m2; Surface analytique des ouvertures sur face extérieure: 0 m2; Volume analytique des ouvertures dans le Mur: 0 m3; Epaisseur de couche de mur sur face extérieure: 0 m; Epaisseur de couche de mur sur face intérieure: 0 m; Epaisseur couche isolation: 0 m; Epaisseur couche d'air: 0 m; Hauteur de couche de mur minimum sur face extérieure: 0 m; Hauteur de couche de mur maximum sur face extérieure: 0 m; Hauteur de couche de mur minimum sur face intérieure: 0 m; Hauteur de couche de mur maximum sur face intérieure: 0 m; Volume de couche de mur sur face extérieure: 0 m3; Volume de couche de mur sur face intérieure: 0 m3; Volume de couche de mur conditionnelle sur face extérieure: 0 m3; Volume de couche de mur conditionnelle sur face intérieure: 0 m3; Décalage étage d'implantation: 0 m; Décalage supérieur: -0.12 m; Surface des fenêtres dans le mur: 0 m2; Surface des portes dans le mur: 0 m2; Surface des baies libres dans le mur: 0 m2; Volume de poteaux: 0 m3
Name | ID Elément entier = ID Elément compact | Nom de Zone | Superficie de surface (m2) = Surface de mur nette sur face extérieure (m2) = Surface de mur nette sur face intérieure (m2) = Surface conditionnelle sur face extérieure (m2) = Surface conditionnelle sur face intérieure (m2) | Volume net (m3) = Volume conditionnel (m3) | Superficie (m2) = Surface du Mur (m2) | Longueur de mur sur face extérieure (m) = Longueur conditionnelle sur face extérieure (m) | Longueur de mur sur face intérieure (m) = Longueur conditionnelle sur face intérieure (m) | Surface nette des arêtes (m2) | Longueur du Mur au centre (m) = Longueur moyenne (m) | Périmètre du Mur (m) | Surface brute de mur sur face intérieure (m2) = Surface brute de mur sur face extérieure (m2) | Volume brut du Mur (m3) | Longueur de ligne de référence (m)
Mur-007 | Mur-007 | Dépot 2 | 2.24515 | 0.0673545 | 0.0669045 | 2.24515 | 2.21515 | 0.134709 | 2.23015 | 4.53273 | 2.50515 | 0.0751545 | 2.49015
Mur-008 | Mur-008 | Dépot 3 | 4.58777 | 0.137633 | 0.137183 | 4.55777 | 4.58777 | 0.275266 | 4.57277 | 9.21797 | 4.86777 | 0.146033 | 4.85277
Mur-007 | Mur-007 | Dépot 3 | 2.21515 | 0.0664545 | 0.0669045 | 2.24515 | 2.21515 | 0.132909 | 2.23015 | 4.53273 | 2.40515 | 0.0721545 | 2.39015
Mur-006 | Mur-006 | Dépot 2 | 4.55777 | 0.136733 | 0.137183 | 4.58777 | 4.55777 | 0.273466 | 4.57277 | 9.21797 | 4.86777 | 0.146033 | 4.85277

# IfcWallStandardCase: Hachure solide* 3962059836 300 (2)
In: PLAN DE MASSE-TOITURE
Material: Hachure solide* 3962059836 0.3 m
ArchiCADProperties - ID Elément entier: Mur-004; ID Elément compact: Mur-004; Etage d'implantation: PLAN DE MASSE-TOITURE; Calque: Murs Ext: Périphériques.Importation IFC; Type: Mur; Verrouillé: no; Matériau de construction / Composite / Profil / Hachure: Hachure solide* 3962059836; Fonction structurelle: Non défini; Position: Non défini; Classification d'élement: Type ArchiCAD; Etat de rénovation: Existant; Afficher sur filtre de rénovation: Tous les filtres appropriés; Type de structure: Basique; Matériau de construction / Composite / Profil: Hachure solide* 3962059836; Surface de face extérieure: Surface-Stuc blanc; Surface de face intérieure: Surface-Stuc blanc; Surface latérale: Surface-Stuc blanc; Angle d'inclinaison externe: 90 deg; Angle d'inclinaison interne: 90 deg; Type d'inclinaison de mur: Droit; Emplacement de ligne de référence: Face extérieure; Etage supérieur lié: Non lié; Option de géométrie: Uniforme
AC_Pset_RenovationAndPhasing - Renovation Status: Existing
ArchiCADQuantities - Epaisseur: 0.3 m; Nombre de Portes: 0; Nombre de Fenêtres: 0; Nombre de trous (Nombre d'ouvertures vides): 0; Largeur totale des Portes: 0 m; Largeur totale des Fenêtres: 0 m; Epaisseur du Mur à la fin: 0.3 m; Hauteur minimum du Mur: 0 m; Surface analytique des ouvertures sur face intérieure: 0 m2; Surface analytique des ouvertures sur face extérieure: 0 m2; Volume analytique des ouvertures dans le Mur: 0 m3; Epaisseur de couche de mur sur face extérieure: 0 m; Epaisseur de couche de mur sur face intérieure: 0 m; Epaisseur couche isolation: 0 m; Epaisseur couche d'air: 0 m; Hauteur de couche de mur minimum sur face extérieure: 0 m; Hauteur de couche de mur maximum sur face extérieure: 0 m; Hauteur de couche de mur minimum sur face intérieure: 0 m; Hauteur de couche de mur maximum sur face intérieure: 0 m; Volume de couche de mur sur face extérieure: 0 m3; Volume de couche de mur sur face intérieure: 0 m3; Volume de couche de mur conditionnelle sur face extérieure: 0 m3; Volume de couche de mur conditionnelle sur face intérieure: 0 m3; Décalage supérieur: -0.12 m; Surface des fenêtres dans le mur: 0 m2; Surface des portes dans le mur: 0 m2; Surface des baies libres dans le mur: 0 m2; Volume de poteaux: 0 m3
Name | Altitude à Zéro du Projet (m) | Altitude à étage (m) = Décalage étage d'implantation (m) | Hauteur (m) = Hauteur maximum du Mur (m) | Superficie de surface (m2) = Surface de mur nette sur face extérieure (m2) = Surface conditionnelle sur face extérieure (m2) | Volume net (m3) = Volume conditionnel (m3) | Superficie (m2) = Surface du Mur (m2) | Longueur de mur sur face extérieure (m) = Longueur conditionnelle sur face extérieure (m) | Longueur de mur sur face intérieure (m) = Longueur conditionnelle sur face intérieure (m) | Surface de mur nette sur face intérieure (m2) = Surface brute de mur sur face intérieure (m2) = Surface brute de mur sur face extérieure (m2) = Surface conditionnelle sur face intérieure (m2) | Surface nette des arêtes (m2) | Nombre de Poteaux | Longueur du Mur au centre (m) = Longueur moyenne (m) | Périmètre du Mur (m) | Volume brut du Mur (m3) | Longueur de ligne de référence (m)
Mur-004 | 6.2 | 0 | 1.1 | 1.849 | 0.5573 | 0.483 | 1.53 | 1.69 | 1.859 | 1.344 | 1 | 1.61 | 3.86 | 0.5577 | 1.69
Mur-004 | 6.38 | 0.18 | 0.92 | 3.9192 | 1.17576 | 1.254 | 4.26 | 4.1 | 3.9192 | 2.832 | 0 | 4.18 | 9 | 1.17576 | 4.26

# IfcWallStandardCase: Hachure solide* 3962059836 70 (8)
In: NIVEAU BAS GYMNASE
Material: Hachure solide* 3962059836 0.07 m
ArchiCADProperties - ID Elément entier: Mur-004; ID Elément compact: Mur-004; Etage d'implantation: NIVEAU BAS GYMNASE; Calque: Murs Ext: Périphériques.Importation IFC; Type: Mur; Verrouillé: no; Matériau de construction / Composite / Profil / Hachure: Hachure solide* 3962059836; Fonction structurelle: Non défini; Position: Non défini; Classification d'élement: Type ArchiCAD; Etat de rénovation: Existant; Afficher sur filtre de rénovation: Tous les filtres appropriés; Type de structure: Basique; Matériau de construction / Composite / Profil: Hachure solide* 3962059836; Surface de face extérieure: BETON65; Surface de face intérieure: BETON65; Surface latérale: BETON65; Angle d'inclinaison externe: 90 deg; Angle d'inclinaison interne: 90 deg; Type d'inclinaison de mur: Droit; Emplacement de ligne de référence: Face extérieure; Etage supérieur lié: Non lié; Option de géométrie: Uniforme
AC_Pset_RenovationAndPhasing - Renovation Status: Existing
ArchiCADQuantities - Altitude à Zéro du Projet: 0 m; Altitude à étage: 0 m; Hauteur: 2.8 m; Epaisseur: 0.07 m; Nombre de Fenêtres: 0; Nombre de trous (Nombre d'ouvertures vides): 0; Nombre de Poteaux: 0; Largeur totale des Fenêtres: 0 m; Epaisseur du Mur à la fin: 0.07 m; Hauteur minimum du Mur: 0 m; Hauteur maximum du Mur: 2.8 m; Epaisseur de couche de mur sur face extérieure: 0 m; Epaisseur de couche de mur sur face intérieure: 0 m; Epaisseur couche isolation: 0 m; Epaisseur couche d'air: 0 m; Hauteur de couche de mur minimum sur face extérieure: 0 m; Hauteur de couche de mur maximum sur face extérieure: 0 m; Hauteur de couche de mur minimum sur face intérieure: 0 m; Hauteur de couche de mur maximum sur face intérieure: 0 m; Volume de couche de mur sur face extérieure: 0 m3; Volume de couche de mur sur face intérieure: 0 m3; Volume de couche de mur conditionnelle sur face extérieure: 0 m3; Volume de couche de mur conditionnelle sur face intérieure: 0 m3; Décalage étage d'implantation: 0 m; Décalage supérieur: -0.12 m; Surface des fenêtres dans le mur: 0 m2; Surface des baies libres dans le mur: 0 m2; Volume de poteaux: 0 m3
Name | Nom de Zone | Numéro de Zone | Superficie de surface (m2) = Surface de mur nette sur face extérieure (m2) = Surface de mur nette sur face intérieure (m2) | Volume net (m3) | Superficie (m2) = Surface du Mur (m2) | Longueur de mur sur face extérieure (m) | Longueur de mur sur face intérieure (m) | Surface nette des arêtes (m2) | Volume conditionnel (m3) | Nombre de Portes | Largeur totale des Portes (m) | Longueur du Mur au centre (m) = Longueur moyenne (m) | Périmètre du Mur (m) | Surface brute de mur sur face intérieure (m2) = Surface brute de mur sur face extérieure (m2) | Volume brut du Mur (m3) | Surface analytique des ouvertures sur face intérieure (m2) = Surface analytique des ouvertures sur face extérieure (m2) | Volume analytique des ouvertures dans le Mur (m3) | Longueur conditionnelle sur face extérieure (m) | Longueur conditionnelle sur face intérieure (m) | Surface conditionnelle sur face extérieure (m2) = Surface conditionnelle sur face intérieure (m2) | Longueur de ligne de référence (m) | Surface des portes dans le mur (m2)
Mur-004 | Sanit Prof F | 010 | 3.98445 | 0.278911 | 0.14 | 2 | 2 | 0.2247 | 0.392 | 1 | 0.79 | 2 | 4.14 | 6.44 | 0.4508 | 1.61555 | 0.113088 | 1.21 | 1.21 | 5.6 | 2.05 | 1.62345
Mur-004 | Sanit Prof H | 010 | 2.24 | 0.1568 | 0.05355 | 0.8 | 0.73 | 0.308 | 0.1568 | 0 | 0 | 0.765 | 1.69899 | 2.24 | 0.1568 | 0 | 0 | 0.8 | 0.73 | 2.24 | 0.8 | 0
Mur-004 |  |  | 2.64922 | 0.185445 | 0.109069 | 1.59313 | 1.52313 | 0.157939 | 0.298534 | 1 | 0.79 | 1.55813 | 3.28526 | 4.65677 | 0.325974 | 1.61555 | 0.113088 | 0.803133 | 0.733133 | 4.26477 | 1.59313 | 1.62345
Mur-004 | Sanit Prof F | 010 | 2.24 | 0.1568 | 0.05355 | 0.73 | 0.8 | 0.112 | 0.1568 | 0 | 0 | 0.765 | 1.69899 | 2.52 | 0.1764 | 0 | 0 | 0.73 | 0.8 | 2.24 | 0.8 | 0
Mur-004 | Sanit Prof F | 010 | 1.69923 | 0.118946 | 0.0424807 | 0.606867 | 0.606867 | 0.280961 | 0.118946 | 0 | 0 | 0.606867 | 1.35373 | 1.89523 | 0.132666 | 0 | 0 | 0.606867 | 0.606867 | 1.69923 | 0.676867 | 0
Mur-004 |  |  | 2.64922 | 0.185445 | 0.109069 | 1.52313 | 1.59313 | 0.157939 | 0.298534 | 1 | 0.79 | 1.55813 | 3.28526 | 4.65677 | 0.325974 | 1.61555 | 0.113088 | 0.733133 | 0.803133 | 4.26477 | 1.59313 | 1.62345
Mur-004 | Sanit Prof H | 010 | 3.98445 | 0.278911 | 0.14 | 2 | 2 | 0.4207 | 0.392 | 1 | 0.79 | 2 | 4.14 | 5.88 | 0.4116 | 1.61555 | 0.113088 | 1.21 | 1.21 | 5.6 | 2.05 | 1.62345
Mur-004 | Sanit Prof H | 010 | 1.69923 | 0.118946 | 0.0424807 | 0.606867 | 0.606867 | 0.280961 | 0.118946 | 0 | 0 | 0.606867 | 1.35373 | 1.89523 | 0.132666 | 0 | 0 | 0.606867 | 0.606867 | 1.69923 | 0.676867 | 0

# IfcWallStandardCase: Hachure solide* 3992800808 240, Mur-002
In: NIVEAU BAS GYMNASE
Material: Hachure solide* 3992800808 0.24 m
ArchiCADProperties - ID Elément entier: Mur-002; ID Elément compact: Mur-002; Etage d'implantation: NIVEAU BAS GYMNASE; Calque: Murs Ext: Périphériques.Importation IFC; Type: Mur; Verrouillé: no; Matériau de construction / Composite / Profil / Hachure: Hachure solide* 3992800808; Fonction structurelle: Non défini; Position: Non défini; Classification d'élement: Type ArchiCAD; Etat de rénovation: Existant; Afficher sur filtre de rénovation: Tous les filtres appropriés; Type de structure: Basique; Matériau de construction / Composite / Profil: Hachure solide* 3992800808; Surface de face extérieure: BETON65; Surface de face intérieure: BETON65; Surface latérale: BETON65; Angle d'inclinaison externe: 90 deg; Angle d'inclinaison interne: 90 deg; Type d'inclinaison de mur: Droit; Emplacement de ligne de référence: Face extérieure; Etage supérieur lié: Non lié; Option de géométrie: Uniforme
AC_Pset_RenovationAndPhasing - Renovation Status: Existing
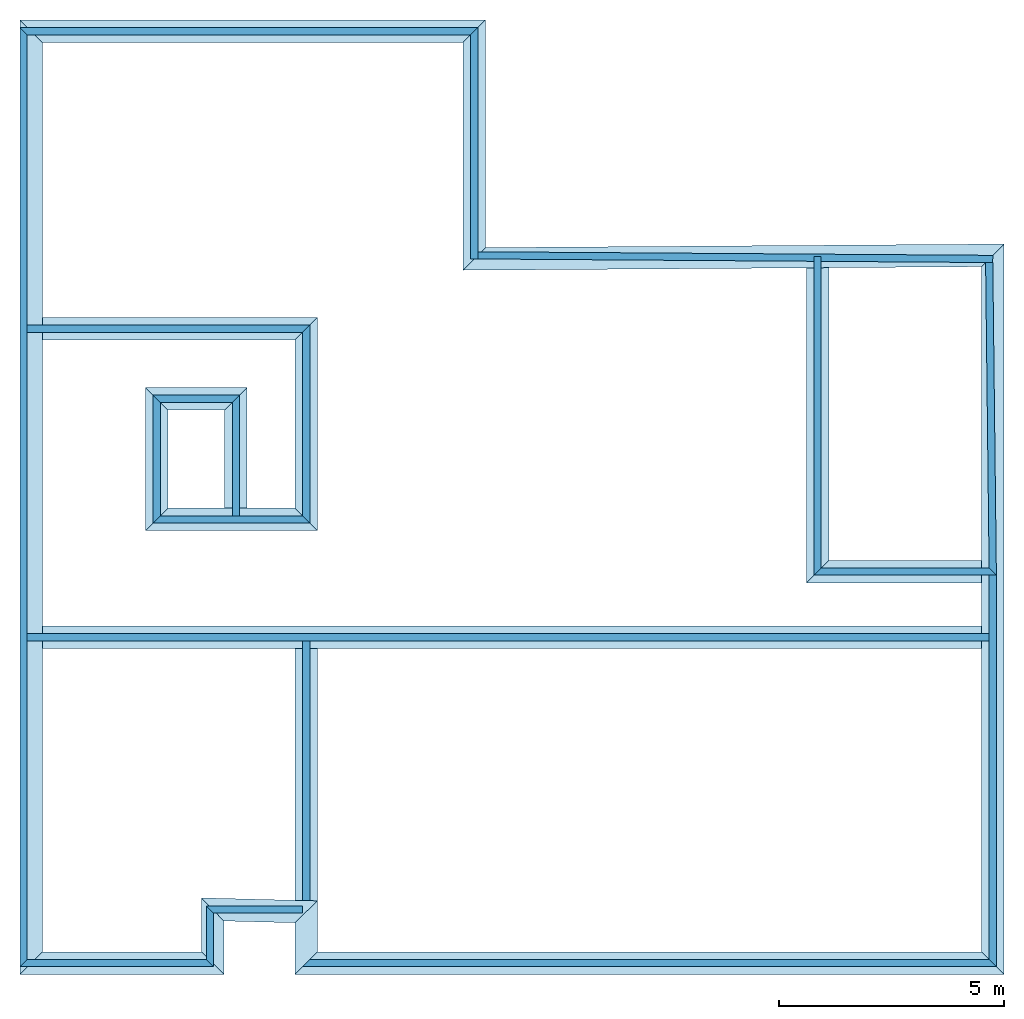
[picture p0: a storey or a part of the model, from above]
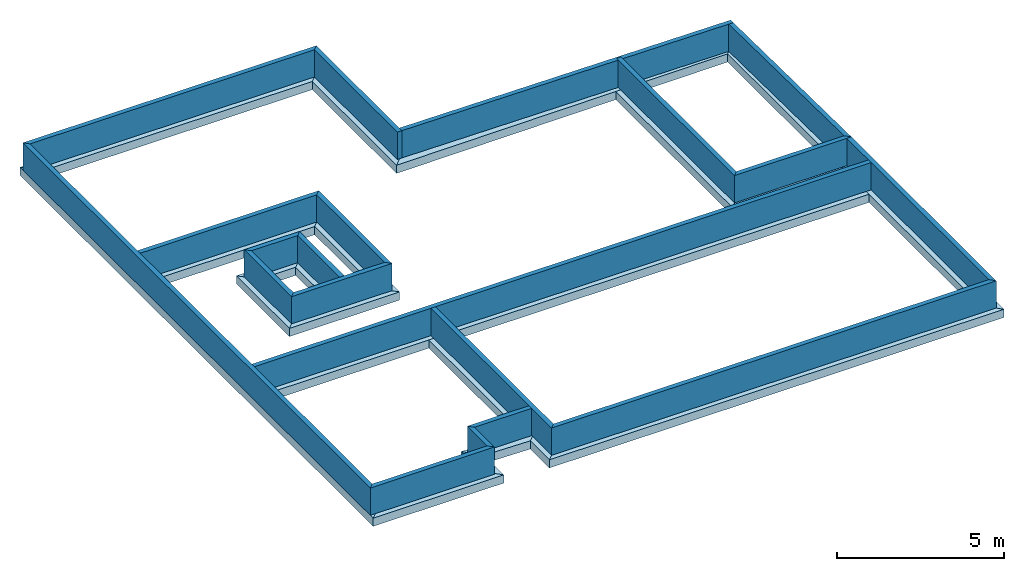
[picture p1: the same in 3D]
Properties of the parts of a building model (IFC2X3), part 5 of 6

# IfcWallStandardCase: Hachure solide* 3992800808 240, Mur-002
ArchiCADQuantities - Altitude à Zéro du Projet: 0 m; Altitude à étage: 0 m; Hauteur: 6.8 m; Superficie de surface: 109.911 m2; Volume net: 26.3786 m3; Superficie: 3.8792 m2; Epaisseur: 0.24 m; Longueur de mur sur face extérieure: 16.1633 m; Longueur de mur sur face intérieure: 16.1633 m; Surface de mur nette sur face extérieure: 109.911 m2; Surface de mur nette sur face intérieure: 109.911 m2; Surface nette des arêtes: 9.3904 m2; Volume conditionnel: 26.3786 m3; Nombre de Portes: 0; Nombre de Fenêtres: 0; Nombre de trous (Nombre d'ouvertures vides): 0; Nombre de Poteaux: 0; Largeur totale des Portes: 0 m; Largeur totale des Fenêtres: 0 m; Epaisseur du Mur à la fin: 0.24 m; Hauteur minimum du Mur: 0 m; Hauteur maximum du Mur: 6.8 m; Longueur du Mur au centre: 16.1633 m; Surface du Mur: 3.8792 m2; Périmètre du Mur: 32.8067 m; Surface brute de mur sur face intérieure: 111.918 m2; Surface brute de mur sur face extérieure: 111.918 m2; Volume brut du Mur: 26.8602 m3; Surface analytique des ouvertures sur face intérieure: 0 m2; Surface analytique des ouvertures sur face extérieure: 0 m2; Volume analytique des ouvertures dans le Mur: 0 m3; Epaisseur de couche de mur sur face extérieure: 0 m; Epaisseur de couche de mur sur face intérieure: 0 m; Epaisseur couche isolation: 0 m; Epaisseur couche d'air: 0 m; Hauteur de couche de mur minimum sur face extérieure: 0 m; Hauteur de couche de mur maximum sur face extérieure: 0 m; Hauteur de couche de mur minimum sur face intérieure: 0 m; Hauteur de couche de mur maximum sur face intérieure: 0 m; Longueur conditionnelle sur face extérieure: 16.1633 m; Longueur conditionnelle sur face intérieure: 16.1633 m; Surface conditionnelle sur face extérieure: 109.911 m2; Surface conditionnelle sur face intérieure: 109.911 m2; Volume de couche de mur sur face extérieure: 0 m3; Volume de couche de mur sur face intérieure: 0 m3; Volume de couche de mur conditionnelle sur face extérieure: 0 m3; Volume de couche de mur conditionnelle sur face intérieure: 0 m3; Longueur de ligne de référence: 16.1633 m; Décalage étage d'implantation: 0 m; Décalage supérieur: -0.12 m; Longueur moyenne: 16.1633 m; Surface des fenêtres dans le mur: 0 m2; Surface des portes dans le mur: 0 m2; Surface des baies libres dans le mur: 0 m2; Volume de poteaux: 0 m3

# IfcWallStandardCase: Hachure solide* 4022991772 100, Mur-004
In: NIVEAU BAS GYMNASE
Material: Hachure solide* 4022991772 0.1 m
ArchiCADProperties - ID Elément entier: Mur-004; ID Elément compact: Mur-004; Etage d'implantation: NIVEAU BAS GYMNASE; Nom de Zone: Hall & Circulation; Numéro de Zone: 010; Calque: Murs Ext: Périphériques.Importation IFC; Type: Mur; Verrouillé: no; Matériau de construction / Composite / Profil / Hachure: Hachure solide* 4022991772; Fonction structurelle: Non défini; Position: Non défini; Classification d'élement: Type ArchiCAD; Etat de rénovation: Existant; Afficher sur filtre de rénovation: Tous les filtres appropriés; Type de structure: Basique; Matériau de construction / Composite / Profil: Hachure solide* 4022991772; Surface de face extérieure: BETON65; Surface de face intérieure: BETON65; Surface latérale: BETON65; Angle d'inclinaison externe: 90 deg; Angle d'inclinaison interne: 90 deg; Type d'inclinaison de mur: Droit; Emplacement de ligne de référence: Face extérieure; Etage supérieur lié: Non lié; Option de géométrie: Uniforme
AC_Pset_RenovationAndPhasing - Renovation Status: Existing
ArchiCADQuantities - Altitude à Zéro du Projet: 0 m; Altitude à étage: 0 m; Hauteur: 2.8 m; Superficie de surface: 5.46395 m2; Volume net: 0.546395 m3; Superficie: 0.276 m2; Epaisseur: 0.1 m; Longueur de mur sur face extérieure: 2.76 m; Longueur de mur sur face intérieure: 2.76 m; Surface de mur nette sur face extérieure: 5.46395 m2; Surface de mur nette sur face intérieure: 5.46395 m2; Surface nette des arêtes: 0.4905 m2; Volume conditionnel: 0.7729 m3; Nombre de Portes: 1; Nombre de Fenêtres: 0; Nombre de trous (Nombre d'ouvertures vides): 0; Nombre de Poteaux: 0; Largeur totale des Portes: 0.89 m; Largeur totale des Fenêtres: 0 m; Epaisseur du Mur à la fin: 0.1 m; Hauteur minimum du Mur: 0 m; Hauteur maximum du Mur: 2.8 m; Longueur du Mur au centre: 2.76 m; Surface du Mur: 0.276 m2; Périmètre du Mur: 5.72 m; Surface brute de mur sur face intérieure: 8.512 m2; Surface brute de mur sur face extérieure: 8.512 m2; Volume brut du Mur: 0.8512 m3; Surface analytique des ouvertures sur face intérieure: 2.26505 m2; Surface analytique des ouvertures sur face extérieure: 2.26505 m2; Volume analytique des ouvertures dans le Mur: 0.226505 m3; Epaisseur de couche de mur sur face extérieure: 0 m; Epaisseur de couche de mur sur face intérieure: 0 m; Epaisseur couche isolation: 0 m; Epaisseur couche d'air: 0 m; Hauteur de couche de mur minimum sur face extérieure: 0 m; Hauteur de couche de mur maximum sur face extérieure: 0 m; Hauteur de couche de mur minimum sur face intérieure: 0 m; Hauteur de couche de mur maximum sur face intérieure: 0 m; Longueur conditionnelle sur face extérieure: 1.87 m; Longueur conditionnelle sur face intérieure: 1.87 m; Surface conditionnelle sur face extérieure: 5.46395 m2; Surface conditionnelle sur face intérieure: 5.46395 m2; Volume de couche de mur sur face extérieure: 0 m3; Volume de couche de mur sur face intérieure: 0 m3; Volume de couche de mur conditionnelle sur face extérieure: 0 m3; Volume de couche de mur conditionnelle sur face intérieure: 0 m3; Longueur de ligne de référence: 3.04 m; Décalage étage d'implantation: 0 m; Décalage supérieur: -0.12 m; Longueur moyenne: 2.76 m; Surface des fenêtres dans le mur: 0 m2; Surface des portes dans le mur: 2.27395 m2; Surface des baies libres dans le mur: 0 m2; Volume de poteaux: 0 m3

# IfcWallStandardCase: Hachure solide* 4022991772 160, Mur-004
In: NIVEAU BAS GYMNASE
Material: Hachure solide* 4022991772 0.16 m
ArchiCADProperties - ID Elément entier: Mur-004; ID Elément compact: Mur-004; Etage d'implantation: NIVEAU BAS GYMNASE; Nom de Zone: Hall & Circulation; Numéro de Zone: 010; Calque: Murs Ext: Périphériques.Importation IFC; Type: Mur; Verrouillé: no; Matériau de construction / Composite / Profil / Hachure: Hachure solide* 4022991772; Fonction structurelle: Non défini; Position: Non défini; Classification d'élement: Type ArchiCAD; Etat de rénovation: Existant; Afficher sur filtre de rénovation: Tous les filtres appropriés; Type de structure: Basique; Matériau de construction / Composite / Profil: Hachure solide* 4022991772; Surface de face extérieure: BETON65; Surface de face intérieure: BETON65; Surface latérale: BETON65; Angle d'inclinaison externe: 90 deg; Angle d'inclinaison interne: 90 deg; Type d'inclinaison de mur: Droit; Emplacement de ligne de référence: Face extérieure; Etage supérieur lié: Non lié; Option de géométrie: Uniforme
AC_Pset_RenovationAndPhasing - Renovation Status: Existing
ArchiCADQuantities - Altitude à Zéro du Projet: 0 m; Altitude à étage: 0 m; Hauteur: 2.8 m; Superficie de surface: 11.705 m2; Volume net: 1.8728 m3; Superficie: 0.6608 m2; Epaisseur: 0.16 m; Longueur de mur sur face extérieure: 4.18 m; Longueur de mur sur face intérieure: 4.08 m; Surface de mur nette sur face extérieure: 11.705 m2; Surface de mur nette sur face intérieure: 11.705 m2; Surface nette des arêtes: 1.3408 m2; Volume conditionnel: 1.8728 m3; Nombre de Portes: 0; Nombre de Fenêtres: 0; Nombre de trous (Nombre d'ouvertures vides): 0; Nombre de Poteaux: 0; Largeur totale des Portes: 0 m; Largeur totale des Fenêtres: 0 m; Epaisseur du Mur à la fin: 0.16 m; Hauteur minimum du Mur: 0 m; Hauteur maximum du Mur: 2.8 m; Longueur du Mur au centre: 4.13 m; Surface du Mur: 0.6608 m2; Périmètre du Mur: 8.60868 m; Surface brute de mur sur face intérieure: 12.488 m2; Surface brute de mur sur face extérieure: 12.488 m2; Volume brut du Mur: 1.99808 m3; Surface analytique des ouvertures sur face intérieure: 0 m2; Surface analytique des ouvertures sur face extérieure: 0 m2; Volume analytique des ouvertures dans le Mur: 0 m3; Epaisseur de couche de mur sur face extérieure: 0 m; Epaisseur de couche de mur sur face intérieure: 0 m; Epaisseur couche isolation: 0 m; Epaisseur couche d'air: 0 m; Hauteur de couche de mur minimum sur face extérieure: 0 m; Hauteur de couche de mur maximum sur face extérieure: 0 m; Hauteur de couche de mur minimum sur face intérieure: 0 m; Hauteur de couche de mur maximum sur face intérieure: 0 m; Longueur conditionnelle sur face extérieure: 4.18 m; Longueur conditionnelle sur face intérieure: 4.08 m; Surface conditionnelle sur face extérieure: 11.705 m2; Surface conditionnelle sur face intérieure: 11.705 m2; Volume de couche de mur sur face extérieure: 0 m3; Volume de couche de mur sur face intérieure: 0 m3; Volume de couche de mur conditionnelle sur face extérieure: 0 m3; Volume de couche de mur conditionnelle sur face intérieure: 0 m3; Longueur de ligne de référence: 4.36 m; Décalage étage d'implantation: 0 m; Décalage supérieur: -0.12 m; Longueur moyenne: 4.13 m; Surface des fenêtres dans le mur: 0 m2; Surface des portes dans le mur: 0 m2; Surface des baies libres dans le mur: 0 m2; Volume de poteaux: 0 m3

# IfcWallStandardCase: Solid Fill 2557160259 240, Mur-002
In: NIVEAU BAS GYMNASE
Material: Solid Fill 2557160259 0.24 m
ArchiCADProperties - ID Elément entier: Mur-002; ID Elément compact: Mur-002; Etage d'implantation: NIVEAU BAS GYMNASE; Calque: Murs Ext: Périphériques.Importation IFC; Type: Mur; Verrouillé: no; Matériau de construction / Composite / Profil / Hachure: Solid Fill 2557160259; Fonction structurelle: Non défini; Position: Non défini; Classification d'élement: Type ArchiCAD; Etat de rénovation: Existant; Afficher sur filtre de rénovation: Tous les filtres appropriés; Type de structure: Basique; Matériau de construction / Composite / Profil: Solid Fill 2557160259; Surface de face extérieure: RAL 7016 Gris anthracite; Surface de face intérieure: RAL 7016 Gris anthracite; Surface latérale: RAL 7016 Gris anthracite; Angle d'inclinaison externe: 90 deg; Angle d'inclinaison interne: 90 deg; Type d'inclinaison de mur: Droit; Emplacement de ligne de référence: Face extérieure; Etage supérieur lié: Non lié; Option de géométrie: Uniforme
AC_Pset_RenovationAndPhasing - Renovation Status: Existing
ArchiCADQuantities - Altitude à Zéro du Projet: 0 m; Altitude à étage: 0 m; Hauteur: 2.8 m; Superficie de surface: 30.6916 m2; Volume net: 7.36598 m3; Superficie: 4.95487 m2; Epaisseur: 0.24 m; Longueur de mur sur face extérieure: 20.8703 m; Longueur de mur sur face intérieure: 20.4203 m; Surface de mur nette sur face extérieure: 30.6916 m2; Surface de mur nette sur face intérieure: 30.6916 m2; Surface nette des arêtes: 7.86971 m2; Volume conditionnel: 10.289 m3; Nombre de Portes: 4; Nombre de Fenêtres: 0; Nombre de trous (Nombre d'ouvertures vides): 0; Nombre de Poteaux: 1; Largeur totale des Portes: 10.8502 m; Largeur totale des Fenêtres: 0 m; Epaisseur du Mur à la fin: 0.24 m; Hauteur minimum du Mur: 0 m; Hauteur maximum du Mur: 2.8 m; Longueur du Mur au centre: 20.6453 m; Surface du Mur: 4.95487 m2; Périmètre du Mur: 42.0406 m; Surface brute de mur sur face intérieure: 58.4368 m2; Surface brute de mur sur face extérieure: 58.4368 m2; Volume brut du Mur: 14.0248 m3; Surface analytique des ouvertures sur face intérieure: 26.4853 m2; Surface analytique des ouvertures sur face extérieure: 26.4853 m2; Volume analytique des ouvertures dans le Mur: 6.35646 m3; Epaisseur de couche de mur sur face extérieure: 0 m; Epaisseur de couche de mur sur face intérieure: 0 m; Epaisseur couche isolation: 0 m; Epaisseur couche d'air: 0 m; Hauteur de couche de mur minimum sur face extérieure: 0 m; Hauteur de couche de mur maximum sur face extérieure: 0 m; Hauteur de couche de mur minimum sur face intérieure: 0 m; Hauteur de couche de mur maximum sur face intérieure: 0 m; Longueur conditionnelle sur face extérieure: 10.0202 m; Longueur conditionnelle sur face intérieure: 9.57015 m; Surface conditionnelle sur face extérieure: 30.6916 m2; Surface conditionnelle sur face intérieure: 30.6916 m2; Volume de couche de mur sur face extérieure: 0 m3; Volume de couche de mur sur face intérieure: 0 m3; Volume de couche de mur conditionnelle sur face extérieure: 0 m3; Volume de couche de mur conditionnelle sur face intérieure: 0 m3; Longueur de ligne de référence: 20.4203 m; Décalage étage d'implantation: 0 m; Décalage supérieur: -0.12 m; Longueur moyenne: 20.6453 m; Surface des fenêtres dans le mur: 0 m2; Surface des portes dans le mur: 26.4853 m2; Surface des baies libres dans le mur: 0 m2; Volume de poteaux: 0 m3

# IfcWallStandardCase: Struct. - B.A. banché 160 (20)
In: FONDATIONS
Material: Struct. - B.A. banché 0.16 m
BET - Ratio voile BA: 12 kg/ m2
ArchiCADProperties - Etage d'implantation: FONDATIONS; Calque: Murs ext - Périphériques; Type: Mur; Verrouillé: no; Matériau de construction / Composite / Profil / Hachure: Struct. - B.A. banché; Fonction structurelle: Elément porteur; Position: Extérieur; Classification d'élement: Mur; Etat de rénovation: Existant; Afficher sur filtre de rénovation: Tous les filtres appropriés; Type de structure: Basique; Matériau de construction / Composite / Profil: Struct. - B.A. banché; Surface de face extérieure: Béton - Brut de décoffrage (Banches); Surface de face intérieure: Béton - Brut de décoffrage (Banches); Surface latérale: Béton - Brut de décoffrage (Banches); Angle d'inclinaison externe: 90 deg; Angle d'inclinaison interne: 90 deg; Type d'inclinaison de mur: Droit; Etage supérieur lié: Propre étage + 0 (-1. FONDATIONS); Option de géométrie: Uniforme
AC_Pset_RenovationAndPhasing - Renovation Status: Existing
Pset_WallCommon - LoadBearing: yes; IsExternal: yes
ArchiCADQuantities - Altitude à Zéro du Projet: -1.2 m; Altitude à étage: 0.3 m; Hauteur: 1 m; Epaisseur: 0.16 m; Nombre de Portes: 0; Nombre de Fenêtres: 0; Nombre de trous (Nombre d'ouvertures vides): 0; Nombre de Poteaux: 0; Largeur totale des Portes: 0 m; Largeur totale des Fenêtres: 0 m; Epaisseur du Mur à la fin: 0.16 m; Hauteur minimum du Mur: 0 m; Hauteur maximum du Mur: 1 m; Surface analytique des ouvertures sur face intérieure: 0 m2; Surface analytique des ouvertures sur face extérieure: 0 m2; Volume analytique des ouvertures dans le Mur: 0 m3; Epaisseur de couche de mur sur face extérieure: 0 m; Epaisseur de couche de mur sur face intérieure: 0 m; Epaisseur couche isolation: 0 m; Epaisseur couche d'air: 0 m; Hauteur de couche de mur minimum sur face extérieure: 0 m; Hauteur de couche de mur maximum sur face extérieure: 0 m; Hauteur de couche de mur minimum sur face intérieure: 0 m; Hauteur de couche de mur maximum sur face intérieure: 0 m; Volume de couche de mur sur face extérieure: 0 m3; Volume de couche de mur sur face intérieure: 0 m3; Volume de couche de mur conditionnelle sur face extérieure: 0 m3; Volume de couche de mur conditionnelle sur face intérieure: 0 m3; Décalage étage d'implantation: 0.3 m; Décalage supérieur: -0.2 m; Surface des fenêtres dans le mur: 0 m2; Surface des portes dans le mur: 0 m2; Surface des baies libres dans le mur: 0 m2; Volume de poteaux: 0 m3
Name | ID Elément entier = ID Elément compact | Emplacement de ligne de référence | Superficie de surface (m2) = Surface de mur nette sur face extérieure (m2) = Surface conditionnelle sur face extérieure (m2) | Volume net (m3) = Volume conditionnel (m3) | Superficie (m2) = Surface du Mur (m2) | Longueur de mur sur face extérieure (m) = Longueur conditionnelle sur face extérieure (m) | Longueur de mur sur face intérieure (m) = Longueur conditionnelle sur face intérieure (m) | Surface de mur nette sur face intérieure (m2) = Surface conditionnelle sur face intérieure (m2) | Surface nette des arêtes (m2) | Longueur du Mur au centre (m) = Longueur moyenne (m) | Périmètre du Mur (m) | Surface brute de mur sur face intérieure (m2) | Surface brute de mur sur face extérieure (m2) | Volume brut du Mur (m3) | Longueur de ligne de référence (m)
MurExt-021 | MurExt-021 | Centrer | 10.175 | 1.628 | 1.6024 | 9.855 | 10.175 | 10.175 | 3.256 | 10.015 | 20.4825 | 10.175 | 10.175 | 1.628 | 10.095
MurExt-022 | MurExt-022 | Centrer | 4.9803 | 0.796848 | 0.809648 | 4.9803 | 5.1403 | 4.9803 | 1.7537 | 5.0603 | 10.5069 | 5.1403 | 5.1403 | 0.822448 | 5.0603
MurExt-023 | MurExt-023 | Centrer | 11.2847 | 1.80564 | 1.83124 | 11.4447 | 11.4458 | 11.2858 | 3.77129 | 11.4453 | 23.2106 | 11.6058 | 11.6047 | 1.85685 | 11.5253
MurExt-024 | MurExt-024 | Centrer | 6.95101 | 1.0709 | 1.09927 | 6.791 | 6.94989 | 6.77034 | 2.14179 | 6.87045 | 14.1285 | 7.10992 | 7.11104 | 1.13768 | 6.95046
MurExt-025 | MurExt-025 | Centrer | 3.89407 | 0.623199 | 0.6232 | 3.73407 | 4.05593 | 3.89592 | 1.2464 | 3.895 | 8.24386 | 4.05593 | 4.05408 | 0.648801 | 3.895
MurExt-026 | MurExt-026 | Centrer | 6.92296 | 1.10767 | 1.12047 | 6.92296 | 7.08296 | 6.92296 | 2.37535 | 7.00296 | 14.3922 | 7.08296 | 7.08296 | 1.13327 | 7.00296
MurExt-027 | MurExt-027 | Centrer | 8.7 | 1.43318 | 1.3792 | 8.54 | 8.7 | 8.78046 | 3.02337 | 8.62 | 17.6263 | 8.78046 | 8.96 | 1.43341 | 8.7
MurExt-028 | MurExt-028 | Centrer | 15.26 | 2.4416 | 2.4416 | 15.1 | 15.42 | 15.26 | 4.8832 | 15.26 | 30.9725 | 15.42 | 15.42 | 2.4672 | 15.26
MurExt-029 | MurExt-029 | Centrer | 7.08 | 1.1328 | 1.1456 | 7.08 | 7.24 | 7.08 | 2.2656 | 7.16 | 14.7063 | 7.4 | 7.4 | 1.184 | 7.24
MurExt-030 | MurExt-030 | Centrer | 21.38 | 3.4208 | 3.4208 | 21.38 | 21.38 | 21.38 | 6.8416 | 21.38 | 43.08 | 21.7 | 21.7 | 3.472 | 21.62
MurExt-031 | MurExt-031 | Centrer | 2.14 | 0.3424 | 0.3296 | 2.14 | 1.98 | 2.14 | 0.6848 | 2.06 | 4.50627 | 2.3 | 2.3 | 0.368 | 2.14
MurExt-032 | MurExt-032 | Centrer | 1.19241 | 0.190785 | 0.190785 | 1.19241 | 1.19241 | 1.19241 | 0.38157 | 1.19241 | 2.83736 | 1.35241 | 1.35241 | 0.216385 | 1.19241
MurExt-033 | MurExt-033 | Centrer | 4.14 | 0.6624 | 0.6624 | 3.98 | 4.3 | 4.14 | 1.3248 | 4.14 | 8.73255 | 4.3 | 4.3 | 0.688 | 4.22
MurExt-034 | MurExt-034 | Face intérieure | 20.5503 | 3.28805 | 3.31365 | 20.5503 | 20.8703 | 20.5503 | 6.5761 | 20.7103 | 41.8731 | 20.8703 | 20.8703 | 3.33925 | 20.7103
MurExt-035 | MurExt-035 | Centrer | 6.28 | 1.0048 | 0.992 | 6.12 | 6.28 | 6.28 | 2.0096 | 6.2 | 12.7863 | 6.44 | 6.44 | 1.0304 | 6.36
MurExt-036 | MurExt-036 | Centrer | 4.24 | 0.6784 | 0.6784 | 4.08 | 4.4 | 4.24 | 1.3568 | 4.24 | 8.93255 | 4.4 | 4.4 | 0.704 | 4.24
MurExt-037 | MurExt-037 | Centrer | 3.32 | 0.5312 | 0.5312 | 3.16 | 3.48 | 3.32 | 1.0624 | 3.32 | 7.09255 | 3.48 | 3.48 | 0.5568 | 3.32
MurExt-038 | MurExt-038 | Centrer | 2.68108 | 0.428973 | 0.428973 | 2.52108 | 2.84108 | 2.68108 | 0.857945 | 2.68108 | 5.81471 | 2.84108 | 2.84108 | 0.454573 | 2.68108
MurExt-039 | MurExt-039 | Centrer | 1.76 | 0.2816 | 0.2816 | 1.6 | 1.92 | 1.76 | 0.5632 | 1.76 | 3.97255 | 1.92 | 1.92 | 0.3072 | 1.76
MurExt-040 | MurExt-040 | Centrer | 2.52108 | 0.403373 | 0.416173 | 2.52108 | 2.68108 | 2.52108 | 0.806745 | 2.60108 | 5.58843 | 2.84108 | 2.84108 | 0.454573 | 2.68108

# IfcWallStandardCase: •GYMN 10+10 0232896968 200 (3)
In: NIVEAU BAS GYMNASE
Material: Hachure solide* 3992800808 0.02 m, Empty Fill 290923149 0.08 m, Hachure solide* 4022991772 0.1 m
ArchiCADProperties - Etage d'implantation: NIVEAU BAS GYMNASE; Nom de Zone: Hall & Circulation; Numéro de Zone: 010; Calque: Murs Ext: Périphériques.Importation IFC; Type: Mur; Verrouillé: no; Matériau de construction / Composite / Profil / Hachure: •GYMN 10+10 0232896968; Fonction structurelle: Non défini; Position: Non défini; Classification d'élement: Type ArchiCAD; Etat de rénovation: Existant; Afficher sur filtre de rénovation: Tous les filtres appropriés; Type de structure: Composite; Matériau de construction / Composite / Profil: •GYMN 10+10 0232896968; Surface de face extérieure: BETON65; Surface de face intérieure: BETON65; Angle d'inclinaison externe: 90 deg; Angle d'inclinaison interne: 90 deg; Type d'inclinaison de mur: Droit; Emplacement de ligne de référence: Face extérieure; Etage supérieur lié: Non lié; Option de géométrie: Uniforme
AC_Pset_RenovationAndPhasing - Renovation Status: Existing
ArchiCADQuantities - Altitude à Zéro du Projet: 0 m; Altitude à étage: 0 m; Epaisseur: 0.2 m; Nombre de Portes: 1; Nombre de trous (Nombre d'ouvertures vides): 0; Nombre de Poteaux: 0; Epaisseur du Mur à la fin: 0.2 m; Hauteur minimum du Mur: 0 m; Epaisseur de couche de mur sur face extérieure: 0.02 m; Epaisseur de couche de mur sur face intérieure: 0.1 m; Epaisseur couche isolation: 0 m; Epaisseur couche d'air: 0 m; Hauteur de couche de mur minimum sur face extérieure: 0 m; Hauteur de couche de mur minimum sur face intérieure: 0 m; Décalage étage d'implantation: 0 m; Décalage supérieur: -0.12 m; Surface des baies libres dans le mur: 0 m2; Volume de poteaux: 0 m3
Name | ID Elément entier = ID Elément compact | Hauteur (m) | Superficie de surface (m2) = Surface de mur nette sur face extérieure (m2) = Surface conditionnelle sur face extérieure (m2) | Volume net (m3) | Superficie (m2) = Surface du Mur (m2) | Longueur de mur sur face extérieure (m) | Longueur de mur sur face intérieure (m) | Surface de mur nette sur face intérieure (m2) = Surface conditionnelle sur face intérieure (m2) | Surface nette des arêtes (m2) | Volume conditionnel (m3) | Nombre de Fenêtres | Largeur totale des Portes (m) | Largeur totale des Fenêtres (m) | Hauteur maximum du Mur (m) = Hauteur de couche de mur maximum sur face extérieure (m) = Hauteur de couche de mur maximum sur face intérieure (m) | Longueur du Mur au centre (m) = Longueur moyenne (m) | Périmètre du Mur (m) | Surface brute de mur sur face intérieure (m2) = Surface brute de mur sur face extérieure (m2) | Volume brut du Mur (m3) | Surface analytique des ouvertures sur face intérieure (m2) = Surface analytique des ouvertures sur face extérieure (m2) | Volume analytique des ouvertures dans le Mur (m3) | Longueur conditionnelle sur face extérieure (m) | Longueur conditionnelle sur face intérieure (m) | Volume de couche de mur sur face extérieure (m3) | Volume de couche de mur sur face intérieure (m3) | Volume de couche de mur conditionnelle sur face extérieure (m3) | Volume de couche de mur conditionnelle sur face intérieure (m3) | Longueur de ligne de référence (m) | Surface des fenêtres dans le mur (m2) | Surface des portes dans le mur (m2) | Surface latérale
Mur-004 | Mur-004 | 2.75 | 8.21245 | 1.64249 | 0.762 | 3.81 | 3.81 | 8.21245 | 1.387 | 2.0955 | 0 | 0.89 | 0 | 2.75 | 3.81 | 8.02 | 11.1925 | 2.2385 | 2.26505 | 0.45301 | 2.92 | 2.92 | 0.164249 | 0.821245 | 0.20955 | 1.04775 | 4.07 | 0 | 2.27395
Mur-022 | Mur-022 | 2.82 | 0.76 | 0.152 | 0.38 | 1.9 | 1.9 | 0.76 | 0.38 | 1.064 | 0 | 1.9 | 0 | 2.8 | 1.9 | 4.2 | 6.348 | 1.2696 | 4.56 | 0.912 | 1.9 | 1.9 | 0.0152 | 0.076 | 0.1064 | 0.532 | 1.9 | 0 | 4.56 | BETON65
Mur-022 | Mur-022 | 2.8 | 0.91 | 0.29064 | 0.286 | 1.3 | 1.56 | 1.638 | 0.3376 | 0.83664 | 1 | 0.9 | 0.4 | 2.8 | 1.43 | 3.38802 | 5.138 | 1.0276 | 2.73 | 0.546 | 0 | 0.26 | 0.0182 | 0.1638 | 0.0728 | 0.4368 | 1.3 | 0.84 | 1.89 | BETON65

# IfcWallStandardCase: •GYMN 16+10 260 (14)
ArchiCADProperties - Calque: 0.Importation IFC; Type: Mur; Verrouillé: no; Fonction structurelle: Non défini; Position: Non défini; Classification d'élement: Type ArchiCAD; Etat de rénovation: Existant; Afficher sur filtre de rénovation: Tous les filtres appropriés; Type de structure: Composite; Angle d'inclinaison externe: 90 deg; Angle d'inclinaison interne: 90 deg; Type d'inclinaison de mur: Droit; Emplacement de ligne de référence: Face extérieure; Etage supérieur lié: Non lié; Option de géométrie: Uniforme
AC_Pset_RenovationAndPhasing - Renovation Status: Existing
ArchiCADQuantities - Epaisseur: 0.26 m; Nombre de trous (Nombre d'ouvertures vides): 0; Epaisseur du Mur à la fin: 0.26 m; Epaisseur couche isolation: 0 m; Epaisseur couche d'air: 0 m; Décalage supérieur: -0.12 m; Surface des baies libres dans le mur: 0 m2; Volume de poteaux: 0 m3
Name | In | Material | ID Elément entier = ID Elément compact | Etage d'implantation | Nom de Zone | Numéro de Zone | Matériau de construction / Composite / Profil / Hachure = Matériau de construction / Composite / Profil | Surface de face extérieure | Surface de face intérieure | Altitude à Zéro du Projet (m) | Altitude à étage (m) = Décalage étage d'implantation (m) | Hauteur (m) | Superficie de surface (m2) = Surface de mur nette sur face extérieure (m2) | Volume net (m3) | Superficie (m2) = Surface du Mur (m2) | Longueur de mur sur face extérieure (m) | Longueur de mur sur face intérieure (m) | Surface de mur nette sur face intérieure (m2) | Surface nette des arêtes (m2) | Volume conditionnel (m3) | Nombre de Portes | Nombre de Fenêtres | Nombre de Poteaux | Largeur totale des Portes (m) | Largeur totale des Fenêtres (m) | Hauteur minimum du Mur (m) = Hauteur de couche de mur minimum sur face extérieure (m) = Hauteur de couche de mur minimum sur face intérieure (m) | Hauteur maximum du Mur (m) = Hauteur de couche de mur maximum sur face extérieure (m) = Hauteur de couche de mur maximum sur face intérieure (m) | Longueur du Mur au centre (m) = Longueur moyenne (m) | Périmètre du Mur (m) | Surface brute de mur sur face intérieure (m2) = Surface brute de mur sur face extérieure (m2) | Volume brut du Mur (m3) | Surface analytique des ouvertures sur face intérieure (m2) = Surface analytique des ouvertures sur face extérieure (m2) | Volume analytique des ouvertures dans le Mur (m3) | Epaisseur de couche de mur sur face extérieure (m) | Epaisseur de couche de mur sur face intérieure (m) | Longueur conditionnelle sur face extérieure (m) | Longueur conditionnelle sur face intérieure (m) | Surface conditionnelle sur face extérieure (m2) | Surface conditionnelle sur face intérieure (m2) | Volume de couche de mur sur face extérieure (m3) | Volume de couche de mur sur face intérieure (m3) | Volume de couche de mur conditionnelle sur face extérieure (m3) | Volume de couche de mur conditionnelle sur face intérieure (m3) | Longueur de ligne de référence (m) | Surface des fenêtres dans le mur (m2) | Surface des portes dans le mur (m2)
Mur-021 | NIVEAU BAS GYMNASE | Hachure solide* 3992800808 0.02 m, Empty Fill 290923149 0.08 m, Hachure solide* 2593434267 0.16 m | Mur-021 | NIVEAU BAS GYMNASE | Sanit Vest 5 | 010 | •GYMN 16+10 | BETON65 | Peinture-09 | -0.2 | -0.2 | 2.95 | 21.8416 | 6.22165 | 2.16454 | 8.19516 | 8.45516 | 24.2607 | 3.97821 | 6.22165 | 0 | 0 | 0 | 0 | 0 | 0 | 2.95 | 8.32516 | 17.278 | 24.9427 | 6.48511 | 0 | 0 | 0.02 | 0.16 | 8.19516 | 8.45516 | 21.8416 | 24.2607 | 0.436833 | 3.88172 | 0.436833 | 3.88172 | 8.45516 | 0 | 0
Mur-021 | NIVEAU BAS GYMNASE | Hachure solide* 3992800808 0.02 m, Empty Fill 290923149 0.08 m, Hachure solide* 2593434267 0.16 m | Mur-021 | NIVEAU BAS GYMNASE | Sanit Vest 5 | 010 | •GYMN 16+10 | BETON65 | BETON65 | -0.2 | -0.2 | 2.95 | 19.214 | 5.3286 | 1.95 | 7.37 | 7.63 | 20.428 | 1.8312 | 5.3286 | 0 | 0 | 0 | 0 | 0 | 0 | 2.8 | 7.5 | 15.6277 | 23.3005 | 6.05813 | 0 | 0 | 0.02 | 0.16 | 7.37 | 7.63 | 19.214 | 20.428 | 0.38428 | 3.26848 | 0.38428 | 3.26848 | 7.63 | 0 | 0 | ArchiCADProperties - Surface latérale: BETON65
Mur-021 | NIVEAU BAS GYMNASE | Hachure solide* 2593434267 0.16 m, Empty Fill 290923149 0.08 m, Hachure solide* 3992800808 0.02 m | Mur-021 | NIVEAU BAS GYMNASE | Dépot 2 | 010 | •GYMN 16+10 (1) | Peinture-09 | BETON65 | -0.2 | -0.2 | 2.95 | 29.2853 | 7.51659 | 2.5961 | 10.255 | 9.715 | 25.3505 | 4.79365 | 7.51659 | 0 | 0 | 0 | 0 | 0 | 0 | 2.95 | 9.985 | 20.7198 | 30.2523 | 7.86559 | 0 | 0 | 0.16 | 0.02 | 10.255 | 9.715 | 29.2853 | 25.3505 | 4.68564 | 0.50701 | 4.68564 | 0.50701 | 10.255 | 0 | 0
Mur-005 | NIVEAU BAS GYMNASE | Hachure solide* 2593434267 0.16 m, Empty Fill 290923149 0.08 m, Hachure solide* 3992800808 0.02 m | Mur-005 | NIVEAU BAS GYMNASE | Chaufferie | 010 | •GYMN 16+10 (1) | Peinture-09 | BETON65 | 0 | 0 | 2.7 | 18.323 | 4.76374 | 1.8018 | 6.93 | 6.93 | 18.279 | 3.5124 | 4.76374 | 0 | 0 | 0 | 0 | 0 | 0 | 2.7 | 6.93 | 14.5954 | 19.413 | 5.04738 | 0 | 0 | 0.16 | 0.02 | 6.93 | 6.93 | 18.323 | 18.279 | 2.93168 | 0.36558 | 2.93168 | 0.36558 | 7.19 | 0 | 0
Mur-004 | NIVEAU BAS GYMNASE | Hachure solide* 3992800808 0.02 m, Empty Fill 290923149 0.08 m, Hachure solide* 2593434267 0.16 m | Mur-004 | NIVEAU BAS GYMNASE | Hall & Circulation | 010 | •GYMN 16+10 | Revêt-murs int. | Revêt-murs int. | 0 | 0 | 2.82 | 8.45475 | 2.21207 | 0.818884 | 3.11955 | 3.17955 | 7.96075 | 0.790684 | 2.21207 | 0 | 0 | 0 | 0 | 0 | 0 | 2.8 | 3.14955 | 6.99483 | 9.49914 | 2.46978 | 0 | 0 | 0.02 | 0.16 | 3.11955 | 3.17955 | 8.45475 | 7.96075 | 0.169095 | 1.33204 | 0.169095 | 1.33204 | 3.11955 | 0 | 0 | ArchiCADProperties - Surface latérale: Revêt-murs int.
Mur-022 | NIVEAU BAS GYMNASE | Hachure solide* 2593434267 0.16 m, Empty Fill 290923149 0.08 m, Hachure solide* 3992800808 0.02 m | Mur-022 | NIVEAU BAS GYMNASE | Sanit Vest 2 | 010 | •GYMN 16+10 (1) | Peinture-09 | BETON65 | -0.2 | -0.2 | 2.95 | 49.858 | 12.8304 | 5.5926 | 21.78 | 21.24 | 45.1114 | 10.3661 | 16.4439 | 1 | 5 | 1 | 1.9 | 15 | 2.22045e-16 | 2.95 | 21.51 | 43.7698 | 64.251 | 16.7053 | 13.898 | 3.61348 | 0.16 | 0.02 | 19.88 | 19.34 | 57.058 | 52.3114 | 7.97728 | 0.902229 | 10.201 | 1.18019 | 21.78 | 9.3 | 4.598
Mur-022 | NIVEAU BAS GYMNASE | Hachure solide* 2593434267 0.16 m, Empty Fill 290923149 0.08 m, Hachure solide* 3992800808 0.02 m | Mur-022 | NIVEAU BAS GYMNASE |  |  | •GYMN 16+10 (1) | Peinture-09 | BETON65 | -0.2 | -0.2 | 2.95 | 20.663 | 5.31942 | 2.2282 | 8.7 | 8.44 | 18.959 | 4.1661 | 6.49722 | 1 | 1 | 0 | 1.3 | 3 | 0 | 2.95 | 8.57 | 17.7677 | 25.665 | 6.6729 | 4.53 | 1.1778 | 0.16 | 0.02 | 7.4 | 7.14 | 22.463 | 20.759 | 3.30608 | 0.37918 | 4.03088 | 0.46978 | 8.7 | 1.8 | 2.73
Mur-004 | NIVEAU HAUT ENTRÉE | Hachure solide* 2593434267 0.16 m, Empty Fill 290923149 0.08 m, Hachure solide* 3992800808 0.02 m | Mur-004 | NIVEAU HAUT ENTRÉE | Sanit Visit. F | 010 | •GYMN 16+10 (1) | Peinture-09 | BETON65 | 2.75 | -0.25 | 3.45 | 46.59 | 12.0276 | 3.666 | 14.36 | 13.84 | 45.4698 | 7.3496 | 12.6516 | 0 | 1 | 1 | 0 | 1.2 | 0 | 3.45 | 14.1 | 28.9354 | 49.542 | 12.8809 | 2.4 | 0.624 | 0.16 | 0.02 | 14.36 | 12.64 | 46.59 | 45.4698 | 7.4544 | 0.909396 | 7.8384 | 0.957396 | 14.36 | 2.4 | 0
Mur-003 | NIVEAU HAUT ENTRÉE | Hachure solide* 3992800808 0.02 m, Empty Fill 290923149 0.08 m, Hachure solide* 2593434267 0.16 m | Mur-003 | NIVEAU HAUT ENTRÉE | Salle de Sport de Combat | 006 | •GYMN 16+10 | BETON65 | Peinture-09 | 2.85 | -0.15 | 3.35 | 5.0943 | 1.32663 | 0.3978 | 1.53 | 1.53 | 5.1063 | 0.7456 | 1.32663 | 0 | 0 | 1 | 0 | 0 | 0 | 3.35 | 1.53 | 3.79539 | 5.9653 | 1.55098 | 0 | 0 | 0.02 | 0.16 | 1.53 | 1.53 | 5.0943 | 5.1063 | 0.101886 | 0.817008 | 0.101886 | 0.817008 | 1.53 | 0 | 0
Mur-002 | NIVEAU HAUT ENTRÉE | Hachure solide* 3992800808 0.02 m, Empty Fill 290923149 0.08 m, Hachure solide* 2593434267 0.16 m | Mur-002 | NIVEAU HAUT ENTRÉE | Hall d'Entrée | 010 | •GYMN 16+10 | BETON65 | Peinture-09 | 2.97 | -0.03 | 3.23 | 13.3785 | 3.39055 | 1.6536 | 6.36 | 6.36 | 12.9263 | 2.7484 | 5.23648 | 1 | 1 | 1 | 1.9 | 0.65 | 0 | 3.23 | 6.36 | 13.4554 | 21.3826 | 5.55948 | 7.09971 | 1.84593 | 0.02 | 0.16 | 4.46 | 4.46 | 14.8661 | 14.4139 | 0.26757 | 2.06821 | 0.409564 | 3.20416 | 6.36 | 1.48762 | 5.61209
Mur-002 | NIVEAU HAUT ENTRÉE | Hachure solide* 2593434267 0.16 m, Empty Fill 290923149 0.08 m, Hachure solide* 3992800808 0.02 m | Mur-002 | NIVEAU HAUT ENTRÉE | Salle de Sport de Combat | 006 | •GYMN 16+10 (1) | Peinture-09 | BETON65 | 2.6 | -0.4 | 3.6 | 49.772 | 12.821 | 3.9416 | 15.42 | 14.9 | 48.14 | 7.9832 | 14.3134 | 0 | 3 | 1 | 0 | 8.2 | 0 | 3.6 | 15.16 | 31.0554 | 55.512 | 14.4331 | 5.74 | 1.4924 | 0.16 | 0.02 | 15.42 | 14.9 | 55.512 | 53.88 | 7.96352 | 0.9628 | 8.88192 | 1.0776 | 15.42 | 5.74 | 0
Mur-005 | NIVEAU HAUT ENTRÉE | Hachure solide* 3992800808 0.02 m, Empty Fill 290923149 0.08 m, Hachure solide* 2593434267 0.16 m | Mur-005 | NIVEAU HAUT ENTRÉE | Salle de Sport de Combat | 006 | •GYMN 16+10 | BETON65 | Peinture-09 | 2.75 | -0.25 | 3.45 | 46.7955 | 12.3821 | 4.0638 | 15.37 | 15.89 | 47.9685 | 8.1276 | 14.0201 | 0 | 3 | 0 | 0 | 9 | 0 | 3.45 | 15.63 | 31.9954 | 54.8205 | 14.2533 | 6.3 | 1.638 | 0.02 | 0.16 | 15.37 | 15.89 | 46.7955 | 47.9685 | 0.93591 | 7.67496 | 1.06191 | 8.68296 | 15.89 | 6.3 | 0
Mur-004 | NIVEAU HAUT ENTRÉE | Hachure solide* 3992800808 0.02 m, Empty Fill 290923149 0.08 m, Hachure solide* 2593434267 0.16 m | Mur-004 | NIVEAU HAUT ENTRÉE | Bureau Association | 011 | •GYMN 16+10 | BETON65 | Peinture-09 | 2.75 | -0.25 | 3.45 | 10.374 | 2.8518 | 1.0478 | 3.9 | 4.16 | 11.202 | 3.025 | 3.6708 | 0 | 2 | 1 | 0 | 4.5 | 0 | 3.45 | 4.03 | 8.6877 | 14.352 | 3.73152 | 3.15 | 0.819 | 0.02 | 0.16 | 3.9 | 4.16 | 11.424 | 12.252 | 0.20748 | 1.79232 | 0.27048 | 2.29632 | 4.16 | 3.15 | 0
Mur-004 | NIVEAU HAUT ENTRÉE | Hachure solide* 3992800808 0.02 m, Empty Fill 290923149 0.08 m, Hachure solide* 2593434267 0.16 m | Mur-004 | NIVEAU HAUT ENTRÉE | Salle de Sport de Combat | 006 | •GYMN 16+10 | BETON65 | Peinture-09 | 2.75 | -0.25 | 3.45 | 44.8987 | 11.7344 | 4.5474 | 17.36 | 17.62 | 45.2437 | 9.9594 | 15.6326 | 0 | 4 | 1 | 0 | 12.9339 | 0 | 3.45 | 17.49 | 35.6077 | 60.789 | 15.8051 | 14.9933 | 3.89825 | 0.02 | 0.16 | 14.08 | 17.62 | 44.8987 | 45.2437 | 0.897975 | 7.239 | 1.19784 | 9.63792 | 17.62 | 14.9933 | 0

# IfcWallStandardCase: •GYMN 18+10 280 (2)
In: NIVEAU BAS GYMNASE
Material: Hachure solide* 3992800808 0.02 m, Empty Fill 290923149 0.08 m, Hachure solide* 2593434267 0.18 m
ArchiCADProperties - Etage d'implantation: NIVEAU BAS GYMNASE; Calque: 0.Importation IFC; Type: Mur; Verrouillé: no; Matériau de construction / Composite / Profil / Hachure: •GYMN 18+10; Fonction structurelle: Non défini; Position: Non défini; Classification d'élement: Type ArchiCAD; Etat de rénovation: Existant; Afficher sur filtre de rénovation: Tous les filtres appropriés; Type de structure: Composite; Matériau de construction / Composite / Profil: •GYMN 18+10; Angle d'inclinaison externe: 90 deg; Angle d'inclinaison interne: 90 deg; Type d'inclinaison de mur: Droit; Emplacement de ligne de référence: Face extérieure; Etage supérieur lié: Non lié; Option de géométrie: Uniforme
AC_Pset_RenovationAndPhasing - Renovation Status: Existing
ArchiCADQuantities - Altitude à Zéro du Projet: 0 m; Altitude à étage: 0 m; Hauteur: 2.75 m; Epaisseur: 0.28 m; Nombre de trous (Nombre d'ouvertures vides): 0; Nombre de Poteaux: 0; Epaisseur du Mur à la fin: 0.28 m; Hauteur minimum du Mur: 0 m; Hauteur maximum du Mur: 2.75 m; Epaisseur de couche de mur sur face extérieure: 0.02 m; Epaisseur de couche de mur sur face intérieure: 0.18 m; Epaisseur couche isolation: 0 m; Epaisseur couche d'air: 0 m; Hauteur de couche de mur minimum sur face extérieure: 0 m; Hauteur de couche de mur maximum sur face extérieure: 2.75 m; Hauteur de couche de mur minimum sur face intérieure: 0 m; Hauteur de couche de mur maximum sur face intérieure: 2.75 m; Décalage étage d'implantation: 0 m; Décalage supérieur: -0.12 m; Surface des baies libres dans le mur: 0 m2; Volume de poteaux: 0 m3
Name | ID Elément entier = ID Elément compact | Surface de face extérieure | Surface de face intérieure | Superficie de surface (m2) = Surface de mur nette sur face extérieure (m2) = Surface conditionnelle sur face extérieure (m2) | Volume net (m3) | Superficie (m2) = Surface du Mur (m2) | Longueur de mur sur face extérieure (m) | Longueur de mur sur face intérieure (m) | Surface de mur nette sur face intérieure (m2) = Surface conditionnelle sur face intérieure (m2) | Surface nette des arêtes (m2) | Volume conditionnel (m3) | Nombre de Portes | Nombre de Fenêtres | Largeur totale des Portes (m) | Largeur totale des Fenêtres (m) | Longueur du Mur au centre (m) = Longueur moyenne (m) | Périmètre du Mur (m) | Surface brute de mur sur face intérieure (m2) = Surface brute de mur sur face extérieure (m2) | Volume brut du Mur (m3) | Surface analytique des ouvertures sur face intérieure (m2) = Surface analytique des ouvertures sur face extérieure (m2) | Volume analytique des ouvertures dans le Mur (m3) | Longueur conditionnelle sur face extérieure (m) | Longueur conditionnelle sur face intérieure (m) | Volume de couche de mur sur face extérieure (m3) | Volume de couche de mur sur face intérieure (m3) | Volume de couche de mur conditionnelle sur face extérieure (m3) | Volume de couche de mur conditionnelle sur face intérieure (m3) | Longueur de ligne de référence (m) | Surface des fenêtres dans le mur (m2) | Surface des portes dans le mur (m2)
Mur-004 | Mur-004 | RAL 7024 Gris Graphite | RAL 7024 Gris Graphite | 1.96748 | 0.550894 | 0.200325 | 0.715447 | 0.715447 | 1.96748 | 1.17065 | 0.550894 | 0 | 0 | 0 | 0 | 0.715447 | 1.99089 | 2.68248 | 0.751094 | 0 | 0 | 0.715447 | 0.715447 | 0.0393496 | 0.354146 | 0.0393496 | 0.354146 | 0.975447 | 0 | 0 | ArchiCADProperties - Surface latérale: RAL 7024 Gris Graphite
Mur-021 | Mur-021 | BETON65 | Peinture-09 | 32.5832 | 9.38949 | 5.77088 | 20.3503 | 20.8703 | 34.0132 | 8.57977 | 12.6893 | 4 | 2 | 8.21 | 2.4 | 20.6103 | 41.9848 | 57.3933 | 16.0701 | 23.3802 | 6.54644 | 12.1403 | 12.6603 | 0.651664 | 6.12237 | 1.11927 | 10.3308 | 20.8703 | 4.8 | 18.6353 | ArchiCADProperties - Nom de Zone: Dépot 2; Numéro de Zone: 010

# IfcWallStandardCase: •GYMN PANNEAU 1 0232896968 240 (3)
Material: Hachure solide* 1842511997 0.1 m, Isolation 347608549 0.12 m, Hachure solide* 398427698 0.02 m
ArchiCADProperties - ID Elément entier: Mur-003; ID Elément compact: Mur-003; Calque: Murs Ext: Périphériques.Importation IFC; Type: Mur; Verrouillé: no; Matériau de construction / Composite / Profil / Hachure: •GYMN PANNEAU 1 0232896968; Fonction structurelle: Non défini; Position: Non défini; Classification d'élement: Type ArchiCAD; Etat de rénovation: Existant; Afficher sur filtre de rénovation: Tous les filtres appropriés; Type de structure: Composite; Matériau de construction / Composite / Profil: •GYMN PANNEAU 1 0232896968; Angle d'inclinaison externe: 90 deg; Angle d'inclinaison interne: 90 deg; Type d'inclinaison de mur: Droit; Emplacement de ligne de référence: Face extérieure; Etage supérieur lié: Non lié; Option de géométrie: Uniforme
AC_Pset_RenovationAndPhasing - Renovation Status: Existing
ArchiCADQuantities - Epaisseur: 0.24 m; Nombre de Portes: 0; Nombre de trous (Nombre d'ouvertures vides): 0; Largeur totale des Portes: 0 m; Epaisseur du Mur à la fin: 0.24 m; Epaisseur de couche de mur sur face extérieure: 0.1 m; Epaisseur de couche de mur sur face intérieure: 0.02 m; Epaisseur couche isolation: 0 m; Epaisseur couche d'air: 0 m; Décalage supérieur: -0.12 m; Surface des portes dans le mur: 0 m2; Surface des baies libres dans le mur: 0 m2; Volume de poteaux: 0 m3
Name | In | Etage d'implantation | Surface de face extérieure | Surface de face intérieure | Altitude à Zéro du Projet (m) | Altitude à étage (m) = Décalage étage d'implantation (m) | Hauteur (m) = Hauteur maximum du Mur (m) = Hauteur de couche de mur maximum sur face extérieure (m) = Hauteur de couche de mur maximum sur face intérieure (m) | Superficie de surface (m2) = Surface de mur nette sur face extérieure (m2) = Surface de mur nette sur face intérieure (m2) | Volume net (m3) | Superficie (m2) = Surface du Mur (m2) | Longueur de mur sur face extérieure (m) = Longueur de ligne de référence (m) | Longueur de mur sur face intérieure (m) | Surface nette des arêtes (m2) | Volume conditionnel (m3) | Nombre de Fenêtres | Nombre de Poteaux | Largeur totale des Fenêtres (m) | Hauteur minimum du Mur (m) = Hauteur de couche de mur minimum sur face extérieure (m) = Hauteur de couche de mur minimum sur face intérieure (m) | Longueur du Mur au centre (m) = Longueur moyenne (m) | Périmètre du Mur (m) | Surface brute de mur sur face intérieure (m2) = Surface brute de mur sur face extérieure (m2) | Volume brut du Mur (m3) | Surface analytique des ouvertures sur face intérieure (m2) = Surface analytique des ouvertures sur face extérieure (m2) = Surface des fenêtres dans le mur (m2) | Volume analytique des ouvertures dans le Mur (m3) | Longueur conditionnelle sur face extérieure (m) | Longueur conditionnelle sur face intérieure (m) | Surface conditionnelle sur face extérieure (m2) = Surface conditionnelle sur face intérieure (m2) | Volume de couche de mur sur face extérieure (m3) | Volume de couche de mur sur face intérieure (m3) | Volume de couche de mur conditionnelle sur face extérieure (m3) | Volume de couche de mur conditionnelle sur face intérieure (m3)
Mur-003 | NIVEAU BAS GYMNASE | NIVEAU BAS GYMNASE | Pierre-Granite rouge | Pierre-Granite rouge | 2.8 | 2.8 | 6.58885 | 33.1628 | 7.95906 | 1.32772 | 5.30717 | 5.75717 | 4.12876 | 8.39235 | 1 | 1 | 0.607011 | 0 | 5.53217 | 11.8143 | 35.7151 | 8.57163 | 1.80537 | 0.433289 | 5.30717 | 5.75717 | 34.9681 | 3.31628 | 0.663255 | 3.49681 | 0.699363 | ArchiCADProperties - Surface latérale: Pierre-Granite rouge
Mur-003 | NIVEAU HAUT ENTRÉE | NIVEAU HAUT ENTRÉE | Revêt-murs int. | Enduit - Blanc nature | 4.46 | 1.46 | 4.35 | 88.4032 | 21.2168 | 5.4048 | 22.52 | 22.52 | 11.2656 | 23.5109 | 2 | 0 | 6.8 | 4.35 | 22.52 | 45.52 | 97.962 | 23.5109 | 9.55877 | 2.29411 | 15.72 | 15.72 | 88.4032 | 8.84032 | 1.76806 | 9.7962 | 1.95924
Mur-003 | NIVEAU HAUT ENTRÉE | NIVEAU HAUT ENTRÉE | Revêt-murs int. | Enduit - Blanc nature | 4.46 | 1.46 | 4.35 | 67.1782 | 16.1228 | 5.3544 | 22.31 | 22.31 | 6.71862 | 23.0306 | 6 | 1 | 20.4757 | 0 | 22.31 | 45.1 | 97.0485 | 23.2916 | 28.7828 | 6.90787 | 1.83426 | 1.83426 | 67.1782 | 6.71782 | 1.34356 | 9.5961 | 1.91922

# IfcWindow: F Devanture 1 10 (4)
Type - OperationType: USERDEFINED; ParameterTakesPrecedence: no; Sizeable: no
Material: Sans Trame
Pset_WindowCommon - ThermalTransmittance: 0; GlazingAreaFraction: 0
ArchiCADProperties - Type: Fenêtre; Verrouillé: no; Matériau de construction / Composite / Profil / Hachure: Menuis1; Fonction structurelle: Non défini; Position: Non défini; Classification d'élement: Type ArchiCAD; Etat de rénovation: Existant; Afficher sur filtre de rénovation: Tous les filtres appropriés; Orientation: G
AC_Pset_RenovationAndPhasing - Renovation Status: Existing
ArchiCADQuantities - Epaisseur: 0.05 m; Hauteur nominale linteau: 2.1 m; Hauteur linteau côté ébrasure: 2.1 m; Hauteur linteau côté opposé ébrasure: 2.1 m
Name | In | OverallHeight (m) = ArchiCADQuantities, Hauteur (m) = Hauteur ouverture côté ébrasure (m) = Hauteur ouverture côté opposé ébrasure (m) = Hauteur nominale de l'ouverture côté ébrasure (m) = Hauteur nominale de l'ouverture côté opposée ébrasure (m) | OverallWidth (m) = ArchiCADQuantities, Largeur (m) = Largeur ouverture côté ébrasure (m) = Largeur ouverture côté opposé ébrasure (m) = Largeur nominale de l'ouverture côté ébrasure (m) = Largeur nominale de l'ouverture côté opposée ébrasure (m) | ID Elément entier = ID Elément compact | Etage d'implantation | Nom de Zone = De Zone | Numéro de Zone = De la Zone numéro | Calque | Nom Elément de Bibliothèque | Structure mur | Taille L x H nominale | Taille L x H x E nominale | Altitude à Zéro du Projet (m) | Altitude à étage (m) | Superficie de surface (m2) | Volume net (m3) = Volume ouverture (m3) | Hauteur nominale seuil (m) = Hauteur seuil côté ébrasure (m) = Hauteur seuil côté opposé ébrasure (m) = Valeur Appui ou Linteau (m) | Surface ouverture côté ébrasure (m2) = Surface ouverture côté opposé ébrasure (m2) = Surface nominale de l'ouverture P/F côté ébrasure (m2) = Surface nominale de l'ouverture P/F côté opposé ébrasure (m2) = Surface nominale ouverture P/F (m2) | Volume nominal ouverture (m3) | Epaisseur de Mur (m)
Fen-029 | NIVEAU BAS GYMNASE | 2.1 | 0.4 | Fen-029 | NIVEAU BAS GYMNASE | Hall & Circulation | 010 | Murs Ext: Périphériques.Importation IFC | Fenêtre (Mur) 10 | •GYMN 10+10 0232896968 | 0,40x2,10 | 0,40x2,10x0,20 | 0 | 0 | 2.5864 | 0.025312 | 0 | 0.84 | 0.168 | 0.2 | AC_Pset_Fenêtre_(Mur)_10 - Contours Mur (0-Sans,1-Tout,2-Côté,3-Longueur): 1; Point ch.0-Non,1-2D,2-3D,3-Tous: 3; Points chauds auto. en 3D: yes; Trou reprend surface latérale de mur: no; Division de surface de trou courbée: no; Stylo ligne non coupée: Ouvertures - Général; Stylo de contour: Eléments 2D - Général; Type Hachure: Sans Trame; Stylo Hachure: Fond - Couleur 1; Stylo fond hachure: Fond - Couleur 1; Stylo châssis: Eléments 2D - Général; Stylo vitrage: Eléments 2D - Général; Stylo cadre: Eléments 2D - Général; Afficher arêtes de contour seulement en 3D: yes; Surface par défaut: Enduit - Blanc nature; Surface 1: Métal-Aluminium; Surface 2: Vitrage-Clair; Surface de châssis: Bois - Pin granuleux horizontal; Surface vitre: Transp. - Verre clair (rapide); Surface de cadre: Bois - Pin granuleux vertical; Opération IFC (ifc_optype): 0; AC_Equantity_Fenêtre_(Mur)_10 - Largeur: 1 m; Hauteur: 1.5 m; Hauteur appui à étage actuel: 1 m; Niveau inférieur: 1 m; Niveau supérieur: 0 m; Largeur cadre: 0.07 m; Epaisseur cadre: 0.05 m; Largeur châssis: 0.05 m; Epaisseur vitrage: 0.02 m; Epaisseur châssis: 0.05 m; Dépass.ouverture à droite: 0 m; Dépass.ouverture supérieur: 0 m; Dépass.ouverture inférieur: 0 m; Dépass.ouverture gauche: 0 m
Fen-005 | NIVEAU BAS GYMNASE | 2 | 1.2 | Fen-005 | NIVEAU BAS GYMNASE | Bureau Prof | 006 | 0.Importation IFC | Fenêtre (Mur) 13 | •GYMN 18+10 | 1,20x2,00 | 1,20x2,00x0,28 | 0.1 | 0.1 | 6.0876 | 0.061856 | 0.1 | 2.4 | 0.672 | 0.28 | AC_Pset_Fenêtre_(Mur)_13 - Contours Mur (0-Sans,1-Tout,2-Côté,3-Longueur): 1; Point ch.0-Non,1-2D,2-3D,3-Tous: 3; Points chauds auto. en 3D: yes; Trou reprend surface latérale de mur: no; Division de surface de trou courbée: no; Stylo ligne non coupée: Ouvertures - Général; Stylo de contour: Eléments 2D - Général; Type Hachure: Sans Trame; Stylo Hachure: Fond - Couleur 1; Stylo fond hachure: Fond - Couleur 1; Stylo châssis: Eléments 2D - Général; Stylo vitrage: Eléments 2D - Général; Stylo cadre: Eléments 2D - Général; Afficher arêtes de contour seulement en 3D: yes; Surface par défaut: Enduit - Blanc nature; Surface 1: Métal-Aluminium; Surface 2: Vitrage-Clair; Surface de châssis: Bois - Pin granuleux horizontal; Surface vitre: Transp. - Verre clair (rapide); Surface de cadre: Bois - Pin granuleux vertical; Opération IFC (ifc_optype): 0; AC_Equantity_Fenêtre_(Mur)_13 - Largeur: 1 m; Hauteur: 1.5 m; Hauteur appui à étage actuel: 1 m; Niveau inférieur: 1 m; Niveau supérieur: 0 m; Largeur cadre: 0.07 m; Epaisseur cadre: 0.05 m; Largeur châssis: 0.05 m; Epaisseur vitrage: 0.02 m; Epaisseur châssis: 0.05 m; Dépass.ouverture à droite: 0 m; Dépass.ouverture supérieur: 0 m; Dépass.ouverture inférieur: 0 m; Dépass.ouverture gauche: 0 m
Fen-006 | NIVEAU BAS GYMNASE | 2 | 1.2 | Fen-006 | NIVEAU BAS GYMNASE |  |  | 0.Importation IFC | Fenêtre (Mur) 14 | •GYMN 18+10 | 1,20x2,00 | 1,20x2,00x0,28 | 0.1 | 0.1 | 6.0876 | 0.061856 | 0.1 | 2.4 | 0.672 | 0.28 | AC_Pset_Fenêtre_(Mur)_14 - Contours Mur (0-Sans,1-Tout,2-Côté,3-Longueur): 1; Point ch.0-Non,1-2D,2-3D,3-Tous: 3; Points chauds auto. en 3D: yes; Trou reprend surface latérale de mur: no; Division de surface de trou courbée: no; Stylo ligne non coupée: Ouvertures - Général; Stylo de contour: Eléments 2D - Général; Type Hachure: Sans Trame; Stylo Hachure: Fond - Couleur 1; Stylo fond hachure: Fond - Couleur 1; Stylo châssis: Eléments 2D - Général; Stylo vitrage: Eléments 2D - Général; Stylo cadre: Eléments 2D - Général; Afficher arêtes de contour seulement en 3D: yes; Surface par défaut: Enduit - Blanc nature; Surface 1: Métal-Aluminium; Surface 2: Vitrage-Clair; Surface de châssis: Bois - Pin granuleux horizontal; Surface vitre: Transp. - Verre clair (rapide); Surface de cadre: Bois - Pin granuleux vertical; Opération IFC (ifc_optype): 0; AC_Equantity_Fenêtre_(Mur)_14 - Largeur: 1 m; Hauteur: 1.5 m; Hauteur appui à étage actuel: 1 m; Niveau inférieur: 1 m; Niveau supérieur: 0 m; Largeur cadre: 0.07 m; Epaisseur cadre: 0.05 m; Largeur châssis: 0.05 m; Epaisseur vitrage: 0.02 m; Epaisseur châssis: 0.05 m; Dépass.ouverture à droite: 0 m; Dépass.ouverture supérieur: 0 m; Dépass.ouverture inférieur: 0 m; Dépass.ouverture gauche: 0 m
Fen-007 | NIVEAU HAUT ENTRÉE | 2 | 1.2 | Fen-007 | NIVEAU HAUT ENTRÉE | Hall d'Entrée | 010 | 0.Importation IFC | Fenêtre (Mur) 13 | •GYMN 16+10 (1) | 1,20x2,00 | 1,20x2,00x0,26 | 2.85 | -0.15 | 6.0876 | 0.061856 | 0.1 | 2.4 | 0.624 | 0.26 | AC_Pset_Fenêtre_(Mur)_13 - Contours Mur (0-Sans,1-Tout,2-Côté,3-Longueur): 1; Point ch.0-Non,1-2D,2-3D,3-Tous: 3; Points chauds auto. en 3D: yes; Trou reprend surface latérale de mur: no; Division de surface de trou courbée: no; Stylo ligne non coupée: Ouvertures - Général; Stylo de contour: Eléments 2D - Général; Type Hachure: Sans Trame; Stylo Hachure: Fond - Couleur 1; Stylo fond hachure: Fond - Couleur 1; Stylo châssis: Eléments 2D - Général; Stylo vitrage: Eléments 2D - Général; Stylo cadre: Eléments 2D - Général; Afficher arêtes de contour seulement en 3D: yes; Surface par défaut: Enduit - Blanc nature; Surface 1: Métal-Aluminium; Surface 2: Vitrage-Clair; Surface de châssis: Bois - Pin granuleux horizontal; Surface vitre: Transp. - Verre clair (rapide); Surface de cadre: Bois - Pin granuleux vertical; Opération IFC (ifc_optype): 0; AC_Equantity_Fenêtre_(Mur)_13 - Largeur: 1 m; Hauteur: 1.5 m; Hauteur appui à étage actuel: 0.75 m; Niveau inférieur: 1 m; Niveau supérieur: 0 m; Largeur cadre: 0.07 m; Epaisseur cadre: 0.05 m; Largeur châssis: 0.05 m; Epaisseur vitrage: 0.02 m; Epaisseur châssis: 0.05 m; Dépass.ouverture à droite: 0 m; Dépass.ouverture supérieur: 0 m; Dépass.ouverture inférieur: 0 m; Dépass.ouverture gauche: 0 m

# IfcWindow: F Devanture 3 10 (8)
Type - OperationType: USERDEFINED; ParameterTakesPrecedence: no; Sizeable: no
Material: Sans Trame
Pset_WindowCommon - ThermalTransmittance: 0; GlazingAreaFraction: 0
ArchiCADProperties - Type: Fenêtre; Verrouillé: no; Matériau de construction / Composite / Profil / Hachure: Menuis1; Fonction structurelle: Non défini; Position: Non défini; Classification d'élement: Type ArchiCAD; Etat de rénovation: Existant; Afficher sur filtre de rénovation: Tous les filtres appropriés; Orientation: G
AC_Pset_RenovationAndPhasing - Renovation Status: Existing
ArchiCADQuantities - Epaisseur: 0.05 m
Name | In | OverallHeight (m) = ArchiCADQuantities, Hauteur (m) = Hauteur ouverture côté ébrasure (m) = Hauteur ouverture côté opposé ébrasure (m) = Hauteur nominale de l'ouverture côté ébrasure (m) = Hauteur nominale de l'ouverture côté opposée ébrasure (m) | OverallWidth (m) = ArchiCADQuantities, Largeur (m) = Largeur ouverture côté ébrasure (m) = Largeur nominale de l'ouverture côté ébrasure (m) = Largeur nominale de l'ouverture côté opposée ébrasure (m) | ID Elément entier = ID Elément compact | Etage d'implantation | Calque | Nom Elément de Bibliothèque | Structure mur | Taille L x H nominale | Taille L x H x E nominale | Altitude à Zéro du Projet (m) | Altitude à étage (m) | Superficie de surface (m2) | Volume net (m3) = Volume ouverture (m3) | Hauteur nominale seuil (m) = Hauteur seuil côté ébrasure (m) = Hauteur seuil côté opposé ébrasure (m) = Valeur Appui ou Linteau (m) | Hauteur nominale linteau (m) = Hauteur linteau côté ébrasure (m) = Hauteur linteau côté opposé ébrasure (m) | Largeur ouverture côté opposé ébrasure (m) | Surface ouverture côté ébrasure (m2) = Surface nominale de l'ouverture P/F côté ébrasure (m2) = Surface nominale de l'ouverture P/F côté opposé ébrasure (m2) = Surface nominale ouverture P/F (m2) | Surface ouverture côté opposé ébrasure (m2) | Volume nominal ouverture (m3) | Epaisseur de Mur (m)
2 x Fen-022 | NIVEAU BAS GYMNASE | 2.32 | 7.37667 | Fen-022 | NIVEAU BAS GYMNASE | Murs Ext: Périphériques.Importation IFC | Fenêtre (Mur) 2 | Acier 2556372607 | 7,38x2,32 | 7,38x2,32x0,10 | 0.1 | 0.1 | 38.2756 | 0.288844 | 0.1 | 2.42 | 7.37667 | 17.1139 | 17.1139 | 1.71139 | 0.1 | AC_Pset_Fenêtre_(Mur)_2 - Contours Mur (0-Sans,1-Tout,2-Côté,3-Longueur): 1; Point ch.0-Non,1-2D,2-3D,3-Tous: 3; Points chauds auto. en 3D: yes; Trou reprend surface latérale de mur: no; Division de surface de trou courbée: no; Stylo ligne non coupée: Ouvertures - Général; Stylo de contour: Eléments 2D - Général; Type Hachure: Sans Trame; Stylo Hachure: Fond - Couleur 1; Stylo fond hachure: Fond - Couleur 1; Stylo châssis: Eléments 2D - Général; Stylo vitrage: Eléments 2D - Général; Stylo cadre: Eléments 2D - Général; Afficher arêtes de contour seulement en 3D: yes; Surface par défaut: Enduit - Blanc nature; Surface 1: Métal-Aluminium; Surface 2: Vitrage-Clair; Surface de châssis: Bois - Pin granuleux horizontal; Surface vitre: Transp. - Verre clair (rapide); Surface de cadre: Bois - Pin granuleux vertical; Opération IFC (ifc_optype): 0; AC_Equantity_Fenêtre_(Mur)_2 - Largeur: 1 m; Hauteur: 1.5 m; Hauteur appui à étage actuel: 1 m; Niveau inférieur: 1 m; Niveau supérieur: 0 m; Largeur cadre: 0.07 m; Epaisseur cadre: 0.05 m; Largeur châssis: 0.05 m; Epaisseur vitrage: 0.02 m; Epaisseur châssis: 0.05 m; Dépass.ouverture à droite: 0 m; Dépass.ouverture supérieur: 0 m; Dépass.ouverture inférieur: 0 m; Dépass.ouverture gauche: 0 m
Fen-023 | NIVEAU BAS GYMNASE | 2.32 | 7.37667 | Fen-023 | NIVEAU BAS GYMNASE | Murs Ext: Périphériques.Importation IFC | Fenêtre (Mur) 2 | Acier 2556372607 | 7,38x2,32 | 7,38x2,32x0,10 | 0.1 | 0.1 | 38.2756 | 0.288844 | 0.1 | 2.42 | 7.37667 | 17.1139 | 17.1139 | 1.71139 | 0.1 | AC_Pset_Fenêtre_(Mur)_2 - Contours Mur (0-Sans,1-Tout,2-Côté,3-Longueur): 1; Point ch.0-Non,1-2D,2-3D,3-Tous: 3; Points chauds auto. en 3D: yes; Trou reprend surface latérale de mur: no; Division de surface de trou courbée: no; Stylo ligne non coupée: Ouvertures - Général; Stylo de contour: Eléments 2D - Général; Type Hachure: Sans Trame; Stylo Hachure: Fond - Couleur 1; Stylo fond hachure: Fond - Couleur 1; Stylo châssis: Eléments 2D - Général; Stylo vitrage: Eléments 2D - Général; Stylo cadre: Eléments 2D - Général; Afficher arêtes de contour seulement en 3D: yes; Surface par défaut: Enduit - Blanc nature; Surface 1: Métal-Aluminium; Surface 2: Vitrage-Clair; Surface de châssis: Bois - Pin granuleux horizontal; Surface vitre: Transp. - Verre clair (rapide); Surface de cadre: Bois - Pin granuleux vertical; Opération IFC (ifc_optype): 0; AC_Equantity_Fenêtre_(Mur)_2 - Largeur: 1 m; Hauteur: 1.5 m; Hauteur appui à étage actuel: 1 m; Niveau inférieur: 1 m; Niveau supérieur: 0 m; Largeur cadre: 0.07 m; Epaisseur cadre: 0.05 m; Largeur châssis: 0.05 m; Epaisseur vitrage: 0.02 m; Epaisseur châssis: 0.05 m; Dépass.ouverture à droite: 0 m; Dépass.ouverture supérieur: 0 m; Dépass.ouverture inférieur: 0 m; Dépass.ouverture gauche: 0 m
Fen-022 | NIVEAU BAS GYMNASE | 2.32 | 7.37667 | Fen-022 | NIVEAU BAS GYMNASE | Murs Ext: Périphériques.Importation IFC | Fenêtre (Mur) 3 | Acier 2556372607 | 7,38x2,32 | 7,38x2,32x0,10 | 0.1 | 0.1 | 38.27 | 0.28288 | 0.1 | 2.42 | 7.37667 | 17.1139 | 17.1139 | 1.71139 | 0.1 | AC_Pset_Fenêtre_(Mur)_3 - Contours Mur (0-Sans,1-Tout,2-Côté,3-Longueur): 1; Point ch.0-Non,1-2D,2-3D,3-Tous: 3; Points chauds auto. en 3D: yes; Trou reprend surface latérale de mur: no; Division de surface de trou courbée: no; Stylo ligne non coupée: Ouvertures - Général; Stylo de contour: Eléments 2D - Général; Type Hachure: Sans Trame; Stylo Hachure: Fond - Couleur 1; Stylo fond hachure: Fond - Couleur 1; Stylo châssis: Eléments 2D - Général; Stylo vitrage: Eléments 2D - Général; Stylo cadre: Eléments 2D - Général; Afficher arêtes de contour seulement en 3D: yes; Surface par défaut: Enduit - Blanc nature; Surface 1: Métal-Aluminium; Surface 2: Vitrage-Clair; Surface de châssis: Bois - Pin granuleux horizontal; Surface vitre: Transp. - Verre clair (rapide); Surface de cadre: Bois - Pin granuleux vertical; Opération IFC (ifc_optype): 0; AC_Equantity_Fenêtre_(Mur)_3 - Largeur: 1 m; Hauteur: 1.5 m; Hauteur appui à étage actuel: 1 m; Niveau inférieur: 1 m; Niveau supérieur: 0 m; Largeur cadre: 0.07 m; Epaisseur cadre: 0.05 m; Largeur châssis: 0.05 m; Epaisseur vitrage: 0.02 m; Epaisseur châssis: 0.05 m; Dépass.ouverture à droite: 0 m; Dépass.ouverture supérieur: 0 m; Dépass.ouverture inférieur: 0 m; Dépass.ouverture gauche: 0 m
Fen-023 | NIVEAU BAS GYMNASE | 2.32 | 7.60667 | Fen-023 | NIVEAU BAS GYMNASE | Murs Ext: Périphériques.Importation IFC | Fenêtre (Mur) 4 | Acier 2556372607 | 7,61x2,32 | 7,61x2,32x0,10 | 0.1 | 0.1 | 39.3043 | 0.301743 | 0.1 | 2.42 | 7.50667 | 17.6475 | 17.4155 | 1.76475 | 0.1 | AC_Pset_Fenêtre_(Mur)_4 - Contours Mur (0-Sans,1-Tout,2-Côté,3-Longueur): 1; Point ch.0-Non,1-2D,2-3D,3-Tous: 3; Points chauds auto. en 3D: yes; Trou reprend surface latérale de mur: no; Division de surface de trou courbée: no; Stylo ligne non coupée: Ouvertures - Général; Stylo de contour: Eléments 2D - Général; Type Hachure: Sans Trame; Stylo Hachure: Fond - Couleur 1; Stylo fond hachure: Fond - Couleur 1; Stylo châssis: Eléments 2D - Général; Stylo vitrage: Eléments 2D - Général; Stylo cadre: Eléments 2D - Général; Afficher arêtes de contour seulement en 3D: yes; Surface par défaut: Enduit - Blanc nature; Surface 1: Métal-Aluminium; Surface 2: Vitrage-Clair; Surface de châssis: Bois - Pin granuleux horizontal; Surface vitre: Transp. - Verre clair (rapide); Surface de cadre: Bois - Pin granuleux vertical; Opération IFC (ifc_optype): 0; AC_Equantity_Fenêtre_(Mur)_4 - Largeur: 1 m; Hauteur: 1.5 m; Hauteur appui à étage actuel: 1 m; Niveau inférieur: 1 m; Niveau supérieur: 0 m; Largeur cadre: 0.07 m; Epaisseur cadre: 0.05 m; Largeur châssis: 0.05 m; Epaisseur vitrage: 0.02 m; Epaisseur châssis: 0.05 m; Dépass.ouverture à droite: 0 m; Dépass.ouverture supérieur: 0 m; Dépass.ouverture inférieur: 0 m; Dépass.ouverture gauche: 0 m
Fen-025 | NIVEAU BAS GYMNASE | 2.32 | 7.60667 | Fen-025 | NIVEAU BAS GYMNASE | Murs Ext: Périphériques.Importation IFC | Fenêtre (Mur) 5 | Acier 2556372607 | 7,61x2,32 | 7,61x2,32x0,10 | 0.1 | 0.1 | 39.3043 | 0.301743 | 0.1 | 2.42 | 7.50667 | 17.6475 | 17.4155 | 1.76475 | 0.1 | AC_Pset_Fenêtre_(Mur)_5 - Contours Mur (0-Sans,1-Tout,2-Côté,3-Longueur): 1; Point ch.0-Non,1-2D,2-3D,3-Tous: 3; Points chauds auto. en 3D: yes; Trou reprend surface latérale de mur: no; Division de surface de trou courbée: no; Stylo ligne non coupée: Ouvertures - Général; Stylo de contour: Eléments 2D - Général; Type Hachure: Sans Trame; Stylo Hachure: Fond - Couleur 1; Stylo fond hachure: Fond - Couleur 1; Stylo châssis: Eléments 2D - Général; Stylo vitrage: Eléments 2D - Général; Stylo cadre: Eléments 2D - Général; Afficher arêtes de contour seulement en 3D: yes; Surface par défaut: Enduit - Blanc nature; Surface 1: Métal-Aluminium; Surface 2: Vitrage-Clair; Surface de châssis: Bois - Pin granuleux horizontal; Surface vitre: Transp. - Verre clair (rapide); Surface de cadre: Bois - Pin granuleux vertical; Opération IFC (ifc_optype): 0; AC_Equantity_Fenêtre_(Mur)_5 - Largeur: 1 m; Hauteur: 1.5 m; Hauteur appui à étage actuel: 1 m; Niveau inférieur: 1 m; Niveau supérieur: 0 m; Largeur cadre: 0.07 m; Epaisseur cadre: 0.05 m; Largeur châssis: 0.05 m; Epaisseur vitrage: 0.02 m; Epaisseur châssis: 0.05 m; Dépass.ouverture à droite: 0 m; Dépass.ouverture supérieur: 0 m; Dépass.ouverture inférieur: 0 m; Dépass.ouverture gauche: 0 m
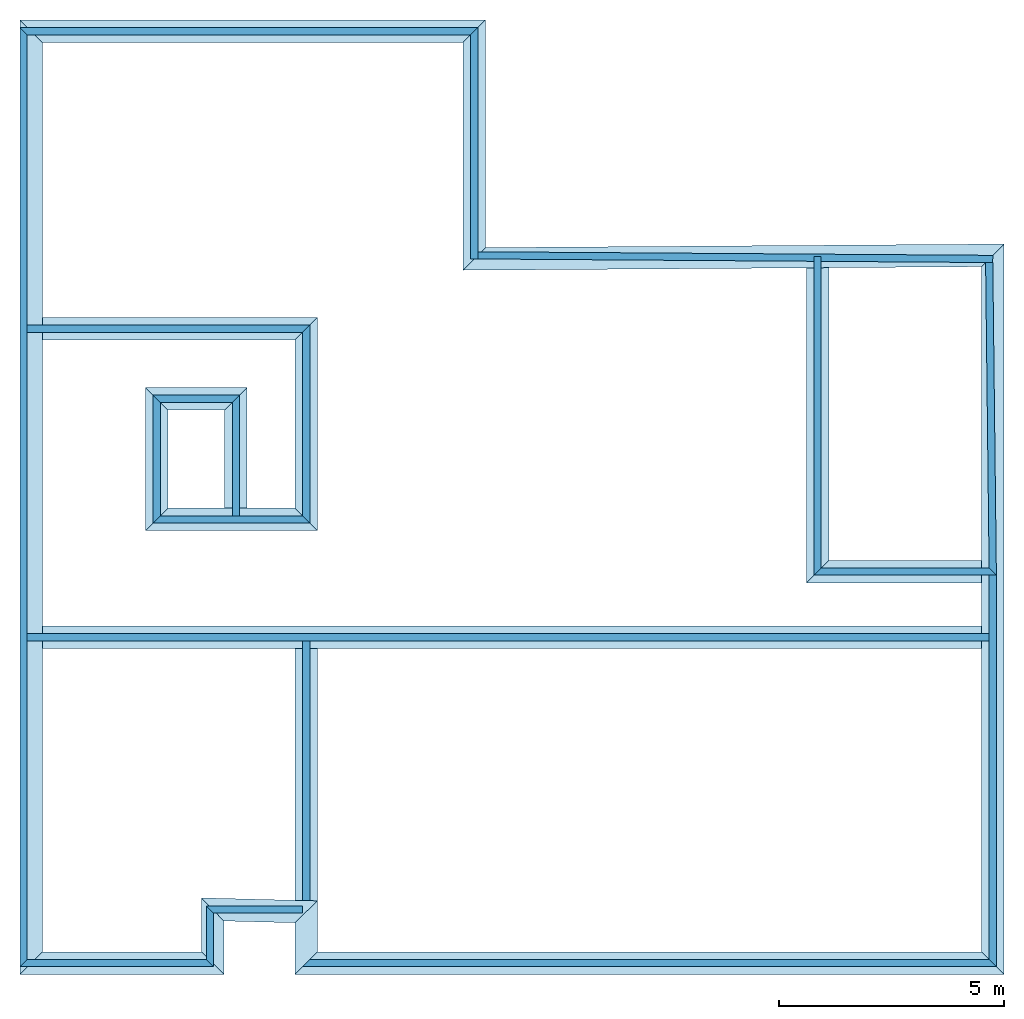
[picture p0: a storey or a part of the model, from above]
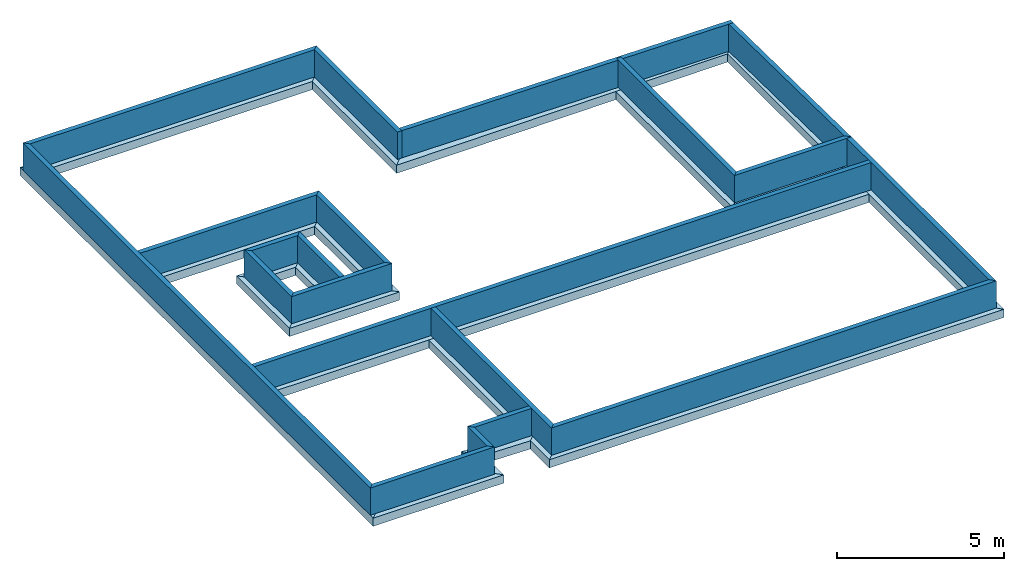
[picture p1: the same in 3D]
Properties of the parts of a building model (IFC2X3), part 6 of 6

# IfcWindow: F Devanture 3 10 (8)
Name | In | OverallHeight (m) = ArchiCADQuantities, Hauteur (m) = Hauteur ouverture côté ébrasure (m) = Hauteur ouverture côté opposé ébrasure (m) = Hauteur nominale de l'ouverture côté ébrasure (m) = Hauteur nominale de l'ouverture côté opposée ébrasure (m) | OverallWidth (m) = ArchiCADQuantities, Largeur (m) = Largeur ouverture côté ébrasure (m) = Largeur nominale de l'ouverture côté ébrasure (m) = Largeur nominale de l'ouverture côté opposée ébrasure (m) | ID Elément entier = ID Elément compact | Etage d'implantation | Calque | Nom Elément de Bibliothèque | Structure mur | Taille L x H nominale | Taille L x H x E nominale | Altitude à Zéro du Projet (m) | Altitude à étage (m) | Superficie de surface (m2) | Volume net (m3) = Volume ouverture (m3) | Hauteur nominale seuil (m) = Hauteur seuil côté ébrasure (m) = Hauteur seuil côté opposé ébrasure (m) = Valeur Appui ou Linteau (m) | Hauteur nominale linteau (m) = Hauteur linteau côté ébrasure (m) = Hauteur linteau côté opposé ébrasure (m) | Largeur ouverture côté opposé ébrasure (m) | Surface ouverture côté ébrasure (m2) = Surface nominale de l'ouverture P/F côté ébrasure (m2) = Surface nominale de l'ouverture P/F côté opposé ébrasure (m2) = Surface nominale ouverture P/F (m2) | Surface ouverture côté opposé ébrasure (m2) | Volume nominal ouverture (m3) | Epaisseur de Mur (m)
Fen-023 | NIVEAU BAS GYMNASE | 2.32 | 4.25697 | Fen-023 | NIVEAU BAS GYMNASE | Murs Ext: Périphériques.Importation IFC | Fenêtre (Mur) 16 | Acier 2556372607 | 4,26x2,32 | 4,26x2,32x0,10 | 0.1 | 0.1 | 22.4787 | 0.169437 | 0.1 | 2.42 | 4.25697 | 9.87616 | 9.87616 | 0.987616 | 0.1 | AC_Pset_Fenêtre_(Mur)_16 - Contours Mur (0-Sans,1-Tout,2-Côté,3-Longueur): 1; Point ch.0-Non,1-2D,2-3D,3-Tous: 3; Points chauds auto. en 3D: yes; Trou reprend surface latérale de mur: no; Division de surface de trou courbée: no; Stylo ligne non coupée: Ouvertures - Général; Stylo de contour: Eléments 2D - Général; Type Hachure: Sans Trame; Stylo Hachure: Fond - Couleur 1; Stylo fond hachure: Fond - Couleur 1; Stylo châssis: Eléments 2D - Général; Stylo vitrage: Eléments 2D - Général; Stylo cadre: Eléments 2D - Général; Afficher arêtes de contour seulement en 3D: yes; Surface par défaut: Enduit - Blanc nature; Surface 1: Métal-Aluminium; Surface 2: Vitrage-Clair; Surface de châssis: Bois - Pin granuleux horizontal; Surface vitre: Transp. - Verre clair (rapide); Surface de cadre: Bois - Pin granuleux vertical; Opération IFC (ifc_optype): 0; AC_Equantity_Fenêtre_(Mur)_16 - Largeur: 1 m; Hauteur: 1.5 m; Hauteur appui à étage actuel: 1 m; Niveau inférieur: 1 m; Niveau supérieur: 0 m; Largeur cadre: 0.07 m; Epaisseur cadre: 0.05 m; Largeur châssis: 0.05 m; Epaisseur vitrage: 0.02 m; Epaisseur châssis: 0.05 m; Dépass.ouverture à droite: 0 m; Dépass.ouverture supérieur: 0 m; Dépass.ouverture inférieur: 0 m; Dépass.ouverture gauche: 0 m
Fen-001 | NIVEAU HAUT ENTRÉE | 2.28865 | 0.65 | Fen-001 | NIVEAU HAUT ENTRÉE | 0.Importation IFC | Fenêtre (Mur) 32 | •GYMN 16+10 | 0,65x2,29 | 0,65x2,29x0,26 | 3.63508 | 0.635079 | 3.95139 | 0.0352737 | 0.665079 | 2.95373 | 0.65 | 1.48762 | 1.48762 | 0.386782 | 0.26 | AC_Pset_Fenêtre_(Mur)_32 - Contours Mur (0-Sans,1-Tout,2-Côté,3-Longueur): 1; Point ch.0-Non,1-2D,2-3D,3-Tous: 3; Points chauds auto. en 3D: yes; Trou reprend surface latérale de mur: no; Division de surface de trou courbée: no; Stylo ligne non coupée: Ouvertures - Général; Stylo de contour: Eléments 2D - Général; Type Hachure: Sans Trame; Stylo Hachure: Fond - Couleur 1; Stylo fond hachure: Fond - Couleur 1; Stylo châssis: Eléments 2D - Général; Stylo vitrage: Eléments 2D - Général; Stylo cadre: Eléments 2D - Général; Afficher arêtes de contour seulement en 3D: yes; Surface par défaut: Enduit - Blanc nature; Surface 1: •MENUIS H CADRE; Surface 2: Vitrage-Clair; Surface de châssis: Bois - Pin granuleux horizontal; Surface vitre: Transp. - Verre clair (rapide); Surface de cadre: Bois - Pin granuleux vertical; Opération IFC (ifc_optype): 0; AC_Equantity_Fenêtre_(Mur)_32 - Largeur: 1 m; Hauteur: 1.5 m; Hauteur appui à étage actuel: 0.97 m; Niveau inférieur: 1 m; Niveau supérieur: 0 m; Largeur cadre: 0.07 m; Epaisseur cadre: 0.05 m; Largeur châssis: 0.05 m; Epaisseur vitrage: 0.02 m; Epaisseur châssis: 0.05 m; Dépass.ouverture à droite: 0 m; Dépass.ouverture supérieur: 0 m; Dépass.ouverture inférieur: 0 m; Dépass.ouverture gauche: 0 m

# IfcWindow: Fen bascule 1 10 (2)
Type - OperationType: SINGLE_PANEL; ParameterTakesPrecedence: no; Sizeable: no
Type - Propriétés Doublure Fenêtre - LiningDepth: 0.03 m; LiningThickness: 0.03 m
Type - Propriétés Panneau Fenêtre - Panneau1 - PanelPosition: MIDDLE; FrameDepth: 0.03 m; FrameThickness: 0.03 m
Material: Sans Trame
Pset_WindowCommon - ThermalTransmittance: 0; GlazingAreaFraction: 0
Pset_ManufacturerOccurrence - SerialNumber: Sans
ArchiCADProperties - ID Elément entier: Fen-027; ID Elément compact: Fen-027; Type: Fenêtre; Verrouillé: no; Matériau de construction / Composite / Profil / Hachure: Menuis1; Fonction structurelle: Non défini; Position: Non défini; Classification d'élement: Type ArchiCAD; Etat de rénovation: Existant; Afficher sur filtre de rénovation: Tous les filtres appropriés; Orientation: G
AC_Pset_RenovationAndPhasing - Renovation Status: Existing
ArchiCADQuantities - Epaisseur: 0.05 m
Name | In | OverallHeight (m) = ArchiCADQuantities, Hauteur (m) = Hauteur ouverture côté ébrasure (m) = Hauteur ouverture côté opposé ébrasure (m) = Hauteur nominale de l'ouverture côté ébrasure (m) = Hauteur nominale de l'ouverture côté opposée ébrasure (m) | OverallWidth (m) = ArchiCADQuantities, Largeur (m) = Largeur ouverture côté ébrasure (m) = Largeur ouverture côté opposé ébrasure (m) = Largeur nominale de l'ouverture côté ébrasure (m) = Largeur nominale de l'ouverture côté opposée ébrasure (m) | Etage d'implantation | Nom de Zone | Numéro de Zone = De la Zone numéro | Calque | Nom Elément de Bibliothèque | De Zone | Structure mur | Taille L x H nominale | Taille L x H x E nominale | Altitude à Zéro du Projet (m) | Altitude à étage (m) | Superficie de surface (m2) | Volume net (m3) = Volume ouverture (m3) | Hauteur nominale seuil (m) = Hauteur seuil côté ébrasure (m) = Hauteur seuil côté opposé ébrasure (m) = Valeur Appui ou Linteau (m) | Hauteur nominale linteau (m) = Hauteur linteau côté ébrasure (m) = Hauteur linteau côté opposé ébrasure (m) | Surface ouverture côté ébrasure (m2) = Surface ouverture côté opposé ébrasure (m2) = Surface nominale de l'ouverture P/F côté ébrasure (m2) = Surface nominale de l'ouverture P/F côté opposé ébrasure (m2) = Surface nominale ouverture P/F (m2) | Volume nominal ouverture (m3) | Epaisseur de Mur (m)
Fen-027 | NIVEAU BAS GYMNASE | 0.45 | 2 | NIVEAU BAS GYMNASE | Sanit Vest 6 | 010 | Murs Ext: Périphériques.Importation IFC | Fenêtre (Mur) 11 | Hall & Circulation | Hachure solide* 3962059836 | 2,00x0,45 | 2,00x0,45x0,10 | 2.03 | 2.03 | 2.5224 | 0.007434 | 2.03 | 2.48 | 0.9 | 0.09 | 0.1 | AC_Pset_Fenêtre_(Mur)_11 - Contours Mur (0-Sans,1-Tout,2-Côté,3-Longueur): 1; Point ch.0-Non,1-2D,2-3D,3-Tous: 3; Points chauds auto. en 3D: yes; Trou reprend surface latérale de mur: no; Division de surface de trou courbée: no; Stylo ligne non coupée: Ouvertures - Général; Stylo de contour: Eléments 2D - Général; Type Hachure: Sans Trame; Stylo Hachure: Fond - Couleur 1; Stylo fond hachure: Fond - Couleur 1; Stylo châssis: Eléments 2D - Général; Stylo vitrage: Eléments 2D - Général; Stylo cadre: Eléments 2D - Général; Afficher arêtes de contour seulement en 3D: yes; Surface par défaut: Enduit - Blanc nature; Surface 1: •MENUIS H CADRE; Surface 2: •MENUIS H CHASSIS; Surface 3: Vitrage-Bleu; Surface de châssis: Bois - Pin granuleux horizontal; Surface vitre: Transp. - Verre clair (rapide); Surface de cadre: Bois - Pin granuleux vertical; Opération IFC (ifc_optype): 1; AC_Equantity_Fenêtre_(Mur)_11 - Largeur: 1 m; Hauteur: 1.5 m; Hauteur appui à étage actuel: 1 m; Niveau inférieur: 1 m; Niveau supérieur: 0 m; Largeur cadre: 0.07 m; Epaisseur cadre: 0.05 m; Largeur châssis: 0.05 m; Epaisseur vitrage: 0.02 m; Epaisseur châssis: 0.05 m; Dépass.ouverture à droite: 0 m; Dépass.ouverture supérieur: 0 m; Dépass.ouverture inférieur: 0 m; Dépass.ouverture gauche: 0 m
Fen-027 | NIVEAU HAUT ENTRÉE | 0.7 | 3 | NIVEAU HAUT ENTRÉE | Salle de Sport de Combat | 006 | 0.Importation IFC | Fenêtre (Mur) 19 | Salle de Sport de Combat | •GYMN 16+10 | 3,00x0,70 | 3,00x0,70x0,26 | 4.85 | 1.85 | 5.2974 | 0.0113715 | 2.1 | 2.8 | 2.1 | 0.546 | 0.26 | AC_Pset_Fenêtre_(Mur)_19 - Contours Mur (0-Sans,1-Tout,2-Côté,3-Longueur): 1; Point ch.0-Non,1-2D,2-3D,3-Tous: 3; Points chauds auto. en 3D: yes; Trou reprend surface latérale de mur: no; Division de surface de trou courbée: no; Stylo ligne non coupée: Ouvertures - Général; Stylo de contour: Eléments 2D - Général; Type Hachure: Sans Trame; Stylo Hachure: Fond - Couleur 1; Stylo fond hachure: Fond - Couleur 1; Stylo châssis: Eléments 2D - Général; Stylo vitrage: Eléments 2D - Général; Stylo cadre: Eléments 2D - Général; Afficher arêtes de contour seulement en 3D: yes; Surface par défaut: Enduit - Blanc nature; Surface 1: •MENUIS H CADRE; Surface 2: •MENUIS H CHASSIS; Surface 3: Vitrage-Bleu; Surface de châssis: Bois - Pin granuleux horizontal; Surface vitre: Transp. - Verre clair (rapide); Surface de cadre: Bois - Pin granuleux vertical; Opération IFC (ifc_optype): 1; AC_Equantity_Fenêtre_(Mur)_19 - Largeur: 1 m; Hauteur: 1.5 m; Hauteur appui à étage actuel: 0.75 m; Niveau inférieur: 1 m; Niveau supérieur: 0 m; Largeur cadre: 0.07 m; Epaisseur cadre: 0.05 m; Largeur châssis: 0.05 m; Epaisseur vitrage: 0.02 m; Epaisseur châssis: 0.05 m; Dépass.ouverture à droite: 0 m; Dépass.ouverture supérieur: 0 m; Dépass.ouverture inférieur: 0 m; Dépass.ouverture gauche: 0 m

# IfcWindow: Fen bascule 1 10 (2)
In: NIVEAU HAUT ENTRÉE
Type - OperationType: SINGLE_PANEL; ParameterTakesPrecedence: no; Sizeable: no
Type - Propriétés Doublure Fenêtre - LiningDepth: 0.04 m; LiningThickness: 0.04 m
Type - Propriétés Panneau Fenêtre - Panneau1 - PanelPosition: MIDDLE; FrameDepth: 0.03 m; FrameThickness: 0.03 m
OverallHeight: 0.7 m; OverallWidth: 3 m; Material: Sans Trame
Pset_WindowCommon - ThermalTransmittance: 0; GlazingAreaFraction: 0
Pset_ManufacturerOccurrence - SerialNumber: Sans
ArchiCADProperties - ID Elément entier: Fen-027; ID Elément compact: Fen-027; Etage d'implantation: NIVEAU HAUT ENTRÉE; Nom de Zone: Salle de Sport de Combat; Numéro de Zone: 006; Calque: 0.Importation IFC; Type: Fenêtre; Verrouillé: no; Matériau de construction / Composite / Profil / Hachure: Menuis1; Fonction structurelle: Non défini; Position: Non défini; Classification d'élement: Type ArchiCAD; Etat de rénovation: Existant; Afficher sur filtre de rénovation: Tous les filtres appropriés; De Zone: Salle de Sport de Combat; Orientation: G; De la Zone numéro: 006; Structure mur: •GYMN 16+10; Taille L x H nominale: 3,00x0,70; Taille L x H x E nominale: 3,00x0,70x0,26
AC_Pset_RenovationAndPhasing - Renovation Status: Existing
ArchiCADQuantities - Hauteur: 0.7 m; Superficie de surface: 5.5128 m2; Volume net: 0.015844 m3; Largeur: 3 m; Epaisseur: 0.05 m; Largeur ouverture côté ébrasure: 3 m; Largeur ouverture côté opposé ébrasure: 3 m; Hauteur ouverture côté ébrasure: 0.7 m; Hauteur ouverture côté opposé ébrasure: 0.7 m; Surface ouverture côté ébrasure: 2.1 m2; Surface ouverture côté opposé ébrasure: 2.1 m2; Largeur nominale de l'ouverture côté ébrasure: 3 m; Largeur nominale de l'ouverture côté opposée ébrasure: 3 m; Hauteur nominale de l'ouverture côté ébrasure: 0.7 m; Hauteur nominale de l'ouverture côté opposée ébrasure: 0.7 m; Surface nominale de l'ouverture P/F côté ébrasure: 2.1 m2; Surface nominale de l'ouverture P/F côté opposé ébrasure: 2.1 m2; Volume ouverture: 0.015844 m3; Surface nominale ouverture P/F: 2.1 m2; Volume nominal ouverture: 0.546 m3; Epaisseur de Mur: 0.26 m
Name | Nom Elément de Bibliothèque | Altitude à Zéro du Projet (m) | Altitude à étage (m) | Hauteur nominale seuil (m) = Hauteur seuil côté ébrasure (m) = Hauteur seuil côté opposé ébrasure (m) = Valeur Appui ou Linteau (m) | Hauteur nominale linteau (m) = Hauteur linteau côté ébrasure (m) = Hauteur linteau côté opposé ébrasure (m)
Fen-027 | Fenêtre (Mur) 20 | 4.15 | 1.15 | 1.4 | 2.1 | AC_Pset_Fenêtre_(Mur)_20 - Contours Mur (0-Sans,1-Tout,2-Côté,3-Longueur): 1; Point ch.0-Non,1-2D,2-3D,3-Tous: 3; Points chauds auto. en 3D: yes; Trou reprend surface latérale de mur: no; Division de surface de trou courbée: no; Stylo ligne non coupée: Ouvertures - Général; Stylo de contour: Eléments 2D - Général; Type Hachure: Sans Trame; Stylo Hachure: Fond - Couleur 1; Stylo fond hachure: Fond - Couleur 1; Stylo châssis: Eléments 2D - Général; Stylo vitrage: Eléments 2D - Général; Stylo cadre: Eléments 2D - Général; Afficher arêtes de contour seulement en 3D: yes; Surface par défaut: Enduit - Blanc nature; Surface 1: •MENUIS H CADRE; Surface 2: •MENUIS H CHASSIS; Surface 3: Vitrage-Bleu; Surface de châssis: Bois - Pin granuleux horizontal; Surface vitre: Transp. - Verre clair (rapide); Surface de cadre: Bois - Pin granuleux vertical; Opération IFC (ifc_optype): 1; AC_Equantity_Fenêtre_(Mur)_20 - Largeur: 1 m; Hauteur: 1.5 m; Hauteur appui à étage actuel: 0.75 m; Niveau inférieur: 1 m; Niveau supérieur: 0 m; Largeur cadre: 0.07 m; Epaisseur cadre: 0.05 m; Largeur châssis: 0.05 m; Epaisseur vitrage: 0.02 m; Epaisseur châssis: 0.05 m; Dépass.ouverture à droite: 0 m; Dépass.ouverture supérieur: 0 m; Dépass.ouverture inférieur: 0 m; Dépass.ouverture gauche: 0 m
Fen-027 | Fenêtre (Mur) 21 | 4.85 | 1.85 | 2.1 | 2.8 | AC_Pset_Fenêtre_(Mur)_21 - Contours Mur (0-Sans,1-Tout,2-Côté,3-Longueur): 1; Point ch.0-Non,1-2D,2-3D,3-Tous: 3; Points chauds auto. en 3D: yes; Trou reprend surface latérale de mur: no; Division de surface de trou courbée: no; Stylo ligne non coupée: Ouvertures - Général; Stylo de contour: Eléments 2D - Général; Type Hachure: Sans Trame; Stylo Hachure: Fond - Couleur 1; Stylo fond hachure: Fond - Couleur 1; Stylo châssis: Eléments 2D - Général; Stylo vitrage: Eléments 2D - Général; Stylo cadre: Eléments 2D - Général; Afficher arêtes de contour seulement en 3D: yes; Surface par défaut: Enduit - Blanc nature; Surface 1: •MENUIS H CADRE; Surface 2: •MENUIS H CHASSIS; Surface 3: Vitrage-Bleu; Surface de châssis: Bois - Pin granuleux horizontal; Surface vitre: Transp. - Verre clair (rapide); Surface de cadre: Bois - Pin granuleux vertical; Opération IFC (ifc_optype): 1; AC_Equantity_Fenêtre_(Mur)_21 - Largeur: 1 m; Hauteur: 1.5 m; Hauteur appui à étage actuel: 0.75 m; Niveau inférieur: 1 m; Niveau supérieur: 0 m; Largeur cadre: 0.07 m; Epaisseur cadre: 0.05 m; Largeur châssis: 0.05 m; Epaisseur vitrage: 0.02 m; Epaisseur châssis: 0.05 m; Dépass.ouverture à droite: 0 m; Dépass.ouverture supérieur: 0 m; Dépass.ouverture inférieur: 0 m; Dépass.ouverture gauche: 0 m

# IfcWindow: Fen bascule 1 10 (17)
Type - OperationType: SINGLE_PANEL; ParameterTakesPrecedence: no; Sizeable: no
Type - Propriétés Doublure Fenêtre - LiningDepth: 0.04 m; LiningThickness: 0.04 m
Type - Propriétés Panneau Fenêtre - Panneau1 - PanelPosition: MIDDLE; FrameDepth: 0.04 m; FrameThickness: 0.04 m
Material: Sans Trame
Pset_WindowCommon - ThermalTransmittance: 0; GlazingAreaFraction: 0
Pset_ManufacturerOccurrence - SerialNumber: Sans
ArchiCADProperties - Type: Fenêtre; Verrouillé: no; Matériau de construction / Composite / Profil / Hachure: Menuis1; Fonction structurelle: Non défini; Position: Non défini; Classification d'élement: Type ArchiCAD; Etat de rénovation: Existant; Afficher sur filtre de rénovation: Tous les filtres appropriés; Orientation: G
AC_Pset_RenovationAndPhasing - Renovation Status: Existing
ArchiCADQuantities - Epaisseur: 0.05 m
Name | In | OverallHeight (m) = ArchiCADQuantities, Hauteur (m) = Hauteur ouverture côté ébrasure (m) = Hauteur ouverture côté opposé ébrasure (m) = Hauteur nominale de l'ouverture côté ébrasure (m) = Hauteur nominale de l'ouverture côté opposée ébrasure (m) | OverallWidth (m) = ArchiCADQuantities, Largeur (m) = Largeur ouverture côté ébrasure (m) = Largeur ouverture côté opposé ébrasure (m) = Largeur nominale de l'ouverture côté ébrasure (m) = Largeur nominale de l'ouverture côté opposée ébrasure (m) | ID Elément entier = ID Elément compact | Etage d'implantation | Calque | Nom Elément de Bibliothèque | Structure mur | Taille L x H nominale | Taille L x H x E nominale | Altitude à Zéro du Projet (m) | Altitude à étage (m) | Superficie de surface (m2) | Volume net (m3) = Volume ouverture (m3) | Hauteur nominale seuil (m) = Hauteur seuil côté ébrasure (m) = Hauteur seuil côté opposé ébrasure (m) = Valeur Appui ou Linteau (m) | Hauteur nominale linteau (m) = Hauteur linteau côté ébrasure (m) = Hauteur linteau côté opposé ébrasure (m) | Surface ouverture côté ébrasure (m2) = Surface ouverture côté opposé ébrasure (m2) = Surface nominale de l'ouverture P/F côté ébrasure (m2) = Surface nominale de l'ouverture P/F côté opposé ébrasure (m2) = Surface nominale ouverture P/F (m2) | Volume nominal ouverture (m3) | Epaisseur de Mur (m)
Fen-028 | NIVEAU BAS GYMNASE | 0.7 | 3 | Fen-028 | NIVEAU BAS GYMNASE | 0.Importation IFC | Fenêtre (Mur) 8 | •GYMN 16+10 (1) | 3,00x0,70 | 3,00x0,70x0,26 | 1.65 | 1.65 | 5.6576 | 0.020048 | 1.85 | 2.55 | 2.1 | 0.546 | 0.26 | AC_Pset_Fenêtre_(Mur)_8 - Contours Mur (0-Sans,1-Tout,2-Côté,3-Longueur): 1; Point ch.0-Non,1-2D,2-3D,3-Tous: 3; Points chauds auto. en 3D: yes; Trou reprend surface latérale de mur: no; Division de surface de trou courbée: no; Stylo ligne non coupée: Ouvertures - Général; Stylo de contour: Eléments 2D - Général; Type Hachure: Sans Trame; Stylo Hachure: Fond - Couleur 1; Stylo fond hachure: Fond - Couleur 1; Stylo châssis: Eléments 2D - Général; Stylo vitrage: Eléments 2D - Général; Stylo cadre: Eléments 2D - Général; Afficher arêtes de contour seulement en 3D: yes; Surface par défaut: Enduit - Blanc nature; Surface 1: •MENUIS H CADRE; Surface 2: •MENUIS H CHASSIS; Surface 3: Vitrage-Bleu; Surface de châssis: Bois - Pin granuleux horizontal; Surface vitre: Transp. - Verre clair (rapide); Surface de cadre: Bois - Pin granuleux vertical; Opération IFC (ifc_optype): 1; AC_Equantity_Fenêtre_(Mur)_8 - Largeur: 1 m; Hauteur: 1.5 m; Hauteur appui à étage actuel: 1.65 m; Niveau inférieur: 1 m; Niveau supérieur: 0 m; Largeur cadre: 0.07 m; Epaisseur cadre: 0.05 m; Largeur châssis: 0.05 m; Epaisseur vitrage: 0.02 m; Epaisseur châssis: 0.05 m; Dépass.ouverture à droite: 0 m; Dépass.ouverture supérieur: 0 m; Dépass.ouverture inférieur: 0 m; Dépass.ouverture gauche: 0 m
5 x Fen-028 | NIVEAU HAUT ENTRÉE | 1.4057 | 3.4 | Fen-028 | NIVEAU HAUT ENTRÉE | Murs Ext: Périphériques.Importation IFC | Fenêtre (Mur) 29 | •GYMN PANNEAU 1 0232896968 | 3,40x1,41 | 3,40x1,41x0,24 | 4.46 | 1.46 | 11.4587 | 0.0262399 | 2.00018e-12 | 1.4057 | 4.77939 | 1.14705 | 0.24 | AC_Pset_Fenêtre_(Mur)_29 - Contours Mur (0-Sans,1-Tout,2-Côté,3-Longueur): 1; Point ch.0-Non,1-2D,2-3D,3-Tous: 3; Points chauds auto. en 3D: yes; Trou reprend surface latérale de mur: no; Division de surface de trou courbée: no; Stylo ligne non coupée: Ouvertures - Général; Stylo de contour: Eléments 2D - Général; Type Hachure: Sans Trame; Stylo Hachure: Fond - Couleur 1; Stylo fond hachure: Fond - Couleur 1; Stylo châssis: Eléments 2D - Général; Stylo vitrage: Eléments 2D - Général; Stylo cadre: Eléments 2D - Général; Afficher arêtes de contour seulement en 3D: yes; Surface par défaut: Enduit - Blanc nature; Surface 1: •MENUIS H CADRE; Surface 2: •MENUIS H CHASSIS; Surface 3: Vitrage-Bleu; Surface de châssis: Bois - Pin granuleux horizontal; Surface vitre: Transp. - Verre clair (rapide); Surface de cadre: Bois - Pin granuleux vertical; Opération IFC (ifc_optype): 1; AC_Equantity_Fenêtre_(Mur)_29 - Largeur: 1 m; Hauteur: 1.5 m; Hauteur appui à étage actuel: 2.46 m; Niveau inférieur: 1 m; Niveau supérieur: 0 m; Largeur cadre: 0.07 m; Epaisseur cadre: 0.05 m; Largeur châssis: 0.05 m; Epaisseur vitrage: 0.02 m; Epaisseur châssis: 0.05 m; Dépass.ouverture à droite: 0 m; Dépass.ouverture supérieur: 0 m; Dépass.ouverture inférieur: 0 m; Dépass.ouverture gauche: 0 m
Fen-027 | NIVEAU HAUT ENTRÉE | 0.7 | 2.6 | Fen-027 | NIVEAU HAUT ENTRÉE | 0.Importation IFC | Fenêtre (Mur) 17 | •GYMN 16+10 (1) | 2,60x0,70 | 2,60x0,70x0,26 | 4.85 | 1.85 | 4.9376 | 0.017808 | 2.25 | 2.95 | 1.82 | 0.4732 | 0.26 | ArchiCADProperties - Nom de Zone: Salle de Sport de Combat; Numéro de Zone: 006; De Zone: Salle de Sport de Combat; De la Zone numéro: 006; AC_Pset_Fenêtre_(Mur)_17 - Contours Mur (0-Sans,1-Tout,2-Côté,3-Longueur): 1; Point ch.0-Non,1-2D,2-3D,3-Tous: 3; Points chauds auto. en 3D: yes; Trou reprend surface latérale de mur: no; Division de surface de trou courbée: no; Stylo ligne non coupée: Ouvertures - Général; Stylo de contour: Eléments 2D - Général; Type Hachure: Sans Trame; Stylo Hachure: Fond - Couleur 1; Stylo fond hachure: Fond - Couleur 1; Stylo châssis: Eléments 2D - Général; Stylo vitrage: Eléments 2D - Général; Stylo cadre: Eléments 2D - Général; Afficher arêtes de contour seulement en 3D: yes; Surface par défaut: Enduit - Blanc nature; Surface 1: •MENUIS H CADRE; Surface 2: •MENUIS H CHASSIS; Surface 3: Vitrage-Bleu; Surface de châssis: Bois - Pin granuleux horizontal; Surface vitre: Transp. - Verre clair (rapide); Surface de cadre: Bois - Pin granuleux vertical; Opération IFC (ifc_optype): 1; AC_Equantity_Fenêtre_(Mur)_17 - Largeur: 1 m; Hauteur: 1.5 m; Hauteur appui à étage actuel: 0.6 m; Niveau inférieur: 1 m; Niveau supérieur: 0 m; Largeur cadre: 0.07 m; Epaisseur cadre: 0.05 m; Largeur châssis: 0.05 m; Epaisseur vitrage: 0.02 m; Epaisseur châssis: 0.05 m; Dépass.ouverture à droite: 0 m; Dépass.ouverture supérieur: 0 m; Dépass.ouverture inférieur: 0 m; Dépass.ouverture gauche: 0 m
Fen-027 | NIVEAU HAUT ENTRÉE | 0.7 | 2.8 | Fen-027 | NIVEAU HAUT ENTRÉE | 0.Importation IFC | Fenêtre (Mur) 18 | •GYMN 16+10 (1) | 2,80x0,70 | 2,80x0,70x0,26 | 4.15 | 1.15 | 5.2976 | 0.018928 | 1.55 | 2.25 | 1.96 | 0.5096 | 0.26 | ArchiCADProperties - Nom de Zone: Salle de Sport de Combat; Numéro de Zone: 006; De Zone: Salle de Sport de Combat; De la Zone numéro: 006; AC_Pset_Fenêtre_(Mur)_18 - Contours Mur (0-Sans,1-Tout,2-Côté,3-Longueur): 1; Point ch.0-Non,1-2D,2-3D,3-Tous: 3; Points chauds auto. en 3D: yes; Trou reprend surface latérale de mur: no; Division de surface de trou courbée: no; Stylo ligne non coupée: Ouvertures - Général; Stylo de contour: Eléments 2D - Général; Type Hachure: Sans Trame; Stylo Hachure: Fond - Couleur 1; Stylo fond hachure: Fond - Couleur 1; Stylo châssis: Eléments 2D - Général; Stylo vitrage: Eléments 2D - Général; Stylo cadre: Eléments 2D - Général; Afficher arêtes de contour seulement en 3D: yes; Surface par défaut: Enduit - Blanc nature; Surface 1: •MENUIS H CADRE; Surface 2: •MENUIS H CHASSIS; Surface 3: Vitrage-Bleu; Surface de châssis: Bois - Pin granuleux horizontal; Surface vitre: Transp. - Verre clair (rapide); Surface de cadre: Bois - Pin granuleux vertical; Opération IFC (ifc_optype): 1; AC_Equantity_Fenêtre_(Mur)_18 - Largeur: 1 m; Hauteur: 1.5 m; Hauteur appui à étage actuel: 0.6 m; Niveau inférieur: 1 m; Niveau supérieur: 0 m; Largeur cadre: 0.07 m; Epaisseur cadre: 0.05 m; Largeur châssis: 0.05 m; Epaisseur vitrage: 0.02 m; Epaisseur châssis: 0.05 m; Dépass.ouverture à droite: 0 m; Dépass.ouverture supérieur: 0 m; Dépass.ouverture inférieur: 0 m; Dépass.ouverture gauche: 0 m
Fen-027 | NIVEAU HAUT ENTRÉE | 0.7 | 2.8 | Fen-027 | NIVEAU HAUT ENTRÉE | 0.Importation IFC | Fenêtre (Mur) 18 | •GYMN 16+10 (1) | 2,80x0,70 | 2,80x0,70x0,26 | 4.85 | 1.85 | 5.2976 | 0.018928 | 2.25 | 2.95 | 1.96 | 0.5096 | 0.26 | ArchiCADProperties - Nom de Zone: Salle de Sport de Combat; Numéro de Zone: 006; De Zone: Salle de Sport de Combat; De la Zone numéro: 006; AC_Pset_Fenêtre_(Mur)_18 - Contours Mur (0-Sans,1-Tout,2-Côté,3-Longueur): 1; Point ch.0-Non,1-2D,2-3D,3-Tous: 3; Points chauds auto. en 3D: yes; Trou reprend surface latérale de mur: no; Division de surface de trou courbée: no; Stylo ligne non coupée: Ouvertures - Général; Stylo de contour: Eléments 2D - Général; Type Hachure: Sans Trame; Stylo Hachure: Fond - Couleur 1; Stylo fond hachure: Fond - Couleur 1; Stylo châssis: Eléments 2D - Général; Stylo vitrage: Eléments 2D - Général; Stylo cadre: Eléments 2D - Général; Afficher arêtes de contour seulement en 3D: yes; Surface par défaut: Enduit - Blanc nature; Surface 1: •MENUIS H CADRE; Surface 2: •MENUIS H CHASSIS; Surface 3: Vitrage-Bleu; Surface de châssis: Bois - Pin granuleux horizontal; Surface vitre: Transp. - Verre clair (rapide); Surface de cadre: Bois - Pin granuleux vertical; Opération IFC (ifc_optype): 1; AC_Equantity_Fenêtre_(Mur)_18 - Largeur: 1 m; Hauteur: 1.5 m; Hauteur appui à étage actuel: 0.6 m; Niveau inférieur: 1 m; Niveau supérieur: 0 m; Largeur cadre: 0.07 m; Epaisseur cadre: 0.05 m; Largeur châssis: 0.05 m; Epaisseur vitrage: 0.02 m; Epaisseur châssis: 0.05 m; Dépass.ouverture à droite: 0 m; Dépass.ouverture supérieur: 0 m; Dépass.ouverture inférieur: 0 m; Dépass.ouverture gauche: 0 m
Fen-028 | NIVEAU HAUT ENTRÉE | 0.7 | 3 | Fen-028 | NIVEAU HAUT ENTRÉE | 0.Importation IFC | Fenêtre (Mur) 22 | •GYMN 16+10 | 3,00x0,70 | 3,00x0,70x0,26 | 4.81082 | 1.81082 | 5.6576 | 0.020048 | 2.06082 | 2.76082 | 2.1 | 0.546 | 0.26 | ArchiCADProperties - Nom de Zone: Bureau Association; Numéro de Zone: 011; De Zone: Bureau Association; De la Zone numéro: 011; AC_Pset_Fenêtre_(Mur)_22 - Contours Mur (0-Sans,1-Tout,2-Côté,3-Longueur): 1; Point ch.0-Non,1-2D,2-3D,3-Tous: 3; Points chauds auto. en 3D: yes; Trou reprend surface latérale de mur: no; Division de surface de trou courbée: no; Stylo ligne non coupée: Ouvertures - Général; Stylo de contour: Eléments 2D - Général; Type Hachure: Sans Trame; Stylo Hachure: Fond - Couleur 1; Stylo fond hachure: Fond - Couleur 1; Stylo châssis: Eléments 2D - Général; Stylo vitrage: Eléments 2D - Général; Stylo cadre: Eléments 2D - Général; Afficher arêtes de contour seulement en 3D: yes; Surface par défaut: Enduit - Blanc nature; Surface 1: •MENUIS H CADRE; Surface 2: •MENUIS H CHASSIS; Surface 3: Vitrage-Bleu; Surface de châssis: Bois - Pin granuleux horizontal; Surface vitre: Transp. - Verre clair (rapide); Surface de cadre: Bois - Pin granuleux vertical; Opération IFC (ifc_optype): 1; AC_Equantity_Fenêtre_(Mur)_22 - Largeur: 1 m; Hauteur: 1.5 m; Hauteur appui à étage actuel: 0.75 m; Niveau inférieur: 1 m; Niveau supérieur: 0 m; Largeur cadre: 0.07 m; Epaisseur cadre: 0.05 m; Largeur châssis: 0.05 m; Epaisseur vitrage: 0.02 m; Epaisseur châssis: 0.05 m; Dépass.ouverture à droite: 0 m; Dépass.ouverture supérieur: 0 m; Dépass.ouverture inférieur: 0 m; Dépass.ouverture gauche: 0 m
Fen-028 | NIVEAU HAUT ENTRÉE | 0.7 | 1.5 | Fen-028 | NIVEAU HAUT ENTRÉE | 0.Importation IFC | Fenêtre (Mur) 23 | •GYMN 16+10 | 1,50x0,70 | 1,50x0,70x0,26 | 3.45 | 0.45 | 2.9576 | 0.011648 | 0.7 | 1.4 | 1.05 | 0.273 | 0.26 | ArchiCADProperties - Nom de Zone: Bureau Association; Numéro de Zone: 011; De Zone: Bureau Association; De la Zone numéro: 011; AC_Pset_Fenêtre_(Mur)_23 - Contours Mur (0-Sans,1-Tout,2-Côté,3-Longueur): 1; Point ch.0-Non,1-2D,2-3D,3-Tous: 3; Points chauds auto. en 3D: yes; Trou reprend surface latérale de mur: no; Division de surface de trou courbée: no; Stylo ligne non coupée: Ouvertures - Général; Stylo de contour: Eléments 2D - Général; Type Hachure: Sans Trame; Stylo Hachure: Fond - Couleur 1; Stylo fond hachure: Fond - Couleur 1; Stylo châssis: Eléments 2D - Général; Stylo vitrage: Eléments 2D - Général; Stylo cadre: Eléments 2D - Général; Afficher arêtes de contour seulement en 3D: yes; Surface par défaut: Enduit - Blanc nature; Surface 1: •MENUIS H CADRE; Surface 2: •MENUIS H CHASSIS; Surface 3: Vitrage-Bleu; Surface de châssis: Bois - Pin granuleux horizontal; Surface vitre: Transp. - Verre clair (rapide); Surface de cadre: Bois - Pin granuleux vertical; Opération IFC (ifc_optype): 1; AC_Equantity_Fenêtre_(Mur)_23 - Largeur: 1 m; Hauteur: 1.5 m; Hauteur appui à étage actuel: 0.75 m; Niveau inférieur: 1 m; Niveau supérieur: 0 m; Largeur cadre: 0.07 m; Epaisseur cadre: 0.05 m; Largeur châssis: 0.05 m; Epaisseur vitrage: 0.02 m; Epaisseur châssis: 0.05 m; Dépass.ouverture à droite: 0 m; Dépass.ouverture supérieur: 0 m; Dépass.ouverture inférieur: 0 m; Dépass.ouverture gauche: 0 m
Fen-026 | NIVEAU HAUT ENTRÉE | 0.7 | 3.269 | Fen-026 | NIVEAU HAUT ENTRÉE | 0.Importation IFC | Fenêtre (Mur) 24 | •GYMN 16+10 | 3,27x0,70 | 3,27x0,70x0,26 | 4.81082 | 1.81082 | 6.1418 | 0.0215544 | 2.06082 | 2.76082 | 2.2883 | 0.594958 | 0.26 | ArchiCADProperties - Nom de Zone: Salle de Sport de Combat; Numéro de Zone: 006; De Zone: Salle de Sport de Combat; De la Zone numéro: 006; AC_Pset_Fenêtre_(Mur)_24 - Contours Mur (0-Sans,1-Tout,2-Côté,3-Longueur): 1; Point ch.0-Non,1-2D,2-3D,3-Tous: 3; Points chauds auto. en 3D: yes; Trou reprend surface latérale de mur: no; Division de surface de trou courbée: no; Stylo ligne non coupée: Ouvertures - Général; Stylo de contour: Eléments 2D - Général; Type Hachure: Sans Trame; Stylo Hachure: Fond - Couleur 1; Stylo fond hachure: Fond - Couleur 1; Stylo châssis: Eléments 2D - Général; Stylo vitrage: Eléments 2D - Général; Stylo cadre: Eléments 2D - Général; Afficher arêtes de contour seulement en 3D: yes; Surface par défaut: Enduit - Blanc nature; Surface 1: •MENUIS H CADRE; Surface 2: •MENUIS H CHASSIS; Surface 3: Vitrage-Bleu; Surface de châssis: Bois - Pin granuleux horizontal; Surface vitre: Transp. - Verre clair (rapide); Surface de cadre: Bois - Pin granuleux vertical; Opération IFC (ifc_optype): 1; AC_Equantity_Fenêtre_(Mur)_24 - Largeur: 1 m; Hauteur: 1.5 m; Hauteur appui à étage actuel: 0.75 m; Niveau inférieur: 1 m; Niveau supérieur: 0 m; Largeur cadre: 0.07 m; Epaisseur cadre: 0.05 m; Largeur châssis: 0.05 m; Epaisseur vitrage: 0.02 m; Epaisseur châssis: 0.05 m; Dépass.ouverture à droite: 0 m; Dépass.ouverture supérieur: 0 m; Dépass.ouverture inférieur: 0 m; Dépass.ouverture gauche: 0 m
Fen-026 | NIVEAU HAUT ENTRÉE | 0.7 | 3.27194 | Fen-026 | NIVEAU HAUT ENTRÉE | 0.Importation IFC | Fenêtre (Mur) 25 | •GYMN 16+10 | 3,27x0,70 | 3,27x0,70x0,26 | 4.12 | 1.12 | 6.14709 | 0.0215709 | 1.37 | 2.07 | 2.29036 | 0.595493 | 0.26 | ArchiCADProperties - Nom de Zone: Salle de Sport de Combat; Numéro de Zone: 006; De Zone: Salle de Sport de Combat; De la Zone numéro: 006; AC_Pset_Fenêtre_(Mur)_25 - Contours Mur (0-Sans,1-Tout,2-Côté,3-Longueur): 1; Point ch.0-Non,1-2D,2-3D,3-Tous: 3; Points chauds auto. en 3D: yes; Trou reprend surface latérale de mur: no; Division de surface de trou courbée: no; Stylo ligne non coupée: Ouvertures - Général; Stylo de contour: Eléments 2D - Général; Type Hachure: Sans Trame; Stylo Hachure: Fond - Couleur 1; Stylo fond hachure: Fond - Couleur 1; Stylo châssis: Eléments 2D - Général; Stylo vitrage: Eléments 2D - Général; Stylo cadre: Eléments 2D - Général; Afficher arêtes de contour seulement en 3D: yes; Surface par défaut: Enduit - Blanc nature; Surface 1: •MENUIS H CADRE; Surface 2: •MENUIS H CHASSIS; Surface 3: Vitrage-Bleu; Surface de châssis: Bois - Pin granuleux horizontal; Surface vitre: Transp. - Verre clair (rapide); Surface de cadre: Bois - Pin granuleux vertical; Opération IFC (ifc_optype): 1; AC_Equantity_Fenêtre_(Mur)_25 - Largeur: 1 m; Hauteur: 1.5 m; Hauteur appui à étage actuel: 0.75 m; Niveau inférieur: 1 m; Niveau supérieur: 0 m; Largeur cadre: 0.07 m; Epaisseur cadre: 0.05 m; Largeur châssis: 0.05 m; Epaisseur vitrage: 0.02 m; Epaisseur châssis: 0.05 m; Dépass.ouverture à droite: 0 m; Dépass.ouverture supérieur: 0 m; Dépass.ouverture inférieur: 0 m; Dépass.ouverture gauche: 0 m
Fen-026 | NIVEAU HAUT ENTRÉE | 0.7 | 3.113 | Fen-026 | NIVEAU HAUT ENTRÉE | 0.Importation IFC | Fenêtre (Mur) 26 | •GYMN 16+10 | 3,11x0,70 | 3,11x0,70x0,26 | 4.12 | 1.12 | 5.861 | 0.0206808 | 1.37 | 2.07 | 2.1791 | 0.566566 | 0.26 | ArchiCADProperties - Nom de Zone: Salle de Sport de Combat; Numéro de Zone: 006; De Zone: Salle de Sport de Combat; De la Zone numéro: 006; AC_Pset_Fenêtre_(Mur)_26 - Contours Mur (0-Sans,1-Tout,2-Côté,3-Longueur): 1; Point ch.0-Non,1-2D,2-3D,3-Tous: 3; Points chauds auto. en 3D: yes; Trou reprend surface latérale de mur: no; Division de surface de trou courbée: no; Stylo ligne non coupée: Ouvertures - Général; Stylo de contour: Eléments 2D - Général; Type Hachure: Sans Trame; Stylo Hachure: Fond - Couleur 1; Stylo fond hachure: Fond - Couleur 1; Stylo châssis: Eléments 2D - Général; Stylo vitrage: Eléments 2D - Général; Stylo cadre: Eléments 2D - Général; Afficher arêtes de contour seulement en 3D: yes; Surface par défaut: Enduit - Blanc nature; Surface 1: •MENUIS H CADRE; Surface 2: •MENUIS H CHASSIS; Surface 3: Vitrage-Bleu; Surface de châssis: Bois - Pin granuleux horizontal; Surface vitre: Transp. - Verre clair (rapide); Surface de cadre: Bois - Pin granuleux vertical; Opération IFC (ifc_optype): 1; AC_Equantity_Fenêtre_(Mur)_26 - Largeur: 1 m; Hauteur: 1.5 m; Hauteur appui à étage actuel: 0.75 m; Niveau inférieur: 1 m; Niveau supérieur: 0 m; Largeur cadre: 0.07 m; Epaisseur cadre: 0.05 m; Largeur châssis: 0.05 m; Epaisseur vitrage: 0.02 m; Epaisseur châssis: 0.05 m; Dépass.ouverture à droite: 0 m; Dépass.ouverture supérieur: 0 m; Dépass.ouverture inférieur: 0 m; Dépass.ouverture gauche: 0 m
Fen-028 | NIVEAU HAUT ENTRÉE | 1.4057 | 3.5 | Fen-028 | NIVEAU HAUT ENTRÉE | Murs Ext: Périphériques.Importation IFC | Fenêtre (Mur) 28 | •GYMN PANNEAU 1 0232896968 | 3,50x1,41 | 3,50x1,41x0,24 | 4.46 | 1.46 | 11.7798 | 0.0267999 | 2.00018e-12 | 1.4057 | 4.91996 | 1.18079 | 0.24 | AC_Pset_Fenêtre_(Mur)_28 - Contours Mur (0-Sans,1-Tout,2-Côté,3-Longueur): 1; Point ch.0-Non,1-2D,2-3D,3-Tous: 3; Points chauds auto. en 3D: yes; Trou reprend surface latérale de mur: no; Division de surface de trou courbée: no; Stylo ligne non coupée: Ouvertures - Général; Stylo de contour: Eléments 2D - Général; Type Hachure: Sans Trame; Stylo Hachure: Fond - Couleur 1; Stylo fond hachure: Fond - Couleur 1; Stylo châssis: Eléments 2D - Général; Stylo vitrage: Eléments 2D - Général; Stylo cadre: Eléments 2D - Général; Afficher arêtes de contour seulement en 3D: yes; Surface par défaut: Enduit - Blanc nature; Surface 1: •MENUIS H CADRE; Surface 2: •MENUIS H CHASSIS; Surface 3: Vitrage-Bleu; Surface de châssis: Bois - Pin granuleux horizontal; Surface vitre: Transp. - Verre clair (rapide); Surface de cadre: Bois - Pin granuleux vertical; Opération IFC (ifc_optype): 1; AC_Equantity_Fenêtre_(Mur)_28 - Largeur: 1 m; Hauteur: 1.5 m; Hauteur appui à étage actuel: 2.46 m; Niveau inférieur: 1 m; Niveau supérieur: 0 m; Largeur cadre: 0.07 m; Epaisseur cadre: 0.05 m; Largeur châssis: 0.05 m; Epaisseur vitrage: 0.02 m; Epaisseur châssis: 0.05 m; Dépass.ouverture à droite: 0 m; Dépass.ouverture supérieur: 0 m; Dépass.ouverture inférieur: 0 m; Dépass.ouverture gauche: 0 m
Fen-028 | NIVEAU HAUT ENTRÉE | 1.4057 | 3.3 | Fen-028 | NIVEAU HAUT ENTRÉE | Murs Ext: Périphériques.Importation IFC | Fenêtre (Mur) 30 | •GYMN PANNEAU 1 0232896968 | 3,30x1,41 | 3,30x1,41x0,24 | 4.46 | 1.46 | 11.1375 | 0.0256799 | 2.00018e-12 | 1.4057 | 4.63882 | 1.11332 | 0.24 | AC_Pset_Fenêtre_(Mur)_30 - Contours Mur (0-Sans,1-Tout,2-Côté,3-Longueur): 1; Point ch.0-Non,1-2D,2-3D,3-Tous: 3; Points chauds auto. en 3D: yes; Trou reprend surface latérale de mur: no; Division de surface de trou courbée: no; Stylo ligne non coupée: Ouvertures - Général; Stylo de contour: Eléments 2D - Général; Type Hachure: Sans Trame; Stylo Hachure: Fond - Couleur 1; Stylo fond hachure: Fond - Couleur 1; Stylo châssis: Eléments 2D - Général; Stylo vitrage: Eléments 2D - Général; Stylo cadre: Eléments 2D - Général; Afficher arêtes de contour seulement en 3D: yes; Surface par défaut: Enduit - Blanc nature; Surface 1: •MENUIS H CADRE; Surface 2: •MENUIS H CHASSIS; Surface 3: Vitrage-Bleu; Surface de châssis: Bois - Pin granuleux horizontal; Surface vitre: Transp. - Verre clair (rapide); Surface de cadre: Bois - Pin granuleux vertical; Opération IFC (ifc_optype): 1; AC_Equantity_Fenêtre_(Mur)_30 - Largeur: 1 m; Hauteur: 1.5 m; Hauteur appui à étage actuel: 2.46 m; Niveau inférieur: 1 m; Niveau supérieur: 0 m; Largeur cadre: 0.07 m; Epaisseur cadre: 0.05 m; Largeur châssis: 0.05 m; Epaisseur vitrage: 0.02 m; Epaisseur châssis: 0.05 m; Dépass.ouverture à droite: 0 m; Dépass.ouverture supérieur: 0 m; Dépass.ouverture inférieur: 0 m; Dépass.ouverture gauche: 0 m
Fen-028 | NIVEAU HAUT ENTRÉE | 1.4057 | 3.47574 | Fen-028 | NIVEAU HAUT ENTRÉE | Murs Ext: Périphériques.Importation IFC | Fenêtre (Mur) 31 | •GYMN PANNEAU 1 0232896968 | 3,48x1,41 | 3,48x1,41x0,24 | 4.46 | 1.46 | 11.7019 | 0.0266641 | 2.00018e-12 | 1.4057 | 4.88586 | 1.17261 | 0.24 | AC_Pset_Fenêtre_(Mur)_31 - Contours Mur (0-Sans,1-Tout,2-Côté,3-Longueur): 1; Point ch.0-Non,1-2D,2-3D,3-Tous: 3; Points chauds auto. en 3D: yes; Trou reprend surface latérale de mur: no; Division de surface de trou courbée: no; Stylo ligne non coupée: Ouvertures - Général; Stylo de contour: Eléments 2D - Général; Type Hachure: Sans Trame; Stylo Hachure: Fond - Couleur 1; Stylo fond hachure: Fond - Couleur 1; Stylo châssis: Eléments 2D - Général; Stylo vitrage: Eléments 2D - Général; Stylo cadre: Eléments 2D - Général; Afficher arêtes de contour seulement en 3D: yes; Surface par défaut: Enduit - Blanc nature; Surface 1: •MENUIS H CADRE; Surface 2: •MENUIS H CHASSIS; Surface 3: Vitrage-Bleu; Surface de châssis: Bois - Pin granuleux horizontal; Surface vitre: Transp. - Verre clair (rapide); Surface de cadre: Bois - Pin granuleux vertical; Opération IFC (ifc_optype): 1; AC_Equantity_Fenêtre_(Mur)_31 - Largeur: 1 m; Hauteur: 1.5 m; Hauteur appui à étage actuel: 2.46 m; Niveau inférieur: 1 m; Niveau supérieur: 0 m; Largeur cadre: 0.07 m; Epaisseur cadre: 0.05 m; Largeur châssis: 0.05 m; Epaisseur vitrage: 0.02 m; Epaisseur châssis: 0.05 m; Dépass.ouverture à droite: 0 m; Dépass.ouverture supérieur: 0 m; Dépass.ouverture inférieur: 0 m; Dépass.ouverture gauche: 0 m

# IfcWindow: Fen double hor coul 10 (6)
Type - OperationType: DOUBLE_PANEL_VERTICAL; ParameterTakesPrecedence: no; Sizeable: no
Type - Propriétés Doublure Fenêtre - LiningDepth: 0.05 m; LiningThickness: 0.04 m
Type - Propriétés Panneau Fenêtre - Panneau1 - PanelPosition: LEFT
Type - Propriétés Panneau Fenêtre - Panneau2 - PanelPosition: RIGHT
Material: Sans Trame
Pset_WindowCommon - ThermalTransmittance: 0; GlazingAreaFraction: 0
ArchiCADProperties - Calque: 0.Importation IFC; Type: Fenêtre; Verrouillé: no; Matériau de construction / Composite / Profil / Hachure: Menuis1; Fonction structurelle: Non défini; Position: Non défini; Classification d'élement: Type ArchiCAD; Etat de rénovation: Existant; Afficher sur filtre de rénovation: Tous les filtres appropriés; Orientation: G
AC_Pset_RenovationAndPhasing - Renovation Status: Existing
ArchiCADQuantities - Epaisseur: 0.05 m; Epaisseur de Mur: 0.26 m
Name | In | OverallHeight (m) = ArchiCADQuantities, Hauteur (m) = Hauteur ouverture côté ébrasure (m) = Hauteur ouverture côté opposé ébrasure (m) = Hauteur nominale de l'ouverture côté ébrasure (m) = Hauteur nominale de l'ouverture côté opposée ébrasure (m) | OverallWidth (m) = ArchiCADQuantities, Largeur (m) = Largeur ouverture côté ébrasure (m) = Largeur ouverture côté opposé ébrasure (m) = Largeur nominale de l'ouverture côté ébrasure (m) = Largeur nominale de l'ouverture côté opposée ébrasure (m) | ID Elément entier = ID Elément compact | Etage d'implantation | Nom de Zone = De Zone | Numéro de Zone = De la Zone numéro | Nom Elément de Bibliothèque | Structure mur | Taille L x H nominale | Taille L x H x E nominale | Altitude à Zéro du Projet (m) | Altitude à étage (m) | Superficie de surface (m2) | Volume net (m3) = Volume ouverture (m3) | Hauteur nominale seuil (m) = Hauteur seuil côté ébrasure (m) = Hauteur seuil côté opposé ébrasure (m) = Valeur Appui ou Linteau (m) | Hauteur nominale linteau (m) = Hauteur linteau côté ébrasure (m) = Hauteur linteau côté opposé ébrasure (m) | Surface ouverture côté ébrasure (m2) = Surface ouverture côté opposé ébrasure (m2) = Surface nominale de l'ouverture P/F côté ébrasure (m2) = Surface nominale de l'ouverture P/F côté opposé ébrasure (m2) = Surface nominale ouverture P/F (m2) | Volume nominal ouverture (m3)
Fen-027 | NIVEAU BAS GYMNASE | 0.6 | 3 | Fen-027 | NIVEAU BAS GYMNASE | Sanit Vest 2 | 010 | Fenêtre (Mur) 6 | •GYMN 16+10 (1) | 3,00x0,60 | 3,00x0,60x0,26 | 1.65 | 1.65 | 4.7616 | 0.02176 | 1.85 | 2.45 | 1.8 | 0.468 | AC_Pset_Fenêtre_(Mur)_6 - Contours Mur (0-Sans,1-Tout,2-Côté,3-Longueur): 1; Point ch.0-Non,1-2D,2-3D,3-Tous: 3; Points chauds auto. en 3D: yes; Trou reprend surface latérale de mur: no; Division de surface de trou courbée: no; Stylo ligne non coupée: Ouvertures - Général; Stylo de contour: Eléments 2D - Général; Type Hachure: Sans Trame; Stylo Hachure: Fond - Couleur 1; Stylo fond hachure: Fond - Couleur 1; Stylo châssis: Eléments 2D - Général; Stylo vitrage: Eléments 2D - Général; Stylo cadre: Eléments 2D - Général; Afficher arêtes de contour seulement en 3D: yes; Surface par défaut: Enduit - Blanc nature; Surface 1: •MENUIS H CADRE; Surface 2: •MENUIS H CHASSIS; Surface 3: Vitrage-Bleu; Surface de châssis: Bois - Pin granuleux horizontal; Surface vitre: Transp. - Verre clair (rapide); Surface de cadre: Bois - Pin granuleux vertical; Opération IFC (ifc_optype): 2; AC_Equantity_Fenêtre_(Mur)_6 - Largeur: 1 m; Hauteur: 1.5 m; Hauteur appui à étage actuel: 1.65 m; Niveau inférieur: 1 m; Niveau supérieur: 0 m; Largeur cadre: 0.07 m; Epaisseur cadre: 0.05 m; Largeur châssis: 0.05 m; Epaisseur vitrage: 0.02 m; Epaisseur châssis: 0.05 m; Dépass.ouverture à droite: 0 m; Dépass.ouverture supérieur: 0 m; Dépass.ouverture inférieur: 0 m; Dépass.ouverture gauche: 0 m
Fen-028 | NIVEAU BAS GYMNASE | 0.6 | 3 | Fen-028 | NIVEAU BAS GYMNASE | Sanit Vest 1 | 010 | Fenêtre (Mur) 7 | •GYMN 16+10 (1) | 3,00x0,60 | 3,00x0,60x0,26 | 1.65 | 1.65 | 4.7616 | 0.02176 | 1.85 | 2.45 | 1.8 | 0.468 | AC_Pset_Fenêtre_(Mur)_7 - Contours Mur (0-Sans,1-Tout,2-Côté,3-Longueur): 1; Point ch.0-Non,1-2D,2-3D,3-Tous: 3; Points chauds auto. en 3D: yes; Trou reprend surface latérale de mur: no; Division de surface de trou courbée: no; Stylo ligne non coupée: Ouvertures - Général; Stylo de contour: Eléments 2D - Général; Type Hachure: Sans Trame; Stylo Hachure: Fond - Couleur 1; Stylo fond hachure: Fond - Couleur 1; Stylo châssis: Eléments 2D - Général; Stylo vitrage: Eléments 2D - Général; Stylo cadre: Eléments 2D - Général; Afficher arêtes de contour seulement en 3D: yes; Surface par défaut: Enduit - Blanc nature; Surface 1: •MENUIS H CADRE; Surface 2: •MENUIS H CHASSIS; Surface 3: Vitrage-Bleu; Surface de châssis: Bois - Pin granuleux horizontal; Surface vitre: Transp. - Verre clair (rapide); Surface de cadre: Bois - Pin granuleux vertical; Opération IFC (ifc_optype): 2; AC_Equantity_Fenêtre_(Mur)_7 - Largeur: 1 m; Hauteur: 1.5 m; Hauteur appui à étage actuel: 1.65 m; Niveau inférieur: 1 m; Niveau supérieur: 0 m; Largeur cadre: 0.07 m; Epaisseur cadre: 0.05 m; Largeur châssis: 0.05 m; Epaisseur vitrage: 0.02 m; Epaisseur châssis: 0.05 m; Dépass.ouverture à droite: 0 m; Dépass.ouverture supérieur: 0 m; Dépass.ouverture inférieur: 0 m; Dépass.ouverture gauche: 0 m
Fen-026 | NIVEAU BAS GYMNASE | 0.6 | 3 | Fen-026 | NIVEAU BAS GYMNASE | Sanit Vest 3 | 010 | Fenêtre (Mur) 6 | •GYMN 16+10 (1) | 3,00x0,60 | 3,00x0,60x0,26 | 1.65 | 1.65 | 4.7616 | 0.02176 | 1.85 | 2.45 | 1.8 | 0.468 | AC_Pset_Fenêtre_(Mur)_6 - Contours Mur (0-Sans,1-Tout,2-Côté,3-Longueur): 1; Point ch.0-Non,1-2D,2-3D,3-Tous: 3; Points chauds auto. en 3D: yes; Trou reprend surface latérale de mur: no; Division de surface de trou courbée: no; Stylo ligne non coupée: Ouvertures - Général; Stylo de contour: Eléments 2D - Général; Type Hachure: Sans Trame; Stylo Hachure: Fond - Couleur 1; Stylo fond hachure: Fond - Couleur 1; Stylo châssis: Eléments 2D - Général; Stylo vitrage: Eléments 2D - Général; Stylo cadre: Eléments 2D - Général; Afficher arêtes de contour seulement en 3D: yes; Surface par défaut: Enduit - Blanc nature; Surface 1: •MENUIS H CADRE; Surface 2: •MENUIS H CHASSIS; Surface 3: Vitrage-Bleu; Surface de châssis: Bois - Pin granuleux horizontal; Surface vitre: Transp. - Verre clair (rapide); Surface de cadre: Bois - Pin granuleux vertical; Opération IFC (ifc_optype): 2; AC_Equantity_Fenêtre_(Mur)_6 - Largeur: 1 m; Hauteur: 1.5 m; Hauteur appui à étage actuel: 1.65 m; Niveau inférieur: 1 m; Niveau supérieur: 0 m; Largeur cadre: 0.07 m; Epaisseur cadre: 0.05 m; Largeur châssis: 0.05 m; Epaisseur vitrage: 0.02 m; Epaisseur châssis: 0.05 m; Dépass.ouverture à droite: 0 m; Dépass.ouverture supérieur: 0 m; Dépass.ouverture inférieur: 0 m; Dépass.ouverture gauche: 0 m
Fen-026 | NIVEAU BAS GYMNASE | 0.6 | 3 | Fen-026 | NIVEAU BAS GYMNASE | Sanit Vest 4 | 010 | Fenêtre (Mur) 7 | •GYMN 16+10 (1) | 3,00x0,60 | 3,00x0,60x0,26 | 1.65 | 1.65 | 4.7616 | 0.02176 | 1.85 | 2.45 | 1.8 | 0.468 | AC_Pset_Fenêtre_(Mur)_7 - Contours Mur (0-Sans,1-Tout,2-Côté,3-Longueur): 1; Point ch.0-Non,1-2D,2-3D,3-Tous: 3; Points chauds auto. en 3D: yes; Trou reprend surface latérale de mur: no; Division de surface de trou courbée: no; Stylo ligne non coupée: Ouvertures - Général; Stylo de contour: Eléments 2D - Général; Type Hachure: Sans Trame; Stylo Hachure: Fond - Couleur 1; Stylo fond hachure: Fond - Couleur 1; Stylo châssis: Eléments 2D - Général; Stylo vitrage: Eléments 2D - Général; Stylo cadre: Eléments 2D - Général; Afficher arêtes de contour seulement en 3D: yes; Surface par défaut: Enduit - Blanc nature; Surface 1: •MENUIS H CADRE; Surface 2: •MENUIS H CHASSIS; Surface 3: Vitrage-Bleu; Surface de châssis: Bois - Pin granuleux horizontal; Surface vitre: Transp. - Verre clair (rapide); Surface de cadre: Bois - Pin granuleux vertical; Opération IFC (ifc_optype): 2; AC_Equantity_Fenêtre_(Mur)_7 - Largeur: 1 m; Hauteur: 1.5 m; Hauteur appui à étage actuel: 1.65 m; Niveau inférieur: 1 m; Niveau supérieur: 0 m; Largeur cadre: 0.07 m; Epaisseur cadre: 0.05 m; Largeur châssis: 0.05 m; Epaisseur vitrage: 0.02 m; Epaisseur châssis: 0.05 m; Dépass.ouverture à droite: 0 m; Dépass.ouverture supérieur: 0 m; Dépass.ouverture inférieur: 0 m; Dépass.ouverture gauche: 0 m
Fen-028 | NIVEAU BAS GYMNASE | 0.6 | 3 | Fen-028 | NIVEAU BAS GYMNASE |  |  | Fenêtre (Mur) 7 | •GYMN 16+10 (1) | 3,00x0,60 | 3,00x0,60x0,26 | 1.65 | 1.65 | 4.7616 | 0.02176 | 1.85 | 2.45 | 1.8 | 0.468 | AC_Pset_Fenêtre_(Mur)_7 - Contours Mur (0-Sans,1-Tout,2-Côté,3-Longueur): 1; Point ch.0-Non,1-2D,2-3D,3-Tous: 3; Points chauds auto. en 3D: yes; Trou reprend surface latérale de mur: no; Division de surface de trou courbée: no; Stylo ligne non coupée: Ouvertures - Général; Stylo de contour: Eléments 2D - Général; Type Hachure: Sans Trame; Stylo Hachure: Fond - Couleur 1; Stylo fond hachure: Fond - Couleur 1; Stylo châssis: Eléments 2D - Général; Stylo vitrage: Eléments 2D - Général; Stylo cadre: Eléments 2D - Général; Afficher arêtes de contour seulement en 3D: yes; Surface par défaut: Enduit - Blanc nature; Surface 1: •MENUIS H CADRE; Surface 2: •MENUIS H CHASSIS; Surface 3: Vitrage-Bleu; Surface de châssis: Bois - Pin granuleux horizontal; Surface vitre: Transp. - Verre clair (rapide); Surface de cadre: Bois - Pin granuleux vertical; Opération IFC (ifc_optype): 2; AC_Equantity_Fenêtre_(Mur)_7 - Largeur: 1 m; Hauteur: 1.5 m; Hauteur appui à étage actuel: 1.65 m; Niveau inférieur: 1 m; Niveau supérieur: 0 m; Largeur cadre: 0.07 m; Epaisseur cadre: 0.05 m; Largeur châssis: 0.05 m; Epaisseur vitrage: 0.02 m; Epaisseur châssis: 0.05 m; Dépass.ouverture à droite: 0 m; Dépass.ouverture supérieur: 0 m; Dépass.ouverture inférieur: 0 m; Dépass.ouverture gauche: 0 m
Fen-026 | NIVEAU HAUT ENTRÉE | 2.51082 | 3.28 | Fen-026 | NIVEAU HAUT ENTRÉE | Salle de Sport de Combat | 006 | Fenêtre (Mur) 27 | •GYMN 16+10 | 3,28x2,51 | 3,28x2,51x0,26 | 3 | 0 | 18.6338 | 0.0387266 | 0.25 | 2.76082 | 8.2355 | 2.14123 | AC_Pset_Fenêtre_(Mur)_27 - Contours Mur (0-Sans,1-Tout,2-Côté,3-Longueur): 1; Point ch.0-Non,1-2D,2-3D,3-Tous: 3; Points chauds auto. en 3D: yes; Trou reprend surface latérale de mur: no; Division de surface de trou courbée: no; Stylo ligne non coupée: Ouvertures - Général; Stylo de contour: Eléments 2D - Général; Type Hachure: Sans Trame; Stylo Hachure: Fond - Couleur 1; Stylo fond hachure: Fond - Couleur 1; Stylo châssis: Eléments 2D - Général; Stylo vitrage: Eléments 2D - Général; Stylo cadre: Eléments 2D - Général; Afficher arêtes de contour seulement en 3D: yes; Surface par défaut: Enduit - Blanc nature; Surface 1: •MENUIS H CADRE; Surface 2: •MENUIS H CHASSIS; Surface 3: Vitrage-Bleu; Surface de châssis: Bois - Pin granuleux horizontal; Surface vitre: Transp. - Verre clair (rapide); Surface de cadre: Bois - Pin granuleux vertical; Opération IFC (ifc_optype): 2; AC_Equantity_Fenêtre_(Mur)_27 - Largeur: 1 m; Hauteur: 1.5 m; Hauteur appui à étage actuel: 0.75 m; Niveau inférieur: 1 m; Niveau supérieur: 0 m; Largeur cadre: 0.07 m; Epaisseur cadre: 0.05 m; Largeur châssis: 0.05 m; Epaisseur vitrage: 0.02 m; Epaisseur châssis: 0.05 m; Dépass.ouverture à droite: 0 m; Dépass.ouverture supérieur: 0 m; Dépass.ouverture inférieur: 0 m; Dépass.ouverture gauche: 0 m

# IfcWindow: Fen fixe vitrée 10, Fen-027
In: NIVEAU BAS GYMNASE
Type - OperationType: SINGLE_PANEL; ParameterTakesPrecedence: no; Sizeable: no
Type - Propriétés Doublure Fenêtre - LiningDepth: 0.04 m; LiningThickness: 0.04 m
Type - Propriétés Panneau Fenêtre - Panneau1 - PanelPosition: MIDDLE; FrameDepth: 0.05 m; FrameThickness: 0.05 m
OverallHeight: 2.97421 m; OverallWidth: 0.607011 m; Material: Sans Trame
Pset_WindowCommon - ThermalTransmittance: 0; GlazingAreaFraction: 0
Pset_ManufacturerOccurrence - SerialNumber: Sans
ArchiCADProperties - ID Elément entier: Fen-027; ID Elément compact: Fen-027; Etage d'implantation: NIVEAU BAS GYMNASE; Calque: Murs Ext: Périphériques.Importation IFC; Type: Fenêtre; Verrouillé: no; Nom Elément de Bibliothèque: Fenêtre (Mur) 15; Matériau de construction / Composite / Profil / Hachure: Menuis1; Fonction structurelle: Non défini; Position: Non défini; Classification d'élement: Type ArchiCAD; Etat de rénovation: Existant; Afficher sur filtre de rénovation: Tous les filtres appropriés; Orientation: G; Structure mur: •GYMN PANNEAU 1 0232896968; Taille L x H nominale: 0,61x2,97; Taille L x H x E nominale: 0,61x2,97x0,24
AC_Pset_Fenêtre_(Mur)_15 - Contours Mur (0-Sans,1-Tout,2-Côté,3-Longueur): 1; Point ch.0-Non,1-2D,2-3D,3-Tous: 3; Points chauds auto. en 3D: yes; Trou reprend surface latérale de mur: no; Division de surface de trou courbée: no; Stylo ligne non coupée: Ouvertures - Général; Stylo de contour: Eléments 2D - Général; Type Hachure: Sans Trame; Stylo Hachure: Fond - Couleur 1; Stylo fond hachure: Fond - Couleur 1; Stylo châssis: Eléments 2D - Général; Stylo vitrage: Eléments 2D - Général; Stylo cadre: Eléments 2D - Général; Afficher arêtes de contour seulement en 3D: yes; Surface par défaut: Enduit - Blanc nature; Surface 1: •MENUIS H CADRE; Surface 2: Vitrage-Bleu; Surface de châssis: Bois - Pin granuleux horizontal; Surface vitre: Transp. - Verre clair (rapide); Surface de cadre: Bois - Pin granuleux vertical; Opération IFC (ifc_optype): 1
AC_Pset_RenovationAndPhasing - Renovation Status: Existing
ArchiCADQuantities - Altitude à Zéro du Projet: 3.95 m; Altitude à étage: 0.95 m; Hauteur: 2.97421 m; Superficie de surface: 4.18374 m2; Volume net: 0.0112039 m3; Largeur: 0.607011 m; Epaisseur: 0.05 m; Hauteur nominale seuil: 1.15 m; Hauteur seuil côté ébrasure: 1.15 m; Hauteur seuil côté opposé ébrasure: 1.15 m; Hauteur nominale linteau: 4.12421 m; Hauteur linteau côté ébrasure: 4.12421 m; Hauteur linteau côté opposé ébrasure: 4.12421 m; Largeur ouverture côté ébrasure: 0.60701 m; Largeur ouverture côté opposé ébrasure: 0.60701 m; Hauteur ouverture côté ébrasure: 2.97421 m; Hauteur ouverture côté opposé ébrasure: 2.97421 m; Surface ouverture côté ébrasure: 1.80537 m2; Surface ouverture côté opposé ébrasure: 1.80537 m2; Largeur nominale de l'ouverture côté ébrasure: 0.607011 m; Largeur nominale de l'ouverture côté opposée ébrasure: 0.607011 m; Hauteur nominale de l'ouverture côté ébrasure: 2.97421 m; Hauteur nominale de l'ouverture côté opposée ébrasure: 2.97421 m; Surface nominale de l'ouverture P/F côté ébrasure: 1.80537 m2; Surface nominale de l'ouverture P/F côté opposé ébrasure: 1.80537 m2; Volume ouverture: 0.0112039 m3; Surface nominale ouverture P/F: 1.80537 m2; Volume nominal ouverture: 0.43329 m3; Valeur Appui ou Linteau: 1.15 m; Epaisseur de Mur: 0.24 m
AC_Equantity_Fenêtre_(Mur)_15 - Largeur: 1 m; Hauteur: 1.5 m; Hauteur appui à étage actuel: 3.8 m; Niveau inférieur: 1 m; Niveau supérieur: 0 m; Largeur cadre: 0.07 m; Epaisseur cadre: 0.05 m; Largeur châssis: 0.05 m; Epaisseur vitrage: 0.02 m; Epaisseur châssis: 0.05 m; Dépass.ouverture à droite: 0 m; Dépass.ouverture supérieur: 0 m; Dépass.ouverture inférieur: 0 m; Dépass.ouverture gauche: 0 m

# IfcWindow: Fenêtre de toit pivot 10, Obj.-014
In: PLAN DE MASSE-TOITURE
Type - ParameterTakesPrecedence: no; Sizeable: no
Pset_WindowCommon - ThermalTransmittance: 0; GlazingAreaFraction: 0
ArchiCADProperties - ID Elément entier: Obj.-014; ID Elément compact: Obj.-014; Etage d'implantation: PLAN DE MASSE-TOITURE; Calque: EPS 3D.Importation IFC; Type: Objet; Verrouillé: no; Nom Elément de Bibliothèque: IFC Fenêtre indépendante 1; Matériau de construction / Composite / Profil / Hachure: IFC Hachure; Fonction structurelle: Non défini; Position: Non défini; Classification d'élement: Type ArchiCAD; Etat de rénovation: Existant; Afficher sur filtre de rénovation: Tous les filtres appropriés; Angle de rotation: 0 deg; Surface: Enduit - Blanc nature
AC_Pset_IFC_Fenêtre_indépendante_1 - Type Hachure: Sans Trame; Stylo Hachure: Fond - Couleur 1; Stylo fond hachure: Fond - Couleur 1; Stylo de contour: Eléments 2D - Général; Surface par défaut: Enduit - Blanc nature; Surface 1: Bois-Pin horizontal; Surface 2: Métal-Zinc; Surface 3: Vitrage-Clair; Surface 4: Peinture-01; Afficher arêtes de contour seulement en 3D: yes
AC_Pset_RenovationAndPhasing - Renovation Status: Existing
ArchiCADQuantities - Altitude à Zéro du Projet: 6.38 m; Altitude à étage: 0.18 m; Superficie de surface: 7.65541 m2; Volume net: 0.0586595 m3; Superficie: 1.508 m2; Hauteur (Taille en Z): 0.327 m; Longueur (A): 1.45 m; Volume: 0.0586595 m3; Largeur (B): 1.04 m

# IfcWindow: Fenêtre ventilation 10, Fen-030
In: NIVEAU BAS GYMNASE
Type - OperationType: USERDEFINED; ParameterTakesPrecedence: no; Sizeable: no
OverallHeight: 2.06408 m; OverallWidth: 0.615447 m; Material: Sans Trame
Pset_WindowCommon - ThermalTransmittance: 0; GlazingAreaFraction: 0
Pset_ManufacturerTypeInformation - ProductionYear: 1970
ArchiCADProperties - ID Elément entier: Fen-030; ID Elément compact: Fen-030; Etage d'implantation: NIVEAU BAS GYMNASE; Nom de Zone: Chaufferie; Numéro de Zone: 010; Calque: Murs Ext: Périphériques.Importation IFC; Type: Fenêtre; Verrouillé: no; Nom Elément de Bibliothèque: Fenêtre (Mur) 9; Matériau de construction / Composite / Profil / Hachure: Menuis1; Fonction structurelle: Non défini; Position: Non défini; Classification d'élement: Type ArchiCAD; Etat de rénovation: Existant; Afficher sur filtre de rénovation: Tous les filtres appropriés; De Zone: Chaufferie; Orientation: G; De la Zone numéro: 010; Structure mur: Hachure solide* 1842511997; Taille L x H nominale: 0,62x2,06; Taille L x H x E nominale: 0,62x2,06x0,16
AC_Pset_Fenêtre_(Mur)_9 - Contours Mur (0-Sans,1-Tout,2-Côté,3-Longueur): 1; Point ch.0-Non,1-2D,2-3D,3-Tous: 3; Points chauds auto. en 3D: yes; Trou reprend surface latérale de mur: no; Division de surface de trou courbée: no; Stylo ligne non coupée: Ouvertures - Général; Stylo de contour: Eléments 2D - Général; Type Hachure: Sans Trame; Stylo Hachure: Fond - Couleur 1; Stylo fond hachure: Fond - Couleur 1; Stylo châssis: Eléments 2D - Général; Stylo vitrage: Eléments 2D - Général; Stylo cadre: Eléments 2D - Général; Afficher arêtes de contour seulement en 3D: yes; Surface par défaut: Enduit - Blanc nature; Surface 1: Métal-Inox; Surface de châssis: Bois - Pin granuleux horizontal; Surface vitre: Transp. - Verre clair (rapide); Surface de cadre: Bois - Pin granuleux vertical; Opération IFC (ifc_optype): 0
AC_Pset_RenovationAndPhasing - Renovation Status: Existing
ArchiCADQuantities - Altitude à Zéro du Projet: 0.0359229 m; Altitude à étage: 0.0359229 m; Hauteur: 2.06408 m; Superficie de surface: 5.26871 m2; Volume net: 0.0764144 m3; Largeur: 0.615447 m; Epaisseur: 0.05 m; Hauteur nominale seuil: 0.0359229 m; Hauteur seuil côté ébrasure: 0.0359229 m; Hauteur seuil côté opposé ébrasure: 0.0359229 m; Hauteur nominale linteau: 2.1 m; Hauteur linteau côté ébrasure: 2.1 m; Hauteur linteau côté opposé ébrasure: 2.1 m; Largeur ouverture côté ébrasure: 0.615446 m; Largeur ouverture côté opposé ébrasure: 0.615446 m; Hauteur ouverture côté ébrasure: 2.06408 m; Hauteur ouverture côté opposé ébrasure: 2.06408 m; Surface ouverture côté ébrasure: 1.27033 m2; Surface ouverture côté opposé ébrasure: 1.27033 m2; Largeur nominale de l'ouverture côté ébrasure: 0.615447 m; Largeur nominale de l'ouverture côté opposée ébrasure: 0.615447 m; Hauteur nominale de l'ouverture côté ébrasure: 2.06408 m; Hauteur nominale de l'ouverture côté opposée ébrasure: 2.06408 m; Surface nominale de l'ouverture P/F côté ébrasure: 1.27033 m2; Surface nominale de l'ouverture P/F côté opposé ébrasure: 1.27033 m2; Volume ouverture: 0.0764144 m3; Surface nominale ouverture P/F: 1.27033 m2; Volume nominal ouverture: 0.203253 m3; Valeur Appui ou Linteau: 0.0359229 m; Epaisseur de Mur: 0.16 m
AC_Equantity_Fenêtre_(Mur)_9 - Largeur: 1 m; Hauteur: 1.5 m; Hauteur appui à étage actuel: 1 m; Niveau inférieur: 1 m; Niveau supérieur: 0 m; Largeur cadre: 0.07 m; Epaisseur cadre: 0.05 m; Largeur châssis: 0.05 m; Epaisseur vitrage: 0.02 m; Epaisseur châssis: 0.05 m; Dépass.ouverture à droite: 0 m; Dépass.ouverture supérieur: 0 m; Dépass.ouverture inférieur: 0 m; Dépass.ouverture gauche: 0 m
